VERSION 5.8 ;
BUSBITCHARS "[]" ;
DIVIDERCHAR "/" ;
UNITS
    DATABASE MICRONS 1000 ;
END UNITS

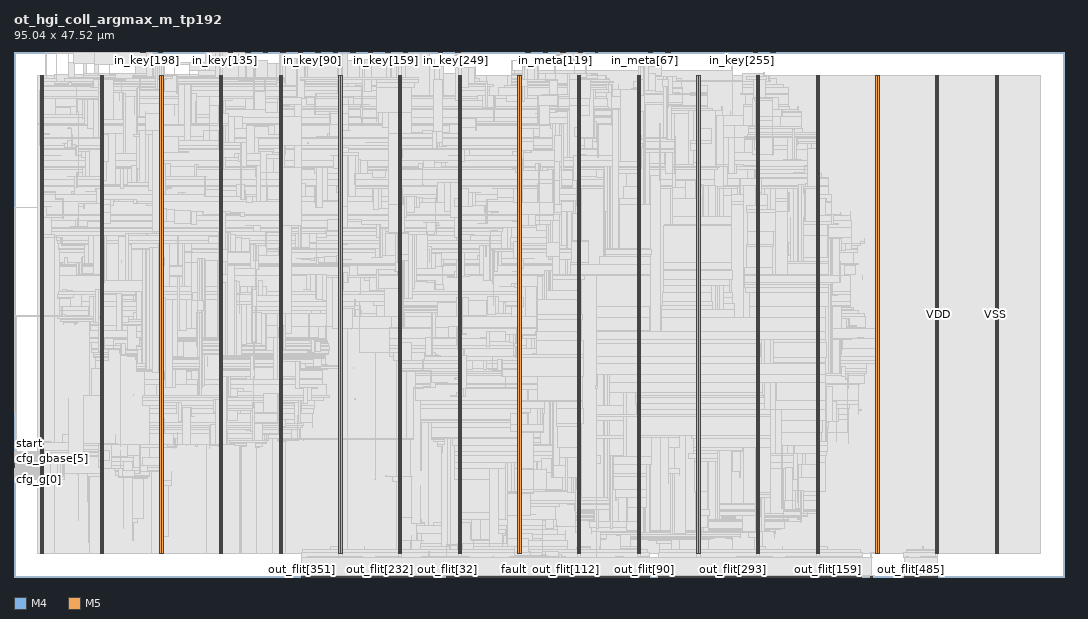
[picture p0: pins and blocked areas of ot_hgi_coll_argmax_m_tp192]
MACRO ot_hgi_coll_argmax_m_tp192
  FOREIGN ot_hgi_coll_argmax_m_tp192 0 0 ;
  CLASS BLOCK ;
  SIZE 95.04 BY 47.52 ;
  PIN cfg_g[0]
    DIRECTION INPUT ;
    USE SIGNAL ;
    PORT
      LAYER M4 ;
        RECT  0 8.784 0.084 8.808 ;
    END
  END cfg_g[0]
  PIN cfg_g[1]
    DIRECTION INPUT ;
    USE SIGNAL ;
    PORT
      LAYER M4 ;
        RECT  0 8.88 0.084 8.904 ;
    END
  END cfg_g[1]
  PIN cfg_g[2]
    DIRECTION INPUT ;
    USE SIGNAL ;
    PORT
      LAYER M4 ;
        RECT  0 8.976 0.084 9 ;
    END
  END cfg_g[2]
  PIN cfg_g[3]
    DIRECTION INPUT ;
    USE SIGNAL ;
    PORT
      LAYER M4 ;
        RECT  0 9.072 0.084 9.096 ;
    END
  END cfg_g[3]
  PIN cfg_g[4]
    DIRECTION INPUT ;
    USE SIGNAL ;
    PORT
      LAYER M4 ;
        RECT  0 9.168 0.084 9.192 ;
    END
  END cfg_g[4]
  PIN cfg_g[5]
    DIRECTION INPUT ;
    USE SIGNAL ;
    PORT
      LAYER M4 ;
        RECT  0 9.264 0.084 9.288 ;
    END
  END cfg_g[5]
  PIN cfg_g[6]
    DIRECTION INPUT ;
    USE SIGNAL ;
    PORT
      LAYER M4 ;
        RECT  0 9.36 0.084 9.384 ;
    END
  END cfg_g[6]
  PIN cfg_g[7]
    DIRECTION INPUT ;
    USE SIGNAL ;
    PORT
      LAYER M4 ;
        RECT  0 9.456 0.084 9.48 ;
    END
  END cfg_g[7]
  PIN cfg_gbase[0]
    DIRECTION INPUT ;
    USE SIGNAL ;
    PORT
      LAYER M4 ;
        RECT  0 9.552 0.084 9.576 ;
    END
  END cfg_gbase[0]
  PIN cfg_gbase[1]
    DIRECTION INPUT ;
    USE SIGNAL ;
    PORT
      LAYER M4 ;
        RECT  0 9.648 0.084 9.672 ;
    END
  END cfg_gbase[1]
  PIN cfg_gbase[2]
    DIRECTION INPUT ;
    USE SIGNAL ;
    PORT
      LAYER M4 ;
        RECT  0 9.744 0.084 9.768 ;
    END
  END cfg_gbase[2]
  PIN cfg_gbase[3]
    DIRECTION INPUT ;
    USE SIGNAL ;
    PORT
      LAYER M4 ;
        RECT  0 9.84 0.084 9.864 ;
    END
  END cfg_gbase[3]
  PIN cfg_gbase[4]
    DIRECTION INPUT ;
    USE SIGNAL ;
    PORT
      LAYER M4 ;
        RECT  0 9.936 0.084 9.96 ;
    END
  END cfg_gbase[4]
  PIN cfg_gbase[5]
    DIRECTION INPUT ;
    USE SIGNAL ;
    PORT
      LAYER M4 ;
        RECT  0 10.032 0.084 10.056 ;
    END
  END cfg_gbase[5]
  PIN cfg_gbase[6]
    DIRECTION INPUT ;
    USE SIGNAL ;
    PORT
      LAYER M4 ;
        RECT  0 10.128 0.084 10.152 ;
    END
  END cfg_gbase[6]
  PIN cfg_gbase[7]
    DIRECTION INPUT ;
    USE SIGNAL ;
    PORT
      LAYER M4 ;
        RECT  0 10.224 0.084 10.248 ;
    END
  END cfg_gbase[7]
  PIN cfg_rank[0]
    DIRECTION INPUT ;
    USE SIGNAL ;
    PORT
      LAYER M4 ;
        RECT  0 10.32 0.084 10.344 ;
    END
  END cfg_rank[0]
  PIN cfg_rank[1]
    DIRECTION INPUT ;
    USE SIGNAL ;
    PORT
      LAYER M4 ;
        RECT  0 10.416 0.084 10.44 ;
    END
  END cfg_rank[1]
  PIN cfg_rank[2]
    DIRECTION INPUT ;
    USE SIGNAL ;
    PORT
      LAYER M4 ;
        RECT  0 10.512 0.084 10.536 ;
    END
  END cfg_rank[2]
  PIN cfg_rank[3]
    DIRECTION INPUT ;
    USE SIGNAL ;
    PORT
      LAYER M4 ;
        RECT  0 10.608 0.084 10.632 ;
    END
  END cfg_rank[3]
  PIN cfg_rank[4]
    DIRECTION INPUT ;
    USE SIGNAL ;
    PORT
      LAYER M4 ;
        RECT  0 10.704 0.084 10.728 ;
    END
  END cfg_rank[4]
  PIN cfg_rank[5]
    DIRECTION INPUT ;
    USE SIGNAL ;
    PORT
      LAYER M4 ;
        RECT  0 10.8 0.084 10.824 ;
    END
  END cfg_rank[5]
  PIN cfg_rank[6]
    DIRECTION INPUT ;
    USE SIGNAL ;
    PORT
      LAYER M4 ;
        RECT  0 10.896 0.084 10.92 ;
    END
  END cfg_rank[6]
  PIN cfg_rank[7]
    DIRECTION INPUT ;
    USE SIGNAL ;
    PORT
      LAYER M4 ;
        RECT  0 10.992 0.084 11.016 ;
    END
  END cfg_rank[7]
  PIN clk
    DIRECTION INPUT ;
    USE SIGNAL ;
    PORT
      LAYER M4 ;
        RECT  0 11.088 0.084 11.112 ;
    END
  END clk
  PIN fault
    DIRECTION OUTPUT ;
    USE SIGNAL ;
    PORT
      LAYER M5 ;
        RECT  45.264 0 45.288 0.084 ;
    END
  END fault
  PIN flush_slot
    DIRECTION INPUT ;
    USE SIGNAL ;
    PORT
      LAYER M5 ;
        RECT  21.36 47.436 21.384 47.52 ;
    END
  END flush_slot
  PIN in_key[0]
    DIRECTION INPUT ;
    USE SIGNAL ;
    PORT
      LAYER M5 ;
        RECT  21.456 47.436 21.48 47.52 ;
    END
  END in_key[0]
  PIN in_key[100]
    DIRECTION INPUT ;
    USE SIGNAL ;
    PORT
      LAYER M5 ;
        RECT  27.984 47.436 28.008 47.52 ;
    END
  END in_key[100]
  PIN in_key[101]
    DIRECTION INPUT ;
    USE SIGNAL ;
    PORT
      LAYER M5 ;
        RECT  28.08 47.436 28.104 47.52 ;
    END
  END in_key[101]
  PIN in_key[102]
    DIRECTION INPUT ;
    USE SIGNAL ;
    PORT
      LAYER M5 ;
        RECT  28.176 47.436 28.2 47.52 ;
    END
  END in_key[102]
  PIN in_key[103]
    DIRECTION INPUT ;
    USE SIGNAL ;
    PORT
      LAYER M5 ;
        RECT  28.272 47.436 28.296 47.52 ;
    END
  END in_key[103]
  PIN in_key[104]
    DIRECTION INPUT ;
    USE SIGNAL ;
    PORT
      LAYER M5 ;
        RECT  28.368 47.436 28.392 47.52 ;
    END
  END in_key[104]
  PIN in_key[105]
    DIRECTION INPUT ;
    USE SIGNAL ;
    PORT
      LAYER M5 ;
        RECT  28.464 47.436 28.488 47.52 ;
    END
  END in_key[105]
  PIN in_key[106]
    DIRECTION INPUT ;
    USE SIGNAL ;
    PORT
      LAYER M5 ;
        RECT  28.56 47.436 28.584 47.52 ;
    END
  END in_key[106]
  PIN in_key[107]
    DIRECTION INPUT ;
    USE SIGNAL ;
    PORT
      LAYER M5 ;
        RECT  28.656 47.436 28.68 47.52 ;
    END
  END in_key[107]
  PIN in_key[108]
    DIRECTION INPUT ;
    USE SIGNAL ;
    PORT
      LAYER M5 ;
        RECT  28.752 47.436 28.776 47.52 ;
    END
  END in_key[108]
  PIN in_key[109]
    DIRECTION INPUT ;
    USE SIGNAL ;
    PORT
      LAYER M5 ;
        RECT  28.848 47.436 28.872 47.52 ;
    END
  END in_key[109]
  PIN in_key[10]
    DIRECTION INPUT ;
    USE SIGNAL ;
    PORT
      LAYER M5 ;
        RECT  22.416 47.436 22.44 47.52 ;
    END
  END in_key[10]
  PIN in_key[110]
    DIRECTION INPUT ;
    USE SIGNAL ;
    PORT
      LAYER M5 ;
        RECT  28.944 47.436 28.968 47.52 ;
    END
  END in_key[110]
  PIN in_key[111]
    DIRECTION INPUT ;
    USE SIGNAL ;
    PORT
      LAYER M5 ;
        RECT  29.04 47.436 29.064 47.52 ;
    END
  END in_key[111]
  PIN in_key[112]
    DIRECTION INPUT ;
    USE SIGNAL ;
    PORT
      LAYER M5 ;
        RECT  29.136 47.436 29.16 47.52 ;
    END
  END in_key[112]
  PIN in_key[113]
    DIRECTION INPUT ;
    USE SIGNAL ;
    PORT
      LAYER M5 ;
        RECT  29.232 47.436 29.256 47.52 ;
    END
  END in_key[113]
  PIN in_key[114]
    DIRECTION INPUT ;
    USE SIGNAL ;
    PORT
      LAYER M5 ;
        RECT  29.328 47.436 29.352 47.52 ;
    END
  END in_key[114]
  PIN in_key[115]
    DIRECTION INPUT ;
    USE SIGNAL ;
    PORT
      LAYER M5 ;
        RECT  29.424 47.436 29.448 47.52 ;
    END
  END in_key[115]
  PIN in_key[116]
    DIRECTION INPUT ;
    USE SIGNAL ;
    PORT
      LAYER M5 ;
        RECT  29.52 47.436 29.544 47.52 ;
    END
  END in_key[116]
  PIN in_key[117]
    DIRECTION INPUT ;
    USE SIGNAL ;
    PORT
      LAYER M5 ;
        RECT  29.616 47.436 29.64 47.52 ;
    END
  END in_key[117]
  PIN in_key[118]
    DIRECTION INPUT ;
    USE SIGNAL ;
    PORT
      LAYER M5 ;
        RECT  29.712 47.436 29.736 47.52 ;
    END
  END in_key[118]
  PIN in_key[119]
    DIRECTION INPUT ;
    USE SIGNAL ;
    PORT
      LAYER M5 ;
        RECT  29.808 47.436 29.832 47.52 ;
    END
  END in_key[119]
  PIN in_key[11]
    DIRECTION INPUT ;
    USE SIGNAL ;
    PORT
      LAYER M5 ;
        RECT  22.512 47.436 22.536 47.52 ;
    END
  END in_key[11]
  PIN in_key[120]
    DIRECTION INPUT ;
    USE SIGNAL ;
    PORT
      LAYER M5 ;
        RECT  29.904 47.436 29.928 47.52 ;
    END
  END in_key[120]
  PIN in_key[121]
    DIRECTION INPUT ;
    USE SIGNAL ;
    PORT
      LAYER M5 ;
        RECT  30 47.436 30.024 47.52 ;
    END
  END in_key[121]
  PIN in_key[122]
    DIRECTION INPUT ;
    USE SIGNAL ;
    PORT
      LAYER M5 ;
        RECT  30.096 47.436 30.12 47.52 ;
    END
  END in_key[122]
  PIN in_key[123]
    DIRECTION INPUT ;
    USE SIGNAL ;
    PORT
      LAYER M5 ;
        RECT  30.192 47.436 30.216 47.52 ;
    END
  END in_key[123]
  PIN in_key[124]
    DIRECTION INPUT ;
    USE SIGNAL ;
    PORT
      LAYER M5 ;
        RECT  30.288 47.436 30.312 47.52 ;
    END
  END in_key[124]
  PIN in_key[125]
    DIRECTION INPUT ;
    USE SIGNAL ;
    PORT
      LAYER M5 ;
        RECT  30.384 47.436 30.408 47.52 ;
    END
  END in_key[125]
  PIN in_key[126]
    DIRECTION INPUT ;
    USE SIGNAL ;
    PORT
      LAYER M5 ;
        RECT  30.48 47.436 30.504 47.52 ;
    END
  END in_key[126]
  PIN in_key[127]
    DIRECTION INPUT ;
    USE SIGNAL ;
    PORT
      LAYER M5 ;
        RECT  18.288 47.436 18.312 47.52 ;
    END
  END in_key[127]
  PIN in_key[128]
    DIRECTION INPUT ;
    USE SIGNAL ;
    PORT
      LAYER M5 ;
        RECT  18.384 47.436 18.408 47.52 ;
    END
  END in_key[128]
  PIN in_key[129]
    DIRECTION INPUT ;
    USE SIGNAL ;
    PORT
      LAYER M5 ;
        RECT  18.48 47.436 18.504 47.52 ;
    END
  END in_key[129]
  PIN in_key[12]
    DIRECTION INPUT ;
    USE SIGNAL ;
    PORT
      LAYER M5 ;
        RECT  22.608 47.436 22.632 47.52 ;
    END
  END in_key[12]
  PIN in_key[130]
    DIRECTION INPUT ;
    USE SIGNAL ;
    PORT
      LAYER M5 ;
        RECT  18.576 47.436 18.6 47.52 ;
    END
  END in_key[130]
  PIN in_key[131]
    DIRECTION INPUT ;
    USE SIGNAL ;
    PORT
      LAYER M5 ;
        RECT  18.672 47.436 18.696 47.52 ;
    END
  END in_key[131]
  PIN in_key[132]
    DIRECTION INPUT ;
    USE SIGNAL ;
    PORT
      LAYER M5 ;
        RECT  18.768 47.436 18.792 47.52 ;
    END
  END in_key[132]
  PIN in_key[133]
    DIRECTION INPUT ;
    USE SIGNAL ;
    PORT
      LAYER M5 ;
        RECT  18.864 47.436 18.888 47.52 ;
    END
  END in_key[133]
  PIN in_key[134]
    DIRECTION INPUT ;
    USE SIGNAL ;
    PORT
      LAYER M5 ;
        RECT  18.96 47.436 18.984 47.52 ;
    END
  END in_key[134]
  PIN in_key[135]
    DIRECTION INPUT ;
    USE SIGNAL ;
    PORT
      LAYER M5 ;
        RECT  19.056 47.436 19.08 47.52 ;
    END
  END in_key[135]
  PIN in_key[136]
    DIRECTION INPUT ;
    USE SIGNAL ;
    PORT
      LAYER M5 ;
        RECT  19.152 47.436 19.176 47.52 ;
    END
  END in_key[136]
  PIN in_key[137]
    DIRECTION INPUT ;
    USE SIGNAL ;
    PORT
      LAYER M5 ;
        RECT  19.248 47.436 19.272 47.52 ;
    END
  END in_key[137]
  PIN in_key[138]
    DIRECTION INPUT ;
    USE SIGNAL ;
    PORT
      LAYER M5 ;
        RECT  19.344 47.436 19.368 47.52 ;
    END
  END in_key[138]
  PIN in_key[139]
    DIRECTION INPUT ;
    USE SIGNAL ;
    PORT
      LAYER M5 ;
        RECT  19.44 47.436 19.464 47.52 ;
    END
  END in_key[139]
  PIN in_key[13]
    DIRECTION INPUT ;
    USE SIGNAL ;
    PORT
      LAYER M5 ;
        RECT  22.704 47.436 22.728 47.52 ;
    END
  END in_key[13]
  PIN in_key[140]
    DIRECTION INPUT ;
    USE SIGNAL ;
    PORT
      LAYER M5 ;
        RECT  19.536 47.436 19.56 47.52 ;
    END
  END in_key[140]
  PIN in_key[141]
    DIRECTION INPUT ;
    USE SIGNAL ;
    PORT
      LAYER M5 ;
        RECT  19.632 47.436 19.656 47.52 ;
    END
  END in_key[141]
  PIN in_key[142]
    DIRECTION INPUT ;
    USE SIGNAL ;
    PORT
      LAYER M5 ;
        RECT  19.728 47.436 19.752 47.52 ;
    END
  END in_key[142]
  PIN in_key[143]
    DIRECTION INPUT ;
    USE SIGNAL ;
    PORT
      LAYER M5 ;
        RECT  19.824 47.436 19.848 47.52 ;
    END
  END in_key[143]
  PIN in_key[144]
    DIRECTION INPUT ;
    USE SIGNAL ;
    PORT
      LAYER M5 ;
        RECT  19.92 47.436 19.944 47.52 ;
    END
  END in_key[144]
  PIN in_key[145]
    DIRECTION INPUT ;
    USE SIGNAL ;
    PORT
      LAYER M5 ;
        RECT  20.016 47.436 20.04 47.52 ;
    END
  END in_key[145]
  PIN in_key[146]
    DIRECTION INPUT ;
    USE SIGNAL ;
    PORT
      LAYER M5 ;
        RECT  20.112 47.436 20.136 47.52 ;
    END
  END in_key[146]
  PIN in_key[147]
    DIRECTION INPUT ;
    USE SIGNAL ;
    PORT
      LAYER M5 ;
        RECT  20.208 47.436 20.232 47.52 ;
    END
  END in_key[147]
  PIN in_key[148]
    DIRECTION INPUT ;
    USE SIGNAL ;
    PORT
      LAYER M5 ;
        RECT  20.304 47.436 20.328 47.52 ;
    END
  END in_key[148]
  PIN in_key[149]
    DIRECTION INPUT ;
    USE SIGNAL ;
    PORT
      LAYER M5 ;
        RECT  20.4 47.436 20.424 47.52 ;
    END
  END in_key[149]
  PIN in_key[14]
    DIRECTION INPUT ;
    USE SIGNAL ;
    PORT
      LAYER M5 ;
        RECT  22.8 47.436 22.824 47.52 ;
    END
  END in_key[14]
  PIN in_key[150]
    DIRECTION INPUT ;
    USE SIGNAL ;
    PORT
      LAYER M5 ;
        RECT  20.496 47.436 20.52 47.52 ;
    END
  END in_key[150]
  PIN in_key[151]
    DIRECTION INPUT ;
    USE SIGNAL ;
    PORT
      LAYER M5 ;
        RECT  20.592 47.436 20.616 47.52 ;
    END
  END in_key[151]
  PIN in_key[152]
    DIRECTION INPUT ;
    USE SIGNAL ;
    PORT
      LAYER M5 ;
        RECT  20.688 47.436 20.712 47.52 ;
    END
  END in_key[152]
  PIN in_key[153]
    DIRECTION INPUT ;
    USE SIGNAL ;
    PORT
      LAYER M5 ;
        RECT  20.784 47.436 20.808 47.52 ;
    END
  END in_key[153]
  PIN in_key[154]
    DIRECTION INPUT ;
    USE SIGNAL ;
    PORT
      LAYER M5 ;
        RECT  20.88 47.436 20.904 47.52 ;
    END
  END in_key[154]
  PIN in_key[155]
    DIRECTION INPUT ;
    USE SIGNAL ;
    PORT
      LAYER M5 ;
        RECT  20.976 47.436 21 47.52 ;
    END
  END in_key[155]
  PIN in_key[156]
    DIRECTION INPUT ;
    USE SIGNAL ;
    PORT
      LAYER M5 ;
        RECT  21.072 47.436 21.096 47.52 ;
    END
  END in_key[156]
  PIN in_key[157]
    DIRECTION INPUT ;
    USE SIGNAL ;
    PORT
      LAYER M5 ;
        RECT  21.168 47.436 21.192 47.52 ;
    END
  END in_key[157]
  PIN in_key[158]
    DIRECTION INPUT ;
    USE SIGNAL ;
    PORT
      LAYER M5 ;
        RECT  21.264 47.436 21.288 47.52 ;
    END
  END in_key[158]
  PIN in_key[159]
    DIRECTION INPUT ;
    USE SIGNAL ;
    PORT
      LAYER M5 ;
        RECT  33.648 47.436 33.672 47.52 ;
    END
  END in_key[159]
  PIN in_key[15]
    DIRECTION INPUT ;
    USE SIGNAL ;
    PORT
      LAYER M5 ;
        RECT  22.896 47.436 22.92 47.52 ;
    END
  END in_key[15]
  PIN in_key[160]
    DIRECTION INPUT ;
    USE SIGNAL ;
    PORT
      LAYER M5 ;
        RECT  33.744 47.436 33.768 47.52 ;
    END
  END in_key[160]
  PIN in_key[161]
    DIRECTION INPUT ;
    USE SIGNAL ;
    PORT
      LAYER M5 ;
        RECT  33.84 47.436 33.864 47.52 ;
    END
  END in_key[161]
  PIN in_key[162]
    DIRECTION INPUT ;
    USE SIGNAL ;
    PORT
      LAYER M5 ;
        RECT  33.936 47.436 33.96 47.52 ;
    END
  END in_key[162]
  PIN in_key[163]
    DIRECTION INPUT ;
    USE SIGNAL ;
    PORT
      LAYER M5 ;
        RECT  34.032 47.436 34.056 47.52 ;
    END
  END in_key[163]
  PIN in_key[164]
    DIRECTION INPUT ;
    USE SIGNAL ;
    PORT
      LAYER M5 ;
        RECT  34.128 47.436 34.152 47.52 ;
    END
  END in_key[164]
  PIN in_key[165]
    DIRECTION INPUT ;
    USE SIGNAL ;
    PORT
      LAYER M5 ;
        RECT  34.224 47.436 34.248 47.52 ;
    END
  END in_key[165]
  PIN in_key[166]
    DIRECTION INPUT ;
    USE SIGNAL ;
    PORT
      LAYER M5 ;
        RECT  34.32 47.436 34.344 47.52 ;
    END
  END in_key[166]
  PIN in_key[167]
    DIRECTION INPUT ;
    USE SIGNAL ;
    PORT
      LAYER M5 ;
        RECT  34.416 47.436 34.44 47.52 ;
    END
  END in_key[167]
  PIN in_key[168]
    DIRECTION INPUT ;
    USE SIGNAL ;
    PORT
      LAYER M5 ;
        RECT  34.512 47.436 34.536 47.52 ;
    END
  END in_key[168]
  PIN in_key[169]
    DIRECTION INPUT ;
    USE SIGNAL ;
    PORT
      LAYER M5 ;
        RECT  34.608 47.436 34.632 47.52 ;
    END
  END in_key[169]
  PIN in_key[16]
    DIRECTION INPUT ;
    USE SIGNAL ;
    PORT
      LAYER M5 ;
        RECT  22.992 47.436 23.016 47.52 ;
    END
  END in_key[16]
  PIN in_key[170]
    DIRECTION INPUT ;
    USE SIGNAL ;
    PORT
      LAYER M5 ;
        RECT  34.704 47.436 34.728 47.52 ;
    END
  END in_key[170]
  PIN in_key[171]
    DIRECTION INPUT ;
    USE SIGNAL ;
    PORT
      LAYER M5 ;
        RECT  34.8 47.436 34.824 47.52 ;
    END
  END in_key[171]
  PIN in_key[172]
    DIRECTION INPUT ;
    USE SIGNAL ;
    PORT
      LAYER M5 ;
        RECT  34.896 47.436 34.92 47.52 ;
    END
  END in_key[172]
  PIN in_key[173]
    DIRECTION INPUT ;
    USE SIGNAL ;
    PORT
      LAYER M5 ;
        RECT  34.992 47.436 35.016 47.52 ;
    END
  END in_key[173]
  PIN in_key[174]
    DIRECTION INPUT ;
    USE SIGNAL ;
    PORT
      LAYER M5 ;
        RECT  35.088 47.436 35.112 47.52 ;
    END
  END in_key[174]
  PIN in_key[175]
    DIRECTION INPUT ;
    USE SIGNAL ;
    PORT
      LAYER M5 ;
        RECT  35.184 47.436 35.208 47.52 ;
    END
  END in_key[175]
  PIN in_key[176]
    DIRECTION INPUT ;
    USE SIGNAL ;
    PORT
      LAYER M5 ;
        RECT  35.28 47.436 35.304 47.52 ;
    END
  END in_key[176]
  PIN in_key[177]
    DIRECTION INPUT ;
    USE SIGNAL ;
    PORT
      LAYER M5 ;
        RECT  35.376 47.436 35.4 47.52 ;
    END
  END in_key[177]
  PIN in_key[178]
    DIRECTION INPUT ;
    USE SIGNAL ;
    PORT
      LAYER M5 ;
        RECT  35.472 47.436 35.496 47.52 ;
    END
  END in_key[178]
  PIN in_key[179]
    DIRECTION INPUT ;
    USE SIGNAL ;
    PORT
      LAYER M5 ;
        RECT  35.568 47.436 35.592 47.52 ;
    END
  END in_key[179]
  PIN in_key[17]
    DIRECTION INPUT ;
    USE SIGNAL ;
    PORT
      LAYER M5 ;
        RECT  23.088 47.436 23.112 47.52 ;
    END
  END in_key[17]
  PIN in_key[180]
    DIRECTION INPUT ;
    USE SIGNAL ;
    PORT
      LAYER M5 ;
        RECT  35.664 47.436 35.688 47.52 ;
    END
  END in_key[180]
  PIN in_key[181]
    DIRECTION INPUT ;
    USE SIGNAL ;
    PORT
      LAYER M5 ;
        RECT  35.76 47.436 35.784 47.52 ;
    END
  END in_key[181]
  PIN in_key[182]
    DIRECTION INPUT ;
    USE SIGNAL ;
    PORT
      LAYER M5 ;
        RECT  35.856 47.436 35.88 47.52 ;
    END
  END in_key[182]
  PIN in_key[183]
    DIRECTION INPUT ;
    USE SIGNAL ;
    PORT
      LAYER M5 ;
        RECT  35.952 47.436 35.976 47.52 ;
    END
  END in_key[183]
  PIN in_key[184]
    DIRECTION INPUT ;
    USE SIGNAL ;
    PORT
      LAYER M5 ;
        RECT  36.048 47.436 36.072 47.52 ;
    END
  END in_key[184]
  PIN in_key[185]
    DIRECTION INPUT ;
    USE SIGNAL ;
    PORT
      LAYER M5 ;
        RECT  36.144 47.436 36.168 47.52 ;
    END
  END in_key[185]
  PIN in_key[186]
    DIRECTION INPUT ;
    USE SIGNAL ;
    PORT
      LAYER M5 ;
        RECT  36.24 47.436 36.264 47.52 ;
    END
  END in_key[186]
  PIN in_key[187]
    DIRECTION INPUT ;
    USE SIGNAL ;
    PORT
      LAYER M5 ;
        RECT  36.336 47.436 36.36 47.52 ;
    END
  END in_key[187]
  PIN in_key[188]
    DIRECTION INPUT ;
    USE SIGNAL ;
    PORT
      LAYER M5 ;
        RECT  36.432 47.436 36.456 47.52 ;
    END
  END in_key[188]
  PIN in_key[189]
    DIRECTION INPUT ;
    USE SIGNAL ;
    PORT
      LAYER M5 ;
        RECT  36.528 47.436 36.552 47.52 ;
    END
  END in_key[189]
  PIN in_key[18]
    DIRECTION INPUT ;
    USE SIGNAL ;
    PORT
      LAYER M5 ;
        RECT  23.184 47.436 23.208 47.52 ;
    END
  END in_key[18]
  PIN in_key[190]
    DIRECTION INPUT ;
    USE SIGNAL ;
    PORT
      LAYER M5 ;
        RECT  36.624 47.436 36.648 47.52 ;
    END
  END in_key[190]
  PIN in_key[191]
    DIRECTION INPUT ;
    USE SIGNAL ;
    PORT
      LAYER M5 ;
        RECT  11.376 47.436 11.4 47.52 ;
    END
  END in_key[191]
  PIN in_key[192]
    DIRECTION INPUT ;
    USE SIGNAL ;
    PORT
      LAYER M5 ;
        RECT  11.472 47.436 11.496 47.52 ;
    END
  END in_key[192]
  PIN in_key[193]
    DIRECTION INPUT ;
    USE SIGNAL ;
    PORT
      LAYER M5 ;
        RECT  11.568 47.436 11.592 47.52 ;
    END
  END in_key[193]
  PIN in_key[194]
    DIRECTION INPUT ;
    USE SIGNAL ;
    PORT
      LAYER M5 ;
        RECT  11.664 47.436 11.688 47.52 ;
    END
  END in_key[194]
  PIN in_key[195]
    DIRECTION INPUT ;
    USE SIGNAL ;
    PORT
      LAYER M5 ;
        RECT  11.76 47.436 11.784 47.52 ;
    END
  END in_key[195]
  PIN in_key[196]
    DIRECTION INPUT ;
    USE SIGNAL ;
    PORT
      LAYER M5 ;
        RECT  11.856 47.436 11.88 47.52 ;
    END
  END in_key[196]
  PIN in_key[197]
    DIRECTION INPUT ;
    USE SIGNAL ;
    PORT
      LAYER M5 ;
        RECT  11.952 47.436 11.976 47.52 ;
    END
  END in_key[197]
  PIN in_key[198]
    DIRECTION INPUT ;
    USE SIGNAL ;
    PORT
      LAYER M5 ;
        RECT  12.048 47.436 12.072 47.52 ;
    END
  END in_key[198]
  PIN in_key[199]
    DIRECTION INPUT ;
    USE SIGNAL ;
    PORT
      LAYER M5 ;
        RECT  12.144 47.436 12.168 47.52 ;
    END
  END in_key[199]
  PIN in_key[19]
    DIRECTION INPUT ;
    USE SIGNAL ;
    PORT
      LAYER M5 ;
        RECT  23.28 47.436 23.304 47.52 ;
    END
  END in_key[19]
  PIN in_key[1]
    DIRECTION INPUT ;
    USE SIGNAL ;
    PORT
      LAYER M5 ;
        RECT  21.552 47.436 21.576 47.52 ;
    END
  END in_key[1]
  PIN in_key[200]
    DIRECTION INPUT ;
    USE SIGNAL ;
    PORT
      LAYER M5 ;
        RECT  12.24 47.436 12.264 47.52 ;
    END
  END in_key[200]
  PIN in_key[201]
    DIRECTION INPUT ;
    USE SIGNAL ;
    PORT
      LAYER M5 ;
        RECT  12.336 47.436 12.36 47.52 ;
    END
  END in_key[201]
  PIN in_key[202]
    DIRECTION INPUT ;
    USE SIGNAL ;
    PORT
      LAYER M5 ;
        RECT  12.432 47.436 12.456 47.52 ;
    END
  END in_key[202]
  PIN in_key[203]
    DIRECTION INPUT ;
    USE SIGNAL ;
    PORT
      LAYER M5 ;
        RECT  12.528 47.436 12.552 47.52 ;
    END
  END in_key[203]
  PIN in_key[204]
    DIRECTION INPUT ;
    USE SIGNAL ;
    PORT
      LAYER M5 ;
        RECT  12.624 47.436 12.648 47.52 ;
    END
  END in_key[204]
  PIN in_key[205]
    DIRECTION INPUT ;
    USE SIGNAL ;
    PORT
      LAYER M5 ;
        RECT  12.72 47.436 12.744 47.52 ;
    END
  END in_key[205]
  PIN in_key[206]
    DIRECTION INPUT ;
    USE SIGNAL ;
    PORT
      LAYER M5 ;
        RECT  12.816 47.436 12.84 47.52 ;
    END
  END in_key[206]
  PIN in_key[207]
    DIRECTION INPUT ;
    USE SIGNAL ;
    PORT
      LAYER M5 ;
        RECT  12.912 47.436 12.936 47.52 ;
    END
  END in_key[207]
  PIN in_key[208]
    DIRECTION INPUT ;
    USE SIGNAL ;
    PORT
      LAYER M5 ;
        RECT  13.008 47.436 13.032 47.52 ;
    END
  END in_key[208]
  PIN in_key[209]
    DIRECTION INPUT ;
    USE SIGNAL ;
    PORT
      LAYER M5 ;
        RECT  13.104 47.436 13.128 47.52 ;
    END
  END in_key[209]
  PIN in_key[20]
    DIRECTION INPUT ;
    USE SIGNAL ;
    PORT
      LAYER M5 ;
        RECT  23.376 47.436 23.4 47.52 ;
    END
  END in_key[20]
  PIN in_key[210]
    DIRECTION INPUT ;
    USE SIGNAL ;
    PORT
      LAYER M5 ;
        RECT  13.2 47.436 13.224 47.52 ;
    END
  END in_key[210]
  PIN in_key[211]
    DIRECTION INPUT ;
    USE SIGNAL ;
    PORT
      LAYER M5 ;
        RECT  13.296 47.436 13.32 47.52 ;
    END
  END in_key[211]
  PIN in_key[212]
    DIRECTION INPUT ;
    USE SIGNAL ;
    PORT
      LAYER M5 ;
        RECT  13.392 47.436 13.416 47.52 ;
    END
  END in_key[212]
  PIN in_key[213]
    DIRECTION INPUT ;
    USE SIGNAL ;
    PORT
      LAYER M5 ;
        RECT  13.488 47.436 13.512 47.52 ;
    END
  END in_key[213]
  PIN in_key[214]
    DIRECTION INPUT ;
    USE SIGNAL ;
    PORT
      LAYER M5 ;
        RECT  13.584 47.436 13.608 47.52 ;
    END
  END in_key[214]
  PIN in_key[215]
    DIRECTION INPUT ;
    USE SIGNAL ;
    PORT
      LAYER M5 ;
        RECT  13.68 47.436 13.704 47.52 ;
    END
  END in_key[215]
  PIN in_key[216]
    DIRECTION INPUT ;
    USE SIGNAL ;
    PORT
      LAYER M5 ;
        RECT  13.776 47.436 13.8 47.52 ;
    END
  END in_key[216]
  PIN in_key[217]
    DIRECTION INPUT ;
    USE SIGNAL ;
    PORT
      LAYER M5 ;
        RECT  13.872 47.436 13.896 47.52 ;
    END
  END in_key[217]
  PIN in_key[218]
    DIRECTION INPUT ;
    USE SIGNAL ;
    PORT
      LAYER M5 ;
        RECT  13.968 47.436 13.992 47.52 ;
    END
  END in_key[218]
  PIN in_key[219]
    DIRECTION INPUT ;
    USE SIGNAL ;
    PORT
      LAYER M5 ;
        RECT  14.064 47.436 14.088 47.52 ;
    END
  END in_key[219]
  PIN in_key[21]
    DIRECTION INPUT ;
    USE SIGNAL ;
    PORT
      LAYER M5 ;
        RECT  23.472 47.436 23.496 47.52 ;
    END
  END in_key[21]
  PIN in_key[220]
    DIRECTION INPUT ;
    USE SIGNAL ;
    PORT
      LAYER M5 ;
        RECT  14.16 47.436 14.184 47.52 ;
    END
  END in_key[220]
  PIN in_key[221]
    DIRECTION INPUT ;
    USE SIGNAL ;
    PORT
      LAYER M5 ;
        RECT  14.256 47.436 14.28 47.52 ;
    END
  END in_key[221]
  PIN in_key[222]
    DIRECTION INPUT ;
    USE SIGNAL ;
    PORT
      LAYER M5 ;
        RECT  14.352 47.436 14.376 47.52 ;
    END
  END in_key[222]
  PIN in_key[223]
    DIRECTION INPUT ;
    USE SIGNAL ;
    PORT
      LAYER M5 ;
        RECT  37.488 47.436 37.512 47.52 ;
    END
  END in_key[223]
  PIN in_key[224]
    DIRECTION INPUT ;
    USE SIGNAL ;
    PORT
      LAYER M5 ;
        RECT  37.584 47.436 37.608 47.52 ;
    END
  END in_key[224]
  PIN in_key[225]
    DIRECTION INPUT ;
    USE SIGNAL ;
    PORT
      LAYER M5 ;
        RECT  37.68 47.436 37.704 47.52 ;
    END
  END in_key[225]
  PIN in_key[226]
    DIRECTION INPUT ;
    USE SIGNAL ;
    PORT
      LAYER M5 ;
        RECT  37.776 47.436 37.8 47.52 ;
    END
  END in_key[226]
  PIN in_key[227]
    DIRECTION INPUT ;
    USE SIGNAL ;
    PORT
      LAYER M5 ;
        RECT  37.872 47.436 37.896 47.52 ;
    END
  END in_key[227]
  PIN in_key[228]
    DIRECTION INPUT ;
    USE SIGNAL ;
    PORT
      LAYER M5 ;
        RECT  37.968 47.436 37.992 47.52 ;
    END
  END in_key[228]
  PIN in_key[229]
    DIRECTION INPUT ;
    USE SIGNAL ;
    PORT
      LAYER M5 ;
        RECT  38.064 47.436 38.088 47.52 ;
    END
  END in_key[229]
  PIN in_key[22]
    DIRECTION INPUT ;
    USE SIGNAL ;
    PORT
      LAYER M5 ;
        RECT  23.568 47.436 23.592 47.52 ;
    END
  END in_key[22]
  PIN in_key[230]
    DIRECTION INPUT ;
    USE SIGNAL ;
    PORT
      LAYER M5 ;
        RECT  38.16 47.436 38.184 47.52 ;
    END
  END in_key[230]
  PIN in_key[231]
    DIRECTION INPUT ;
    USE SIGNAL ;
    PORT
      LAYER M5 ;
        RECT  38.256 47.436 38.28 47.52 ;
    END
  END in_key[231]
  PIN in_key[232]
    DIRECTION INPUT ;
    USE SIGNAL ;
    PORT
      LAYER M5 ;
        RECT  38.352 47.436 38.376 47.52 ;
    END
  END in_key[232]
  PIN in_key[233]
    DIRECTION INPUT ;
    USE SIGNAL ;
    PORT
      LAYER M5 ;
        RECT  38.448 47.436 38.472 47.52 ;
    END
  END in_key[233]
  PIN in_key[234]
    DIRECTION INPUT ;
    USE SIGNAL ;
    PORT
      LAYER M5 ;
        RECT  38.544 47.436 38.568 47.52 ;
    END
  END in_key[234]
  PIN in_key[235]
    DIRECTION INPUT ;
    USE SIGNAL ;
    PORT
      LAYER M5 ;
        RECT  38.64 47.436 38.664 47.52 ;
    END
  END in_key[235]
  PIN in_key[236]
    DIRECTION INPUT ;
    USE SIGNAL ;
    PORT
      LAYER M5 ;
        RECT  38.736 47.436 38.76 47.52 ;
    END
  END in_key[236]
  PIN in_key[237]
    DIRECTION INPUT ;
    USE SIGNAL ;
    PORT
      LAYER M5 ;
        RECT  38.832 47.436 38.856 47.52 ;
    END
  END in_key[237]
  PIN in_key[238]
    DIRECTION INPUT ;
    USE SIGNAL ;
    PORT
      LAYER M5 ;
        RECT  38.928 47.436 38.952 47.52 ;
    END
  END in_key[238]
  PIN in_key[239]
    DIRECTION INPUT ;
    USE SIGNAL ;
    PORT
      LAYER M5 ;
        RECT  39.024 47.436 39.048 47.52 ;
    END
  END in_key[239]
  PIN in_key[23]
    DIRECTION INPUT ;
    USE SIGNAL ;
    PORT
      LAYER M5 ;
        RECT  23.664 47.436 23.688 47.52 ;
    END
  END in_key[23]
  PIN in_key[240]
    DIRECTION INPUT ;
    USE SIGNAL ;
    PORT
      LAYER M5 ;
        RECT  39.12 47.436 39.144 47.52 ;
    END
  END in_key[240]
  PIN in_key[241]
    DIRECTION INPUT ;
    USE SIGNAL ;
    PORT
      LAYER M5 ;
        RECT  39.216 47.436 39.24 47.52 ;
    END
  END in_key[241]
  PIN in_key[242]
    DIRECTION INPUT ;
    USE SIGNAL ;
    PORT
      LAYER M5 ;
        RECT  39.312 47.436 39.336 47.52 ;
    END
  END in_key[242]
  PIN in_key[243]
    DIRECTION INPUT ;
    USE SIGNAL ;
    PORT
      LAYER M5 ;
        RECT  39.408 47.436 39.432 47.52 ;
    END
  END in_key[243]
  PIN in_key[244]
    DIRECTION INPUT ;
    USE SIGNAL ;
    PORT
      LAYER M5 ;
        RECT  39.504 47.436 39.528 47.52 ;
    END
  END in_key[244]
  PIN in_key[245]
    DIRECTION INPUT ;
    USE SIGNAL ;
    PORT
      LAYER M5 ;
        RECT  39.6 47.436 39.624 47.52 ;
    END
  END in_key[245]
  PIN in_key[246]
    DIRECTION INPUT ;
    USE SIGNAL ;
    PORT
      LAYER M5 ;
        RECT  39.696 47.436 39.72 47.52 ;
    END
  END in_key[246]
  PIN in_key[247]
    DIRECTION INPUT ;
    USE SIGNAL ;
    PORT
      LAYER M5 ;
        RECT  39.792 47.436 39.816 47.52 ;
    END
  END in_key[247]
  PIN in_key[248]
    DIRECTION INPUT ;
    USE SIGNAL ;
    PORT
      LAYER M5 ;
        RECT  39.888 47.436 39.912 47.52 ;
    END
  END in_key[248]
  PIN in_key[249]
    DIRECTION INPUT ;
    USE SIGNAL ;
    PORT
      LAYER M5 ;
        RECT  39.984 47.436 40.008 47.52 ;
    END
  END in_key[249]
  PIN in_key[24]
    DIRECTION INPUT ;
    USE SIGNAL ;
    PORT
      LAYER M5 ;
        RECT  23.76 47.436 23.784 47.52 ;
    END
  END in_key[24]
  PIN in_key[250]
    DIRECTION INPUT ;
    USE SIGNAL ;
    PORT
      LAYER M5 ;
        RECT  40.08 47.436 40.104 47.52 ;
    END
  END in_key[250]
  PIN in_key[251]
    DIRECTION INPUT ;
    USE SIGNAL ;
    PORT
      LAYER M5 ;
        RECT  40.176 47.436 40.2 47.52 ;
    END
  END in_key[251]
  PIN in_key[252]
    DIRECTION INPUT ;
    USE SIGNAL ;
    PORT
      LAYER M5 ;
        RECT  40.272 47.436 40.296 47.52 ;
    END
  END in_key[252]
  PIN in_key[253]
    DIRECTION INPUT ;
    USE SIGNAL ;
    PORT
      LAYER M5 ;
        RECT  40.368 47.436 40.392 47.52 ;
    END
  END in_key[253]
  PIN in_key[254]
    DIRECTION INPUT ;
    USE SIGNAL ;
    PORT
      LAYER M5 ;
        RECT  40.464 47.436 40.488 47.52 ;
    END
  END in_key[254]
  PIN in_key[255]
    DIRECTION INPUT ;
    USE SIGNAL ;
    PORT
      LAYER M5 ;
        RECT  65.904 47.436 65.928 47.52 ;
    END
  END in_key[255]
  PIN in_key[25]
    DIRECTION INPUT ;
    USE SIGNAL ;
    PORT
      LAYER M5 ;
        RECT  23.856 47.436 23.88 47.52 ;
    END
  END in_key[25]
  PIN in_key[26]
    DIRECTION INPUT ;
    USE SIGNAL ;
    PORT
      LAYER M5 ;
        RECT  23.952 47.436 23.976 47.52 ;
    END
  END in_key[26]
  PIN in_key[27]
    DIRECTION INPUT ;
    USE SIGNAL ;
    PORT
      LAYER M5 ;
        RECT  24.048 47.436 24.072 47.52 ;
    END
  END in_key[27]
  PIN in_key[28]
    DIRECTION INPUT ;
    USE SIGNAL ;
    PORT
      LAYER M5 ;
        RECT  24.144 47.436 24.168 47.52 ;
    END
  END in_key[28]
  PIN in_key[29]
    DIRECTION INPUT ;
    USE SIGNAL ;
    PORT
      LAYER M5 ;
        RECT  24.24 47.436 24.264 47.52 ;
    END
  END in_key[29]
  PIN in_key[2]
    DIRECTION INPUT ;
    USE SIGNAL ;
    PORT
      LAYER M5 ;
        RECT  21.648 47.436 21.672 47.52 ;
    END
  END in_key[2]
  PIN in_key[30]
    DIRECTION INPUT ;
    USE SIGNAL ;
    PORT
      LAYER M5 ;
        RECT  24.336 47.436 24.36 47.52 ;
    END
  END in_key[30]
  PIN in_key[31]
    DIRECTION INPUT ;
    USE SIGNAL ;
    PORT
      LAYER M5 ;
        RECT  30.576 47.436 30.6 47.52 ;
    END
  END in_key[31]
  PIN in_key[32]
    DIRECTION INPUT ;
    USE SIGNAL ;
    PORT
      LAYER M5 ;
        RECT  30.672 47.436 30.696 47.52 ;
    END
  END in_key[32]
  PIN in_key[33]
    DIRECTION INPUT ;
    USE SIGNAL ;
    PORT
      LAYER M5 ;
        RECT  30.768 47.436 30.792 47.52 ;
    END
  END in_key[33]
  PIN in_key[34]
    DIRECTION INPUT ;
    USE SIGNAL ;
    PORT
      LAYER M5 ;
        RECT  30.864 47.436 30.888 47.52 ;
    END
  END in_key[34]
  PIN in_key[35]
    DIRECTION INPUT ;
    USE SIGNAL ;
    PORT
      LAYER M5 ;
        RECT  30.96 47.436 30.984 47.52 ;
    END
  END in_key[35]
  PIN in_key[36]
    DIRECTION INPUT ;
    USE SIGNAL ;
    PORT
      LAYER M5 ;
        RECT  31.056 47.436 31.08 47.52 ;
    END
  END in_key[36]
  PIN in_key[37]
    DIRECTION INPUT ;
    USE SIGNAL ;
    PORT
      LAYER M5 ;
        RECT  31.152 47.436 31.176 47.52 ;
    END
  END in_key[37]
  PIN in_key[38]
    DIRECTION INPUT ;
    USE SIGNAL ;
    PORT
      LAYER M5 ;
        RECT  31.248 47.436 31.272 47.52 ;
    END
  END in_key[38]
  PIN in_key[39]
    DIRECTION INPUT ;
    USE SIGNAL ;
    PORT
      LAYER M5 ;
        RECT  31.344 47.436 31.368 47.52 ;
    END
  END in_key[39]
  PIN in_key[3]
    DIRECTION INPUT ;
    USE SIGNAL ;
    PORT
      LAYER M5 ;
        RECT  21.744 47.436 21.768 47.52 ;
    END
  END in_key[3]
  PIN in_key[40]
    DIRECTION INPUT ;
    USE SIGNAL ;
    PORT
      LAYER M5 ;
        RECT  31.44 47.436 31.464 47.52 ;
    END
  END in_key[40]
  PIN in_key[41]
    DIRECTION INPUT ;
    USE SIGNAL ;
    PORT
      LAYER M5 ;
        RECT  31.536 47.436 31.56 47.52 ;
    END
  END in_key[41]
  PIN in_key[42]
    DIRECTION INPUT ;
    USE SIGNAL ;
    PORT
      LAYER M5 ;
        RECT  31.632 47.436 31.656 47.52 ;
    END
  END in_key[42]
  PIN in_key[43]
    DIRECTION INPUT ;
    USE SIGNAL ;
    PORT
      LAYER M5 ;
        RECT  31.728 47.436 31.752 47.52 ;
    END
  END in_key[43]
  PIN in_key[44]
    DIRECTION INPUT ;
    USE SIGNAL ;
    PORT
      LAYER M5 ;
        RECT  31.824 47.436 31.848 47.52 ;
    END
  END in_key[44]
  PIN in_key[45]
    DIRECTION INPUT ;
    USE SIGNAL ;
    PORT
      LAYER M5 ;
        RECT  31.92 47.436 31.944 47.52 ;
    END
  END in_key[45]
  PIN in_key[46]
    DIRECTION INPUT ;
    USE SIGNAL ;
    PORT
      LAYER M5 ;
        RECT  32.016 47.436 32.04 47.52 ;
    END
  END in_key[46]
  PIN in_key[47]
    DIRECTION INPUT ;
    USE SIGNAL ;
    PORT
      LAYER M5 ;
        RECT  32.112 47.436 32.136 47.52 ;
    END
  END in_key[47]
  PIN in_key[48]
    DIRECTION INPUT ;
    USE SIGNAL ;
    PORT
      LAYER M5 ;
        RECT  32.208 47.436 32.232 47.52 ;
    END
  END in_key[48]
  PIN in_key[49]
    DIRECTION INPUT ;
    USE SIGNAL ;
    PORT
      LAYER M5 ;
        RECT  32.304 47.436 32.328 47.52 ;
    END
  END in_key[49]
  PIN in_key[4]
    DIRECTION INPUT ;
    USE SIGNAL ;
    PORT
      LAYER M5 ;
        RECT  21.84 47.436 21.864 47.52 ;
    END
  END in_key[4]
  PIN in_key[50]
    DIRECTION INPUT ;
    USE SIGNAL ;
    PORT
      LAYER M5 ;
        RECT  32.4 47.436 32.424 47.52 ;
    END
  END in_key[50]
  PIN in_key[51]
    DIRECTION INPUT ;
    USE SIGNAL ;
    PORT
      LAYER M5 ;
        RECT  32.496 47.436 32.52 47.52 ;
    END
  END in_key[51]
  PIN in_key[52]
    DIRECTION INPUT ;
    USE SIGNAL ;
    PORT
      LAYER M5 ;
        RECT  32.592 47.436 32.616 47.52 ;
    END
  END in_key[52]
  PIN in_key[53]
    DIRECTION INPUT ;
    USE SIGNAL ;
    PORT
      LAYER M5 ;
        RECT  32.688 47.436 32.712 47.52 ;
    END
  END in_key[53]
  PIN in_key[54]
    DIRECTION INPUT ;
    USE SIGNAL ;
    PORT
      LAYER M5 ;
        RECT  32.784 47.436 32.808 47.52 ;
    END
  END in_key[54]
  PIN in_key[55]
    DIRECTION INPUT ;
    USE SIGNAL ;
    PORT
      LAYER M5 ;
        RECT  32.88 47.436 32.904 47.52 ;
    END
  END in_key[55]
  PIN in_key[56]
    DIRECTION INPUT ;
    USE SIGNAL ;
    PORT
      LAYER M5 ;
        RECT  32.976 47.436 33 47.52 ;
    END
  END in_key[56]
  PIN in_key[57]
    DIRECTION INPUT ;
    USE SIGNAL ;
    PORT
      LAYER M5 ;
        RECT  33.072 47.436 33.096 47.52 ;
    END
  END in_key[57]
  PIN in_key[58]
    DIRECTION INPUT ;
    USE SIGNAL ;
    PORT
      LAYER M5 ;
        RECT  33.168 47.436 33.192 47.52 ;
    END
  END in_key[58]
  PIN in_key[59]
    DIRECTION INPUT ;
    USE SIGNAL ;
    PORT
      LAYER M5 ;
        RECT  33.264 47.436 33.288 47.52 ;
    END
  END in_key[59]
  PIN in_key[5]
    DIRECTION INPUT ;
    USE SIGNAL ;
    PORT
      LAYER M5 ;
        RECT  21.936 47.436 21.96 47.52 ;
    END
  END in_key[5]
  PIN in_key[60]
    DIRECTION INPUT ;
    USE SIGNAL ;
    PORT
      LAYER M5 ;
        RECT  33.36 47.436 33.384 47.52 ;
    END
  END in_key[60]
  PIN in_key[61]
    DIRECTION INPUT ;
    USE SIGNAL ;
    PORT
      LAYER M5 ;
        RECT  33.456 47.436 33.48 47.52 ;
    END
  END in_key[61]
  PIN in_key[62]
    DIRECTION INPUT ;
    USE SIGNAL ;
    PORT
      LAYER M5 ;
        RECT  33.552 47.436 33.576 47.52 ;
    END
  END in_key[62]
  PIN in_key[63]
    DIRECTION INPUT ;
    USE SIGNAL ;
    PORT
      LAYER M5 ;
        RECT  24.432 47.436 24.456 47.52 ;
    END
  END in_key[63]
  PIN in_key[64]
    DIRECTION INPUT ;
    USE SIGNAL ;
    PORT
      LAYER M5 ;
        RECT  24.528 47.436 24.552 47.52 ;
    END
  END in_key[64]
  PIN in_key[65]
    DIRECTION INPUT ;
    USE SIGNAL ;
    PORT
      LAYER M5 ;
        RECT  24.624 47.436 24.648 47.52 ;
    END
  END in_key[65]
  PIN in_key[66]
    DIRECTION INPUT ;
    USE SIGNAL ;
    PORT
      LAYER M5 ;
        RECT  24.72 47.436 24.744 47.52 ;
    END
  END in_key[66]
  PIN in_key[67]
    DIRECTION INPUT ;
    USE SIGNAL ;
    PORT
      LAYER M5 ;
        RECT  24.816 47.436 24.84 47.52 ;
    END
  END in_key[67]
  PIN in_key[68]
    DIRECTION INPUT ;
    USE SIGNAL ;
    PORT
      LAYER M5 ;
        RECT  24.912 47.436 24.936 47.52 ;
    END
  END in_key[68]
  PIN in_key[69]
    DIRECTION INPUT ;
    USE SIGNAL ;
    PORT
      LAYER M5 ;
        RECT  25.008 47.436 25.032 47.52 ;
    END
  END in_key[69]
  PIN in_key[6]
    DIRECTION INPUT ;
    USE SIGNAL ;
    PORT
      LAYER M5 ;
        RECT  22.032 47.436 22.056 47.52 ;
    END
  END in_key[6]
  PIN in_key[70]
    DIRECTION INPUT ;
    USE SIGNAL ;
    PORT
      LAYER M5 ;
        RECT  25.104 47.436 25.128 47.52 ;
    END
  END in_key[70]
  PIN in_key[71]
    DIRECTION INPUT ;
    USE SIGNAL ;
    PORT
      LAYER M5 ;
        RECT  25.2 47.436 25.224 47.52 ;
    END
  END in_key[71]
  PIN in_key[72]
    DIRECTION INPUT ;
    USE SIGNAL ;
    PORT
      LAYER M5 ;
        RECT  25.296 47.436 25.32 47.52 ;
    END
  END in_key[72]
  PIN in_key[73]
    DIRECTION INPUT ;
    USE SIGNAL ;
    PORT
      LAYER M5 ;
        RECT  25.392 47.436 25.416 47.52 ;
    END
  END in_key[73]
  PIN in_key[74]
    DIRECTION INPUT ;
    USE SIGNAL ;
    PORT
      LAYER M5 ;
        RECT  25.488 47.436 25.512 47.52 ;
    END
  END in_key[74]
  PIN in_key[75]
    DIRECTION INPUT ;
    USE SIGNAL ;
    PORT
      LAYER M5 ;
        RECT  25.584 47.436 25.608 47.52 ;
    END
  END in_key[75]
  PIN in_key[76]
    DIRECTION INPUT ;
    USE SIGNAL ;
    PORT
      LAYER M5 ;
        RECT  25.68 47.436 25.704 47.52 ;
    END
  END in_key[76]
  PIN in_key[77]
    DIRECTION INPUT ;
    USE SIGNAL ;
    PORT
      LAYER M5 ;
        RECT  25.776 47.436 25.8 47.52 ;
    END
  END in_key[77]
  PIN in_key[78]
    DIRECTION INPUT ;
    USE SIGNAL ;
    PORT
      LAYER M5 ;
        RECT  25.872 47.436 25.896 47.52 ;
    END
  END in_key[78]
  PIN in_key[79]
    DIRECTION INPUT ;
    USE SIGNAL ;
    PORT
      LAYER M5 ;
        RECT  25.968 47.436 25.992 47.52 ;
    END
  END in_key[79]
  PIN in_key[7]
    DIRECTION INPUT ;
    USE SIGNAL ;
    PORT
      LAYER M5 ;
        RECT  22.128 47.436 22.152 47.52 ;
    END
  END in_key[7]
  PIN in_key[80]
    DIRECTION INPUT ;
    USE SIGNAL ;
    PORT
      LAYER M5 ;
        RECT  26.064 47.436 26.088 47.52 ;
    END
  END in_key[80]
  PIN in_key[81]
    DIRECTION INPUT ;
    USE SIGNAL ;
    PORT
      LAYER M5 ;
        RECT  26.16 47.436 26.184 47.52 ;
    END
  END in_key[81]
  PIN in_key[82]
    DIRECTION INPUT ;
    USE SIGNAL ;
    PORT
      LAYER M5 ;
        RECT  26.256 47.436 26.28 47.52 ;
    END
  END in_key[82]
  PIN in_key[83]
    DIRECTION INPUT ;
    USE SIGNAL ;
    PORT
      LAYER M5 ;
        RECT  26.352 47.436 26.376 47.52 ;
    END
  END in_key[83]
  PIN in_key[84]
    DIRECTION INPUT ;
    USE SIGNAL ;
    PORT
      LAYER M5 ;
        RECT  26.448 47.436 26.472 47.52 ;
    END
  END in_key[84]
  PIN in_key[85]
    DIRECTION INPUT ;
    USE SIGNAL ;
    PORT
      LAYER M5 ;
        RECT  26.544 47.436 26.568 47.52 ;
    END
  END in_key[85]
  PIN in_key[86]
    DIRECTION INPUT ;
    USE SIGNAL ;
    PORT
      LAYER M5 ;
        RECT  26.64 47.436 26.664 47.52 ;
    END
  END in_key[86]
  PIN in_key[87]
    DIRECTION INPUT ;
    USE SIGNAL ;
    PORT
      LAYER M5 ;
        RECT  26.736 47.436 26.76 47.52 ;
    END
  END in_key[87]
  PIN in_key[88]
    DIRECTION INPUT ;
    USE SIGNAL ;
    PORT
      LAYER M5 ;
        RECT  26.832 47.436 26.856 47.52 ;
    END
  END in_key[88]
  PIN in_key[89]
    DIRECTION INPUT ;
    USE SIGNAL ;
    PORT
      LAYER M5 ;
        RECT  26.928 47.436 26.952 47.52 ;
    END
  END in_key[89]
  PIN in_key[8]
    DIRECTION INPUT ;
    USE SIGNAL ;
    PORT
      LAYER M5 ;
        RECT  22.224 47.436 22.248 47.52 ;
    END
  END in_key[8]
  PIN in_key[90]
    DIRECTION INPUT ;
    USE SIGNAL ;
    PORT
      LAYER M5 ;
        RECT  27.024 47.436 27.048 47.52 ;
    END
  END in_key[90]
  PIN in_key[91]
    DIRECTION INPUT ;
    USE SIGNAL ;
    PORT
      LAYER M5 ;
        RECT  27.12 47.436 27.144 47.52 ;
    END
  END in_key[91]
  PIN in_key[92]
    DIRECTION INPUT ;
    USE SIGNAL ;
    PORT
      LAYER M5 ;
        RECT  27.216 47.436 27.24 47.52 ;
    END
  END in_key[92]
  PIN in_key[93]
    DIRECTION INPUT ;
    USE SIGNAL ;
    PORT
      LAYER M5 ;
        RECT  27.312 47.436 27.336 47.52 ;
    END
  END in_key[93]
  PIN in_key[94]
    DIRECTION INPUT ;
    USE SIGNAL ;
    PORT
      LAYER M5 ;
        RECT  27.408 47.436 27.432 47.52 ;
    END
  END in_key[94]
  PIN in_key[95]
    DIRECTION INPUT ;
    USE SIGNAL ;
    PORT
      LAYER M5 ;
        RECT  27.504 47.436 27.528 47.52 ;
    END
  END in_key[95]
  PIN in_key[96]
    DIRECTION INPUT ;
    USE SIGNAL ;
    PORT
      LAYER M5 ;
        RECT  27.6 47.436 27.624 47.52 ;
    END
  END in_key[96]
  PIN in_key[97]
    DIRECTION INPUT ;
    USE SIGNAL ;
    PORT
      LAYER M5 ;
        RECT  27.696 47.436 27.72 47.52 ;
    END
  END in_key[97]
  PIN in_key[98]
    DIRECTION INPUT ;
    USE SIGNAL ;
    PORT
      LAYER M5 ;
        RECT  27.792 47.436 27.816 47.52 ;
    END
  END in_key[98]
  PIN in_key[99]
    DIRECTION INPUT ;
    USE SIGNAL ;
    PORT
      LAYER M5 ;
        RECT  27.888 47.436 27.912 47.52 ;
    END
  END in_key[99]
  PIN in_key[9]
    DIRECTION INPUT ;
    USE SIGNAL ;
    PORT
      LAYER M5 ;
        RECT  22.32 47.436 22.344 47.52 ;
    END
  END in_key[9]
  PIN in_meta[0]
    DIRECTION INPUT ;
    USE SIGNAL ;
    PORT
      LAYER M5 ;
        RECT  66 47.436 66.024 47.52 ;
    END
  END in_meta[0]
  PIN in_meta[100]
    DIRECTION INPUT ;
    USE SIGNAL ;
    PORT
      LAYER M5 ;
        RECT  47.184 47.436 47.208 47.52 ;
    END
  END in_meta[100]
  PIN in_meta[101]
    DIRECTION INPUT ;
    USE SIGNAL ;
    PORT
      LAYER M5 ;
        RECT  47.28 47.436 47.304 47.52 ;
    END
  END in_meta[101]
  PIN in_meta[102]
    DIRECTION INPUT ;
    USE SIGNAL ;
    PORT
      LAYER M5 ;
        RECT  47.376 47.436 47.4 47.52 ;
    END
  END in_meta[102]
  PIN in_meta[103]
    DIRECTION INPUT ;
    USE SIGNAL ;
    PORT
      LAYER M5 ;
        RECT  47.472 47.436 47.496 47.52 ;
    END
  END in_meta[103]
  PIN in_meta[104]
    DIRECTION INPUT ;
    USE SIGNAL ;
    PORT
      LAYER M5 ;
        RECT  47.568 47.436 47.592 47.52 ;
    END
  END in_meta[104]
  PIN in_meta[105]
    DIRECTION INPUT ;
    USE SIGNAL ;
    PORT
      LAYER M5 ;
        RECT  47.664 47.436 47.688 47.52 ;
    END
  END in_meta[105]
  PIN in_meta[106]
    DIRECTION INPUT ;
    USE SIGNAL ;
    PORT
      LAYER M5 ;
        RECT  47.76 47.436 47.784 47.52 ;
    END
  END in_meta[106]
  PIN in_meta[107]
    DIRECTION INPUT ;
    USE SIGNAL ;
    PORT
      LAYER M5 ;
        RECT  47.856 47.436 47.88 47.52 ;
    END
  END in_meta[107]
  PIN in_meta[108]
    DIRECTION INPUT ;
    USE SIGNAL ;
    PORT
      LAYER M5 ;
        RECT  47.952 47.436 47.976 47.52 ;
    END
  END in_meta[108]
  PIN in_meta[109]
    DIRECTION INPUT ;
    USE SIGNAL ;
    PORT
      LAYER M5 ;
        RECT  48.048 47.436 48.072 47.52 ;
    END
  END in_meta[109]
  PIN in_meta[10]
    DIRECTION INPUT ;
    USE SIGNAL ;
    PORT
      LAYER M5 ;
        RECT  66.96 47.436 66.984 47.52 ;
    END
  END in_meta[10]
  PIN in_meta[110]
    DIRECTION INPUT ;
    USE SIGNAL ;
    PORT
      LAYER M5 ;
        RECT  48.144 47.436 48.168 47.52 ;
    END
  END in_meta[110]
  PIN in_meta[111]
    DIRECTION INPUT ;
    USE SIGNAL ;
    PORT
      LAYER M5 ;
        RECT  48.24 47.436 48.264 47.52 ;
    END
  END in_meta[111]
  PIN in_meta[112]
    DIRECTION INPUT ;
    USE SIGNAL ;
    PORT
      LAYER M5 ;
        RECT  48.336 47.436 48.36 47.52 ;
    END
  END in_meta[112]
  PIN in_meta[113]
    DIRECTION INPUT ;
    USE SIGNAL ;
    PORT
      LAYER M5 ;
        RECT  48.432 47.436 48.456 47.52 ;
    END
  END in_meta[113]
  PIN in_meta[114]
    DIRECTION INPUT ;
    USE SIGNAL ;
    PORT
      LAYER M5 ;
        RECT  48.528 47.436 48.552 47.52 ;
    END
  END in_meta[114]
  PIN in_meta[115]
    DIRECTION INPUT ;
    USE SIGNAL ;
    PORT
      LAYER M5 ;
        RECT  48.624 47.436 48.648 47.52 ;
    END
  END in_meta[115]
  PIN in_meta[116]
    DIRECTION INPUT ;
    USE SIGNAL ;
    PORT
      LAYER M5 ;
        RECT  48.72 47.436 48.744 47.52 ;
    END
  END in_meta[116]
  PIN in_meta[117]
    DIRECTION INPUT ;
    USE SIGNAL ;
    PORT
      LAYER M5 ;
        RECT  48.816 47.436 48.84 47.52 ;
    END
  END in_meta[117]
  PIN in_meta[118]
    DIRECTION INPUT ;
    USE SIGNAL ;
    PORT
      LAYER M5 ;
        RECT  48.912 47.436 48.936 47.52 ;
    END
  END in_meta[118]
  PIN in_meta[119]
    DIRECTION INPUT ;
    USE SIGNAL ;
    PORT
      LAYER M5 ;
        RECT  49.008 47.436 49.032 47.52 ;
    END
  END in_meta[119]
  PIN in_meta[11]
    DIRECTION INPUT ;
    USE SIGNAL ;
    PORT
      LAYER M5 ;
        RECT  67.056 47.436 67.08 47.52 ;
    END
  END in_meta[11]
  PIN in_meta[120]
    DIRECTION INPUT ;
    USE SIGNAL ;
    PORT
      LAYER M5 ;
        RECT  49.104 47.436 49.128 47.52 ;
    END
  END in_meta[120]
  PIN in_meta[121]
    DIRECTION INPUT ;
    USE SIGNAL ;
    PORT
      LAYER M5 ;
        RECT  49.2 47.436 49.224 47.52 ;
    END
  END in_meta[121]
  PIN in_meta[122]
    DIRECTION INPUT ;
    USE SIGNAL ;
    PORT
      LAYER M5 ;
        RECT  49.296 47.436 49.32 47.52 ;
    END
  END in_meta[122]
  PIN in_meta[123]
    DIRECTION INPUT ;
    USE SIGNAL ;
    PORT
      LAYER M5 ;
        RECT  49.392 47.436 49.416 47.52 ;
    END
  END in_meta[123]
  PIN in_meta[124]
    DIRECTION INPUT ;
    USE SIGNAL ;
    PORT
      LAYER M5 ;
        RECT  49.488 47.436 49.512 47.52 ;
    END
  END in_meta[124]
  PIN in_meta[125]
    DIRECTION INPUT ;
    USE SIGNAL ;
    PORT
      LAYER M5 ;
        RECT  49.584 47.436 49.608 47.52 ;
    END
  END in_meta[125]
  PIN in_meta[126]
    DIRECTION INPUT ;
    USE SIGNAL ;
    PORT
      LAYER M5 ;
        RECT  49.68 47.436 49.704 47.52 ;
    END
  END in_meta[126]
  PIN in_meta[127]
    DIRECTION INPUT ;
    USE SIGNAL ;
    PORT
      LAYER M5 ;
        RECT  45.36 47.436 45.384 47.52 ;
    END
  END in_meta[127]
  PIN in_meta[128]
    DIRECTION INPUT ;
    USE SIGNAL ;
    PORT
      LAYER M5 ;
        RECT  45.456 47.436 45.48 47.52 ;
    END
  END in_meta[128]
  PIN in_meta[129]
    DIRECTION INPUT ;
    USE SIGNAL ;
    PORT
      LAYER M5 ;
        RECT  45.552 47.436 45.576 47.52 ;
    END
  END in_meta[129]
  PIN in_meta[12]
    DIRECTION INPUT ;
    USE SIGNAL ;
    PORT
      LAYER M5 ;
        RECT  67.152 47.436 67.176 47.52 ;
    END
  END in_meta[12]
  PIN in_meta[130]
    DIRECTION INPUT ;
    USE SIGNAL ;
    PORT
      LAYER M5 ;
        RECT  45.648 47.436 45.672 47.52 ;
    END
  END in_meta[130]
  PIN in_meta[131]
    DIRECTION INPUT ;
    USE SIGNAL ;
    PORT
      LAYER M5 ;
        RECT  45.744 47.436 45.768 47.52 ;
    END
  END in_meta[131]
  PIN in_meta[13]
    DIRECTION INPUT ;
    USE SIGNAL ;
    PORT
      LAYER M5 ;
        RECT  67.248 47.436 67.272 47.52 ;
    END
  END in_meta[13]
  PIN in_meta[14]
    DIRECTION INPUT ;
    USE SIGNAL ;
    PORT
      LAYER M5 ;
        RECT  67.344 47.436 67.368 47.52 ;
    END
  END in_meta[14]
  PIN in_meta[15]
    DIRECTION INPUT ;
    USE SIGNAL ;
    PORT
      LAYER M5 ;
        RECT  67.44 47.436 67.464 47.52 ;
    END
  END in_meta[15]
  PIN in_meta[16]
    DIRECTION INPUT ;
    USE SIGNAL ;
    PORT
      LAYER M5 ;
        RECT  67.536 47.436 67.56 47.52 ;
    END
  END in_meta[16]
  PIN in_meta[17]
    DIRECTION INPUT ;
    USE SIGNAL ;
    PORT
      LAYER M5 ;
        RECT  67.632 47.436 67.656 47.52 ;
    END
  END in_meta[17]
  PIN in_meta[18]
    DIRECTION INPUT ;
    USE SIGNAL ;
    PORT
      LAYER M5 ;
        RECT  67.728 47.436 67.752 47.52 ;
    END
  END in_meta[18]
  PIN in_meta[19]
    DIRECTION INPUT ;
    USE SIGNAL ;
    PORT
      LAYER M5 ;
        RECT  67.824 47.436 67.848 47.52 ;
    END
  END in_meta[19]
  PIN in_meta[1]
    DIRECTION INPUT ;
    USE SIGNAL ;
    PORT
      LAYER M5 ;
        RECT  66.096 47.436 66.12 47.52 ;
    END
  END in_meta[1]
  PIN in_meta[20]
    DIRECTION INPUT ;
    USE SIGNAL ;
    PORT
      LAYER M5 ;
        RECT  67.92 47.436 67.944 47.52 ;
    END
  END in_meta[20]
  PIN in_meta[21]
    DIRECTION INPUT ;
    USE SIGNAL ;
    PORT
      LAYER M5 ;
        RECT  68.016 47.436 68.04 47.52 ;
    END
  END in_meta[21]
  PIN in_meta[22]
    DIRECTION INPUT ;
    USE SIGNAL ;
    PORT
      LAYER M5 ;
        RECT  68.112 47.436 68.136 47.52 ;
    END
  END in_meta[22]
  PIN in_meta[23]
    DIRECTION INPUT ;
    USE SIGNAL ;
    PORT
      LAYER M5 ;
        RECT  68.208 47.436 68.232 47.52 ;
    END
  END in_meta[23]
  PIN in_meta[24]
    DIRECTION INPUT ;
    USE SIGNAL ;
    PORT
      LAYER M5 ;
        RECT  68.304 47.436 68.328 47.52 ;
    END
  END in_meta[24]
  PIN in_meta[25]
    DIRECTION INPUT ;
    USE SIGNAL ;
    PORT
      LAYER M5 ;
        RECT  68.4 47.436 68.424 47.52 ;
    END
  END in_meta[25]
  PIN in_meta[26]
    DIRECTION INPUT ;
    USE SIGNAL ;
    PORT
      LAYER M5 ;
        RECT  68.496 47.436 68.52 47.52 ;
    END
  END in_meta[26]
  PIN in_meta[27]
    DIRECTION INPUT ;
    USE SIGNAL ;
    PORT
      LAYER M5 ;
        RECT  68.592 47.436 68.616 47.52 ;
    END
  END in_meta[27]
  PIN in_meta[28]
    DIRECTION INPUT ;
    USE SIGNAL ;
    PORT
      LAYER M5 ;
        RECT  68.688 47.436 68.712 47.52 ;
    END
  END in_meta[28]
  PIN in_meta[29]
    DIRECTION INPUT ;
    USE SIGNAL ;
    PORT
      LAYER M5 ;
        RECT  68.784 47.436 68.808 47.52 ;
    END
  END in_meta[29]
  PIN in_meta[2]
    DIRECTION INPUT ;
    USE SIGNAL ;
    PORT
      LAYER M5 ;
        RECT  66.192 47.436 66.216 47.52 ;
    END
  END in_meta[2]
  PIN in_meta[30]
    DIRECTION INPUT ;
    USE SIGNAL ;
    PORT
      LAYER M5 ;
        RECT  68.88 47.436 68.904 47.52 ;
    END
  END in_meta[30]
  PIN in_meta[31]
    DIRECTION INPUT ;
    USE SIGNAL ;
    PORT
      LAYER M5 ;
        RECT  49.776 47.436 49.8 47.52 ;
    END
  END in_meta[31]
  PIN in_meta[32]
    DIRECTION INPUT ;
    USE SIGNAL ;
    PORT
      LAYER M5 ;
        RECT  49.872 47.436 49.896 47.52 ;
    END
  END in_meta[32]
  PIN in_meta[33]
    DIRECTION INPUT ;
    USE SIGNAL ;
    PORT
      LAYER M5 ;
        RECT  49.968 47.436 49.992 47.52 ;
    END
  END in_meta[33]
  PIN in_meta[34]
    DIRECTION INPUT ;
    USE SIGNAL ;
    PORT
      LAYER M5 ;
        RECT  50.064 47.436 50.088 47.52 ;
    END
  END in_meta[34]
  PIN in_meta[35]
    DIRECTION INPUT ;
    USE SIGNAL ;
    PORT
      LAYER M5 ;
        RECT  50.16 47.436 50.184 47.52 ;
    END
  END in_meta[35]
  PIN in_meta[36]
    DIRECTION INPUT ;
    USE SIGNAL ;
    PORT
      LAYER M5 ;
        RECT  50.256 47.436 50.28 47.52 ;
    END
  END in_meta[36]
  PIN in_meta[37]
    DIRECTION INPUT ;
    USE SIGNAL ;
    PORT
      LAYER M5 ;
        RECT  50.352 47.436 50.376 47.52 ;
    END
  END in_meta[37]
  PIN in_meta[38]
    DIRECTION INPUT ;
    USE SIGNAL ;
    PORT
      LAYER M5 ;
        RECT  50.448 47.436 50.472 47.52 ;
    END
  END in_meta[38]
  PIN in_meta[39]
    DIRECTION INPUT ;
    USE SIGNAL ;
    PORT
      LAYER M5 ;
        RECT  50.544 47.436 50.568 47.52 ;
    END
  END in_meta[39]
  PIN in_meta[3]
    DIRECTION INPUT ;
    USE SIGNAL ;
    PORT
      LAYER M5 ;
        RECT  66.288 47.436 66.312 47.52 ;
    END
  END in_meta[3]
  PIN in_meta[40]
    DIRECTION INPUT ;
    USE SIGNAL ;
    PORT
      LAYER M5 ;
        RECT  50.64 47.436 50.664 47.52 ;
    END
  END in_meta[40]
  PIN in_meta[41]
    DIRECTION INPUT ;
    USE SIGNAL ;
    PORT
      LAYER M5 ;
        RECT  50.736 47.436 50.76 47.52 ;
    END
  END in_meta[41]
  PIN in_meta[42]
    DIRECTION INPUT ;
    USE SIGNAL ;
    PORT
      LAYER M5 ;
        RECT  50.832 47.436 50.856 47.52 ;
    END
  END in_meta[42]
  PIN in_meta[43]
    DIRECTION INPUT ;
    USE SIGNAL ;
    PORT
      LAYER M5 ;
        RECT  50.928 47.436 50.952 47.52 ;
    END
  END in_meta[43]
  PIN in_meta[44]
    DIRECTION INPUT ;
    USE SIGNAL ;
    PORT
      LAYER M5 ;
        RECT  51.024 47.436 51.048 47.52 ;
    END
  END in_meta[44]
  PIN in_meta[45]
    DIRECTION INPUT ;
    USE SIGNAL ;
    PORT
      LAYER M5 ;
        RECT  51.12 47.436 51.144 47.52 ;
    END
  END in_meta[45]
  PIN in_meta[46]
    DIRECTION INPUT ;
    USE SIGNAL ;
    PORT
      LAYER M5 ;
        RECT  51.216 47.436 51.24 47.52 ;
    END
  END in_meta[46]
  PIN in_meta[47]
    DIRECTION INPUT ;
    USE SIGNAL ;
    PORT
      LAYER M5 ;
        RECT  51.312 47.436 51.336 47.52 ;
    END
  END in_meta[47]
  PIN in_meta[48]
    DIRECTION INPUT ;
    USE SIGNAL ;
    PORT
      LAYER M5 ;
        RECT  51.408 47.436 51.432 47.52 ;
    END
  END in_meta[48]
  PIN in_meta[49]
    DIRECTION INPUT ;
    USE SIGNAL ;
    PORT
      LAYER M5 ;
        RECT  51.504 47.436 51.528 47.52 ;
    END
  END in_meta[49]
  PIN in_meta[4]
    DIRECTION INPUT ;
    USE SIGNAL ;
    PORT
      LAYER M5 ;
        RECT  66.384 47.436 66.408 47.52 ;
    END
  END in_meta[4]
  PIN in_meta[50]
    DIRECTION INPUT ;
    USE SIGNAL ;
    PORT
      LAYER M5 ;
        RECT  51.6 47.436 51.624 47.52 ;
    END
  END in_meta[50]
  PIN in_meta[51]
    DIRECTION INPUT ;
    USE SIGNAL ;
    PORT
      LAYER M5 ;
        RECT  51.696 47.436 51.72 47.52 ;
    END
  END in_meta[51]
  PIN in_meta[52]
    DIRECTION INPUT ;
    USE SIGNAL ;
    PORT
      LAYER M5 ;
        RECT  51.792 47.436 51.816 47.52 ;
    END
  END in_meta[52]
  PIN in_meta[53]
    DIRECTION INPUT ;
    USE SIGNAL ;
    PORT
      LAYER M5 ;
        RECT  51.888 47.436 51.912 47.52 ;
    END
  END in_meta[53]
  PIN in_meta[54]
    DIRECTION INPUT ;
    USE SIGNAL ;
    PORT
      LAYER M5 ;
        RECT  51.984 47.436 52.008 47.52 ;
    END
  END in_meta[54]
  PIN in_meta[55]
    DIRECTION INPUT ;
    USE SIGNAL ;
    PORT
      LAYER M5 ;
        RECT  52.08 47.436 52.104 47.52 ;
    END
  END in_meta[55]
  PIN in_meta[56]
    DIRECTION INPUT ;
    USE SIGNAL ;
    PORT
      LAYER M5 ;
        RECT  52.176 47.436 52.2 47.52 ;
    END
  END in_meta[56]
  PIN in_meta[57]
    DIRECTION INPUT ;
    USE SIGNAL ;
    PORT
      LAYER M5 ;
        RECT  52.272 47.436 52.296 47.52 ;
    END
  END in_meta[57]
  PIN in_meta[58]
    DIRECTION INPUT ;
    USE SIGNAL ;
    PORT
      LAYER M5 ;
        RECT  52.368 47.436 52.392 47.52 ;
    END
  END in_meta[58]
  PIN in_meta[59]
    DIRECTION INPUT ;
    USE SIGNAL ;
    PORT
      LAYER M5 ;
        RECT  52.464 47.436 52.488 47.52 ;
    END
  END in_meta[59]
  PIN in_meta[5]
    DIRECTION INPUT ;
    USE SIGNAL ;
    PORT
      LAYER M5 ;
        RECT  66.48 47.436 66.504 47.52 ;
    END
  END in_meta[5]
  PIN in_meta[60]
    DIRECTION INPUT ;
    USE SIGNAL ;
    PORT
      LAYER M5 ;
        RECT  52.56 47.436 52.584 47.52 ;
    END
  END in_meta[60]
  PIN in_meta[61]
    DIRECTION INPUT ;
    USE SIGNAL ;
    PORT
      LAYER M5 ;
        RECT  52.656 47.436 52.68 47.52 ;
    END
  END in_meta[61]
  PIN in_meta[62]
    DIRECTION INPUT ;
    USE SIGNAL ;
    PORT
      LAYER M5 ;
        RECT  52.752 47.436 52.776 47.52 ;
    END
  END in_meta[62]
  PIN in_meta[63]
    DIRECTION INPUT ;
    USE SIGNAL ;
    PORT
      LAYER M5 ;
        RECT  56.688 47.436 56.712 47.52 ;
    END
  END in_meta[63]
  PIN in_meta[64]
    DIRECTION INPUT ;
    USE SIGNAL ;
    PORT
      LAYER M5 ;
        RECT  56.784 47.436 56.808 47.52 ;
    END
  END in_meta[64]
  PIN in_meta[65]
    DIRECTION INPUT ;
    USE SIGNAL ;
    PORT
      LAYER M5 ;
        RECT  56.88 47.436 56.904 47.52 ;
    END
  END in_meta[65]
  PIN in_meta[66]
    DIRECTION INPUT ;
    USE SIGNAL ;
    PORT
      LAYER M5 ;
        RECT  56.976 47.436 57 47.52 ;
    END
  END in_meta[66]
  PIN in_meta[67]
    DIRECTION INPUT ;
    USE SIGNAL ;
    PORT
      LAYER M5 ;
        RECT  57.072 47.436 57.096 47.52 ;
    END
  END in_meta[67]
  PIN in_meta[68]
    DIRECTION INPUT ;
    USE SIGNAL ;
    PORT
      LAYER M5 ;
        RECT  57.168 47.436 57.192 47.52 ;
    END
  END in_meta[68]
  PIN in_meta[69]
    DIRECTION INPUT ;
    USE SIGNAL ;
    PORT
      LAYER M5 ;
        RECT  57.264 47.436 57.288 47.52 ;
    END
  END in_meta[69]
  PIN in_meta[6]
    DIRECTION INPUT ;
    USE SIGNAL ;
    PORT
      LAYER M5 ;
        RECT  66.576 47.436 66.6 47.52 ;
    END
  END in_meta[6]
  PIN in_meta[70]
    DIRECTION INPUT ;
    USE SIGNAL ;
    PORT
      LAYER M5 ;
        RECT  57.36 47.436 57.384 47.52 ;
    END
  END in_meta[70]
  PIN in_meta[71]
    DIRECTION INPUT ;
    USE SIGNAL ;
    PORT
      LAYER M5 ;
        RECT  57.456 47.436 57.48 47.52 ;
    END
  END in_meta[71]
  PIN in_meta[72]
    DIRECTION INPUT ;
    USE SIGNAL ;
    PORT
      LAYER M5 ;
        RECT  57.552 47.436 57.576 47.52 ;
    END
  END in_meta[72]
  PIN in_meta[73]
    DIRECTION INPUT ;
    USE SIGNAL ;
    PORT
      LAYER M5 ;
        RECT  57.648 47.436 57.672 47.52 ;
    END
  END in_meta[73]
  PIN in_meta[74]
    DIRECTION INPUT ;
    USE SIGNAL ;
    PORT
      LAYER M5 ;
        RECT  57.744 47.436 57.768 47.52 ;
    END
  END in_meta[74]
  PIN in_meta[75]
    DIRECTION INPUT ;
    USE SIGNAL ;
    PORT
      LAYER M5 ;
        RECT  57.84 47.436 57.864 47.52 ;
    END
  END in_meta[75]
  PIN in_meta[76]
    DIRECTION INPUT ;
    USE SIGNAL ;
    PORT
      LAYER M5 ;
        RECT  57.936 47.436 57.96 47.52 ;
    END
  END in_meta[76]
  PIN in_meta[77]
    DIRECTION INPUT ;
    USE SIGNAL ;
    PORT
      LAYER M5 ;
        RECT  58.032 47.436 58.056 47.52 ;
    END
  END in_meta[77]
  PIN in_meta[78]
    DIRECTION INPUT ;
    USE SIGNAL ;
    PORT
      LAYER M5 ;
        RECT  58.128 47.436 58.152 47.52 ;
    END
  END in_meta[78]
  PIN in_meta[79]
    DIRECTION INPUT ;
    USE SIGNAL ;
    PORT
      LAYER M5 ;
        RECT  58.224 47.436 58.248 47.52 ;
    END
  END in_meta[79]
  PIN in_meta[7]
    DIRECTION INPUT ;
    USE SIGNAL ;
    PORT
      LAYER M5 ;
        RECT  66.672 47.436 66.696 47.52 ;
    END
  END in_meta[7]
  PIN in_meta[80]
    DIRECTION INPUT ;
    USE SIGNAL ;
    PORT
      LAYER M5 ;
        RECT  58.32 47.436 58.344 47.52 ;
    END
  END in_meta[80]
  PIN in_meta[81]
    DIRECTION INPUT ;
    USE SIGNAL ;
    PORT
      LAYER M5 ;
        RECT  58.416 47.436 58.44 47.52 ;
    END
  END in_meta[81]
  PIN in_meta[82]
    DIRECTION INPUT ;
    USE SIGNAL ;
    PORT
      LAYER M5 ;
        RECT  58.512 47.436 58.536 47.52 ;
    END
  END in_meta[82]
  PIN in_meta[83]
    DIRECTION INPUT ;
    USE SIGNAL ;
    PORT
      LAYER M5 ;
        RECT  58.608 47.436 58.632 47.52 ;
    END
  END in_meta[83]
  PIN in_meta[84]
    DIRECTION INPUT ;
    USE SIGNAL ;
    PORT
      LAYER M5 ;
        RECT  58.704 47.436 58.728 47.52 ;
    END
  END in_meta[84]
  PIN in_meta[85]
    DIRECTION INPUT ;
    USE SIGNAL ;
    PORT
      LAYER M5 ;
        RECT  58.8 47.436 58.824 47.52 ;
    END
  END in_meta[85]
  PIN in_meta[86]
    DIRECTION INPUT ;
    USE SIGNAL ;
    PORT
      LAYER M5 ;
        RECT  58.896 47.436 58.92 47.52 ;
    END
  END in_meta[86]
  PIN in_meta[87]
    DIRECTION INPUT ;
    USE SIGNAL ;
    PORT
      LAYER M5 ;
        RECT  58.992 47.436 59.016 47.52 ;
    END
  END in_meta[87]
  PIN in_meta[88]
    DIRECTION INPUT ;
    USE SIGNAL ;
    PORT
      LAYER M5 ;
        RECT  59.088 47.436 59.112 47.52 ;
    END
  END in_meta[88]
  PIN in_meta[89]
    DIRECTION INPUT ;
    USE SIGNAL ;
    PORT
      LAYER M5 ;
        RECT  59.184 47.436 59.208 47.52 ;
    END
  END in_meta[89]
  PIN in_meta[8]
    DIRECTION INPUT ;
    USE SIGNAL ;
    PORT
      LAYER M5 ;
        RECT  66.768 47.436 66.792 47.52 ;
    END
  END in_meta[8]
  PIN in_meta[90]
    DIRECTION INPUT ;
    USE SIGNAL ;
    PORT
      LAYER M5 ;
        RECT  59.28 47.436 59.304 47.52 ;
    END
  END in_meta[90]
  PIN in_meta[91]
    DIRECTION INPUT ;
    USE SIGNAL ;
    PORT
      LAYER M5 ;
        RECT  59.376 47.436 59.4 47.52 ;
    END
  END in_meta[91]
  PIN in_meta[92]
    DIRECTION INPUT ;
    USE SIGNAL ;
    PORT
      LAYER M5 ;
        RECT  59.472 47.436 59.496 47.52 ;
    END
  END in_meta[92]
  PIN in_meta[93]
    DIRECTION INPUT ;
    USE SIGNAL ;
    PORT
      LAYER M5 ;
        RECT  59.568 47.436 59.592 47.52 ;
    END
  END in_meta[93]
  PIN in_meta[94]
    DIRECTION INPUT ;
    USE SIGNAL ;
    PORT
      LAYER M5 ;
        RECT  59.664 47.436 59.688 47.52 ;
    END
  END in_meta[94]
  PIN in_meta[95]
    DIRECTION INPUT ;
    USE SIGNAL ;
    PORT
      LAYER M5 ;
        RECT  46.704 47.436 46.728 47.52 ;
    END
  END in_meta[95]
  PIN in_meta[96]
    DIRECTION INPUT ;
    USE SIGNAL ;
    PORT
      LAYER M5 ;
        RECT  46.8 47.436 46.824 47.52 ;
    END
  END in_meta[96]
  PIN in_meta[97]
    DIRECTION INPUT ;
    USE SIGNAL ;
    PORT
      LAYER M5 ;
        RECT  46.896 47.436 46.92 47.52 ;
    END
  END in_meta[97]
  PIN in_meta[98]
    DIRECTION INPUT ;
    USE SIGNAL ;
    PORT
      LAYER M5 ;
        RECT  46.992 47.436 47.016 47.52 ;
    END
  END in_meta[98]
  PIN in_meta[99]
    DIRECTION INPUT ;
    USE SIGNAL ;
    PORT
      LAYER M5 ;
        RECT  47.088 47.436 47.112 47.52 ;
    END
  END in_meta[99]
  PIN in_meta[9]
    DIRECTION INPUT ;
    USE SIGNAL ;
    PORT
      LAYER M5 ;
        RECT  66.864 47.436 66.888 47.52 ;
    END
  END in_meta[9]
  PIN in_slot[0]
    DIRECTION INPUT ;
    USE SIGNAL ;
    PORT
      LAYER M5 ;
        RECT  45.84 47.436 45.864 47.52 ;
    END
  END in_slot[0]
  PIN in_slot[1]
    DIRECTION INPUT ;
    USE SIGNAL ;
    PORT
      LAYER M5 ;
        RECT  45.936 47.436 45.96 47.52 ;
    END
  END in_slot[1]
  PIN in_slot[2]
    DIRECTION INPUT ;
    USE SIGNAL ;
    PORT
      LAYER M5 ;
        RECT  46.032 47.436 46.056 47.52 ;
    END
  END in_slot[2]
  PIN in_slot[3]
    DIRECTION INPUT ;
    USE SIGNAL ;
    PORT
      LAYER M5 ;
        RECT  46.128 47.436 46.152 47.52 ;
    END
  END in_slot[3]
  PIN in_v[0]
    DIRECTION INPUT ;
    USE SIGNAL ;
    PORT
      LAYER M5 ;
        RECT  46.224 47.436 46.248 47.52 ;
    END
  END in_v[0]
  PIN in_v[1]
    DIRECTION INPUT ;
    USE SIGNAL ;
    PORT
      LAYER M5 ;
        RECT  46.32 47.436 46.344 47.52 ;
    END
  END in_v[1]
  PIN in_v[2]
    DIRECTION INPUT ;
    USE SIGNAL ;
    PORT
      LAYER M5 ;
        RECT  46.416 47.436 46.44 47.52 ;
    END
  END in_v[2]
  PIN in_v[3]
    DIRECTION INPUT ;
    USE SIGNAL ;
    PORT
      LAYER M5 ;
        RECT  46.512 47.436 46.536 47.52 ;
    END
  END in_v[3]
  PIN mode
    DIRECTION INPUT ;
    USE SIGNAL ;
    PORT
      LAYER M4 ;
        RECT  0 11.184 0.084 11.208 ;
    END
  END mode
  PIN out_flit[0]
    DIRECTION OUTPUT ;
    USE SIGNAL ;
    PORT
      LAYER M5 ;
        RECT  45.36 0 45.384 0.084 ;
    END
  END out_flit[0]
  PIN out_flit[100]
    DIRECTION OUTPUT ;
    USE SIGNAL ;
    PORT
      LAYER M5 ;
        RECT  48.816 0 48.84 0.084 ;
    END
  END out_flit[100]
  PIN out_flit[101]
    DIRECTION OUTPUT ;
    USE SIGNAL ;
    PORT
      LAYER M5 ;
        RECT  48.912 0 48.936 0.084 ;
    END
  END out_flit[101]
  PIN out_flit[102]
    DIRECTION OUTPUT ;
    USE SIGNAL ;
    PORT
      LAYER M5 ;
        RECT  49.008 0 49.032 0.084 ;
    END
  END out_flit[102]
  PIN out_flit[103]
    DIRECTION OUTPUT ;
    USE SIGNAL ;
    PORT
      LAYER M5 ;
        RECT  49.104 0 49.128 0.084 ;
    END
  END out_flit[103]
  PIN out_flit[104]
    DIRECTION OUTPUT ;
    USE SIGNAL ;
    PORT
      LAYER M5 ;
        RECT  49.2 0 49.224 0.084 ;
    END
  END out_flit[104]
  PIN out_flit[105]
    DIRECTION OUTPUT ;
    USE SIGNAL ;
    PORT
      LAYER M5 ;
        RECT  49.296 0 49.32 0.084 ;
    END
  END out_flit[105]
  PIN out_flit[106]
    DIRECTION OUTPUT ;
    USE SIGNAL ;
    PORT
      LAYER M5 ;
        RECT  49.392 0 49.416 0.084 ;
    END
  END out_flit[106]
  PIN out_flit[107]
    DIRECTION OUTPUT ;
    USE SIGNAL ;
    PORT
      LAYER M5 ;
        RECT  49.488 0 49.512 0.084 ;
    END
  END out_flit[107]
  PIN out_flit[108]
    DIRECTION OUTPUT ;
    USE SIGNAL ;
    PORT
      LAYER M5 ;
        RECT  49.584 0 49.608 0.084 ;
    END
  END out_flit[108]
  PIN out_flit[109]
    DIRECTION OUTPUT ;
    USE SIGNAL ;
    PORT
      LAYER M5 ;
        RECT  49.68 0 49.704 0.084 ;
    END
  END out_flit[109]
  PIN out_flit[10]
    DIRECTION OUTPUT ;
    USE SIGNAL ;
    PORT
      LAYER M5 ;
        RECT  46.32 0 46.344 0.084 ;
    END
  END out_flit[10]
  PIN out_flit[110]
    DIRECTION OUTPUT ;
    USE SIGNAL ;
    PORT
      LAYER M5 ;
        RECT  49.776 0 49.8 0.084 ;
    END
  END out_flit[110]
  PIN out_flit[111]
    DIRECTION OUTPUT ;
    USE SIGNAL ;
    PORT
      LAYER M5 ;
        RECT  49.872 0 49.896 0.084 ;
    END
  END out_flit[111]
  PIN out_flit[112]
    DIRECTION OUTPUT ;
    USE SIGNAL ;
    PORT
      LAYER M5 ;
        RECT  49.968 0 49.992 0.084 ;
    END
  END out_flit[112]
  PIN out_flit[113]
    DIRECTION OUTPUT ;
    USE SIGNAL ;
    PORT
      LAYER M5 ;
        RECT  50.064 0 50.088 0.084 ;
    END
  END out_flit[113]
  PIN out_flit[114]
    DIRECTION OUTPUT ;
    USE SIGNAL ;
    PORT
      LAYER M5 ;
        RECT  50.16 0 50.184 0.084 ;
    END
  END out_flit[114]
  PIN out_flit[115]
    DIRECTION OUTPUT ;
    USE SIGNAL ;
    PORT
      LAYER M5 ;
        RECT  50.256 0 50.28 0.084 ;
    END
  END out_flit[115]
  PIN out_flit[116]
    DIRECTION OUTPUT ;
    USE SIGNAL ;
    PORT
      LAYER M5 ;
        RECT  50.352 0 50.376 0.084 ;
    END
  END out_flit[116]
  PIN out_flit[117]
    DIRECTION OUTPUT ;
    USE SIGNAL ;
    PORT
      LAYER M5 ;
        RECT  50.448 0 50.472 0.084 ;
    END
  END out_flit[117]
  PIN out_flit[118]
    DIRECTION OUTPUT ;
    USE SIGNAL ;
    PORT
      LAYER M5 ;
        RECT  50.544 0 50.568 0.084 ;
    END
  END out_flit[118]
  PIN out_flit[119]
    DIRECTION OUTPUT ;
    USE SIGNAL ;
    PORT
      LAYER M5 ;
        RECT  50.64 0 50.664 0.084 ;
    END
  END out_flit[119]
  PIN out_flit[11]
    DIRECTION OUTPUT ;
    USE SIGNAL ;
    PORT
      LAYER M5 ;
        RECT  46.416 0 46.44 0.084 ;
    END
  END out_flit[11]
  PIN out_flit[120]
    DIRECTION OUTPUT ;
    USE SIGNAL ;
    PORT
      LAYER M5 ;
        RECT  50.736 0 50.76 0.084 ;
    END
  END out_flit[120]
  PIN out_flit[121]
    DIRECTION OUTPUT ;
    USE SIGNAL ;
    PORT
      LAYER M5 ;
        RECT  50.832 0 50.856 0.084 ;
    END
  END out_flit[121]
  PIN out_flit[122]
    DIRECTION OUTPUT ;
    USE SIGNAL ;
    PORT
      LAYER M5 ;
        RECT  50.928 0 50.952 0.084 ;
    END
  END out_flit[122]
  PIN out_flit[123]
    DIRECTION OUTPUT ;
    USE SIGNAL ;
    PORT
      LAYER M5 ;
        RECT  51.024 0 51.048 0.084 ;
    END
  END out_flit[123]
  PIN out_flit[124]
    DIRECTION OUTPUT ;
    USE SIGNAL ;
    PORT
      LAYER M5 ;
        RECT  51.12 0 51.144 0.084 ;
    END
  END out_flit[124]
  PIN out_flit[125]
    DIRECTION OUTPUT ;
    USE SIGNAL ;
    PORT
      LAYER M5 ;
        RECT  51.216 0 51.24 0.084 ;
    END
  END out_flit[125]
  PIN out_flit[126]
    DIRECTION OUTPUT ;
    USE SIGNAL ;
    PORT
      LAYER M5 ;
        RECT  51.312 0 51.336 0.084 ;
    END
  END out_flit[126]
  PIN out_flit[127]
    DIRECTION OUTPUT ;
    USE SIGNAL ;
    PORT
      LAYER M5 ;
        RECT  42.192 0 42.216 0.084 ;
    END
  END out_flit[127]
  PIN out_flit[128]
    DIRECTION OUTPUT ;
    USE SIGNAL ;
    PORT
      LAYER M5 ;
        RECT  42.288 0 42.312 0.084 ;
    END
  END out_flit[128]
  PIN out_flit[129]
    DIRECTION OUTPUT ;
    USE SIGNAL ;
    PORT
      LAYER M5 ;
        RECT  42.384 0 42.408 0.084 ;
    END
  END out_flit[129]
  PIN out_flit[12]
    DIRECTION OUTPUT ;
    USE SIGNAL ;
    PORT
      LAYER M5 ;
        RECT  46.512 0 46.536 0.084 ;
    END
  END out_flit[12]
  PIN out_flit[130]
    DIRECTION OUTPUT ;
    USE SIGNAL ;
    PORT
      LAYER M5 ;
        RECT  42.48 0 42.504 0.084 ;
    END
  END out_flit[130]
  PIN out_flit[131]
    DIRECTION OUTPUT ;
    USE SIGNAL ;
    PORT
      LAYER M5 ;
        RECT  42.576 0 42.6 0.084 ;
    END
  END out_flit[131]
  PIN out_flit[132]
    DIRECTION OUTPUT ;
    USE SIGNAL ;
    PORT
      LAYER M5 ;
        RECT  42.672 0 42.696 0.084 ;
    END
  END out_flit[132]
  PIN out_flit[133]
    DIRECTION OUTPUT ;
    USE SIGNAL ;
    PORT
      LAYER M5 ;
        RECT  42.768 0 42.792 0.084 ;
    END
  END out_flit[133]
  PIN out_flit[134]
    DIRECTION OUTPUT ;
    USE SIGNAL ;
    PORT
      LAYER M5 ;
        RECT  42.864 0 42.888 0.084 ;
    END
  END out_flit[134]
  PIN out_flit[135]
    DIRECTION OUTPUT ;
    USE SIGNAL ;
    PORT
      LAYER M5 ;
        RECT  42.96 0 42.984 0.084 ;
    END
  END out_flit[135]
  PIN out_flit[136]
    DIRECTION OUTPUT ;
    USE SIGNAL ;
    PORT
      LAYER M5 ;
        RECT  43.056 0 43.08 0.084 ;
    END
  END out_flit[136]
  PIN out_flit[137]
    DIRECTION OUTPUT ;
    USE SIGNAL ;
    PORT
      LAYER M5 ;
        RECT  43.152 0 43.176 0.084 ;
    END
  END out_flit[137]
  PIN out_flit[138]
    DIRECTION OUTPUT ;
    USE SIGNAL ;
    PORT
      LAYER M5 ;
        RECT  43.248 0 43.272 0.084 ;
    END
  END out_flit[138]
  PIN out_flit[139]
    DIRECTION OUTPUT ;
    USE SIGNAL ;
    PORT
      LAYER M5 ;
        RECT  43.344 0 43.368 0.084 ;
    END
  END out_flit[139]
  PIN out_flit[13]
    DIRECTION OUTPUT ;
    USE SIGNAL ;
    PORT
      LAYER M5 ;
        RECT  46.608 0 46.632 0.084 ;
    END
  END out_flit[13]
  PIN out_flit[140]
    DIRECTION OUTPUT ;
    USE SIGNAL ;
    PORT
      LAYER M5 ;
        RECT  43.44 0 43.464 0.084 ;
    END
  END out_flit[140]
  PIN out_flit[141]
    DIRECTION OUTPUT ;
    USE SIGNAL ;
    PORT
      LAYER M5 ;
        RECT  43.536 0 43.56 0.084 ;
    END
  END out_flit[141]
  PIN out_flit[142]
    DIRECTION OUTPUT ;
    USE SIGNAL ;
    PORT
      LAYER M5 ;
        RECT  43.632 0 43.656 0.084 ;
    END
  END out_flit[142]
  PIN out_flit[143]
    DIRECTION OUTPUT ;
    USE SIGNAL ;
    PORT
      LAYER M5 ;
        RECT  43.728 0 43.752 0.084 ;
    END
  END out_flit[143]
  PIN out_flit[144]
    DIRECTION OUTPUT ;
    USE SIGNAL ;
    PORT
      LAYER M5 ;
        RECT  43.824 0 43.848 0.084 ;
    END
  END out_flit[144]
  PIN out_flit[145]
    DIRECTION OUTPUT ;
    USE SIGNAL ;
    PORT
      LAYER M5 ;
        RECT  43.92 0 43.944 0.084 ;
    END
  END out_flit[145]
  PIN out_flit[146]
    DIRECTION OUTPUT ;
    USE SIGNAL ;
    PORT
      LAYER M5 ;
        RECT  44.016 0 44.04 0.084 ;
    END
  END out_flit[146]
  PIN out_flit[147]
    DIRECTION OUTPUT ;
    USE SIGNAL ;
    PORT
      LAYER M5 ;
        RECT  44.112 0 44.136 0.084 ;
    END
  END out_flit[147]
  PIN out_flit[148]
    DIRECTION OUTPUT ;
    USE SIGNAL ;
    PORT
      LAYER M5 ;
        RECT  44.208 0 44.232 0.084 ;
    END
  END out_flit[148]
  PIN out_flit[149]
    DIRECTION OUTPUT ;
    USE SIGNAL ;
    PORT
      LAYER M5 ;
        RECT  44.304 0 44.328 0.084 ;
    END
  END out_flit[149]
  PIN out_flit[14]
    DIRECTION OUTPUT ;
    USE SIGNAL ;
    PORT
      LAYER M5 ;
        RECT  46.704 0 46.728 0.084 ;
    END
  END out_flit[14]
  PIN out_flit[150]
    DIRECTION OUTPUT ;
    USE SIGNAL ;
    PORT
      LAYER M5 ;
        RECT  44.4 0 44.424 0.084 ;
    END
  END out_flit[150]
  PIN out_flit[151]
    DIRECTION OUTPUT ;
    USE SIGNAL ;
    PORT
      LAYER M5 ;
        RECT  44.496 0 44.52 0.084 ;
    END
  END out_flit[151]
  PIN out_flit[152]
    DIRECTION OUTPUT ;
    USE SIGNAL ;
    PORT
      LAYER M5 ;
        RECT  44.592 0 44.616 0.084 ;
    END
  END out_flit[152]
  PIN out_flit[153]
    DIRECTION OUTPUT ;
    USE SIGNAL ;
    PORT
      LAYER M5 ;
        RECT  44.688 0 44.712 0.084 ;
    END
  END out_flit[153]
  PIN out_flit[154]
    DIRECTION OUTPUT ;
    USE SIGNAL ;
    PORT
      LAYER M5 ;
        RECT  44.784 0 44.808 0.084 ;
    END
  END out_flit[154]
  PIN out_flit[155]
    DIRECTION OUTPUT ;
    USE SIGNAL ;
    PORT
      LAYER M5 ;
        RECT  44.88 0 44.904 0.084 ;
    END
  END out_flit[155]
  PIN out_flit[156]
    DIRECTION OUTPUT ;
    USE SIGNAL ;
    PORT
      LAYER M5 ;
        RECT  44.976 0 45 0.084 ;
    END
  END out_flit[156]
  PIN out_flit[157]
    DIRECTION OUTPUT ;
    USE SIGNAL ;
    PORT
      LAYER M5 ;
        RECT  45.072 0 45.096 0.084 ;
    END
  END out_flit[157]
  PIN out_flit[158]
    DIRECTION OUTPUT ;
    USE SIGNAL ;
    PORT
      LAYER M5 ;
        RECT  45.168 0 45.192 0.084 ;
    END
  END out_flit[158]
  PIN out_flit[159]
    DIRECTION OUTPUT ;
    USE SIGNAL ;
    PORT
      LAYER M5 ;
        RECT  73.68 0 73.704 0.084 ;
    END
  END out_flit[159]
  PIN out_flit[15]
    DIRECTION OUTPUT ;
    USE SIGNAL ;
    PORT
      LAYER M5 ;
        RECT  46.8 0 46.824 0.084 ;
    END
  END out_flit[15]
  PIN out_flit[160]
    DIRECTION OUTPUT ;
    USE SIGNAL ;
    PORT
      LAYER M5 ;
        RECT  73.776 0 73.8 0.084 ;
    END
  END out_flit[160]
  PIN out_flit[161]
    DIRECTION OUTPUT ;
    USE SIGNAL ;
    PORT
      LAYER M5 ;
        RECT  73.872 0 73.896 0.084 ;
    END
  END out_flit[161]
  PIN out_flit[162]
    DIRECTION OUTPUT ;
    USE SIGNAL ;
    PORT
      LAYER M5 ;
        RECT  73.968 0 73.992 0.084 ;
    END
  END out_flit[162]
  PIN out_flit[163]
    DIRECTION OUTPUT ;
    USE SIGNAL ;
    PORT
      LAYER M5 ;
        RECT  74.064 0 74.088 0.084 ;
    END
  END out_flit[163]
  PIN out_flit[164]
    DIRECTION OUTPUT ;
    USE SIGNAL ;
    PORT
      LAYER M5 ;
        RECT  74.16 0 74.184 0.084 ;
    END
  END out_flit[164]
  PIN out_flit[165]
    DIRECTION OUTPUT ;
    USE SIGNAL ;
    PORT
      LAYER M5 ;
        RECT  74.256 0 74.28 0.084 ;
    END
  END out_flit[165]
  PIN out_flit[166]
    DIRECTION OUTPUT ;
    USE SIGNAL ;
    PORT
      LAYER M5 ;
        RECT  74.352 0 74.376 0.084 ;
    END
  END out_flit[166]
  PIN out_flit[167]
    DIRECTION OUTPUT ;
    USE SIGNAL ;
    PORT
      LAYER M5 ;
        RECT  74.448 0 74.472 0.084 ;
    END
  END out_flit[167]
  PIN out_flit[168]
    DIRECTION OUTPUT ;
    USE SIGNAL ;
    PORT
      LAYER M5 ;
        RECT  74.544 0 74.568 0.084 ;
    END
  END out_flit[168]
  PIN out_flit[169]
    DIRECTION OUTPUT ;
    USE SIGNAL ;
    PORT
      LAYER M5 ;
        RECT  74.64 0 74.664 0.084 ;
    END
  END out_flit[169]
  PIN out_flit[16]
    DIRECTION OUTPUT ;
    USE SIGNAL ;
    PORT
      LAYER M5 ;
        RECT  46.896 0 46.92 0.084 ;
    END
  END out_flit[16]
  PIN out_flit[170]
    DIRECTION OUTPUT ;
    USE SIGNAL ;
    PORT
      LAYER M5 ;
        RECT  74.736 0 74.76 0.084 ;
    END
  END out_flit[170]
  PIN out_flit[171]
    DIRECTION OUTPUT ;
    USE SIGNAL ;
    PORT
      LAYER M5 ;
        RECT  74.832 0 74.856 0.084 ;
    END
  END out_flit[171]
  PIN out_flit[172]
    DIRECTION OUTPUT ;
    USE SIGNAL ;
    PORT
      LAYER M5 ;
        RECT  74.928 0 74.952 0.084 ;
    END
  END out_flit[172]
  PIN out_flit[173]
    DIRECTION OUTPUT ;
    USE SIGNAL ;
    PORT
      LAYER M5 ;
        RECT  75.024 0 75.048 0.084 ;
    END
  END out_flit[173]
  PIN out_flit[174]
    DIRECTION OUTPUT ;
    USE SIGNAL ;
    PORT
      LAYER M5 ;
        RECT  75.12 0 75.144 0.084 ;
    END
  END out_flit[174]
  PIN out_flit[175]
    DIRECTION OUTPUT ;
    USE SIGNAL ;
    PORT
      LAYER M5 ;
        RECT  75.216 0 75.24 0.084 ;
    END
  END out_flit[175]
  PIN out_flit[176]
    DIRECTION OUTPUT ;
    USE SIGNAL ;
    PORT
      LAYER M5 ;
        RECT  75.312 0 75.336 0.084 ;
    END
  END out_flit[176]
  PIN out_flit[177]
    DIRECTION OUTPUT ;
    USE SIGNAL ;
    PORT
      LAYER M5 ;
        RECT  75.408 0 75.432 0.084 ;
    END
  END out_flit[177]
  PIN out_flit[178]
    DIRECTION OUTPUT ;
    USE SIGNAL ;
    PORT
      LAYER M5 ;
        RECT  75.504 0 75.528 0.084 ;
    END
  END out_flit[178]
  PIN out_flit[179]
    DIRECTION OUTPUT ;
    USE SIGNAL ;
    PORT
      LAYER M5 ;
        RECT  75.6 0 75.624 0.084 ;
    END
  END out_flit[179]
  PIN out_flit[17]
    DIRECTION OUTPUT ;
    USE SIGNAL ;
    PORT
      LAYER M5 ;
        RECT  46.992 0 47.016 0.084 ;
    END
  END out_flit[17]
  PIN out_flit[180]
    DIRECTION OUTPUT ;
    USE SIGNAL ;
    PORT
      LAYER M5 ;
        RECT  75.696 0 75.72 0.084 ;
    END
  END out_flit[180]
  PIN out_flit[181]
    DIRECTION OUTPUT ;
    USE SIGNAL ;
    PORT
      LAYER M5 ;
        RECT  75.792 0 75.816 0.084 ;
    END
  END out_flit[181]
  PIN out_flit[182]
    DIRECTION OUTPUT ;
    USE SIGNAL ;
    PORT
      LAYER M5 ;
        RECT  75.888 0 75.912 0.084 ;
    END
  END out_flit[182]
  PIN out_flit[183]
    DIRECTION OUTPUT ;
    USE SIGNAL ;
    PORT
      LAYER M5 ;
        RECT  75.984 0 76.008 0.084 ;
    END
  END out_flit[183]
  PIN out_flit[184]
    DIRECTION OUTPUT ;
    USE SIGNAL ;
    PORT
      LAYER M5 ;
        RECT  76.08 0 76.104 0.084 ;
    END
  END out_flit[184]
  PIN out_flit[185]
    DIRECTION OUTPUT ;
    USE SIGNAL ;
    PORT
      LAYER M5 ;
        RECT  76.176 0 76.2 0.084 ;
    END
  END out_flit[185]
  PIN out_flit[186]
    DIRECTION OUTPUT ;
    USE SIGNAL ;
    PORT
      LAYER M5 ;
        RECT  76.272 0 76.296 0.084 ;
    END
  END out_flit[186]
  PIN out_flit[187]
    DIRECTION OUTPUT ;
    USE SIGNAL ;
    PORT
      LAYER M5 ;
        RECT  76.368 0 76.392 0.084 ;
    END
  END out_flit[187]
  PIN out_flit[188]
    DIRECTION OUTPUT ;
    USE SIGNAL ;
    PORT
      LAYER M5 ;
        RECT  76.464 0 76.488 0.084 ;
    END
  END out_flit[188]
  PIN out_flit[189]
    DIRECTION OUTPUT ;
    USE SIGNAL ;
    PORT
      LAYER M5 ;
        RECT  76.56 0 76.584 0.084 ;
    END
  END out_flit[189]
  PIN out_flit[18]
    DIRECTION OUTPUT ;
    USE SIGNAL ;
    PORT
      LAYER M5 ;
        RECT  47.088 0 47.112 0.084 ;
    END
  END out_flit[18]
  PIN out_flit[190]
    DIRECTION OUTPUT ;
    USE SIGNAL ;
    PORT
      LAYER M5 ;
        RECT  76.656 0 76.68 0.084 ;
    END
  END out_flit[190]
  PIN out_flit[191]
    DIRECTION OUTPUT ;
    USE SIGNAL ;
    PORT
      LAYER M5 ;
        RECT  51.408 0 51.432 0.084 ;
    END
  END out_flit[191]
  PIN out_flit[192]
    DIRECTION OUTPUT ;
    USE SIGNAL ;
    PORT
      LAYER M5 ;
        RECT  51.504 0 51.528 0.084 ;
    END
  END out_flit[192]
  PIN out_flit[193]
    DIRECTION OUTPUT ;
    USE SIGNAL ;
    PORT
      LAYER M5 ;
        RECT  51.6 0 51.624 0.084 ;
    END
  END out_flit[193]
  PIN out_flit[194]
    DIRECTION OUTPUT ;
    USE SIGNAL ;
    PORT
      LAYER M5 ;
        RECT  51.696 0 51.72 0.084 ;
    END
  END out_flit[194]
  PIN out_flit[195]
    DIRECTION OUTPUT ;
    USE SIGNAL ;
    PORT
      LAYER M5 ;
        RECT  51.792 0 51.816 0.084 ;
    END
  END out_flit[195]
  PIN out_flit[196]
    DIRECTION OUTPUT ;
    USE SIGNAL ;
    PORT
      LAYER M5 ;
        RECT  51.888 0 51.912 0.084 ;
    END
  END out_flit[196]
  PIN out_flit[197]
    DIRECTION OUTPUT ;
    USE SIGNAL ;
    PORT
      LAYER M5 ;
        RECT  51.984 0 52.008 0.084 ;
    END
  END out_flit[197]
  PIN out_flit[198]
    DIRECTION OUTPUT ;
    USE SIGNAL ;
    PORT
      LAYER M5 ;
        RECT  52.08 0 52.104 0.084 ;
    END
  END out_flit[198]
  PIN out_flit[199]
    DIRECTION OUTPUT ;
    USE SIGNAL ;
    PORT
      LAYER M5 ;
        RECT  52.176 0 52.2 0.084 ;
    END
  END out_flit[199]
  PIN out_flit[19]
    DIRECTION OUTPUT ;
    USE SIGNAL ;
    PORT
      LAYER M5 ;
        RECT  47.184 0 47.208 0.084 ;
    END
  END out_flit[19]
  PIN out_flit[1]
    DIRECTION OUTPUT ;
    USE SIGNAL ;
    PORT
      LAYER M5 ;
        RECT  45.456 0 45.48 0.084 ;
    END
  END out_flit[1]
  PIN out_flit[200]
    DIRECTION OUTPUT ;
    USE SIGNAL ;
    PORT
      LAYER M5 ;
        RECT  52.272 0 52.296 0.084 ;
    END
  END out_flit[200]
  PIN out_flit[201]
    DIRECTION OUTPUT ;
    USE SIGNAL ;
    PORT
      LAYER M5 ;
        RECT  52.368 0 52.392 0.084 ;
    END
  END out_flit[201]
  PIN out_flit[202]
    DIRECTION OUTPUT ;
    USE SIGNAL ;
    PORT
      LAYER M5 ;
        RECT  52.464 0 52.488 0.084 ;
    END
  END out_flit[202]
  PIN out_flit[203]
    DIRECTION OUTPUT ;
    USE SIGNAL ;
    PORT
      LAYER M5 ;
        RECT  52.56 0 52.584 0.084 ;
    END
  END out_flit[203]
  PIN out_flit[204]
    DIRECTION OUTPUT ;
    USE SIGNAL ;
    PORT
      LAYER M5 ;
        RECT  52.656 0 52.68 0.084 ;
    END
  END out_flit[204]
  PIN out_flit[205]
    DIRECTION OUTPUT ;
    USE SIGNAL ;
    PORT
      LAYER M5 ;
        RECT  52.752 0 52.776 0.084 ;
    END
  END out_flit[205]
  PIN out_flit[206]
    DIRECTION OUTPUT ;
    USE SIGNAL ;
    PORT
      LAYER M5 ;
        RECT  52.848 0 52.872 0.084 ;
    END
  END out_flit[206]
  PIN out_flit[207]
    DIRECTION OUTPUT ;
    USE SIGNAL ;
    PORT
      LAYER M5 ;
        RECT  52.944 0 52.968 0.084 ;
    END
  END out_flit[207]
  PIN out_flit[208]
    DIRECTION OUTPUT ;
    USE SIGNAL ;
    PORT
      LAYER M5 ;
        RECT  53.04 0 53.064 0.084 ;
    END
  END out_flit[208]
  PIN out_flit[209]
    DIRECTION OUTPUT ;
    USE SIGNAL ;
    PORT
      LAYER M5 ;
        RECT  53.136 0 53.16 0.084 ;
    END
  END out_flit[209]
  PIN out_flit[20]
    DIRECTION OUTPUT ;
    USE SIGNAL ;
    PORT
      LAYER M5 ;
        RECT  47.28 0 47.304 0.084 ;
    END
  END out_flit[20]
  PIN out_flit[210]
    DIRECTION OUTPUT ;
    USE SIGNAL ;
    PORT
      LAYER M5 ;
        RECT  53.232 0 53.256 0.084 ;
    END
  END out_flit[210]
  PIN out_flit[211]
    DIRECTION OUTPUT ;
    USE SIGNAL ;
    PORT
      LAYER M5 ;
        RECT  53.328 0 53.352 0.084 ;
    END
  END out_flit[211]
  PIN out_flit[212]
    DIRECTION OUTPUT ;
    USE SIGNAL ;
    PORT
      LAYER M5 ;
        RECT  53.424 0 53.448 0.084 ;
    END
  END out_flit[212]
  PIN out_flit[213]
    DIRECTION OUTPUT ;
    USE SIGNAL ;
    PORT
      LAYER M5 ;
        RECT  53.52 0 53.544 0.084 ;
    END
  END out_flit[213]
  PIN out_flit[214]
    DIRECTION OUTPUT ;
    USE SIGNAL ;
    PORT
      LAYER M5 ;
        RECT  53.616 0 53.64 0.084 ;
    END
  END out_flit[214]
  PIN out_flit[215]
    DIRECTION OUTPUT ;
    USE SIGNAL ;
    PORT
      LAYER M5 ;
        RECT  53.712 0 53.736 0.084 ;
    END
  END out_flit[215]
  PIN out_flit[216]
    DIRECTION OUTPUT ;
    USE SIGNAL ;
    PORT
      LAYER M5 ;
        RECT  53.808 0 53.832 0.084 ;
    END
  END out_flit[216]
  PIN out_flit[217]
    DIRECTION OUTPUT ;
    USE SIGNAL ;
    PORT
      LAYER M5 ;
        RECT  53.904 0 53.928 0.084 ;
    END
  END out_flit[217]
  PIN out_flit[218]
    DIRECTION OUTPUT ;
    USE SIGNAL ;
    PORT
      LAYER M5 ;
        RECT  54 0 54.024 0.084 ;
    END
  END out_flit[218]
  PIN out_flit[219]
    DIRECTION OUTPUT ;
    USE SIGNAL ;
    PORT
      LAYER M5 ;
        RECT  54.096 0 54.12 0.084 ;
    END
  END out_flit[219]
  PIN out_flit[21]
    DIRECTION OUTPUT ;
    USE SIGNAL ;
    PORT
      LAYER M5 ;
        RECT  47.376 0 47.4 0.084 ;
    END
  END out_flit[21]
  PIN out_flit[220]
    DIRECTION OUTPUT ;
    USE SIGNAL ;
    PORT
      LAYER M5 ;
        RECT  54.192 0 54.216 0.084 ;
    END
  END out_flit[220]
  PIN out_flit[221]
    DIRECTION OUTPUT ;
    USE SIGNAL ;
    PORT
      LAYER M5 ;
        RECT  54.288 0 54.312 0.084 ;
    END
  END out_flit[221]
  PIN out_flit[222]
    DIRECTION OUTPUT ;
    USE SIGNAL ;
    PORT
      LAYER M5 ;
        RECT  54.384 0 54.408 0.084 ;
    END
  END out_flit[222]
  PIN out_flit[223]
    DIRECTION OUTPUT ;
    USE SIGNAL ;
    PORT
      LAYER M5 ;
        RECT  32.208 0 32.232 0.084 ;
    END
  END out_flit[223]
  PIN out_flit[224]
    DIRECTION OUTPUT ;
    USE SIGNAL ;
    PORT
      LAYER M5 ;
        RECT  32.304 0 32.328 0.084 ;
    END
  END out_flit[224]
  PIN out_flit[225]
    DIRECTION OUTPUT ;
    USE SIGNAL ;
    PORT
      LAYER M5 ;
        RECT  32.4 0 32.424 0.084 ;
    END
  END out_flit[225]
  PIN out_flit[226]
    DIRECTION OUTPUT ;
    USE SIGNAL ;
    PORT
      LAYER M5 ;
        RECT  32.496 0 32.52 0.084 ;
    END
  END out_flit[226]
  PIN out_flit[227]
    DIRECTION OUTPUT ;
    USE SIGNAL ;
    PORT
      LAYER M5 ;
        RECT  32.592 0 32.616 0.084 ;
    END
  END out_flit[227]
  PIN out_flit[228]
    DIRECTION OUTPUT ;
    USE SIGNAL ;
    PORT
      LAYER M5 ;
        RECT  32.688 0 32.712 0.084 ;
    END
  END out_flit[228]
  PIN out_flit[229]
    DIRECTION OUTPUT ;
    USE SIGNAL ;
    PORT
      LAYER M5 ;
        RECT  32.784 0 32.808 0.084 ;
    END
  END out_flit[229]
  PIN out_flit[22]
    DIRECTION OUTPUT ;
    USE SIGNAL ;
    PORT
      LAYER M5 ;
        RECT  47.472 0 47.496 0.084 ;
    END
  END out_flit[22]
  PIN out_flit[230]
    DIRECTION OUTPUT ;
    USE SIGNAL ;
    PORT
      LAYER M5 ;
        RECT  32.88 0 32.904 0.084 ;
    END
  END out_flit[230]
  PIN out_flit[231]
    DIRECTION OUTPUT ;
    USE SIGNAL ;
    PORT
      LAYER M5 ;
        RECT  32.976 0 33 0.084 ;
    END
  END out_flit[231]
  PIN out_flit[232]
    DIRECTION OUTPUT ;
    USE SIGNAL ;
    PORT
      LAYER M5 ;
        RECT  33.072 0 33.096 0.084 ;
    END
  END out_flit[232]
  PIN out_flit[233]
    DIRECTION OUTPUT ;
    USE SIGNAL ;
    PORT
      LAYER M5 ;
        RECT  33.168 0 33.192 0.084 ;
    END
  END out_flit[233]
  PIN out_flit[234]
    DIRECTION OUTPUT ;
    USE SIGNAL ;
    PORT
      LAYER M5 ;
        RECT  33.264 0 33.288 0.084 ;
    END
  END out_flit[234]
  PIN out_flit[235]
    DIRECTION OUTPUT ;
    USE SIGNAL ;
    PORT
      LAYER M5 ;
        RECT  33.36 0 33.384 0.084 ;
    END
  END out_flit[235]
  PIN out_flit[236]
    DIRECTION OUTPUT ;
    USE SIGNAL ;
    PORT
      LAYER M5 ;
        RECT  33.456 0 33.48 0.084 ;
    END
  END out_flit[236]
  PIN out_flit[237]
    DIRECTION OUTPUT ;
    USE SIGNAL ;
    PORT
      LAYER M5 ;
        RECT  33.552 0 33.576 0.084 ;
    END
  END out_flit[237]
  PIN out_flit[238]
    DIRECTION OUTPUT ;
    USE SIGNAL ;
    PORT
      LAYER M5 ;
        RECT  33.648 0 33.672 0.084 ;
    END
  END out_flit[238]
  PIN out_flit[239]
    DIRECTION OUTPUT ;
    USE SIGNAL ;
    PORT
      LAYER M5 ;
        RECT  33.744 0 33.768 0.084 ;
    END
  END out_flit[239]
  PIN out_flit[23]
    DIRECTION OUTPUT ;
    USE SIGNAL ;
    PORT
      LAYER M5 ;
        RECT  47.568 0 47.592 0.084 ;
    END
  END out_flit[23]
  PIN out_flit[240]
    DIRECTION OUTPUT ;
    USE SIGNAL ;
    PORT
      LAYER M5 ;
        RECT  33.84 0 33.864 0.084 ;
    END
  END out_flit[240]
  PIN out_flit[241]
    DIRECTION OUTPUT ;
    USE SIGNAL ;
    PORT
      LAYER M5 ;
        RECT  33.936 0 33.96 0.084 ;
    END
  END out_flit[241]
  PIN out_flit[242]
    DIRECTION OUTPUT ;
    USE SIGNAL ;
    PORT
      LAYER M5 ;
        RECT  34.032 0 34.056 0.084 ;
    END
  END out_flit[242]
  PIN out_flit[243]
    DIRECTION OUTPUT ;
    USE SIGNAL ;
    PORT
      LAYER M5 ;
        RECT  34.128 0 34.152 0.084 ;
    END
  END out_flit[243]
  PIN out_flit[244]
    DIRECTION OUTPUT ;
    USE SIGNAL ;
    PORT
      LAYER M5 ;
        RECT  34.224 0 34.248 0.084 ;
    END
  END out_flit[244]
  PIN out_flit[245]
    DIRECTION OUTPUT ;
    USE SIGNAL ;
    PORT
      LAYER M5 ;
        RECT  34.32 0 34.344 0.084 ;
    END
  END out_flit[245]
  PIN out_flit[246]
    DIRECTION OUTPUT ;
    USE SIGNAL ;
    PORT
      LAYER M5 ;
        RECT  34.416 0 34.44 0.084 ;
    END
  END out_flit[246]
  PIN out_flit[247]
    DIRECTION OUTPUT ;
    USE SIGNAL ;
    PORT
      LAYER M5 ;
        RECT  34.512 0 34.536 0.084 ;
    END
  END out_flit[247]
  PIN out_flit[248]
    DIRECTION OUTPUT ;
    USE SIGNAL ;
    PORT
      LAYER M5 ;
        RECT  34.608 0 34.632 0.084 ;
    END
  END out_flit[248]
  PIN out_flit[249]
    DIRECTION OUTPUT ;
    USE SIGNAL ;
    PORT
      LAYER M5 ;
        RECT  34.704 0 34.728 0.084 ;
    END
  END out_flit[249]
  PIN out_flit[24]
    DIRECTION OUTPUT ;
    USE SIGNAL ;
    PORT
      LAYER M5 ;
        RECT  47.664 0 47.688 0.084 ;
    END
  END out_flit[24]
  PIN out_flit[250]
    DIRECTION OUTPUT ;
    USE SIGNAL ;
    PORT
      LAYER M5 ;
        RECT  34.8 0 34.824 0.084 ;
    END
  END out_flit[250]
  PIN out_flit[251]
    DIRECTION OUTPUT ;
    USE SIGNAL ;
    PORT
      LAYER M5 ;
        RECT  34.896 0 34.92 0.084 ;
    END
  END out_flit[251]
  PIN out_flit[252]
    DIRECTION OUTPUT ;
    USE SIGNAL ;
    PORT
      LAYER M5 ;
        RECT  34.992 0 35.016 0.084 ;
    END
  END out_flit[252]
  PIN out_flit[253]
    DIRECTION OUTPUT ;
    USE SIGNAL ;
    PORT
      LAYER M5 ;
        RECT  35.088 0 35.112 0.084 ;
    END
  END out_flit[253]
  PIN out_flit[254]
    DIRECTION OUTPUT ;
    USE SIGNAL ;
    PORT
      LAYER M5 ;
        RECT  35.184 0 35.208 0.084 ;
    END
  END out_flit[254]
  PIN out_flit[255]
    DIRECTION OUTPUT ;
    USE SIGNAL ;
    PORT
      LAYER M5 ;
        RECT  67.536 0 67.56 0.084 ;
    END
  END out_flit[255]
  PIN out_flit[256]
    DIRECTION OUTPUT ;
    USE SIGNAL ;
    PORT
      LAYER M5 ;
        RECT  67.632 0 67.656 0.084 ;
    END
  END out_flit[256]
  PIN out_flit[257]
    DIRECTION OUTPUT ;
    USE SIGNAL ;
    PORT
      LAYER M5 ;
        RECT  67.728 0 67.752 0.084 ;
    END
  END out_flit[257]
  PIN out_flit[258]
    DIRECTION OUTPUT ;
    USE SIGNAL ;
    PORT
      LAYER M5 ;
        RECT  67.824 0 67.848 0.084 ;
    END
  END out_flit[258]
  PIN out_flit[259]
    DIRECTION OUTPUT ;
    USE SIGNAL ;
    PORT
      LAYER M5 ;
        RECT  67.92 0 67.944 0.084 ;
    END
  END out_flit[259]
  PIN out_flit[25]
    DIRECTION OUTPUT ;
    USE SIGNAL ;
    PORT
      LAYER M5 ;
        RECT  47.76 0 47.784 0.084 ;
    END
  END out_flit[25]
  PIN out_flit[260]
    DIRECTION OUTPUT ;
    USE SIGNAL ;
    PORT
      LAYER M5 ;
        RECT  68.016 0 68.04 0.084 ;
    END
  END out_flit[260]
  PIN out_flit[261]
    DIRECTION OUTPUT ;
    USE SIGNAL ;
    PORT
      LAYER M5 ;
        RECT  68.112 0 68.136 0.084 ;
    END
  END out_flit[261]
  PIN out_flit[262]
    DIRECTION OUTPUT ;
    USE SIGNAL ;
    PORT
      LAYER M5 ;
        RECT  68.208 0 68.232 0.084 ;
    END
  END out_flit[262]
  PIN out_flit[263]
    DIRECTION OUTPUT ;
    USE SIGNAL ;
    PORT
      LAYER M5 ;
        RECT  68.304 0 68.328 0.084 ;
    END
  END out_flit[263]
  PIN out_flit[264]
    DIRECTION OUTPUT ;
    USE SIGNAL ;
    PORT
      LAYER M5 ;
        RECT  68.4 0 68.424 0.084 ;
    END
  END out_flit[264]
  PIN out_flit[265]
    DIRECTION OUTPUT ;
    USE SIGNAL ;
    PORT
      LAYER M5 ;
        RECT  68.496 0 68.52 0.084 ;
    END
  END out_flit[265]
  PIN out_flit[266]
    DIRECTION OUTPUT ;
    USE SIGNAL ;
    PORT
      LAYER M5 ;
        RECT  68.592 0 68.616 0.084 ;
    END
  END out_flit[266]
  PIN out_flit[267]
    DIRECTION OUTPUT ;
    USE SIGNAL ;
    PORT
      LAYER M5 ;
        RECT  68.688 0 68.712 0.084 ;
    END
  END out_flit[267]
  PIN out_flit[268]
    DIRECTION OUTPUT ;
    USE SIGNAL ;
    PORT
      LAYER M5 ;
        RECT  68.784 0 68.808 0.084 ;
    END
  END out_flit[268]
  PIN out_flit[269]
    DIRECTION OUTPUT ;
    USE SIGNAL ;
    PORT
      LAYER M5 ;
        RECT  68.88 0 68.904 0.084 ;
    END
  END out_flit[269]
  PIN out_flit[26]
    DIRECTION OUTPUT ;
    USE SIGNAL ;
    PORT
      LAYER M5 ;
        RECT  47.856 0 47.88 0.084 ;
    END
  END out_flit[26]
  PIN out_flit[270]
    DIRECTION OUTPUT ;
    USE SIGNAL ;
    PORT
      LAYER M5 ;
        RECT  68.976 0 69 0.084 ;
    END
  END out_flit[270]
  PIN out_flit[271]
    DIRECTION OUTPUT ;
    USE SIGNAL ;
    PORT
      LAYER M5 ;
        RECT  69.072 0 69.096 0.084 ;
    END
  END out_flit[271]
  PIN out_flit[272]
    DIRECTION OUTPUT ;
    USE SIGNAL ;
    PORT
      LAYER M5 ;
        RECT  69.168 0 69.192 0.084 ;
    END
  END out_flit[272]
  PIN out_flit[273]
    DIRECTION OUTPUT ;
    USE SIGNAL ;
    PORT
      LAYER M5 ;
        RECT  69.264 0 69.288 0.084 ;
    END
  END out_flit[273]
  PIN out_flit[274]
    DIRECTION OUTPUT ;
    USE SIGNAL ;
    PORT
      LAYER M5 ;
        RECT  69.36 0 69.384 0.084 ;
    END
  END out_flit[274]
  PIN out_flit[275]
    DIRECTION OUTPUT ;
    USE SIGNAL ;
    PORT
      LAYER M5 ;
        RECT  69.456 0 69.48 0.084 ;
    END
  END out_flit[275]
  PIN out_flit[276]
    DIRECTION OUTPUT ;
    USE SIGNAL ;
    PORT
      LAYER M5 ;
        RECT  69.552 0 69.576 0.084 ;
    END
  END out_flit[276]
  PIN out_flit[277]
    DIRECTION OUTPUT ;
    USE SIGNAL ;
    PORT
      LAYER M5 ;
        RECT  69.648 0 69.672 0.084 ;
    END
  END out_flit[277]
  PIN out_flit[278]
    DIRECTION OUTPUT ;
    USE SIGNAL ;
    PORT
      LAYER M5 ;
        RECT  69.744 0 69.768 0.084 ;
    END
  END out_flit[278]
  PIN out_flit[279]
    DIRECTION OUTPUT ;
    USE SIGNAL ;
    PORT
      LAYER M5 ;
        RECT  69.84 0 69.864 0.084 ;
    END
  END out_flit[279]
  PIN out_flit[27]
    DIRECTION OUTPUT ;
    USE SIGNAL ;
    PORT
      LAYER M5 ;
        RECT  47.952 0 47.976 0.084 ;
    END
  END out_flit[27]
  PIN out_flit[280]
    DIRECTION OUTPUT ;
    USE SIGNAL ;
    PORT
      LAYER M5 ;
        RECT  69.936 0 69.96 0.084 ;
    END
  END out_flit[280]
  PIN out_flit[281]
    DIRECTION OUTPUT ;
    USE SIGNAL ;
    PORT
      LAYER M5 ;
        RECT  70.032 0 70.056 0.084 ;
    END
  END out_flit[281]
  PIN out_flit[282]
    DIRECTION OUTPUT ;
    USE SIGNAL ;
    PORT
      LAYER M5 ;
        RECT  70.128 0 70.152 0.084 ;
    END
  END out_flit[282]
  PIN out_flit[283]
    DIRECTION OUTPUT ;
    USE SIGNAL ;
    PORT
      LAYER M5 ;
        RECT  70.224 0 70.248 0.084 ;
    END
  END out_flit[283]
  PIN out_flit[284]
    DIRECTION OUTPUT ;
    USE SIGNAL ;
    PORT
      LAYER M5 ;
        RECT  70.32 0 70.344 0.084 ;
    END
  END out_flit[284]
  PIN out_flit[285]
    DIRECTION OUTPUT ;
    USE SIGNAL ;
    PORT
      LAYER M5 ;
        RECT  70.416 0 70.44 0.084 ;
    END
  END out_flit[285]
  PIN out_flit[286]
    DIRECTION OUTPUT ;
    USE SIGNAL ;
    PORT
      LAYER M5 ;
        RECT  70.512 0 70.536 0.084 ;
    END
  END out_flit[286]
  PIN out_flit[287]
    DIRECTION OUTPUT ;
    USE SIGNAL ;
    PORT
      LAYER M5 ;
        RECT  64.464 0 64.488 0.084 ;
    END
  END out_flit[287]
  PIN out_flit[288]
    DIRECTION OUTPUT ;
    USE SIGNAL ;
    PORT
      LAYER M5 ;
        RECT  64.56 0 64.584 0.084 ;
    END
  END out_flit[288]
  PIN out_flit[289]
    DIRECTION OUTPUT ;
    USE SIGNAL ;
    PORT
      LAYER M5 ;
        RECT  64.656 0 64.68 0.084 ;
    END
  END out_flit[289]
  PIN out_flit[28]
    DIRECTION OUTPUT ;
    USE SIGNAL ;
    PORT
      LAYER M5 ;
        RECT  48.048 0 48.072 0.084 ;
    END
  END out_flit[28]
  PIN out_flit[290]
    DIRECTION OUTPUT ;
    USE SIGNAL ;
    PORT
      LAYER M5 ;
        RECT  64.752 0 64.776 0.084 ;
    END
  END out_flit[290]
  PIN out_flit[291]
    DIRECTION OUTPUT ;
    USE SIGNAL ;
    PORT
      LAYER M5 ;
        RECT  64.848 0 64.872 0.084 ;
    END
  END out_flit[291]
  PIN out_flit[292]
    DIRECTION OUTPUT ;
    USE SIGNAL ;
    PORT
      LAYER M5 ;
        RECT  64.944 0 64.968 0.084 ;
    END
  END out_flit[292]
  PIN out_flit[293]
    DIRECTION OUTPUT ;
    USE SIGNAL ;
    PORT
      LAYER M5 ;
        RECT  65.04 0 65.064 0.084 ;
    END
  END out_flit[293]
  PIN out_flit[294]
    DIRECTION OUTPUT ;
    USE SIGNAL ;
    PORT
      LAYER M5 ;
        RECT  65.136 0 65.16 0.084 ;
    END
  END out_flit[294]
  PIN out_flit[295]
    DIRECTION OUTPUT ;
    USE SIGNAL ;
    PORT
      LAYER M5 ;
        RECT  65.232 0 65.256 0.084 ;
    END
  END out_flit[295]
  PIN out_flit[296]
    DIRECTION OUTPUT ;
    USE SIGNAL ;
    PORT
      LAYER M5 ;
        RECT  65.328 0 65.352 0.084 ;
    END
  END out_flit[296]
  PIN out_flit[297]
    DIRECTION OUTPUT ;
    USE SIGNAL ;
    PORT
      LAYER M5 ;
        RECT  65.424 0 65.448 0.084 ;
    END
  END out_flit[297]
  PIN out_flit[298]
    DIRECTION OUTPUT ;
    USE SIGNAL ;
    PORT
      LAYER M5 ;
        RECT  65.52 0 65.544 0.084 ;
    END
  END out_flit[298]
  PIN out_flit[299]
    DIRECTION OUTPUT ;
    USE SIGNAL ;
    PORT
      LAYER M5 ;
        RECT  65.616 0 65.64 0.084 ;
    END
  END out_flit[299]
  PIN out_flit[29]
    DIRECTION OUTPUT ;
    USE SIGNAL ;
    PORT
      LAYER M5 ;
        RECT  48.144 0 48.168 0.084 ;
    END
  END out_flit[29]
  PIN out_flit[2]
    DIRECTION OUTPUT ;
    USE SIGNAL ;
    PORT
      LAYER M5 ;
        RECT  45.552 0 45.576 0.084 ;
    END
  END out_flit[2]
  PIN out_flit[300]
    DIRECTION OUTPUT ;
    USE SIGNAL ;
    PORT
      LAYER M5 ;
        RECT  65.712 0 65.736 0.084 ;
    END
  END out_flit[300]
  PIN out_flit[301]
    DIRECTION OUTPUT ;
    USE SIGNAL ;
    PORT
      LAYER M5 ;
        RECT  65.808 0 65.832 0.084 ;
    END
  END out_flit[301]
  PIN out_flit[302]
    DIRECTION OUTPUT ;
    USE SIGNAL ;
    PORT
      LAYER M5 ;
        RECT  65.904 0 65.928 0.084 ;
    END
  END out_flit[302]
  PIN out_flit[303]
    DIRECTION OUTPUT ;
    USE SIGNAL ;
    PORT
      LAYER M5 ;
        RECT  66 0 66.024 0.084 ;
    END
  END out_flit[303]
  PIN out_flit[304]
    DIRECTION OUTPUT ;
    USE SIGNAL ;
    PORT
      LAYER M5 ;
        RECT  66.096 0 66.12 0.084 ;
    END
  END out_flit[304]
  PIN out_flit[305]
    DIRECTION OUTPUT ;
    USE SIGNAL ;
    PORT
      LAYER M5 ;
        RECT  66.192 0 66.216 0.084 ;
    END
  END out_flit[305]
  PIN out_flit[306]
    DIRECTION OUTPUT ;
    USE SIGNAL ;
    PORT
      LAYER M5 ;
        RECT  66.288 0 66.312 0.084 ;
    END
  END out_flit[306]
  PIN out_flit[307]
    DIRECTION OUTPUT ;
    USE SIGNAL ;
    PORT
      LAYER M5 ;
        RECT  66.384 0 66.408 0.084 ;
    END
  END out_flit[307]
  PIN out_flit[308]
    DIRECTION OUTPUT ;
    USE SIGNAL ;
    PORT
      LAYER M5 ;
        RECT  66.48 0 66.504 0.084 ;
    END
  END out_flit[308]
  PIN out_flit[309]
    DIRECTION OUTPUT ;
    USE SIGNAL ;
    PORT
      LAYER M5 ;
        RECT  66.576 0 66.6 0.084 ;
    END
  END out_flit[309]
  PIN out_flit[30]
    DIRECTION OUTPUT ;
    USE SIGNAL ;
    PORT
      LAYER M5 ;
        RECT  48.24 0 48.264 0.084 ;
    END
  END out_flit[30]
  PIN out_flit[310]
    DIRECTION OUTPUT ;
    USE SIGNAL ;
    PORT
      LAYER M5 ;
        RECT  66.672 0 66.696 0.084 ;
    END
  END out_flit[310]
  PIN out_flit[311]
    DIRECTION OUTPUT ;
    USE SIGNAL ;
    PORT
      LAYER M5 ;
        RECT  66.768 0 66.792 0.084 ;
    END
  END out_flit[311]
  PIN out_flit[312]
    DIRECTION OUTPUT ;
    USE SIGNAL ;
    PORT
      LAYER M5 ;
        RECT  66.864 0 66.888 0.084 ;
    END
  END out_flit[312]
  PIN out_flit[313]
    DIRECTION OUTPUT ;
    USE SIGNAL ;
    PORT
      LAYER M5 ;
        RECT  66.96 0 66.984 0.084 ;
    END
  END out_flit[313]
  PIN out_flit[314]
    DIRECTION OUTPUT ;
    USE SIGNAL ;
    PORT
      LAYER M5 ;
        RECT  67.056 0 67.08 0.084 ;
    END
  END out_flit[314]
  PIN out_flit[315]
    DIRECTION OUTPUT ;
    USE SIGNAL ;
    PORT
      LAYER M5 ;
        RECT  67.152 0 67.176 0.084 ;
    END
  END out_flit[315]
  PIN out_flit[316]
    DIRECTION OUTPUT ;
    USE SIGNAL ;
    PORT
      LAYER M5 ;
        RECT  67.248 0 67.272 0.084 ;
    END
  END out_flit[316]
  PIN out_flit[317]
    DIRECTION OUTPUT ;
    USE SIGNAL ;
    PORT
      LAYER M5 ;
        RECT  67.344 0 67.368 0.084 ;
    END
  END out_flit[317]
  PIN out_flit[318]
    DIRECTION OUTPUT ;
    USE SIGNAL ;
    PORT
      LAYER M5 ;
        RECT  67.44 0 67.464 0.084 ;
    END
  END out_flit[318]
  PIN out_flit[319]
    DIRECTION OUTPUT ;
    USE SIGNAL ;
    PORT
      LAYER M5 ;
        RECT  70.608 0 70.632 0.084 ;
    END
  END out_flit[319]
  PIN out_flit[31]
    DIRECTION OUTPUT ;
    USE SIGNAL ;
    PORT
      LAYER M5 ;
        RECT  39.12 0 39.144 0.084 ;
    END
  END out_flit[31]
  PIN out_flit[320]
    DIRECTION OUTPUT ;
    USE SIGNAL ;
    PORT
      LAYER M5 ;
        RECT  70.704 0 70.728 0.084 ;
    END
  END out_flit[320]
  PIN out_flit[321]
    DIRECTION OUTPUT ;
    USE SIGNAL ;
    PORT
      LAYER M5 ;
        RECT  70.8 0 70.824 0.084 ;
    END
  END out_flit[321]
  PIN out_flit[322]
    DIRECTION OUTPUT ;
    USE SIGNAL ;
    PORT
      LAYER M5 ;
        RECT  70.896 0 70.92 0.084 ;
    END
  END out_flit[322]
  PIN out_flit[323]
    DIRECTION OUTPUT ;
    USE SIGNAL ;
    PORT
      LAYER M5 ;
        RECT  70.992 0 71.016 0.084 ;
    END
  END out_flit[323]
  PIN out_flit[324]
    DIRECTION OUTPUT ;
    USE SIGNAL ;
    PORT
      LAYER M5 ;
        RECT  71.088 0 71.112 0.084 ;
    END
  END out_flit[324]
  PIN out_flit[325]
    DIRECTION OUTPUT ;
    USE SIGNAL ;
    PORT
      LAYER M5 ;
        RECT  71.184 0 71.208 0.084 ;
    END
  END out_flit[325]
  PIN out_flit[326]
    DIRECTION OUTPUT ;
    USE SIGNAL ;
    PORT
      LAYER M5 ;
        RECT  71.28 0 71.304 0.084 ;
    END
  END out_flit[326]
  PIN out_flit[327]
    DIRECTION OUTPUT ;
    USE SIGNAL ;
    PORT
      LAYER M5 ;
        RECT  71.376 0 71.4 0.084 ;
    END
  END out_flit[327]
  PIN out_flit[328]
    DIRECTION OUTPUT ;
    USE SIGNAL ;
    PORT
      LAYER M5 ;
        RECT  71.472 0 71.496 0.084 ;
    END
  END out_flit[328]
  PIN out_flit[329]
    DIRECTION OUTPUT ;
    USE SIGNAL ;
    PORT
      LAYER M5 ;
        RECT  71.568 0 71.592 0.084 ;
    END
  END out_flit[329]
  PIN out_flit[32]
    DIRECTION OUTPUT ;
    USE SIGNAL ;
    PORT
      LAYER M5 ;
        RECT  39.216 0 39.24 0.084 ;
    END
  END out_flit[32]
  PIN out_flit[330]
    DIRECTION OUTPUT ;
    USE SIGNAL ;
    PORT
      LAYER M5 ;
        RECT  71.664 0 71.688 0.084 ;
    END
  END out_flit[330]
  PIN out_flit[331]
    DIRECTION OUTPUT ;
    USE SIGNAL ;
    PORT
      LAYER M5 ;
        RECT  71.76 0 71.784 0.084 ;
    END
  END out_flit[331]
  PIN out_flit[332]
    DIRECTION OUTPUT ;
    USE SIGNAL ;
    PORT
      LAYER M5 ;
        RECT  71.856 0 71.88 0.084 ;
    END
  END out_flit[332]
  PIN out_flit[333]
    DIRECTION OUTPUT ;
    USE SIGNAL ;
    PORT
      LAYER M5 ;
        RECT  71.952 0 71.976 0.084 ;
    END
  END out_flit[333]
  PIN out_flit[334]
    DIRECTION OUTPUT ;
    USE SIGNAL ;
    PORT
      LAYER M5 ;
        RECT  72.048 0 72.072 0.084 ;
    END
  END out_flit[334]
  PIN out_flit[335]
    DIRECTION OUTPUT ;
    USE SIGNAL ;
    PORT
      LAYER M5 ;
        RECT  72.144 0 72.168 0.084 ;
    END
  END out_flit[335]
  PIN out_flit[336]
    DIRECTION OUTPUT ;
    USE SIGNAL ;
    PORT
      LAYER M5 ;
        RECT  72.24 0 72.264 0.084 ;
    END
  END out_flit[336]
  PIN out_flit[337]
    DIRECTION OUTPUT ;
    USE SIGNAL ;
    PORT
      LAYER M5 ;
        RECT  72.336 0 72.36 0.084 ;
    END
  END out_flit[337]
  PIN out_flit[338]
    DIRECTION OUTPUT ;
    USE SIGNAL ;
    PORT
      LAYER M5 ;
        RECT  72.432 0 72.456 0.084 ;
    END
  END out_flit[338]
  PIN out_flit[339]
    DIRECTION OUTPUT ;
    USE SIGNAL ;
    PORT
      LAYER M5 ;
        RECT  72.528 0 72.552 0.084 ;
    END
  END out_flit[339]
  PIN out_flit[33]
    DIRECTION OUTPUT ;
    USE SIGNAL ;
    PORT
      LAYER M5 ;
        RECT  39.312 0 39.336 0.084 ;
    END
  END out_flit[33]
  PIN out_flit[340]
    DIRECTION OUTPUT ;
    USE SIGNAL ;
    PORT
      LAYER M5 ;
        RECT  72.624 0 72.648 0.084 ;
    END
  END out_flit[340]
  PIN out_flit[341]
    DIRECTION OUTPUT ;
    USE SIGNAL ;
    PORT
      LAYER M5 ;
        RECT  72.72 0 72.744 0.084 ;
    END
  END out_flit[341]
  PIN out_flit[342]
    DIRECTION OUTPUT ;
    USE SIGNAL ;
    PORT
      LAYER M5 ;
        RECT  72.816 0 72.84 0.084 ;
    END
  END out_flit[342]
  PIN out_flit[343]
    DIRECTION OUTPUT ;
    USE SIGNAL ;
    PORT
      LAYER M5 ;
        RECT  72.912 0 72.936 0.084 ;
    END
  END out_flit[343]
  PIN out_flit[344]
    DIRECTION OUTPUT ;
    USE SIGNAL ;
    PORT
      LAYER M5 ;
        RECT  73.008 0 73.032 0.084 ;
    END
  END out_flit[344]
  PIN out_flit[345]
    DIRECTION OUTPUT ;
    USE SIGNAL ;
    PORT
      LAYER M5 ;
        RECT  73.104 0 73.128 0.084 ;
    END
  END out_flit[345]
  PIN out_flit[346]
    DIRECTION OUTPUT ;
    USE SIGNAL ;
    PORT
      LAYER M5 ;
        RECT  73.2 0 73.224 0.084 ;
    END
  END out_flit[346]
  PIN out_flit[347]
    DIRECTION OUTPUT ;
    USE SIGNAL ;
    PORT
      LAYER M5 ;
        RECT  73.296 0 73.32 0.084 ;
    END
  END out_flit[347]
  PIN out_flit[348]
    DIRECTION OUTPUT ;
    USE SIGNAL ;
    PORT
      LAYER M5 ;
        RECT  73.392 0 73.416 0.084 ;
    END
  END out_flit[348]
  PIN out_flit[349]
    DIRECTION OUTPUT ;
    USE SIGNAL ;
    PORT
      LAYER M5 ;
        RECT  73.488 0 73.512 0.084 ;
    END
  END out_flit[349]
  PIN out_flit[34]
    DIRECTION OUTPUT ;
    USE SIGNAL ;
    PORT
      LAYER M5 ;
        RECT  39.408 0 39.432 0.084 ;
    END
  END out_flit[34]
  PIN out_flit[350]
    DIRECTION OUTPUT ;
    USE SIGNAL ;
    PORT
      LAYER M5 ;
        RECT  73.584 0 73.608 0.084 ;
    END
  END out_flit[350]
  PIN out_flit[351]
    DIRECTION OUTPUT ;
    USE SIGNAL ;
    PORT
      LAYER M5 ;
        RECT  26.064 0 26.088 0.084 ;
    END
  END out_flit[351]
  PIN out_flit[352]
    DIRECTION OUTPUT ;
    USE SIGNAL ;
    PORT
      LAYER M5 ;
        RECT  26.16 0 26.184 0.084 ;
    END
  END out_flit[352]
  PIN out_flit[353]
    DIRECTION OUTPUT ;
    USE SIGNAL ;
    PORT
      LAYER M5 ;
        RECT  26.256 0 26.28 0.084 ;
    END
  END out_flit[353]
  PIN out_flit[354]
    DIRECTION OUTPUT ;
    USE SIGNAL ;
    PORT
      LAYER M5 ;
        RECT  26.352 0 26.376 0.084 ;
    END
  END out_flit[354]
  PIN out_flit[355]
    DIRECTION OUTPUT ;
    USE SIGNAL ;
    PORT
      LAYER M5 ;
        RECT  26.448 0 26.472 0.084 ;
    END
  END out_flit[355]
  PIN out_flit[356]
    DIRECTION OUTPUT ;
    USE SIGNAL ;
    PORT
      LAYER M5 ;
        RECT  26.544 0 26.568 0.084 ;
    END
  END out_flit[356]
  PIN out_flit[357]
    DIRECTION OUTPUT ;
    USE SIGNAL ;
    PORT
      LAYER M5 ;
        RECT  26.64 0 26.664 0.084 ;
    END
  END out_flit[357]
  PIN out_flit[358]
    DIRECTION OUTPUT ;
    USE SIGNAL ;
    PORT
      LAYER M5 ;
        RECT  26.736 0 26.76 0.084 ;
    END
  END out_flit[358]
  PIN out_flit[359]
    DIRECTION OUTPUT ;
    USE SIGNAL ;
    PORT
      LAYER M5 ;
        RECT  26.832 0 26.856 0.084 ;
    END
  END out_flit[359]
  PIN out_flit[35]
    DIRECTION OUTPUT ;
    USE SIGNAL ;
    PORT
      LAYER M5 ;
        RECT  39.504 0 39.528 0.084 ;
    END
  END out_flit[35]
  PIN out_flit[360]
    DIRECTION OUTPUT ;
    USE SIGNAL ;
    PORT
      LAYER M5 ;
        RECT  26.928 0 26.952 0.084 ;
    END
  END out_flit[360]
  PIN out_flit[361]
    DIRECTION OUTPUT ;
    USE SIGNAL ;
    PORT
      LAYER M5 ;
        RECT  27.024 0 27.048 0.084 ;
    END
  END out_flit[361]
  PIN out_flit[362]
    DIRECTION OUTPUT ;
    USE SIGNAL ;
    PORT
      LAYER M5 ;
        RECT  27.12 0 27.144 0.084 ;
    END
  END out_flit[362]
  PIN out_flit[363]
    DIRECTION OUTPUT ;
    USE SIGNAL ;
    PORT
      LAYER M5 ;
        RECT  27.216 0 27.24 0.084 ;
    END
  END out_flit[363]
  PIN out_flit[364]
    DIRECTION OUTPUT ;
    USE SIGNAL ;
    PORT
      LAYER M5 ;
        RECT  27.312 0 27.336 0.084 ;
    END
  END out_flit[364]
  PIN out_flit[365]
    DIRECTION OUTPUT ;
    USE SIGNAL ;
    PORT
      LAYER M5 ;
        RECT  27.408 0 27.432 0.084 ;
    END
  END out_flit[365]
  PIN out_flit[366]
    DIRECTION OUTPUT ;
    USE SIGNAL ;
    PORT
      LAYER M5 ;
        RECT  27.504 0 27.528 0.084 ;
    END
  END out_flit[366]
  PIN out_flit[367]
    DIRECTION OUTPUT ;
    USE SIGNAL ;
    PORT
      LAYER M5 ;
        RECT  27.6 0 27.624 0.084 ;
    END
  END out_flit[367]
  PIN out_flit[368]
    DIRECTION OUTPUT ;
    USE SIGNAL ;
    PORT
      LAYER M5 ;
        RECT  27.696 0 27.72 0.084 ;
    END
  END out_flit[368]
  PIN out_flit[369]
    DIRECTION OUTPUT ;
    USE SIGNAL ;
    PORT
      LAYER M5 ;
        RECT  27.792 0 27.816 0.084 ;
    END
  END out_flit[369]
  PIN out_flit[36]
    DIRECTION OUTPUT ;
    USE SIGNAL ;
    PORT
      LAYER M5 ;
        RECT  39.6 0 39.624 0.084 ;
    END
  END out_flit[36]
  PIN out_flit[370]
    DIRECTION OUTPUT ;
    USE SIGNAL ;
    PORT
      LAYER M5 ;
        RECT  27.888 0 27.912 0.084 ;
    END
  END out_flit[370]
  PIN out_flit[371]
    DIRECTION OUTPUT ;
    USE SIGNAL ;
    PORT
      LAYER M5 ;
        RECT  27.984 0 28.008 0.084 ;
    END
  END out_flit[371]
  PIN out_flit[372]
    DIRECTION OUTPUT ;
    USE SIGNAL ;
    PORT
      LAYER M5 ;
        RECT  28.08 0 28.104 0.084 ;
    END
  END out_flit[372]
  PIN out_flit[373]
    DIRECTION OUTPUT ;
    USE SIGNAL ;
    PORT
      LAYER M5 ;
        RECT  28.176 0 28.2 0.084 ;
    END
  END out_flit[373]
  PIN out_flit[374]
    DIRECTION OUTPUT ;
    USE SIGNAL ;
    PORT
      LAYER M5 ;
        RECT  28.272 0 28.296 0.084 ;
    END
  END out_flit[374]
  PIN out_flit[375]
    DIRECTION OUTPUT ;
    USE SIGNAL ;
    PORT
      LAYER M5 ;
        RECT  28.368 0 28.392 0.084 ;
    END
  END out_flit[375]
  PIN out_flit[376]
    DIRECTION OUTPUT ;
    USE SIGNAL ;
    PORT
      LAYER M5 ;
        RECT  28.464 0 28.488 0.084 ;
    END
  END out_flit[376]
  PIN out_flit[377]
    DIRECTION OUTPUT ;
    USE SIGNAL ;
    PORT
      LAYER M5 ;
        RECT  28.56 0 28.584 0.084 ;
    END
  END out_flit[377]
  PIN out_flit[378]
    DIRECTION OUTPUT ;
    USE SIGNAL ;
    PORT
      LAYER M5 ;
        RECT  28.656 0 28.68 0.084 ;
    END
  END out_flit[378]
  PIN out_flit[379]
    DIRECTION OUTPUT ;
    USE SIGNAL ;
    PORT
      LAYER M5 ;
        RECT  28.752 0 28.776 0.084 ;
    END
  END out_flit[379]
  PIN out_flit[37]
    DIRECTION OUTPUT ;
    USE SIGNAL ;
    PORT
      LAYER M5 ;
        RECT  39.696 0 39.72 0.084 ;
    END
  END out_flit[37]
  PIN out_flit[380]
    DIRECTION OUTPUT ;
    USE SIGNAL ;
    PORT
      LAYER M5 ;
        RECT  28.848 0 28.872 0.084 ;
    END
  END out_flit[380]
  PIN out_flit[381]
    DIRECTION OUTPUT ;
    USE SIGNAL ;
    PORT
      LAYER M5 ;
        RECT  28.944 0 28.968 0.084 ;
    END
  END out_flit[381]
  PIN out_flit[382]
    DIRECTION OUTPUT ;
    USE SIGNAL ;
    PORT
      LAYER M5 ;
        RECT  29.04 0 29.064 0.084 ;
    END
  END out_flit[382]
  PIN out_flit[383]
    DIRECTION OUTPUT ;
    USE SIGNAL ;
    PORT
      LAYER M5 ;
        RECT  58.32 0 58.344 0.084 ;
    END
  END out_flit[383]
  PIN out_flit[384]
    DIRECTION OUTPUT ;
    USE SIGNAL ;
    PORT
      LAYER M5 ;
        RECT  58.416 0 58.44 0.084 ;
    END
  END out_flit[384]
  PIN out_flit[385]
    DIRECTION OUTPUT ;
    USE SIGNAL ;
    PORT
      LAYER M5 ;
        RECT  58.512 0 58.536 0.084 ;
    END
  END out_flit[385]
  PIN out_flit[386]
    DIRECTION OUTPUT ;
    USE SIGNAL ;
    PORT
      LAYER M5 ;
        RECT  58.608 0 58.632 0.084 ;
    END
  END out_flit[386]
  PIN out_flit[387]
    DIRECTION OUTPUT ;
    USE SIGNAL ;
    PORT
      LAYER M5 ;
        RECT  58.704 0 58.728 0.084 ;
    END
  END out_flit[387]
  PIN out_flit[388]
    DIRECTION OUTPUT ;
    USE SIGNAL ;
    PORT
      LAYER M5 ;
        RECT  58.8 0 58.824 0.084 ;
    END
  END out_flit[388]
  PIN out_flit[389]
    DIRECTION OUTPUT ;
    USE SIGNAL ;
    PORT
      LAYER M5 ;
        RECT  58.896 0 58.92 0.084 ;
    END
  END out_flit[389]
  PIN out_flit[38]
    DIRECTION OUTPUT ;
    USE SIGNAL ;
    PORT
      LAYER M5 ;
        RECT  39.792 0 39.816 0.084 ;
    END
  END out_flit[38]
  PIN out_flit[390]
    DIRECTION OUTPUT ;
    USE SIGNAL ;
    PORT
      LAYER M5 ;
        RECT  58.992 0 59.016 0.084 ;
    END
  END out_flit[390]
  PIN out_flit[391]
    DIRECTION OUTPUT ;
    USE SIGNAL ;
    PORT
      LAYER M5 ;
        RECT  59.088 0 59.112 0.084 ;
    END
  END out_flit[391]
  PIN out_flit[392]
    DIRECTION OUTPUT ;
    USE SIGNAL ;
    PORT
      LAYER M5 ;
        RECT  59.184 0 59.208 0.084 ;
    END
  END out_flit[392]
  PIN out_flit[393]
    DIRECTION OUTPUT ;
    USE SIGNAL ;
    PORT
      LAYER M5 ;
        RECT  59.28 0 59.304 0.084 ;
    END
  END out_flit[393]
  PIN out_flit[394]
    DIRECTION OUTPUT ;
    USE SIGNAL ;
    PORT
      LAYER M5 ;
        RECT  59.376 0 59.4 0.084 ;
    END
  END out_flit[394]
  PIN out_flit[395]
    DIRECTION OUTPUT ;
    USE SIGNAL ;
    PORT
      LAYER M5 ;
        RECT  59.472 0 59.496 0.084 ;
    END
  END out_flit[395]
  PIN out_flit[396]
    DIRECTION OUTPUT ;
    USE SIGNAL ;
    PORT
      LAYER M5 ;
        RECT  59.568 0 59.592 0.084 ;
    END
  END out_flit[396]
  PIN out_flit[397]
    DIRECTION OUTPUT ;
    USE SIGNAL ;
    PORT
      LAYER M5 ;
        RECT  59.664 0 59.688 0.084 ;
    END
  END out_flit[397]
  PIN out_flit[398]
    DIRECTION OUTPUT ;
    USE SIGNAL ;
    PORT
      LAYER M5 ;
        RECT  59.76 0 59.784 0.084 ;
    END
  END out_flit[398]
  PIN out_flit[399]
    DIRECTION OUTPUT ;
    USE SIGNAL ;
    PORT
      LAYER M5 ;
        RECT  59.856 0 59.88 0.084 ;
    END
  END out_flit[399]
  PIN out_flit[39]
    DIRECTION OUTPUT ;
    USE SIGNAL ;
    PORT
      LAYER M5 ;
        RECT  39.888 0 39.912 0.084 ;
    END
  END out_flit[39]
  PIN out_flit[3]
    DIRECTION OUTPUT ;
    USE SIGNAL ;
    PORT
      LAYER M5 ;
        RECT  45.648 0 45.672 0.084 ;
    END
  END out_flit[3]
  PIN out_flit[400]
    DIRECTION OUTPUT ;
    USE SIGNAL ;
    PORT
      LAYER M5 ;
        RECT  59.952 0 59.976 0.084 ;
    END
  END out_flit[400]
  PIN out_flit[401]
    DIRECTION OUTPUT ;
    USE SIGNAL ;
    PORT
      LAYER M5 ;
        RECT  60.048 0 60.072 0.084 ;
    END
  END out_flit[401]
  PIN out_flit[402]
    DIRECTION OUTPUT ;
    USE SIGNAL ;
    PORT
      LAYER M5 ;
        RECT  60.144 0 60.168 0.084 ;
    END
  END out_flit[402]
  PIN out_flit[403]
    DIRECTION OUTPUT ;
    USE SIGNAL ;
    PORT
      LAYER M5 ;
        RECT  60.24 0 60.264 0.084 ;
    END
  END out_flit[403]
  PIN out_flit[404]
    DIRECTION OUTPUT ;
    USE SIGNAL ;
    PORT
      LAYER M5 ;
        RECT  60.336 0 60.36 0.084 ;
    END
  END out_flit[404]
  PIN out_flit[405]
    DIRECTION OUTPUT ;
    USE SIGNAL ;
    PORT
      LAYER M5 ;
        RECT  60.432 0 60.456 0.084 ;
    END
  END out_flit[405]
  PIN out_flit[406]
    DIRECTION OUTPUT ;
    USE SIGNAL ;
    PORT
      LAYER M5 ;
        RECT  60.528 0 60.552 0.084 ;
    END
  END out_flit[406]
  PIN out_flit[407]
    DIRECTION OUTPUT ;
    USE SIGNAL ;
    PORT
      LAYER M5 ;
        RECT  60.624 0 60.648 0.084 ;
    END
  END out_flit[407]
  PIN out_flit[408]
    DIRECTION OUTPUT ;
    USE SIGNAL ;
    PORT
      LAYER M5 ;
        RECT  60.72 0 60.744 0.084 ;
    END
  END out_flit[408]
  PIN out_flit[409]
    DIRECTION OUTPUT ;
    USE SIGNAL ;
    PORT
      LAYER M5 ;
        RECT  60.816 0 60.84 0.084 ;
    END
  END out_flit[409]
  PIN out_flit[40]
    DIRECTION OUTPUT ;
    USE SIGNAL ;
    PORT
      LAYER M5 ;
        RECT  39.984 0 40.008 0.084 ;
    END
  END out_flit[40]
  PIN out_flit[410]
    DIRECTION OUTPUT ;
    USE SIGNAL ;
    PORT
      LAYER M5 ;
        RECT  60.912 0 60.936 0.084 ;
    END
  END out_flit[410]
  PIN out_flit[411]
    DIRECTION OUTPUT ;
    USE SIGNAL ;
    PORT
      LAYER M5 ;
        RECT  61.008 0 61.032 0.084 ;
    END
  END out_flit[411]
  PIN out_flit[412]
    DIRECTION OUTPUT ;
    USE SIGNAL ;
    PORT
      LAYER M5 ;
        RECT  61.104 0 61.128 0.084 ;
    END
  END out_flit[412]
  PIN out_flit[413]
    DIRECTION OUTPUT ;
    USE SIGNAL ;
    PORT
      LAYER M5 ;
        RECT  61.2 0 61.224 0.084 ;
    END
  END out_flit[413]
  PIN out_flit[414]
    DIRECTION OUTPUT ;
    USE SIGNAL ;
    PORT
      LAYER M5 ;
        RECT  61.296 0 61.32 0.084 ;
    END
  END out_flit[414]
  PIN out_flit[415]
    DIRECTION OUTPUT ;
    USE SIGNAL ;
    PORT
      LAYER M5 ;
        RECT  29.136 0 29.16 0.084 ;
    END
  END out_flit[415]
  PIN out_flit[416]
    DIRECTION OUTPUT ;
    USE SIGNAL ;
    PORT
      LAYER M5 ;
        RECT  29.232 0 29.256 0.084 ;
    END
  END out_flit[416]
  PIN out_flit[417]
    DIRECTION OUTPUT ;
    USE SIGNAL ;
    PORT
      LAYER M5 ;
        RECT  29.328 0 29.352 0.084 ;
    END
  END out_flit[417]
  PIN out_flit[418]
    DIRECTION OUTPUT ;
    USE SIGNAL ;
    PORT
      LAYER M5 ;
        RECT  29.424 0 29.448 0.084 ;
    END
  END out_flit[418]
  PIN out_flit[419]
    DIRECTION OUTPUT ;
    USE SIGNAL ;
    PORT
      LAYER M5 ;
        RECT  29.52 0 29.544 0.084 ;
    END
  END out_flit[419]
  PIN out_flit[41]
    DIRECTION OUTPUT ;
    USE SIGNAL ;
    PORT
      LAYER M5 ;
        RECT  40.08 0 40.104 0.084 ;
    END
  END out_flit[41]
  PIN out_flit[420]
    DIRECTION OUTPUT ;
    USE SIGNAL ;
    PORT
      LAYER M5 ;
        RECT  29.616 0 29.64 0.084 ;
    END
  END out_flit[420]
  PIN out_flit[421]
    DIRECTION OUTPUT ;
    USE SIGNAL ;
    PORT
      LAYER M5 ;
        RECT  29.712 0 29.736 0.084 ;
    END
  END out_flit[421]
  PIN out_flit[422]
    DIRECTION OUTPUT ;
    USE SIGNAL ;
    PORT
      LAYER M5 ;
        RECT  29.808 0 29.832 0.084 ;
    END
  END out_flit[422]
  PIN out_flit[423]
    DIRECTION OUTPUT ;
    USE SIGNAL ;
    PORT
      LAYER M5 ;
        RECT  29.904 0 29.928 0.084 ;
    END
  END out_flit[423]
  PIN out_flit[424]
    DIRECTION OUTPUT ;
    USE SIGNAL ;
    PORT
      LAYER M5 ;
        RECT  30 0 30.024 0.084 ;
    END
  END out_flit[424]
  PIN out_flit[425]
    DIRECTION OUTPUT ;
    USE SIGNAL ;
    PORT
      LAYER M5 ;
        RECT  30.096 0 30.12 0.084 ;
    END
  END out_flit[425]
  PIN out_flit[426]
    DIRECTION OUTPUT ;
    USE SIGNAL ;
    PORT
      LAYER M5 ;
        RECT  30.192 0 30.216 0.084 ;
    END
  END out_flit[426]
  PIN out_flit[427]
    DIRECTION OUTPUT ;
    USE SIGNAL ;
    PORT
      LAYER M5 ;
        RECT  30.288 0 30.312 0.084 ;
    END
  END out_flit[427]
  PIN out_flit[428]
    DIRECTION OUTPUT ;
    USE SIGNAL ;
    PORT
      LAYER M5 ;
        RECT  30.384 0 30.408 0.084 ;
    END
  END out_flit[428]
  PIN out_flit[429]
    DIRECTION OUTPUT ;
    USE SIGNAL ;
    PORT
      LAYER M5 ;
        RECT  30.48 0 30.504 0.084 ;
    END
  END out_flit[429]
  PIN out_flit[42]
    DIRECTION OUTPUT ;
    USE SIGNAL ;
    PORT
      LAYER M5 ;
        RECT  40.176 0 40.2 0.084 ;
    END
  END out_flit[42]
  PIN out_flit[430]
    DIRECTION OUTPUT ;
    USE SIGNAL ;
    PORT
      LAYER M5 ;
        RECT  30.576 0 30.6 0.084 ;
    END
  END out_flit[430]
  PIN out_flit[431]
    DIRECTION OUTPUT ;
    USE SIGNAL ;
    PORT
      LAYER M5 ;
        RECT  30.672 0 30.696 0.084 ;
    END
  END out_flit[431]
  PIN out_flit[432]
    DIRECTION OUTPUT ;
    USE SIGNAL ;
    PORT
      LAYER M5 ;
        RECT  30.768 0 30.792 0.084 ;
    END
  END out_flit[432]
  PIN out_flit[433]
    DIRECTION OUTPUT ;
    USE SIGNAL ;
    PORT
      LAYER M5 ;
        RECT  30.864 0 30.888 0.084 ;
    END
  END out_flit[433]
  PIN out_flit[434]
    DIRECTION OUTPUT ;
    USE SIGNAL ;
    PORT
      LAYER M5 ;
        RECT  30.96 0 30.984 0.084 ;
    END
  END out_flit[434]
  PIN out_flit[435]
    DIRECTION OUTPUT ;
    USE SIGNAL ;
    PORT
      LAYER M5 ;
        RECT  31.056 0 31.08 0.084 ;
    END
  END out_flit[435]
  PIN out_flit[436]
    DIRECTION OUTPUT ;
    USE SIGNAL ;
    PORT
      LAYER M5 ;
        RECT  31.152 0 31.176 0.084 ;
    END
  END out_flit[436]
  PIN out_flit[437]
    DIRECTION OUTPUT ;
    USE SIGNAL ;
    PORT
      LAYER M5 ;
        RECT  31.248 0 31.272 0.084 ;
    END
  END out_flit[437]
  PIN out_flit[438]
    DIRECTION OUTPUT ;
    USE SIGNAL ;
    PORT
      LAYER M5 ;
        RECT  31.344 0 31.368 0.084 ;
    END
  END out_flit[438]
  PIN out_flit[439]
    DIRECTION OUTPUT ;
    USE SIGNAL ;
    PORT
      LAYER M5 ;
        RECT  31.44 0 31.464 0.084 ;
    END
  END out_flit[439]
  PIN out_flit[43]
    DIRECTION OUTPUT ;
    USE SIGNAL ;
    PORT
      LAYER M5 ;
        RECT  40.272 0 40.296 0.084 ;
    END
  END out_flit[43]
  PIN out_flit[440]
    DIRECTION OUTPUT ;
    USE SIGNAL ;
    PORT
      LAYER M5 ;
        RECT  31.536 0 31.56 0.084 ;
    END
  END out_flit[440]
  PIN out_flit[441]
    DIRECTION OUTPUT ;
    USE SIGNAL ;
    PORT
      LAYER M5 ;
        RECT  31.632 0 31.656 0.084 ;
    END
  END out_flit[441]
  PIN out_flit[442]
    DIRECTION OUTPUT ;
    USE SIGNAL ;
    PORT
      LAYER M5 ;
        RECT  31.728 0 31.752 0.084 ;
    END
  END out_flit[442]
  PIN out_flit[443]
    DIRECTION OUTPUT ;
    USE SIGNAL ;
    PORT
      LAYER M5 ;
        RECT  31.824 0 31.848 0.084 ;
    END
  END out_flit[443]
  PIN out_flit[444]
    DIRECTION OUTPUT ;
    USE SIGNAL ;
    PORT
      LAYER M5 ;
        RECT  31.92 0 31.944 0.084 ;
    END
  END out_flit[444]
  PIN out_flit[445]
    DIRECTION OUTPUT ;
    USE SIGNAL ;
    PORT
      LAYER M5 ;
        RECT  32.016 0 32.04 0.084 ;
    END
  END out_flit[445]
  PIN out_flit[446]
    DIRECTION OUTPUT ;
    USE SIGNAL ;
    PORT
      LAYER M5 ;
        RECT  32.112 0 32.136 0.084 ;
    END
  END out_flit[446]
  PIN out_flit[447]
    DIRECTION OUTPUT ;
    USE SIGNAL ;
    PORT
      LAYER M5 ;
        RECT  61.392 0 61.416 0.084 ;
    END
  END out_flit[447]
  PIN out_flit[448]
    DIRECTION OUTPUT ;
    USE SIGNAL ;
    PORT
      LAYER M5 ;
        RECT  61.488 0 61.512 0.084 ;
    END
  END out_flit[448]
  PIN out_flit[449]
    DIRECTION OUTPUT ;
    USE SIGNAL ;
    PORT
      LAYER M5 ;
        RECT  61.584 0 61.608 0.084 ;
    END
  END out_flit[449]
  PIN out_flit[44]
    DIRECTION OUTPUT ;
    USE SIGNAL ;
    PORT
      LAYER M5 ;
        RECT  40.368 0 40.392 0.084 ;
    END
  END out_flit[44]
  PIN out_flit[450]
    DIRECTION OUTPUT ;
    USE SIGNAL ;
    PORT
      LAYER M5 ;
        RECT  61.68 0 61.704 0.084 ;
    END
  END out_flit[450]
  PIN out_flit[451]
    DIRECTION OUTPUT ;
    USE SIGNAL ;
    PORT
      LAYER M5 ;
        RECT  61.776 0 61.8 0.084 ;
    END
  END out_flit[451]
  PIN out_flit[452]
    DIRECTION OUTPUT ;
    USE SIGNAL ;
    PORT
      LAYER M5 ;
        RECT  61.872 0 61.896 0.084 ;
    END
  END out_flit[452]
  PIN out_flit[453]
    DIRECTION OUTPUT ;
    USE SIGNAL ;
    PORT
      LAYER M5 ;
        RECT  61.968 0 61.992 0.084 ;
    END
  END out_flit[453]
  PIN out_flit[454]
    DIRECTION OUTPUT ;
    USE SIGNAL ;
    PORT
      LAYER M5 ;
        RECT  62.064 0 62.088 0.084 ;
    END
  END out_flit[454]
  PIN out_flit[455]
    DIRECTION OUTPUT ;
    USE SIGNAL ;
    PORT
      LAYER M5 ;
        RECT  62.16 0 62.184 0.084 ;
    END
  END out_flit[455]
  PIN out_flit[456]
    DIRECTION OUTPUT ;
    USE SIGNAL ;
    PORT
      LAYER M5 ;
        RECT  62.256 0 62.28 0.084 ;
    END
  END out_flit[456]
  PIN out_flit[457]
    DIRECTION OUTPUT ;
    USE SIGNAL ;
    PORT
      LAYER M5 ;
        RECT  62.352 0 62.376 0.084 ;
    END
  END out_flit[457]
  PIN out_flit[458]
    DIRECTION OUTPUT ;
    USE SIGNAL ;
    PORT
      LAYER M5 ;
        RECT  62.448 0 62.472 0.084 ;
    END
  END out_flit[458]
  PIN out_flit[459]
    DIRECTION OUTPUT ;
    USE SIGNAL ;
    PORT
      LAYER M5 ;
        RECT  62.544 0 62.568 0.084 ;
    END
  END out_flit[459]
  PIN out_flit[45]
    DIRECTION OUTPUT ;
    USE SIGNAL ;
    PORT
      LAYER M5 ;
        RECT  40.464 0 40.488 0.084 ;
    END
  END out_flit[45]
  PIN out_flit[460]
    DIRECTION OUTPUT ;
    USE SIGNAL ;
    PORT
      LAYER M5 ;
        RECT  62.64 0 62.664 0.084 ;
    END
  END out_flit[460]
  PIN out_flit[461]
    DIRECTION OUTPUT ;
    USE SIGNAL ;
    PORT
      LAYER M5 ;
        RECT  62.736 0 62.76 0.084 ;
    END
  END out_flit[461]
  PIN out_flit[462]
    DIRECTION OUTPUT ;
    USE SIGNAL ;
    PORT
      LAYER M5 ;
        RECT  62.832 0 62.856 0.084 ;
    END
  END out_flit[462]
  PIN out_flit[463]
    DIRECTION OUTPUT ;
    USE SIGNAL ;
    PORT
      LAYER M5 ;
        RECT  62.928 0 62.952 0.084 ;
    END
  END out_flit[463]
  PIN out_flit[464]
    DIRECTION OUTPUT ;
    USE SIGNAL ;
    PORT
      LAYER M5 ;
        RECT  63.024 0 63.048 0.084 ;
    END
  END out_flit[464]
  PIN out_flit[465]
    DIRECTION OUTPUT ;
    USE SIGNAL ;
    PORT
      LAYER M5 ;
        RECT  63.12 0 63.144 0.084 ;
    END
  END out_flit[465]
  PIN out_flit[466]
    DIRECTION OUTPUT ;
    USE SIGNAL ;
    PORT
      LAYER M5 ;
        RECT  63.216 0 63.24 0.084 ;
    END
  END out_flit[466]
  PIN out_flit[467]
    DIRECTION OUTPUT ;
    USE SIGNAL ;
    PORT
      LAYER M5 ;
        RECT  63.312 0 63.336 0.084 ;
    END
  END out_flit[467]
  PIN out_flit[468]
    DIRECTION OUTPUT ;
    USE SIGNAL ;
    PORT
      LAYER M5 ;
        RECT  63.408 0 63.432 0.084 ;
    END
  END out_flit[468]
  PIN out_flit[469]
    DIRECTION OUTPUT ;
    USE SIGNAL ;
    PORT
      LAYER M5 ;
        RECT  63.504 0 63.528 0.084 ;
    END
  END out_flit[469]
  PIN out_flit[46]
    DIRECTION OUTPUT ;
    USE SIGNAL ;
    PORT
      LAYER M5 ;
        RECT  40.56 0 40.584 0.084 ;
    END
  END out_flit[46]
  PIN out_flit[470]
    DIRECTION OUTPUT ;
    USE SIGNAL ;
    PORT
      LAYER M5 ;
        RECT  63.6 0 63.624 0.084 ;
    END
  END out_flit[470]
  PIN out_flit[471]
    DIRECTION OUTPUT ;
    USE SIGNAL ;
    PORT
      LAYER M5 ;
        RECT  63.696 0 63.72 0.084 ;
    END
  END out_flit[471]
  PIN out_flit[472]
    DIRECTION OUTPUT ;
    USE SIGNAL ;
    PORT
      LAYER M5 ;
        RECT  63.792 0 63.816 0.084 ;
    END
  END out_flit[472]
  PIN out_flit[473]
    DIRECTION OUTPUT ;
    USE SIGNAL ;
    PORT
      LAYER M5 ;
        RECT  63.888 0 63.912 0.084 ;
    END
  END out_flit[473]
  PIN out_flit[474]
    DIRECTION OUTPUT ;
    USE SIGNAL ;
    PORT
      LAYER M5 ;
        RECT  63.984 0 64.008 0.084 ;
    END
  END out_flit[474]
  PIN out_flit[475]
    DIRECTION OUTPUT ;
    USE SIGNAL ;
    PORT
      LAYER M5 ;
        RECT  64.08 0 64.104 0.084 ;
    END
  END out_flit[475]
  PIN out_flit[476]
    DIRECTION OUTPUT ;
    USE SIGNAL ;
    PORT
      LAYER M5 ;
        RECT  64.176 0 64.2 0.084 ;
    END
  END out_flit[476]
  PIN out_flit[477]
    DIRECTION OUTPUT ;
    USE SIGNAL ;
    PORT
      LAYER M5 ;
        RECT  64.272 0 64.296 0.084 ;
    END
  END out_flit[477]
  PIN out_flit[478]
    DIRECTION OUTPUT ;
    USE SIGNAL ;
    PORT
      LAYER M5 ;
        RECT  64.368 0 64.392 0.084 ;
    END
  END out_flit[478]
  PIN out_flit[479]
    DIRECTION OUTPUT ;
    USE SIGNAL ;
    PORT
      LAYER M5 ;
        RECT  80.592 0 80.616 0.084 ;
    END
  END out_flit[479]
  PIN out_flit[47]
    DIRECTION OUTPUT ;
    USE SIGNAL ;
    PORT
      LAYER M5 ;
        RECT  40.656 0 40.68 0.084 ;
    END
  END out_flit[47]
  PIN out_flit[480]
    DIRECTION OUTPUT ;
    USE SIGNAL ;
    PORT
      LAYER M5 ;
        RECT  80.688 0 80.712 0.084 ;
    END
  END out_flit[480]
  PIN out_flit[481]
    DIRECTION OUTPUT ;
    USE SIGNAL ;
    PORT
      LAYER M5 ;
        RECT  80.784 0 80.808 0.084 ;
    END
  END out_flit[481]
  PIN out_flit[482]
    DIRECTION OUTPUT ;
    USE SIGNAL ;
    PORT
      LAYER M5 ;
        RECT  80.88 0 80.904 0.084 ;
    END
  END out_flit[482]
  PIN out_flit[483]
    DIRECTION OUTPUT ;
    USE SIGNAL ;
    PORT
      LAYER M5 ;
        RECT  80.976 0 81 0.084 ;
    END
  END out_flit[483]
  PIN out_flit[484]
    DIRECTION OUTPUT ;
    USE SIGNAL ;
    PORT
      LAYER M5 ;
        RECT  81.072 0 81.096 0.084 ;
    END
  END out_flit[484]
  PIN out_flit[485]
    DIRECTION OUTPUT ;
    USE SIGNAL ;
    PORT
      LAYER M5 ;
        RECT  81.168 0 81.192 0.084 ;
    END
  END out_flit[485]
  PIN out_flit[486]
    DIRECTION OUTPUT ;
    USE SIGNAL ;
    PORT
      LAYER M5 ;
        RECT  81.264 0 81.288 0.084 ;
    END
  END out_flit[486]
  PIN out_flit[487]
    DIRECTION OUTPUT ;
    USE SIGNAL ;
    PORT
      LAYER M5 ;
        RECT  81.36 0 81.384 0.084 ;
    END
  END out_flit[487]
  PIN out_flit[488]
    DIRECTION OUTPUT ;
    USE SIGNAL ;
    PORT
      LAYER M5 ;
        RECT  81.456 0 81.48 0.084 ;
    END
  END out_flit[488]
  PIN out_flit[489]
    DIRECTION OUTPUT ;
    USE SIGNAL ;
    PORT
      LAYER M5 ;
        RECT  81.552 0 81.576 0.084 ;
    END
  END out_flit[489]
  PIN out_flit[48]
    DIRECTION OUTPUT ;
    USE SIGNAL ;
    PORT
      LAYER M5 ;
        RECT  40.752 0 40.776 0.084 ;
    END
  END out_flit[48]
  PIN out_flit[490]
    DIRECTION OUTPUT ;
    USE SIGNAL ;
    PORT
      LAYER M5 ;
        RECT  81.648 0 81.672 0.084 ;
    END
  END out_flit[490]
  PIN out_flit[491]
    DIRECTION OUTPUT ;
    USE SIGNAL ;
    PORT
      LAYER M5 ;
        RECT  81.744 0 81.768 0.084 ;
    END
  END out_flit[491]
  PIN out_flit[492]
    DIRECTION OUTPUT ;
    USE SIGNAL ;
    PORT
      LAYER M5 ;
        RECT  81.84 0 81.864 0.084 ;
    END
  END out_flit[492]
  PIN out_flit[493]
    DIRECTION OUTPUT ;
    USE SIGNAL ;
    PORT
      LAYER M5 ;
        RECT  81.936 0 81.96 0.084 ;
    END
  END out_flit[493]
  PIN out_flit[494]
    DIRECTION OUTPUT ;
    USE SIGNAL ;
    PORT
      LAYER M5 ;
        RECT  82.032 0 82.056 0.084 ;
    END
  END out_flit[494]
  PIN out_flit[495]
    DIRECTION OUTPUT ;
    USE SIGNAL ;
    PORT
      LAYER M5 ;
        RECT  82.128 0 82.152 0.084 ;
    END
  END out_flit[495]
  PIN out_flit[496]
    DIRECTION OUTPUT ;
    USE SIGNAL ;
    PORT
      LAYER M5 ;
        RECT  82.224 0 82.248 0.084 ;
    END
  END out_flit[496]
  PIN out_flit[497]
    DIRECTION OUTPUT ;
    USE SIGNAL ;
    PORT
      LAYER M5 ;
        RECT  82.32 0 82.344 0.084 ;
    END
  END out_flit[497]
  PIN out_flit[498]
    DIRECTION OUTPUT ;
    USE SIGNAL ;
    PORT
      LAYER M5 ;
        RECT  82.416 0 82.44 0.084 ;
    END
  END out_flit[498]
  PIN out_flit[499]
    DIRECTION OUTPUT ;
    USE SIGNAL ;
    PORT
      LAYER M5 ;
        RECT  82.512 0 82.536 0.084 ;
    END
  END out_flit[499]
  PIN out_flit[49]
    DIRECTION OUTPUT ;
    USE SIGNAL ;
    PORT
      LAYER M5 ;
        RECT  40.848 0 40.872 0.084 ;
    END
  END out_flit[49]
  PIN out_flit[4]
    DIRECTION OUTPUT ;
    USE SIGNAL ;
    PORT
      LAYER M5 ;
        RECT  45.744 0 45.768 0.084 ;
    END
  END out_flit[4]
  PIN out_flit[500]
    DIRECTION OUTPUT ;
    USE SIGNAL ;
    PORT
      LAYER M5 ;
        RECT  82.608 0 82.632 0.084 ;
    END
  END out_flit[500]
  PIN out_flit[501]
    DIRECTION OUTPUT ;
    USE SIGNAL ;
    PORT
      LAYER M5 ;
        RECT  82.704 0 82.728 0.084 ;
    END
  END out_flit[501]
  PIN out_flit[502]
    DIRECTION OUTPUT ;
    USE SIGNAL ;
    PORT
      LAYER M5 ;
        RECT  82.8 0 82.824 0.084 ;
    END
  END out_flit[502]
  PIN out_flit[503]
    DIRECTION OUTPUT ;
    USE SIGNAL ;
    PORT
      LAYER M5 ;
        RECT  82.896 0 82.92 0.084 ;
    END
  END out_flit[503]
  PIN out_flit[504]
    DIRECTION OUTPUT ;
    USE SIGNAL ;
    PORT
      LAYER M5 ;
        RECT  82.992 0 83.016 0.084 ;
    END
  END out_flit[504]
  PIN out_flit[505]
    DIRECTION OUTPUT ;
    USE SIGNAL ;
    PORT
      LAYER M5 ;
        RECT  83.088 0 83.112 0.084 ;
    END
  END out_flit[505]
  PIN out_flit[506]
    DIRECTION OUTPUT ;
    USE SIGNAL ;
    PORT
      LAYER M5 ;
        RECT  83.184 0 83.208 0.084 ;
    END
  END out_flit[506]
  PIN out_flit[507]
    DIRECTION OUTPUT ;
    USE SIGNAL ;
    PORT
      LAYER M5 ;
        RECT  83.28 0 83.304 0.084 ;
    END
  END out_flit[507]
  PIN out_flit[508]
    DIRECTION OUTPUT ;
    USE SIGNAL ;
    PORT
      LAYER M5 ;
        RECT  83.376 0 83.4 0.084 ;
    END
  END out_flit[508]
  PIN out_flit[509]
    DIRECTION OUTPUT ;
    USE SIGNAL ;
    PORT
      LAYER M5 ;
        RECT  83.472 0 83.496 0.084 ;
    END
  END out_flit[509]
  PIN out_flit[50]
    DIRECTION OUTPUT ;
    USE SIGNAL ;
    PORT
      LAYER M5 ;
        RECT  40.944 0 40.968 0.084 ;
    END
  END out_flit[50]
  PIN out_flit[510]
    DIRECTION OUTPUT ;
    USE SIGNAL ;
    PORT
      LAYER M5 ;
        RECT  83.568 0 83.592 0.084 ;
    END
  END out_flit[510]
  PIN out_flit[511]
    DIRECTION OUTPUT ;
    USE SIGNAL ;
    PORT
      LAYER M5 ;
        RECT  35.28 0 35.304 0.084 ;
    END
  END out_flit[511]
  PIN out_flit[512]
    DIRECTION OUTPUT ;
    USE SIGNAL ;
    PORT
      LAYER M5 ;
        RECT  35.376 0 35.4 0.084 ;
    END
  END out_flit[512]
  PIN out_flit[513]
    DIRECTION OUTPUT ;
    USE SIGNAL ;
    PORT
      LAYER M5 ;
        RECT  35.472 0 35.496 0.084 ;
    END
  END out_flit[513]
  PIN out_flit[514]
    DIRECTION OUTPUT ;
    USE SIGNAL ;
    PORT
      LAYER M5 ;
        RECT  35.568 0 35.592 0.084 ;
    END
  END out_flit[514]
  PIN out_flit[515]
    DIRECTION OUTPUT ;
    USE SIGNAL ;
    PORT
      LAYER M5 ;
        RECT  35.664 0 35.688 0.084 ;
    END
  END out_flit[515]
  PIN out_flit[516]
    DIRECTION OUTPUT ;
    USE SIGNAL ;
    PORT
      LAYER M5 ;
        RECT  35.76 0 35.784 0.084 ;
    END
  END out_flit[516]
  PIN out_flit[517]
    DIRECTION OUTPUT ;
    USE SIGNAL ;
    PORT
      LAYER M5 ;
        RECT  35.856 0 35.88 0.084 ;
    END
  END out_flit[517]
  PIN out_flit[518]
    DIRECTION OUTPUT ;
    USE SIGNAL ;
    PORT
      LAYER M5 ;
        RECT  35.952 0 35.976 0.084 ;
    END
  END out_flit[518]
  PIN out_flit[519]
    DIRECTION OUTPUT ;
    USE SIGNAL ;
    PORT
      LAYER M5 ;
        RECT  36.048 0 36.072 0.084 ;
    END
  END out_flit[519]
  PIN out_flit[51]
    DIRECTION OUTPUT ;
    USE SIGNAL ;
    PORT
      LAYER M5 ;
        RECT  41.04 0 41.064 0.084 ;
    END
  END out_flit[51]
  PIN out_flit[520]
    DIRECTION OUTPUT ;
    USE SIGNAL ;
    PORT
      LAYER M5 ;
        RECT  36.144 0 36.168 0.084 ;
    END
  END out_flit[520]
  PIN out_flit[521]
    DIRECTION OUTPUT ;
    USE SIGNAL ;
    PORT
      LAYER M5 ;
        RECT  36.24 0 36.264 0.084 ;
    END
  END out_flit[521]
  PIN out_flit[522]
    DIRECTION OUTPUT ;
    USE SIGNAL ;
    PORT
      LAYER M5 ;
        RECT  36.336 0 36.36 0.084 ;
    END
  END out_flit[522]
  PIN out_flit[523]
    DIRECTION OUTPUT ;
    USE SIGNAL ;
    PORT
      LAYER M5 ;
        RECT  36.432 0 36.456 0.084 ;
    END
  END out_flit[523]
  PIN out_flit[524]
    DIRECTION OUTPUT ;
    USE SIGNAL ;
    PORT
      LAYER M5 ;
        RECT  36.528 0 36.552 0.084 ;
    END
  END out_flit[524]
  PIN out_flit[525]
    DIRECTION OUTPUT ;
    USE SIGNAL ;
    PORT
      LAYER M5 ;
        RECT  36.624 0 36.648 0.084 ;
    END
  END out_flit[525]
  PIN out_flit[526]
    DIRECTION OUTPUT ;
    USE SIGNAL ;
    PORT
      LAYER M5 ;
        RECT  36.72 0 36.744 0.084 ;
    END
  END out_flit[526]
  PIN out_flit[527]
    DIRECTION OUTPUT ;
    USE SIGNAL ;
    PORT
      LAYER M5 ;
        RECT  36.816 0 36.84 0.084 ;
    END
  END out_flit[527]
  PIN out_flit[528]
    DIRECTION OUTPUT ;
    USE SIGNAL ;
    PORT
      LAYER M5 ;
        RECT  36.912 0 36.936 0.084 ;
    END
  END out_flit[528]
  PIN out_flit[529]
    DIRECTION OUTPUT ;
    USE SIGNAL ;
    PORT
      LAYER M5 ;
        RECT  37.008 0 37.032 0.084 ;
    END
  END out_flit[529]
  PIN out_flit[52]
    DIRECTION OUTPUT ;
    USE SIGNAL ;
    PORT
      LAYER M5 ;
        RECT  41.136 0 41.16 0.084 ;
    END
  END out_flit[52]
  PIN out_flit[530]
    DIRECTION OUTPUT ;
    USE SIGNAL ;
    PORT
      LAYER M5 ;
        RECT  37.104 0 37.128 0.084 ;
    END
  END out_flit[530]
  PIN out_flit[531]
    DIRECTION OUTPUT ;
    USE SIGNAL ;
    PORT
      LAYER M5 ;
        RECT  37.2 0 37.224 0.084 ;
    END
  END out_flit[531]
  PIN out_flit[532]
    DIRECTION OUTPUT ;
    USE SIGNAL ;
    PORT
      LAYER M5 ;
        RECT  37.296 0 37.32 0.084 ;
    END
  END out_flit[532]
  PIN out_flit[533]
    DIRECTION OUTPUT ;
    USE SIGNAL ;
    PORT
      LAYER M5 ;
        RECT  37.392 0 37.416 0.084 ;
    END
  END out_flit[533]
  PIN out_flit[534]
    DIRECTION OUTPUT ;
    USE SIGNAL ;
    PORT
      LAYER M5 ;
        RECT  37.488 0 37.512 0.084 ;
    END
  END out_flit[534]
  PIN out_flit[535]
    DIRECTION OUTPUT ;
    USE SIGNAL ;
    PORT
      LAYER M5 ;
        RECT  37.584 0 37.608 0.084 ;
    END
  END out_flit[535]
  PIN out_flit[536]
    DIRECTION OUTPUT ;
    USE SIGNAL ;
    PORT
      LAYER M5 ;
        RECT  37.68 0 37.704 0.084 ;
    END
  END out_flit[536]
  PIN out_flit[537]
    DIRECTION OUTPUT ;
    USE SIGNAL ;
    PORT
      LAYER M5 ;
        RECT  37.776 0 37.8 0.084 ;
    END
  END out_flit[537]
  PIN out_flit[538]
    DIRECTION OUTPUT ;
    USE SIGNAL ;
    PORT
      LAYER M5 ;
        RECT  37.872 0 37.896 0.084 ;
    END
  END out_flit[538]
  PIN out_flit[539]
    DIRECTION OUTPUT ;
    USE SIGNAL ;
    PORT
      LAYER M5 ;
        RECT  37.968 0 37.992 0.084 ;
    END
  END out_flit[539]
  PIN out_flit[53]
    DIRECTION OUTPUT ;
    USE SIGNAL ;
    PORT
      LAYER M5 ;
        RECT  41.232 0 41.256 0.084 ;
    END
  END out_flit[53]
  PIN out_flit[540]
    DIRECTION OUTPUT ;
    USE SIGNAL ;
    PORT
      LAYER M5 ;
        RECT  38.064 0 38.088 0.084 ;
    END
  END out_flit[540]
  PIN out_flit[541]
    DIRECTION OUTPUT ;
    USE SIGNAL ;
    PORT
      LAYER M5 ;
        RECT  38.16 0 38.184 0.084 ;
    END
  END out_flit[541]
  PIN out_flit[542]
    DIRECTION OUTPUT ;
    USE SIGNAL ;
    PORT
      LAYER M5 ;
        RECT  38.256 0 38.28 0.084 ;
    END
  END out_flit[542]
  PIN out_flit[543]
    DIRECTION OUTPUT ;
    USE SIGNAL ;
    PORT
      LAYER M5 ;
        RECT  77.52 0 77.544 0.084 ;
    END
  END out_flit[543]
  PIN out_flit[544]
    DIRECTION OUTPUT ;
    USE SIGNAL ;
    PORT
      LAYER M5 ;
        RECT  77.616 0 77.64 0.084 ;
    END
  END out_flit[544]
  PIN out_flit[54]
    DIRECTION OUTPUT ;
    USE SIGNAL ;
    PORT
      LAYER M5 ;
        RECT  41.328 0 41.352 0.084 ;
    END
  END out_flit[54]
  PIN out_flit[55]
    DIRECTION OUTPUT ;
    USE SIGNAL ;
    PORT
      LAYER M5 ;
        RECT  41.424 0 41.448 0.084 ;
    END
  END out_flit[55]
  PIN out_flit[56]
    DIRECTION OUTPUT ;
    USE SIGNAL ;
    PORT
      LAYER M5 ;
        RECT  41.52 0 41.544 0.084 ;
    END
  END out_flit[56]
  PIN out_flit[57]
    DIRECTION OUTPUT ;
    USE SIGNAL ;
    PORT
      LAYER M5 ;
        RECT  41.616 0 41.64 0.084 ;
    END
  END out_flit[57]
  PIN out_flit[58]
    DIRECTION OUTPUT ;
    USE SIGNAL ;
    PORT
      LAYER M5 ;
        RECT  41.712 0 41.736 0.084 ;
    END
  END out_flit[58]
  PIN out_flit[59]
    DIRECTION OUTPUT ;
    USE SIGNAL ;
    PORT
      LAYER M5 ;
        RECT  41.808 0 41.832 0.084 ;
    END
  END out_flit[59]
  PIN out_flit[5]
    DIRECTION OUTPUT ;
    USE SIGNAL ;
    PORT
      LAYER M5 ;
        RECT  45.84 0 45.864 0.084 ;
    END
  END out_flit[5]
  PIN out_flit[60]
    DIRECTION OUTPUT ;
    USE SIGNAL ;
    PORT
      LAYER M5 ;
        RECT  41.904 0 41.928 0.084 ;
    END
  END out_flit[60]
  PIN out_flit[61]
    DIRECTION OUTPUT ;
    USE SIGNAL ;
    PORT
      LAYER M5 ;
        RECT  42 0 42.024 0.084 ;
    END
  END out_flit[61]
  PIN out_flit[62]
    DIRECTION OUTPUT ;
    USE SIGNAL ;
    PORT
      LAYER M5 ;
        RECT  42.096 0 42.12 0.084 ;
    END
  END out_flit[62]
  PIN out_flit[63]
    DIRECTION OUTPUT ;
    USE SIGNAL ;
    PORT
      LAYER M5 ;
        RECT  54.48 0 54.504 0.084 ;
    END
  END out_flit[63]
  PIN out_flit[64]
    DIRECTION OUTPUT ;
    USE SIGNAL ;
    PORT
      LAYER M5 ;
        RECT  54.576 0 54.6 0.084 ;
    END
  END out_flit[64]
  PIN out_flit[65]
    DIRECTION OUTPUT ;
    USE SIGNAL ;
    PORT
      LAYER M5 ;
        RECT  54.672 0 54.696 0.084 ;
    END
  END out_flit[65]
  PIN out_flit[66]
    DIRECTION OUTPUT ;
    USE SIGNAL ;
    PORT
      LAYER M5 ;
        RECT  54.768 0 54.792 0.084 ;
    END
  END out_flit[66]
  PIN out_flit[67]
    DIRECTION OUTPUT ;
    USE SIGNAL ;
    PORT
      LAYER M5 ;
        RECT  54.864 0 54.888 0.084 ;
    END
  END out_flit[67]
  PIN out_flit[68]
    DIRECTION OUTPUT ;
    USE SIGNAL ;
    PORT
      LAYER M5 ;
        RECT  54.96 0 54.984 0.084 ;
    END
  END out_flit[68]
  PIN out_flit[69]
    DIRECTION OUTPUT ;
    USE SIGNAL ;
    PORT
      LAYER M5 ;
        RECT  55.056 0 55.08 0.084 ;
    END
  END out_flit[69]
  PIN out_flit[6]
    DIRECTION OUTPUT ;
    USE SIGNAL ;
    PORT
      LAYER M5 ;
        RECT  45.936 0 45.96 0.084 ;
    END
  END out_flit[6]
  PIN out_flit[70]
    DIRECTION OUTPUT ;
    USE SIGNAL ;
    PORT
      LAYER M5 ;
        RECT  55.152 0 55.176 0.084 ;
    END
  END out_flit[70]
  PIN out_flit[71]
    DIRECTION OUTPUT ;
    USE SIGNAL ;
    PORT
      LAYER M5 ;
        RECT  55.248 0 55.272 0.084 ;
    END
  END out_flit[71]
  PIN out_flit[72]
    DIRECTION OUTPUT ;
    USE SIGNAL ;
    PORT
      LAYER M5 ;
        RECT  55.344 0 55.368 0.084 ;
    END
  END out_flit[72]
  PIN out_flit[73]
    DIRECTION OUTPUT ;
    USE SIGNAL ;
    PORT
      LAYER M5 ;
        RECT  55.44 0 55.464 0.084 ;
    END
  END out_flit[73]
  PIN out_flit[74]
    DIRECTION OUTPUT ;
    USE SIGNAL ;
    PORT
      LAYER M5 ;
        RECT  55.536 0 55.56 0.084 ;
    END
  END out_flit[74]
  PIN out_flit[75]
    DIRECTION OUTPUT ;
    USE SIGNAL ;
    PORT
      LAYER M5 ;
        RECT  55.632 0 55.656 0.084 ;
    END
  END out_flit[75]
  PIN out_flit[76]
    DIRECTION OUTPUT ;
    USE SIGNAL ;
    PORT
      LAYER M5 ;
        RECT  55.728 0 55.752 0.084 ;
    END
  END out_flit[76]
  PIN out_flit[77]
    DIRECTION OUTPUT ;
    USE SIGNAL ;
    PORT
      LAYER M5 ;
        RECT  55.824 0 55.848 0.084 ;
    END
  END out_flit[77]
  PIN out_flit[78]
    DIRECTION OUTPUT ;
    USE SIGNAL ;
    PORT
      LAYER M5 ;
        RECT  55.92 0 55.944 0.084 ;
    END
  END out_flit[78]
  PIN out_flit[79]
    DIRECTION OUTPUT ;
    USE SIGNAL ;
    PORT
      LAYER M5 ;
        RECT  56.016 0 56.04 0.084 ;
    END
  END out_flit[79]
  PIN out_flit[7]
    DIRECTION OUTPUT ;
    USE SIGNAL ;
    PORT
      LAYER M5 ;
        RECT  46.032 0 46.056 0.084 ;
    END
  END out_flit[7]
  PIN out_flit[80]
    DIRECTION OUTPUT ;
    USE SIGNAL ;
    PORT
      LAYER M5 ;
        RECT  56.112 0 56.136 0.084 ;
    END
  END out_flit[80]
  PIN out_flit[81]
    DIRECTION OUTPUT ;
    USE SIGNAL ;
    PORT
      LAYER M5 ;
        RECT  56.208 0 56.232 0.084 ;
    END
  END out_flit[81]
  PIN out_flit[82]
    DIRECTION OUTPUT ;
    USE SIGNAL ;
    PORT
      LAYER M5 ;
        RECT  56.304 0 56.328 0.084 ;
    END
  END out_flit[82]
  PIN out_flit[83]
    DIRECTION OUTPUT ;
    USE SIGNAL ;
    PORT
      LAYER M5 ;
        RECT  56.4 0 56.424 0.084 ;
    END
  END out_flit[83]
  PIN out_flit[84]
    DIRECTION OUTPUT ;
    USE SIGNAL ;
    PORT
      LAYER M5 ;
        RECT  56.496 0 56.52 0.084 ;
    END
  END out_flit[84]
  PIN out_flit[85]
    DIRECTION OUTPUT ;
    USE SIGNAL ;
    PORT
      LAYER M5 ;
        RECT  56.592 0 56.616 0.084 ;
    END
  END out_flit[85]
  PIN out_flit[86]
    DIRECTION OUTPUT ;
    USE SIGNAL ;
    PORT
      LAYER M5 ;
        RECT  56.688 0 56.712 0.084 ;
    END
  END out_flit[86]
  PIN out_flit[87]
    DIRECTION OUTPUT ;
    USE SIGNAL ;
    PORT
      LAYER M5 ;
        RECT  56.784 0 56.808 0.084 ;
    END
  END out_flit[87]
  PIN out_flit[88]
    DIRECTION OUTPUT ;
    USE SIGNAL ;
    PORT
      LAYER M5 ;
        RECT  56.88 0 56.904 0.084 ;
    END
  END out_flit[88]
  PIN out_flit[89]
    DIRECTION OUTPUT ;
    USE SIGNAL ;
    PORT
      LAYER M5 ;
        RECT  56.976 0 57 0.084 ;
    END
  END out_flit[89]
  PIN out_flit[8]
    DIRECTION OUTPUT ;
    USE SIGNAL ;
    PORT
      LAYER M5 ;
        RECT  46.128 0 46.152 0.084 ;
    END
  END out_flit[8]
  PIN out_flit[90]
    DIRECTION OUTPUT ;
    USE SIGNAL ;
    PORT
      LAYER M5 ;
        RECT  57.072 0 57.096 0.084 ;
    END
  END out_flit[90]
  PIN out_flit[91]
    DIRECTION OUTPUT ;
    USE SIGNAL ;
    PORT
      LAYER M5 ;
        RECT  57.168 0 57.192 0.084 ;
    END
  END out_flit[91]
  PIN out_flit[92]
    DIRECTION OUTPUT ;
    USE SIGNAL ;
    PORT
      LAYER M5 ;
        RECT  57.264 0 57.288 0.084 ;
    END
  END out_flit[92]
  PIN out_flit[93]
    DIRECTION OUTPUT ;
    USE SIGNAL ;
    PORT
      LAYER M5 ;
        RECT  57.36 0 57.384 0.084 ;
    END
  END out_flit[93]
  PIN out_flit[94]
    DIRECTION OUTPUT ;
    USE SIGNAL ;
    PORT
      LAYER M5 ;
        RECT  57.456 0 57.48 0.084 ;
    END
  END out_flit[94]
  PIN out_flit[95]
    DIRECTION OUTPUT ;
    USE SIGNAL ;
    PORT
      LAYER M5 ;
        RECT  48.336 0 48.36 0.084 ;
    END
  END out_flit[95]
  PIN out_flit[96]
    DIRECTION OUTPUT ;
    USE SIGNAL ;
    PORT
      LAYER M5 ;
        RECT  48.432 0 48.456 0.084 ;
    END
  END out_flit[96]
  PIN out_flit[97]
    DIRECTION OUTPUT ;
    USE SIGNAL ;
    PORT
      LAYER M5 ;
        RECT  48.528 0 48.552 0.084 ;
    END
  END out_flit[97]
  PIN out_flit[98]
    DIRECTION OUTPUT ;
    USE SIGNAL ;
    PORT
      LAYER M5 ;
        RECT  48.624 0 48.648 0.084 ;
    END
  END out_flit[98]
  PIN out_flit[99]
    DIRECTION OUTPUT ;
    USE SIGNAL ;
    PORT
      LAYER M5 ;
        RECT  48.72 0 48.744 0.084 ;
    END
  END out_flit[99]
  PIN out_flit[9]
    DIRECTION OUTPUT ;
    USE SIGNAL ;
    PORT
      LAYER M5 ;
        RECT  46.224 0 46.248 0.084 ;
    END
  END out_flit[9]
  PIN out_v
    DIRECTION OUTPUT ;
    USE SIGNAL ;
    PORT
      LAYER M5 ;
        RECT  77.712 0 77.736 0.084 ;
    END
  END out_v
  PIN publish_slot
    DIRECTION INPUT ;
    USE SIGNAL ;
    PORT
      LAYER M5 ;
        RECT  46.608 47.436 46.632 47.52 ;
    END
  END publish_slot
  PIN rst_n
    DIRECTION INPUT ;
    USE SIGNAL ;
    PORT
      LAYER M4 ;
        RECT  0 11.28 0.084 11.304 ;
    END
  END rst_n
  PIN start
    DIRECTION INPUT ;
    USE SIGNAL ;
    PORT
      LAYER M4 ;
        RECT  0 11.376 0.084 11.4 ;
    END
  END start
  PIN VDD
    DIRECTION INOUT ;
    USE POWER ;
    PORT
      LAYER M5 ;
        RECT  88.992 2.151 89.112 45.369 ;
        RECT  83.592 2.151 83.712 45.369 ;
        RECT  78.192 2.151 78.312 45.369 ;
        RECT  72.792 2.151 72.912 45.369 ;
        RECT  67.392 2.151 67.512 45.369 ;
        RECT  61.992 2.151 62.112 45.369 ;
        RECT  56.592 2.151 56.712 45.369 ;
        RECT  51.192 2.151 51.312 45.369 ;
        RECT  45.792 2.151 45.912 45.369 ;
        RECT  40.392 2.151 40.512 45.369 ;
        RECT  34.992 2.151 35.112 45.369 ;
        RECT  29.592 2.151 29.712 45.369 ;
        RECT  24.192 2.151 24.312 45.369 ;
        RECT  18.792 2.151 18.912 45.369 ;
        RECT  13.392 2.151 13.512 45.369 ;
        RECT  7.992 2.151 8.112 45.369 ;
        RECT  2.592 2.151 2.712 45.369 ;
    END
  END VDD
  PIN VSS
    DIRECTION INOUT ;
    USE GROUND ;
    PORT
      LAYER M5 ;
        RECT  88.8 2.137 88.92 45.383 ;
        RECT  83.4 2.137 83.52 45.383 ;
        RECT  78 2.137 78.12 45.383 ;
        RECT  72.6 2.137 72.72 45.383 ;
        RECT  67.2 2.137 67.32 45.383 ;
        RECT  61.8 2.137 61.92 45.383 ;
        RECT  56.4 2.137 56.52 45.383 ;
        RECT  51 2.137 51.12 45.383 ;
        RECT  45.6 2.137 45.72 45.383 ;
        RECT  40.2 2.137 40.32 45.383 ;
        RECT  34.8 2.137 34.92 45.383 ;
        RECT  29.4 2.137 29.52 45.383 ;
        RECT  24 2.137 24.12 45.383 ;
        RECT  18.6 2.137 18.72 45.383 ;
        RECT  13.2 2.137 13.32 45.383 ;
        RECT  7.8 2.137 7.92 45.383 ;
        RECT  2.4 2.137 2.52 45.383 ;
    END
  END VSS
  # OT_OBS_CLOSED layer=M5 d_um=1.536 added=244
  OBS
    LAYER RVTN ;
     RECT  2.16 2.16 92.88 2.295 ;
     RECT  2.16 2.565 92.88 2.835 ;
     RECT  2.16 3.105 92.88 3.375 ;
     RECT  2.16 3.645 92.88 3.915 ;
     RECT  2.16 4.185 92.88 4.455 ;
     RECT  2.16 4.725 92.88 4.995 ;
     RECT  2.16 5.265 92.88 5.535 ;
     RECT  2.16 5.805 92.88 6.075 ;
     RECT  2.16 6.345 92.88 6.615 ;
     RECT  2.16 6.885 92.88 7.155 ;
     RECT  2.16 7.425 92.88 7.695 ;
     RECT  2.16 7.965 92.88 8.235 ;
     RECT  2.16 8.505 92.88 8.775 ;
     RECT  2.16 9.045 92.88 9.315 ;
     RECT  2.16 9.585 92.88 9.855 ;
     RECT  2.16 10.125 92.88 10.395 ;
     RECT  2.16 10.665 92.88 10.935 ;
     RECT  2.16 11.205 92.88 11.475 ;
     RECT  2.16 11.745 92.88 12.015 ;
     RECT  2.16 12.285 92.88 12.555 ;
     RECT  2.16 12.825 92.88 13.095 ;
     RECT  2.16 13.365 92.88 13.635 ;
     RECT  2.16 13.905 92.88 14.175 ;
     RECT  2.16 14.445 92.88 14.715 ;
     RECT  2.16 14.985 92.88 15.255 ;
     RECT  2.16 15.525 92.88 15.795 ;
     RECT  2.16 16.065 92.88 16.335 ;
     RECT  2.16 16.605 92.88 16.875 ;
     RECT  2.16 17.145 92.88 17.415 ;
     RECT  2.16 17.685 92.88 17.955 ;
     RECT  2.16 18.225 92.88 18.495 ;
     RECT  2.16 18.765 92.88 19.035 ;
     RECT  2.16 19.305 92.88 19.575 ;
     RECT  2.16 19.845 92.88 20.115 ;
     RECT  2.16 20.385 92.88 20.655 ;
     RECT  2.16 20.925 92.88 21.195 ;
     RECT  2.16 21.465 92.88 21.735 ;
     RECT  2.16 22.005 92.88 22.275 ;
     RECT  2.16 22.545 92.88 22.815 ;
     RECT  2.16 23.085 92.88 23.355 ;
     RECT  2.16 23.625 92.88 23.895 ;
     RECT  2.16 24.165 92.88 24.435 ;
     RECT  2.16 24.705 92.88 24.975 ;
     RECT  2.16 25.245 92.88 25.515 ;
     RECT  2.16 25.785 92.88 26.055 ;
     RECT  2.16 26.325 92.88 26.595 ;
     RECT  2.16 26.865 92.88 27.135 ;
     RECT  2.16 27.405 92.88 27.675 ;
     RECT  2.16 27.945 92.88 28.215 ;
     RECT  2.16 28.485 92.88 28.755 ;
     RECT  2.16 29.025 92.88 29.295 ;
     RECT  2.16 29.565 92.88 29.835 ;
     RECT  2.16 30.105 92.88 30.375 ;
     RECT  2.16 30.645 92.88 30.915 ;
     RECT  2.16 31.185 92.88 31.455 ;
     RECT  2.16 31.725 92.88 31.995 ;
     RECT  2.16 32.265 92.88 32.535 ;
     RECT  2.16 32.805 92.88 33.075 ;
     RECT  2.16 33.345 92.88 33.615 ;
     RECT  2.16 33.885 92.88 34.155 ;
     RECT  2.16 34.425 92.88 34.695 ;
     RECT  2.16 34.965 92.88 35.235 ;
     RECT  2.16 35.505 92.88 35.775 ;
     RECT  2.16 36.045 92.88 36.315 ;
     RECT  2.16 36.585 92.88 36.855 ;
     RECT  2.16 37.125 92.88 37.395 ;
     RECT  2.16 37.665 92.88 37.935 ;
     RECT  2.16 38.205 92.88 38.475 ;
     RECT  2.16 38.745 92.88 39.015 ;
     RECT  2.16 39.285 92.88 39.555 ;
     RECT  2.16 39.825 92.88 40.095 ;
     RECT  2.16 40.365 92.88 40.635 ;
     RECT  2.16 40.905 92.88 41.175 ;
     RECT  2.16 41.445 92.88 41.715 ;
     RECT  2.16 41.985 92.88 42.255 ;
     RECT  2.16 42.525 92.88 42.795 ;
     RECT  2.16 43.065 92.88 43.335 ;
     RECT  2.16 43.605 92.88 43.875 ;
     RECT  2.16 44.145 92.88 44.415 ;
     RECT  2.16 44.685 92.88 44.955 ;
     RECT  2.16 45.225 92.88 45.36 ;
    LAYER RVTP ;
     RECT  2.16 2.295 92.88 2.565 ;
     RECT  2.16 2.835 92.88 3.105 ;
     RECT  2.16 3.375 92.88 3.645 ;
     RECT  2.16 3.915 92.88 4.185 ;
     RECT  2.16 4.455 92.88 4.725 ;
     RECT  2.16 4.995 92.88 5.265 ;
     RECT  2.16 5.535 92.88 5.805 ;
     RECT  2.16 6.075 92.88 6.345 ;
     RECT  2.16 6.615 92.88 6.885 ;
     RECT  2.16 7.155 92.88 7.425 ;
     RECT  2.16 7.695 92.88 7.965 ;
     RECT  2.16 8.235 92.88 8.505 ;
     RECT  2.16 8.775 92.88 9.045 ;
     RECT  2.16 9.315 92.88 9.585 ;
     RECT  2.16 9.855 92.88 10.125 ;
     RECT  2.16 10.395 92.88 10.665 ;
     RECT  2.16 10.935 92.88 11.205 ;
     RECT  2.16 11.475 92.88 11.745 ;
     RECT  2.16 12.015 92.88 12.285 ;
     RECT  2.16 12.555 92.88 12.825 ;
     RECT  2.16 13.095 92.88 13.365 ;
     RECT  2.16 13.635 92.88 13.905 ;
     RECT  2.16 14.175 92.88 14.445 ;
     RECT  2.16 14.715 92.88 14.985 ;
     RECT  2.16 15.255 92.88 15.525 ;
     RECT  2.16 15.795 92.88 16.065 ;
     RECT  2.16 16.335 92.88 16.605 ;
     RECT  2.16 16.875 92.88 17.145 ;
     RECT  2.16 17.415 92.88 17.685 ;
     RECT  2.16 17.955 92.88 18.225 ;
     RECT  2.16 18.495 92.88 18.765 ;
     RECT  2.16 19.035 92.88 19.305 ;
     RECT  2.16 19.575 92.88 19.845 ;
     RECT  2.16 20.115 92.88 20.385 ;
     RECT  2.16 20.655 92.88 20.925 ;
     RECT  2.16 21.195 92.88 21.465 ;
     RECT  2.16 21.735 92.88 22.005 ;
     RECT  2.16 22.275 92.88 22.545 ;
     RECT  2.16 22.815 92.88 23.085 ;
     RECT  2.16 23.355 92.88 23.625 ;
     RECT  2.16 23.895 92.88 24.165 ;
     RECT  2.16 24.435 92.88 24.705 ;
     RECT  2.16 24.975 92.88 25.245 ;
     RECT  2.16 25.515 92.88 25.785 ;
     RECT  2.16 26.055 92.88 26.325 ;
     RECT  2.16 26.595 92.88 26.865 ;
     RECT  2.16 27.135 92.88 27.405 ;
     RECT  2.16 27.675 92.88 27.945 ;
     RECT  2.16 28.215 92.88 28.485 ;
     RECT  2.16 28.755 92.88 29.025 ;
     RECT  2.16 29.295 92.88 29.565 ;
     RECT  2.16 29.835 92.88 30.105 ;
     RECT  2.16 30.375 92.88 30.645 ;
     RECT  2.16 30.915 92.88 31.185 ;
     RECT  2.16 31.455 92.88 31.725 ;
     RECT  2.16 31.995 92.88 32.265 ;
     RECT  2.16 32.535 92.88 32.805 ;
     RECT  2.16 33.075 92.88 33.345 ;
     RECT  2.16 33.615 92.88 33.885 ;
     RECT  2.16 34.155 92.88 34.425 ;
     RECT  2.16 34.695 92.88 34.965 ;
     RECT  2.16 35.235 92.88 35.505 ;
     RECT  2.16 35.775 92.88 36.045 ;
     RECT  2.16 36.315 92.88 36.585 ;
     RECT  2.16 36.855 92.88 37.125 ;
     RECT  2.16 37.395 92.88 37.665 ;
     RECT  2.16 37.935 92.88 38.205 ;
     RECT  2.16 38.475 92.88 38.745 ;
     RECT  2.16 39.015 92.88 39.285 ;
     RECT  2.16 39.555 92.88 39.825 ;
     RECT  2.16 40.095 92.88 40.365 ;
     RECT  2.16 40.635 92.88 40.905 ;
     RECT  2.16 41.175 92.88 41.445 ;
     RECT  2.16 41.715 92.88 41.985 ;
     RECT  2.16 42.255 92.88 42.525 ;
     RECT  2.16 42.795 92.88 43.065 ;
     RECT  2.16 43.335 92.88 43.605 ;
     RECT  2.16 43.875 92.88 44.145 ;
     RECT  2.16 44.415 92.88 44.685 ;
     RECT  2.16 44.955 92.88 45.225 ;
    LAYER M1 ;
     RECT  2.16 2.151 92.88 45.369 ;
    LAYER M2 ;
     RECT  0.103 9.486 0.139 9.504 ;
     RECT  0.031 14.796 0.167 14.814 ;
     RECT  0.139 9.486 0.203 10.224 ;
     RECT  0.203 9.9 0.283 10.224 ;
     RECT  0.103 11.178 0.283 11.196 ;
     RECT  0.283 9.9 0.419 11.196 ;
     RECT  0.535 8.784 2.16 8.802 ;
     RECT  0.419 9.9 2.16 10.188 ;
     RECT  0.419 11.178 2.16 11.196 ;
     RECT  0.031 33.426 2.16 33.444 ;
     RECT  2.16 2.151 3.703 45.369 ;
     RECT  3.703 2.151 6.835 45.486 ;
     RECT  6.835 2.151 12.407 45.594 ;
     RECT  12.407 2.151 17.447 45.486 ;
     RECT  18.967 46.62 19.039 46.638 ;
     RECT  19.039 46.62 19.067 46.719 ;
     RECT  19.067 46.701 19.139 46.719 ;
     RECT  17.447 2.151 20.443 45.414 ;
     RECT  20.443 2.151 20.479 45.486 ;
     RECT  20.479 2.151 20.623 45.522 ;
     RECT  20.623 2.151 21.983 45.558 ;
     RECT  21.983 2.151 23.387 45.522 ;
     RECT  23.387 2.151 24.539 45.486 ;
     RECT  24.539 2.151 30.163 45.369 ;
     RECT  30.163 2.151 34.619 45.864 ;
     RECT  34.771 46.161 35.699 46.179 ;
     RECT  37.255 46.242 37.355 46.26 ;
     RECT  34.619 2.151 37.507 45.369 ;
     RECT  37.507 2.151 38.695 45.486 ;
     RECT  38.695 2.106 39.263 45.486 ;
     RECT  39.263 2.106 39.515 45.414 ;
     RECT  39.515 2.106 42.799 45.369 ;
     RECT  42.799 2.034 44.699 45.369 ;
     RECT  44.699 2.106 44.995 45.369 ;
     RECT  44.995 2.106 45.283 45.414 ;
     RECT  45.283 2.106 46.859 45.864 ;
     RECT  46.859 2.151 65.003 45.864 ;
     RECT  65.003 2.151 67.027 45.369 ;
     RECT  67.027 2.151 67.739 45.414 ;
     RECT  67.739 2.151 92.88 45.369 ;
    LAYER M3 ;
     RECT  52.812 0.043 52.83 0.091 ;
     RECT  48.168 0.091 49.122 0.139 ;
     RECT  49.932 0.091 57.186 0.139 ;
     RECT  80.784 0.091 83.25 0.523 ;
     RECT  26.136 0.091 36.666 0.571 ;
     RECT  26.136 0.571 37.674 1.147 ;
     RECT  26.136 1.147 38.034 1.723 ;
     RECT  39.42 0.091 46.818 1.723 ;
     RECT  48.024 0.139 57.33 1.723 ;
     RECT  58.428 0.091 76.626 1.723 ;
     RECT  77.544 0.571 77.562 1.723 ;
     RECT  80.784 0.523 83.574 1.723 ;
     RECT  26.028 1.723 38.322 1.771 ;
     RECT  39.06 1.723 47.142 1.771 ;
     RECT  48.024 1.723 57.366 1.771 ;
     RECT  58.32 1.723 76.626 1.771 ;
     RECT  77.544 1.723 77.634 2.143 ;
     RECT  26.028 1.771 57.546 2.219 ;
     RECT  58.32 1.771 76.806 2.219 ;
     RECT  80.532 1.723 83.61 2.219 ;
     RECT  77.544 2.143 78.105 2.255 ;
     RECT  2.415 2.143 2.505 2.413 ;
     RECT  7.815 2.143 7.905 2.413 ;
     RECT  13.215 2.143 13.305 2.413 ;
     RECT  18.615 2.143 18.705 2.413 ;
     RECT  24.015 2.143 24.105 2.413 ;
     RECT  78.015 2.255 78.105 2.413 ;
     RECT  80.784 2.219 83.61 2.413 ;
     RECT  88.815 2.143 88.905 2.413 ;
     RECT  26.136 2.219 57.33 2.525 ;
     RECT  58.428 2.219 76.626 2.525 ;
     RECT  80.784 2.413 83.697 2.525 ;
     RECT  54.864 2.525 56.754 2.597 ;
     RECT  50.94 2.525 52.146 2.669 ;
     RECT  28.692 2.525 29.697 2.759 ;
     RECT  31.752 2.525 31.77 2.759 ;
     RECT  36.756 2.525 39.438 2.759 ;
     RECT  41.58 2.525 50.13 2.759 ;
     RECT  51.015 2.669 52.146 2.759 ;
     RECT  53.028 2.525 53.118 2.759 ;
     RECT  54.864 2.597 56.697 2.759 ;
     RECT  67.215 2.525 68.058 2.759 ;
     RECT  69.552 2.525 69.57 2.759 ;
     RECT  72.615 2.525 73.674 2.759 ;
     RECT  82.26 2.525 82.278 2.759 ;
     RECT  36.756 2.759 38.718 3.029 ;
     RECT  40.176 2.525 40.626 3.029 ;
     RECT  40.215 3.029 40.626 3.053 ;
     RECT  58.428 2.525 59.49 3.073 ;
     RECT  34.776 2.525 35.097 3.137 ;
     RECT  41.58 2.759 43.038 3.271 ;
     RECT  58.14 3.073 59.49 3.271 ;
     RECT  44.172 2.759 50.058 3.299 ;
     RECT  35.856 2.525 36.018 3.341 ;
     RECT  41.436 3.271 43.038 3.379 ;
     RECT  41.328 3.379 43.038 3.407 ;
     RECT  53.1 2.759 53.118 3.415 ;
     RECT  55.8 2.759 56.697 3.415 ;
     RECT  57.456 3.271 59.49 3.415 ;
     RECT  60.264 2.525 62.838 3.415 ;
     RECT  53.1 3.415 53.514 3.451 ;
     RECT  55.8 3.415 63.054 3.451 ;
     RECT  64.944 3.379 64.962 3.451 ;
     RECT  55.8 3.451 63.378 3.577 ;
     RECT  64.404 3.451 64.962 3.577 ;
     RECT  66.456 3.577 66.474 3.613 ;
     RECT  67.215 2.759 67.497 3.613 ;
     RECT  13.215 2.413 13.497 3.685 ;
     RECT  55.8 3.577 64.962 3.685 ;
     RECT  65.7 3.577 65.718 3.685 ;
     RECT  36 3.341 36.018 3.713 ;
     RECT  54.864 2.759 54.882 3.721 ;
     RECT  45.252 3.299 49.95 3.839 ;
     RECT  54.504 3.721 54.882 3.847 ;
     RECT  55.8 3.685 65.718 3.847 ;
     RECT  53.1 3.451 53.586 3.883 ;
     RECT  54.504 3.847 65.718 3.883 ;
     RECT  44.172 3.299 44.478 3.955 ;
     RECT  68.832 3.451 68.85 3.955 ;
     RECT  36.9 3.029 38.718 3.979 ;
     RECT  51.015 2.759 51.297 3.991 ;
     RECT  53.1 3.883 65.718 3.991 ;
     RECT  66.456 3.613 67.497 3.991 ;
     RECT  68.832 3.955 68.958 3.991 ;
     RECT  52.236 3.955 52.254 4.081 ;
     RECT  53.1 3.991 67.497 4.081 ;
     RECT  52.236 4.081 67.497 4.109 ;
     RECT  58.32 4.109 67.497 4.117 ;
     RECT  68.724 3.991 68.958 4.117 ;
     RECT  49.932 3.839 49.95 4.181 ;
     RECT  43.812 3.955 44.478 4.261 ;
     RECT  45.252 3.839 49.158 4.261 ;
     RECT  58.32 4.117 68.958 4.261 ;
     RECT  58.32 4.261 69.354 4.423 ;
     RECT  52.236 4.109 57.582 4.459 ;
     RECT  50.868 3.991 51.297 4.555 ;
     RECT  36.432 3.979 38.718 4.649 ;
     RECT  43.812 4.261 49.158 4.649 ;
     RECT  36.432 4.649 37.134 4.801 ;
     RECT  35.964 4.801 37.134 4.829 ;
     RECT  40.215 3.053 40.497 4.891 ;
     RECT  41.328 3.407 41.454 4.891 ;
     RECT  37.98 4.649 38.718 4.919 ;
     RECT  36.756 4.829 37.134 4.955 ;
     RECT  10.764 3.307 10.782 4.963 ;
     RECT  58.32 4.423 69.786 4.999 ;
     RECT  52.128 4.459 57.582 5.035 ;
     RECT  50.832 4.555 51.297 5.071 ;
     RECT  52.02 5.035 57.582 5.071 ;
     RECT  58.32 4.999 69.894 5.071 ;
     RECT  40.215 4.891 41.454 5.161 ;
     RECT  42.264 3.407 43.038 5.161 ;
     RECT  71.208 4.891 71.226 5.161 ;
     RECT  36.756 4.955 36.918 5.189 ;
     RECT  43.812 4.649 49.05 5.189 ;
     RECT  50.832 5.071 57.582 5.197 ;
     RECT  58.32 5.071 70.146 5.197 ;
     RECT  10.764 4.963 11.142 5.269 ;
     RECT  70.884 5.161 71.226 5.269 ;
     RECT  50.832 5.197 70.146 5.341 ;
     RECT  70.884 5.269 71.262 5.341 ;
     RECT  35.964 4.829 35.982 5.405 ;
     RECT  50.832 5.341 71.262 5.431 ;
     RECT  50.832 5.431 71.658 5.503 ;
     RECT  50.832 5.503 71.802 5.575 ;
     RECT  40.215 5.161 43.038 5.845 ;
     RECT  50.796 5.575 71.802 5.971 ;
     RECT  72.615 2.759 72.897 5.971 ;
     RECT  50.796 5.971 72.897 6.043 ;
     RECT  50.76 6.043 72.897 6.071 ;
     RECT  45.288 5.189 48.978 6.385 ;
     RECT  50.76 6.071 69.75 6.583 ;
     RECT  45.288 6.385 49.338 6.691 ;
     RECT  50.112 6.583 69.75 6.691 ;
     RECT  6.768 3.109 6.786 6.853 ;
     RECT  6.696 6.853 6.786 6.881 ;
     RECT  45.288 6.691 69.75 6.961 ;
     RECT  70.488 6.071 72.897 6.961 ;
     RECT  45.288 6.961 72.897 7.771 ;
     RECT  13.215 3.685 13.95 8.239 ;
     RECT  36.756 5.189 36.774 8.267 ;
     RECT  34.815 3.137 35.097 8.671 ;
     RECT  13.215 8.239 14.238 8.699 ;
     RECT  2.415 2.413 2.697 8.779 ;
     RECT  40.215 5.845 43.074 8.851 ;
     RECT  32.688 8.815 32.706 8.861 ;
     RECT  10.764 5.269 11.682 8.941 ;
     RECT  9.936 4.351 9.954 8.977 ;
     RECT  10.692 8.941 12.078 8.977 ;
     RECT  6.696 6.881 6.714 9.013 ;
     RECT  34.236 8.671 35.097 9.067 ;
     RECT  2.412 8.779 2.697 9.085 ;
     RECT  3.42 8.851 3.438 9.085 ;
     RECT  6.696 9.013 6.786 9.085 ;
     RECT  9.432 8.977 12.078 9.085 ;
     RECT  33.66 9.067 35.097 9.101 ;
     RECT  6.696 9.085 7.038 9.121 ;
     RECT  7.815 2.413 8.097 9.121 ;
     RECT  33.66 9.101 33.678 9.149 ;
     RECT  2.412 9.085 3.438 9.163 ;
     RECT  9.432 9.085 12.222 9.211 ;
     RECT  5.796 5.071 5.814 9.247 ;
     RECT  0.54 8.779 0.558 9.307 ;
     RECT  5.724 9.247 5.814 9.349 ;
     RECT  2.304 9.163 3.438 9.391 ;
     RECT  4.176 8.815 4.59 9.391 ;
     RECT  5.328 9.349 5.814 9.391 ;
     RECT  6.624 9.121 8.097 9.391 ;
     RECT  0.144 9.307 0.558 9.481 ;
     RECT  14.22 8.699 14.238 9.509 ;
     RECT  9.144 9.211 12.222 9.517 ;
     RECT  9.144 9.517 12.258 9.595 ;
     RECT  9.108 9.595 12.258 9.617 ;
     RECT  10.692 9.617 12.258 9.625 ;
     RECT  13.215 8.699 13.497 9.625 ;
     RECT  2.304 9.391 8.097 9.787 ;
     RECT  9.108 9.617 9.954 9.787 ;
     RECT  2.304 9.787 9.954 9.815 ;
     RECT  39.852 8.851 43.074 9.823 ;
     RECT  43.812 5.189 44.478 9.823 ;
     RECT  10.692 9.625 13.554 9.887 ;
     RECT  11.592 9.887 13.554 10.049 ;
     RECT  2.34 9.815 9.954 10.085 ;
     RECT  39.852 9.823 44.478 10.327 ;
     RECT  45.288 7.771 73.458 10.327 ;
     RECT  0.108 9.481 0.558 10.445 ;
     RECT  2.415 10.085 9.954 10.471 ;
     RECT  10.692 9.887 10.818 10.471 ;
     RECT  0.108 10.445 0.486 10.829 ;
     RECT  2.415 10.471 10.818 10.859 ;
     RECT  11.592 10.049 13.497 10.859 ;
     RECT  5.688 10.859 10.818 11.003 ;
     RECT  39.852 10.327 73.458 11.011 ;
     RECT  0.108 10.829 0.342 11.201 ;
     RECT  36.828 9.661 36.846 11.209 ;
     RECT  5.688 11.003 10.206 11.273 ;
     RECT  2.415 10.859 4.95 11.281 ;
     RECT  38.7 4.919 38.718 11.281 ;
     RECT  0.144 11.201 0.342 11.309 ;
     RECT  39.852 11.011 73.53 11.371 ;
     RECT  6.264 11.273 10.206 11.399 ;
     RECT  2.304 11.281 4.95 11.405 ;
     RECT  6.264 11.399 9.918 11.579 ;
     RECT  11.196 11.611 11.214 11.669 ;
     RECT  12.276 10.859 13.497 11.677 ;
     RECT  14.544 11.641 14.562 11.677 ;
     RECT  34.815 9.101 35.097 11.677 ;
     RECT  21.816 11.677 21.834 11.713 ;
     RECT  12.276 11.677 14.562 11.749 ;
     RECT  38.7 11.281 38.79 11.785 ;
     RECT  12.276 11.749 14.67 11.821 ;
     RECT  18.615 2.413 18.897 11.821 ;
     RECT  21.816 11.713 22.194 11.821 ;
     RECT  10.836 11.749 10.926 11.849 ;
     RECT  17.676 11.641 17.694 11.911 ;
     RECT  18.468 11.821 18.897 11.911 ;
     RECT  6.264 11.579 9.846 11.939 ;
     RECT  10.836 11.849 10.854 11.939 ;
     RECT  12.276 11.821 14.742 11.947 ;
     RECT  20.628 11.821 21.078 11.947 ;
     RECT  39.852 11.371 73.638 11.947 ;
     RECT  12.276 11.947 14.814 11.981 ;
     RECT  15.624 11.911 15.642 11.983 ;
     RECT  16.452 11.821 16.65 11.983 ;
     RECT  14.436 11.981 14.814 12.019 ;
     RECT  38.376 11.785 38.79 12.019 ;
     RECT  17.676 11.911 18.897 12.055 ;
     RECT  19.944 11.947 21.078 12.055 ;
     RECT  21.816 11.821 22.482 12.055 ;
     RECT  6.264 11.939 9.342 12.083 ;
     RECT  14.436 12.019 14.886 12.091 ;
     RECT  15.624 11.983 16.65 12.091 ;
     RECT  2.415 11.405 4.95 12.209 ;
     RECT  14.436 12.091 16.758 12.217 ;
     RECT  17.676 12.055 21.078 12.217 ;
     RECT  21.816 12.055 22.842 12.217 ;
     RECT  2.415 12.209 3.402 12.245 ;
     RECT  24.015 2.413 24.297 12.253 ;
     RECT  38.376 12.019 38.97 12.253 ;
     RECT  23.976 12.253 24.297 12.289 ;
     RECT  14.436 12.217 22.842 12.325 ;
     RECT  23.976 12.289 24.642 12.325 ;
     RECT  23.94 12.325 24.642 12.361 ;
     RECT  23.868 12.361 25.434 12.451 ;
     RECT  26.208 12.361 26.226 12.451 ;
     RECT  37.944 12.253 38.97 12.487 ;
     RECT  14.436 12.325 23.022 12.523 ;
     RECT  23.868 12.451 26.226 12.523 ;
     RECT  37.8 12.487 38.97 12.523 ;
     RECT  39.708 11.947 73.638 12.523 ;
     RECT  14.436 12.523 26.226 12.551 ;
     RECT  37.8 12.523 73.638 12.595 ;
     RECT  4.428 12.209 4.95 12.893 ;
     RECT  9.18 12.083 9.198 12.929 ;
     RECT  12.276 11.981 13.497 13.027 ;
     RECT  14.436 12.551 25.074 13.027 ;
     RECT  12.276 13.027 25.074 13.333 ;
     RECT  25.884 12.551 25.902 13.333 ;
     RECT  12.276 13.333 25.902 13.567 ;
     RECT  37.8 12.595 73.674 13.567 ;
     RECT  12.276 13.567 26.082 13.711 ;
     RECT  12.276 13.711 26.19 13.945 ;
     RECT  27 13.567 27.018 13.945 ;
     RECT  36.828 11.209 36.918 13.945 ;
     RECT  37.8 13.567 73.71 13.945 ;
     RECT  74.448 12.253 74.466 14.107 ;
     RECT  36.828 13.945 73.71 14.143 ;
     RECT  74.448 14.107 74.61 14.143 ;
     RECT  36.828 14.143 74.61 14.251 ;
     RECT  75.528 12.091 75.546 14.251 ;
     RECT  0.144 11.309 0.162 14.791 ;
     RECT  12.276 13.945 27.018 14.791 ;
     RECT  0.036 14.791 0.162 14.819 ;
     RECT  76.464 14.719 76.482 15.061 ;
     RECT  76.464 15.061 76.698 15.179 ;
     RECT  36.828 14.251 75.546 15.211 ;
     RECT  12.276 14.791 27.09 15.223 ;
     RECT  12.276 15.223 27.162 15.259 ;
     RECT  12.276 15.259 27.234 15.493 ;
     RECT  36.828 15.211 75.582 15.601 ;
     RECT  76.464 15.179 76.482 15.601 ;
     RECT  11.664 15.493 27.234 15.961 ;
     RECT  36.828 15.601 76.482 15.961 ;
     RECT  11.664 15.961 27.846 15.997 ;
     RECT  30.852 16.033 30.87 16.133 ;
     RECT  4.932 12.893 4.95 16.169 ;
     RECT  11.664 15.997 28.026 16.267 ;
     RECT  6.264 12.083 8.097 16.439 ;
     RECT  11.664 16.267 28.602 16.439 ;
     RECT  11.664 16.439 28.314 16.445 ;
     RECT  10.836 16.411 10.854 16.529 ;
     RECT  11.808 16.445 28.314 17.411 ;
     RECT  36.324 15.961 76.482 17.419 ;
     RECT  36.324 17.419 76.518 17.491 ;
     RECT  11.808 17.411 27.954 17.915 ;
     RECT  16.848 17.915 27.954 17.951 ;
     RECT  36.324 17.491 76.95 18.265 ;
     RECT  36.324 18.265 76.986 18.427 ;
     RECT  11.808 17.915 16.074 18.571 ;
     RECT  34.815 11.677 35.514 18.619 ;
     RECT  36.324 18.427 77.202 18.619 ;
     RECT  11.088 18.571 16.074 18.697 ;
     RECT  16.884 17.951 27.954 18.697 ;
     RECT  11.088 18.697 27.954 18.769 ;
     RECT  11.088 18.769 28.35 18.841 ;
     RECT  29.415 2.759 29.697 18.841 ;
     RECT  34.815 18.619 77.202 18.841 ;
     RECT  6.984 16.439 8.097 18.869 ;
     RECT  30.744 18.841 30.762 18.959 ;
     RECT  11.088 18.841 29.697 19.009 ;
     RECT  27.828 19.009 29.697 19.139 ;
     RECT  27.828 19.139 28.35 19.229 ;
     RECT  27.828 19.229 28.242 19.265 ;
     RECT  11.088 19.009 27.09 19.345 ;
     RECT  34.776 18.841 77.202 19.345 ;
     RECT  78.015 2.413 78.297 19.345 ;
     RECT  7.344 18.869 8.097 19.579 ;
     RECT  7.344 19.579 8.478 19.615 ;
     RECT  34.776 19.345 78.297 19.615 ;
     RECT  11.052 19.345 27.09 19.651 ;
     RECT  11.016 19.651 27.09 19.813 ;
     RECT  27.828 19.265 28.206 19.813 ;
     RECT  7.344 19.615 8.55 19.849 ;
     RECT  11.016 19.813 28.206 19.885 ;
     RECT  34.38 19.615 78.297 19.915 ;
     RECT  7.2 19.849 8.55 19.921 ;
     RECT  10.98 19.885 28.206 19.921 ;
     RECT  10.296 19.921 28.206 20.011 ;
     RECT  10.26 20.011 28.206 20.083 ;
     RECT  9.756 20.083 28.206 20.119 ;
     RECT  7.2 19.921 8.586 20.155 ;
     RECT  9.756 20.119 28.494 20.155 ;
     RECT  9.612 20.155 28.494 20.191 ;
     RECT  7.164 20.155 8.586 20.281 ;
     RECT  9.54 20.191 28.494 20.461 ;
     RECT  7.056 20.281 8.586 20.551 ;
     RECT  9.54 20.461 28.566 20.551 ;
     RECT  7.056 20.551 28.566 20.615 ;
     RECT  7.056 20.615 10.278 20.687 ;
     RECT  34.02 19.915 78.297 20.687 ;
     RECT  11.088 20.615 28.566 20.849 ;
     RECT  11.088 20.849 28.458 20.921 ;
     RECT  34.02 20.687 46.35 20.965 ;
     RECT  11.376 20.921 28.458 21.119 ;
     RECT  7.056 20.687 8.19 21.235 ;
     RECT  11.376 21.119 28.386 21.389 ;
     RECT  11.376 21.389 28.206 21.461 ;
     RECT  9 20.687 10.278 21.541 ;
     RECT  11.376 21.461 28.098 21.569 ;
     RECT  6.876 21.235 8.19 21.631 ;
     RECT  9 21.541 10.314 21.631 ;
     RECT  33.984 20.965 46.35 21.631 ;
     RECT  47.088 20.687 78.297 21.631 ;
     RECT  11.376 21.569 27.594 21.667 ;
     RECT  6.876 21.631 10.314 21.695 ;
     RECT  6.876 21.695 10.278 22.271 ;
     RECT  29.415 19.139 29.697 22.459 ;
     RECT  33.984 21.631 78.297 22.469 ;
     RECT  30.564 22.441 30.582 22.493 ;
     RECT  33.984 22.469 77.094 22.577 ;
     RECT  6.948 22.271 10.278 22.783 ;
     RECT  11.088 21.667 27.594 22.783 ;
     RECT  6.948 22.783 27.81 22.891 ;
     RECT  28.872 22.459 29.697 22.891 ;
     RECT  5.508 22.891 5.526 22.981 ;
     RECT  4.5 22.891 4.518 23.017 ;
     RECT  5.508 22.981 5.778 23.017 ;
     RECT  4.5 23.017 5.778 23.089 ;
     RECT  6.948 22.891 29.826 23.089 ;
     RECT  4.248 23.089 29.826 23.279 ;
     RECT  27.72 23.279 29.826 23.323 ;
     RECT  4.248 23.279 26.946 23.395 ;
     RECT  27.72 23.323 30.15 23.419 ;
     RECT  3.924 23.395 26.946 23.549 ;
     RECT  34.2 22.577 77.094 23.549 ;
     RECT  4.104 23.549 26.946 23.621 ;
     RECT  27.72 23.419 30.618 23.791 ;
     RECT  31.428 23.665 31.446 23.791 ;
     RECT  34.2 23.549 76.986 23.819 ;
     RECT  27.72 23.791 31.446 24.089 ;
     RECT  34.2 23.819 76.446 24.089 ;
     RECT  4.14 23.621 26.946 24.097 ;
     RECT  27.72 24.089 31.266 24.097 ;
     RECT  33.408 23.755 33.426 24.205 ;
     RECT  34.2 24.089 75.978 24.205 ;
     RECT  33.408 24.205 75.978 24.241 ;
     RECT  33.048 24.241 75.978 24.359 ;
     RECT  4.14 24.097 31.266 24.503 ;
     RECT  33.048 24.359 75.726 24.523 ;
     RECT  32.796 24.523 75.726 24.601 ;
     RECT  6.12 24.503 31.266 24.907 ;
     RECT  32.508 24.601 75.726 24.907 ;
     RECT  4.14 24.503 5.13 25.177 ;
     RECT  3.924 25.177 5.13 25.285 ;
     RECT  3.924 25.285 5.382 25.583 ;
     RECT  4.032 25.583 5.382 25.591 ;
     RECT  6.12 24.907 75.726 25.591 ;
     RECT  4.032 25.591 75.726 25.853 ;
     RECT  4.14 25.853 75.726 27.329 ;
     RECT  76.788 26.941 76.806 27.329 ;
     RECT  31.104 27.329 75.726 27.337 ;
     RECT  4.14 27.329 30.33 28.147 ;
     RECT  4.14 28.147 30.366 28.183 ;
     RECT  31.104 27.337 76.194 28.183 ;
     RECT  4.14 28.183 76.194 28.291 ;
     RECT  4.14 28.291 76.446 28.409 ;
     RECT  4.14 28.409 75.942 29.335 ;
     RECT  4.14 29.335 76.014 29.371 ;
     RECT  4.14 29.371 76.338 29.605 ;
     RECT  3.996 29.605 76.338 29.759 ;
     RECT  44.964 29.759 76.338 30.037 ;
     RECT  3.996 29.759 44.118 30.145 ;
     RECT  44.964 30.037 76.626 30.181 ;
     RECT  44.964 30.181 77.022 30.209 ;
     RECT  76.608 30.209 77.022 30.335 ;
     RECT  3.96 30.145 44.118 30.451 ;
     RECT  77.004 30.335 77.022 30.677 ;
     RECT  44.964 30.209 75.834 30.713 ;
     RECT  2.415 12.245 2.697 30.949 ;
     RECT  3.888 30.451 44.118 30.949 ;
     RECT  2.415 30.949 44.118 31.261 ;
     RECT  2.415 31.261 44.226 31.531 ;
     RECT  2.415 31.531 44.298 31.657 ;
     RECT  45.036 30.713 75.834 31.657 ;
     RECT  2.415 31.657 75.834 32.261 ;
     RECT  2.415 32.261 75.726 32.729 ;
     RECT  2.415 32.729 74.934 32.801 ;
     RECT  2.415 32.801 74.79 32.813 ;
     RECT  74.772 32.813 74.79 33.035 ;
     RECT  75.708 32.729 75.726 33.071 ;
     RECT  0.036 14.819 0.054 33.449 ;
     RECT  2.415 32.813 73.998 33.965 ;
     RECT  2.415 33.965 73.962 34.619 ;
     RECT  2.415 34.619 73.746 35.339 ;
     RECT  64.332 35.339 73.746 35.429 ;
     RECT  2.415 35.339 63.522 35.453 ;
     RECT  2.415 35.453 63.45 35.969 ;
     RECT  64.62 35.429 73.746 36.041 ;
     RECT  67.14 36.041 73.746 36.149 ;
     RECT  67.14 36.149 73.098 36.509 ;
     RECT  64.62 36.041 66.366 36.859 ;
     RECT  67.14 36.509 72.954 36.859 ;
     RECT  2.415 35.969 63.414 36.895 ;
     RECT  2.415 36.895 63.666 37.057 ;
     RECT  2.415 37.057 63.882 37.129 ;
     RECT  64.62 36.859 72.954 37.129 ;
     RECT  2.415 37.129 72.954 37.697 ;
     RECT  2.415 37.697 72.897 38.705 ;
     RECT  2.415 38.705 65.358 38.741 ;
     RECT  2.415 38.741 51.642 39.091 ;
     RECT  52.38 38.741 65.358 39.451 ;
     RECT  66.132 38.705 72.897 39.451 ;
     RECT  2.34 39.091 51.642 39.721 ;
     RECT  52.38 39.451 72.897 39.721 ;
     RECT  2.34 39.721 72.897 39.749 ;
     RECT  65.952 39.749 72.897 39.785 ;
     RECT  66.132 39.785 72.897 39.827 ;
     RECT  66.276 39.827 72.897 39.893 ;
     RECT  66.384 39.893 72.897 40.091 ;
     RECT  66.492 40.091 72.897 40.199 ;
     RECT  66.492 40.199 71.406 40.631 ;
     RECT  66.492 40.631 71.298 40.739 ;
     RECT  2.34 39.749 65.178 40.901 ;
     RECT  2.34 40.901 64.962 40.945 ;
     RECT  2.304 40.945 64.962 41.009 ;
     RECT  2.304 41.009 64.89 41.021 ;
     RECT  66.492 40.739 68.67 41.279 ;
     RECT  2.34 41.021 64.89 41.597 ;
     RECT  52.164 41.597 64.89 41.639 ;
     RECT  66.816 41.279 68.67 41.683 ;
     RECT  69.408 40.739 71.298 41.683 ;
     RECT  52.164 41.639 64.854 41.747 ;
     RECT  66.024 41.791 66.042 42.025 ;
     RECT  66.816 41.683 71.298 42.025 ;
     RECT  64.836 41.747 64.854 42.179 ;
     RECT  66.024 42.025 71.298 42.179 ;
     RECT  52.164 41.747 64.098 42.221 ;
     RECT  2.34 41.597 51.354 42.331 ;
     RECT  66.024 42.179 70.974 42.359 ;
     RECT  2.34 42.331 51.39 42.421 ;
     RECT  52.164 42.221 63.198 42.421 ;
     RECT  2.34 42.421 63.198 42.449 ;
     RECT  54.9 42.449 62.802 42.557 ;
     RECT  70.956 42.359 70.974 42.557 ;
     RECT  2.34 42.449 53.838 42.593 ;
     RECT  54.936 42.557 62.802 42.593 ;
     RECT  64.08 42.221 64.098 42.629 ;
     RECT  66.024 42.359 70.182 42.629 ;
     RECT  54.972 42.593 62.802 42.719 ;
     RECT  55.008 42.719 60.498 42.791 ;
     RECT  66.024 42.629 70.11 42.791 ;
     RECT  55.08 42.791 60.498 42.989 ;
     RECT  2.34 42.593 53.694 43.331 ;
     RECT  2.34 43.331 53.586 43.529 ;
     RECT  54.324 43.483 54.342 43.529 ;
     RECT  61.815 42.719 62.802 43.609 ;
     RECT  55.188 42.989 60.498 43.681 ;
     RECT  61.272 43.609 62.802 43.681 ;
     RECT  66.168 42.791 70.11 43.681 ;
     RECT  54.432 43.645 54.45 43.799 ;
     RECT  55.188 43.681 62.802 43.799 ;
     RECT  65.772 43.681 70.11 43.799 ;
     RECT  61.272 43.799 62.802 43.835 ;
     RECT  2.34 43.529 43.002 44.069 ;
     RECT  54.72 44.059 55.062 44.105 ;
     RECT  55.872 43.799 60.498 44.249 ;
     RECT  43.812 43.529 53.586 44.339 ;
     RECT  56.088 44.249 60.498 44.339 ;
     RECT  65.916 43.799 70.11 44.339 ;
     RECT  2.415 44.069 43.002 44.419 ;
     RECT  44.424 44.339 53.586 44.483 ;
     RECT  61.815 43.835 62.802 44.519 ;
     RECT  45 44.483 53.586 44.539 ;
     RECT  2.415 44.419 43.362 44.609 ;
     RECT  54.72 44.105 54.738 44.609 ;
     RECT  65.916 44.339 69.606 44.609 ;
     RECT  2.415 44.609 42.858 44.669 ;
     RECT  45 44.539 53.802 44.761 ;
     RECT  2.415 44.669 42.822 44.879 ;
     RECT  45 44.761 54.306 44.879 ;
     RECT  56.088 44.339 60.462 44.879 ;
     RECT  56.415 44.879 60.462 44.951 ;
     RECT  45 44.879 53.91 45.059 ;
     RECT  45 45.059 52.794 45.101 ;
     RECT  61.815 44.519 62.097 45.107 ;
     RECT  72.615 40.199 72.897 45.107 ;
     RECT  78.015 22.469 78.297 45.107 ;
     RECT  83.415 2.525 83.697 45.107 ;
     RECT  88.815 2.413 89.097 45.107 ;
     RECT  2.415 44.879 3.834 45.149 ;
     RECT  4.608 44.879 42.174 45.149 ;
     RECT  53.532 45.059 53.91 45.149 ;
     RECT  56.415 44.951 60.426 45.149 ;
     RECT  65.916 44.609 68.994 45.149 ;
     RECT  4.896 45.149 9.738 45.155 ;
     RECT  4.896 45.155 9.162 45.221 ;
     RECT  10.692 45.149 41.814 45.221 ;
     RECT  53.532 45.149 53.586 45.221 ;
     RECT  65.916 45.149 68.418 45.221 ;
     RECT  56.415 45.149 59.994 45.245 ;
     RECT  59.4 45.245 59.994 45.257 ;
     RECT  10.728 45.221 40.77 45.293 ;
     RECT  59.472 45.257 59.994 45.299 ;
     RECT  10.728 45.293 40.554 45.329 ;
     RECT  10.728 45.329 14.814 45.341 ;
     RECT  16.704 45.329 40.554 45.341 ;
     RECT  59.976 45.299 59.994 45.341 ;
     RECT  65.916 45.221 68.382 45.341 ;
     RECT  2.415 45.149 2.898 45.377 ;
     RECT  6.3 45.221 9.162 45.377 ;
     RECT  56.415 45.245 58.626 45.377 ;
     RECT  61.815 45.107 61.905 45.377 ;
     RECT  72.615 45.107 72.705 45.377 ;
     RECT  78.015 45.107 78.105 45.377 ;
     RECT  83.415 45.107 83.505 45.377 ;
     RECT  88.815 45.107 88.905 45.377 ;
     RECT  14.508 45.341 14.814 45.389 ;
     RECT  16.704 45.341 28.278 45.389 ;
     RECT  53.568 45.221 53.586 45.389 ;
     RECT  65.916 45.341 68.238 45.389 ;
     RECT  10.728 45.341 13.662 45.419 ;
     RECT  24.156 45.389 28.278 45.419 ;
     RECT  45 45.101 47.826 45.419 ;
     RECT  24.228 45.419 28.278 45.485 ;
     RECT  41.652 45.221 41.814 45.485 ;
     RECT  45.072 45.419 47.826 45.485 ;
     RECT  65.916 45.389 67.842 45.485 ;
     RECT  3.708 45.149 3.834 45.491 ;
     RECT  29.34 45.341 40.554 45.491 ;
     RECT  8.604 45.377 9.162 45.527 ;
     RECT  29.34 45.491 38.934 45.533 ;
     RECT  39.672 45.491 40.554 45.533 ;
     RECT  45.072 45.485 47.79 45.533 ;
     RECT  48.564 45.101 52.794 45.533 ;
     RECT  10.908 45.419 13.662 45.563 ;
     RECT  24.228 45.485 28.242 45.581 ;
     RECT  29.34 45.533 29.394 45.581 ;
     RECT  30.168 45.533 38.934 45.581 ;
     RECT  39.672 45.533 40.194 45.581 ;
     RECT  45.072 45.533 46.278 45.581 ;
     RECT  47.052 45.533 47.79 45.581 ;
     RECT  48.564 45.533 52.254 45.581 ;
     RECT  65.916 45.485 66.474 45.581 ;
     RECT  67.356 45.485 67.842 45.581 ;
     RECT  6.3 45.377 7.614 45.599 ;
     RECT  30.168 45.581 34.794 45.629 ;
     RECT  40.104 45.581 40.122 45.629 ;
     RECT  67.824 45.581 67.842 45.629 ;
     RECT  29.376 45.581 29.394 45.677 ;
     RECT  15.912 45.329 15.93 45.869 ;
     RECT  45.072 45.581 45.306 45.869 ;
     RECT  16.704 45.389 23.382 45.965 ;
     RECT  30.168 45.629 33.066 46.157 ;
     RECT  41.688 45.485 41.814 46.157 ;
     RECT  35.676 45.581 38.466 46.184 ;
     RECT  17.316 45.965 23.382 46.205 ;
     RECT  36 46.184 38.466 46.205 ;
     RECT  46.08 45.581 46.098 46.205 ;
     RECT  47.052 45.581 47.394 46.205 ;
     RECT  56.556 45.377 58.626 46.205 ;
     RECT  23.364 46.205 23.382 46.253 ;
     RECT  24.228 45.581 26.442 46.253 ;
     RECT  30.168 46.157 31.734 46.253 ;
     RECT  36 46.205 38.106 46.253 ;
     RECT  17.316 46.205 22.554 46.301 ;
     RECT  7.308 45.599 7.614 46.445 ;
     RECT  18.972 46.301 22.554 46.445 ;
     RECT  7.596 46.445 7.614 46.493 ;
     RECT  32.472 46.157 33.066 46.493 ;
     RECT  4.896 45.221 5.454 46.541 ;
     RECT  6.3 45.599 6.57 46.589 ;
     RECT  14.508 45.389 14.526 46.589 ;
     RECT  36 46.253 37.602 46.637 ;
     RECT  36 46.637 36.558 46.685 ;
     RECT  10.98 45.563 13.662 46.733 ;
     RECT  24.228 46.253 26.19 46.733 ;
     RECT  27.252 45.581 27.27 46.733 ;
     RECT  36.252 46.685 36.558 46.733 ;
     RECT  56.988 46.205 58.626 46.733 ;
     RECT  10.98 46.733 13.554 46.781 ;
     RECT  17.316 46.301 17.874 46.781 ;
     RECT  18.972 46.445 20.07 46.781 ;
     RECT  21.24 46.445 22.554 46.781 ;
     RECT  24.228 46.733 26.01 46.781 ;
     RECT  31.248 46.253 31.734 46.781 ;
     RECT  32.472 46.493 32.778 46.781 ;
     RECT  36.54 46.733 36.558 46.781 ;
     RECT  45.072 45.869 45.09 46.781 ;
     RECT  47.16 46.205 47.394 46.781 ;
     RECT  48.96 45.581 48.978 46.781 ;
     RECT  50.688 45.581 50.706 46.781 ;
     RECT  56.988 46.733 58.086 46.781 ;
     RECT  64.98 45.841 64.998 46.781 ;
     RECT  8.604 45.527 8.622 46.829 ;
     RECT  11.268 46.781 12.546 46.829 ;
     RECT  19.044 46.781 19.638 46.829 ;
     RECT  21.24 46.781 21.546 46.829 ;
     RECT  31.572 46.781 31.734 46.829 ;
     RECT  37.332 46.637 37.602 46.829 ;
     RECT  47.376 46.781 47.394 46.829 ;
     RECT  11.268 46.829 11.538 46.877 ;
     RECT  19.62 46.829 19.638 46.877 ;
     RECT  21.24 46.829 21.258 46.877 ;
     RECT  24.552 46.781 25.002 46.877 ;
     RECT  31.716 46.829 31.734 46.877 ;
     RECT  11.52 46.877 11.538 46.925 ;
     RECT  24.552 46.877 24.894 46.925 ;
     RECT  51.768 45.581 51.786 47.117 ;
     RECT  6.552 46.589 6.57 47.275 ;
     RECT  51.408 47.131 51.75 47.309 ;
     RECT  6.552 47.275 6.858 47.357 ;
     RECT  12.312 46.829 12.546 47.357 ;
     RECT  17.316 46.781 17.766 47.357 ;
     RECT  20.376 47.323 20.394 47.371 ;
     RECT  4.896 46.541 4.914 47.405 ;
     RECT  6.84 47.357 6.858 47.405 ;
     RECT  24.552 46.925 24.57 47.405 ;
     RECT  30.168 46.253 30.186 47.405 ;
     RECT  34.2 45.629 34.794 47.405 ;
     RECT  37.584 46.829 37.602 47.405 ;
     RECT  41.796 46.157 41.814 47.405 ;
     RECT  49.176 47.227 49.194 47.405 ;
     RECT  51.48 47.309 51.75 47.405 ;
     RECT  3.816 45.491 3.834 47.453 ;
     RECT  12.42 47.357 12.546 47.453 ;
     RECT  17.316 47.357 17.73 47.453 ;
     RECT  20.376 47.371 20.97 47.453 ;
     RECT  2.88 45.377 2.898 47.501 ;
     RECT  12.528 47.453 12.546 47.501 ;
     RECT  17.712 47.453 17.73 47.501 ;
     RECT  20.952 47.453 20.97 47.501 ;
    LAYER M4 ;
     RECT  0.084 8.784 2.408 8.808 ;
     RECT  0.06 8.808 2.408 8.88 ;
     RECT  0.084 8.88 2.408 8.904 ;
     RECT  0.06 8.904 2.408 8.976 ;
     RECT  0.084 8.976 2.408 9 ;
     RECT  0.06 9 2.408 9.072 ;
     RECT  0.084 9.072 2.408 9.096 ;
     RECT  0.06 9.096 2.408 9.168 ;
     RECT  0.084 9.168 2.408 9.192 ;
     RECT  0.06 9.192 2.408 9.264 ;
     RECT  0.084 9.264 2.408 9.288 ;
     RECT  0.06 9.288 2.408 9.36 ;
     RECT  0.084 9.36 2.408 9.384 ;
     RECT  0.06 9.384 2.408 9.456 ;
     RECT  0.084 9.456 2.408 9.48 ;
     RECT  0.06 9.48 2.408 9.552 ;
     RECT  0.084 9.552 2.408 9.576 ;
     RECT  0.06 9.576 2.408 9.648 ;
     RECT  0.084 9.648 2.408 9.672 ;
     RECT  0.06 9.672 2.408 9.744 ;
     RECT  0.084 9.744 2.408 9.768 ;
     RECT  0.06 9.768 2.408 9.84 ;
     RECT  0.084 9.84 2.408 9.864 ;
     RECT  0.06 9.864 2.408 9.936 ;
     RECT  0.084 9.936 2.408 9.96 ;
     RECT  0.06 9.96 2.408 10.032 ;
     RECT  0.084 10.032 2.408 10.056 ;
     RECT  0.06 10.056 2.408 10.128 ;
     RECT  0.084 10.128 2.408 10.152 ;
     RECT  0.06 10.152 2.408 10.224 ;
     RECT  0.084 10.224 2.408 10.248 ;
     RECT  0.06 10.248 2.408 10.32 ;
     RECT  0.084 10.32 2.408 10.344 ;
     RECT  0.06 10.344 2.408 10.416 ;
     RECT  0.084 10.416 2.408 10.44 ;
     RECT  0.06 10.44 2.408 10.512 ;
     RECT  0.084 10.512 2.408 10.536 ;
     RECT  0.06 10.536 2.408 10.608 ;
     RECT  0.084 10.608 2.408 10.632 ;
     RECT  0.06 10.632 2.408 10.704 ;
     RECT  0.084 10.704 2.408 10.728 ;
     RECT  0.06 10.728 2.408 10.8 ;
     RECT  0.084 10.8 2.408 10.824 ;
     RECT  0.06 10.824 2.408 10.896 ;
     RECT  0.084 10.896 2.408 10.92 ;
     RECT  0.06 10.92 2.408 10.992 ;
     RECT  0.084 10.992 2.408 11.016 ;
     RECT  0.06 11.016 2.408 11.088 ;
     RECT  0.084 11.088 2.408 11.112 ;
     RECT  0.06 11.112 2.408 11.184 ;
     RECT  0.084 11.184 2.408 11.208 ;
     RECT  0.06 11.208 2.408 11.28 ;
     RECT  0.084 11.28 2.408 11.304 ;
     RECT  0.06 11.304 2.408 11.376 ;
     RECT  0.084 11.376 2.408 11.4 ;
     RECT  0.181 23.616 2.408 23.64 ;
     RECT  2.252 40.992 2.408 41.016 ;
     RECT  2.293 42 2.408 42.744 ;
     RECT  2.408 2.148 2.512 45.372 ;
     RECT  2.512 2.418 2.704 45.102 ;
     RECT  2.704 32.496 2.945 33.576 ;
     RECT  2.704 40.08 3.197 40.104 ;
     RECT  2.704 8.832 3.305 11.208 ;
     RECT  2.945 33.552 3.377 33.576 ;
     RECT  2.704 37.056 3.557 37.08 ;
     RECT  2.704 30.72 3.635 30.984 ;
     RECT  2.704 44.448 3.701 44.856 ;
     RECT  2.704 34.8 3.769 34.92 ;
     RECT  3.769 34.128 3.773 34.92 ;
     RECT  2.704 41.856 3.773 43.32 ;
     RECT  2.869 47.472 3.805 47.496 ;
     RECT  3.305 8.832 3.971 11.016 ;
     RECT  2.704 35.952 4.061 35.976 ;
     RECT  3.971 8.832 4.205 10.92 ;
     RECT  3.635 30.72 4.237 30.744 ;
     RECT  2.704 23.616 4.273 23.64 ;
     RECT  2.704 38.16 4.277 38.184 ;
     RECT  4.237 30.192 4.309 30.744 ;
     RECT  4.345 25.968 4.381 25.992 ;
     RECT  4.273 23.616 4.385 24.504 ;
     RECT  4.309 30.048 4.385 30.744 ;
     RECT  3.773 34.128 4.405 34.248 ;
     RECT  4.237 28.464 4.417 28.488 ;
     RECT  4.205 8.976 4.421 10.92 ;
     RECT  2.945 32.496 4.451 32.52 ;
     RECT  4.405 33.552 4.451 34.248 ;
     RECT  4.421 9.072 4.457 10.92 ;
     RECT  4.451 33.552 4.493 33.576 ;
     RECT  4.417 28.272 4.561 28.488 ;
     RECT  4.381 39.216 4.561 39.24 ;
     RECT  4.457 9.312 4.565 10.92 ;
     RECT  4.385 23.616 4.637 23.736 ;
     RECT  4.381 25.872 4.709 25.992 ;
     RECT  4.561 38.832 4.813 39.24 ;
     RECT  4.561 28.272 4.853 28.92 ;
     RECT  3.805 47.424 4.885 47.496 ;
     RECT  4.849 40.56 4.957 40.584 ;
     RECT  3.701 44.448 4.957 44.472 ;
     RECT  4.957 40.56 5.105 40.728 ;
     RECT  3.773 41.856 5.137 42.504 ;
     RECT  4.813 38.832 5.173 39.48 ;
     RECT  5.105 40.56 5.173 40.584 ;
     RECT  4.957 44.448 5.213 44.76 ;
     RECT  5.173 38.832 5.249 40.584 ;
     RECT  5.249 38.832 5.285 40.056 ;
     RECT  4.709 25.872 5.321 25.896 ;
     RECT  4.885 47.376 5.425 47.496 ;
     RECT  5.173 34.704 5.461 34.872 ;
     RECT  5.461 34.704 5.497 35.256 ;
     RECT  4.849 36.24 5.497 36.264 ;
     RECT  5.497 34.704 5.501 36.264 ;
     RECT  5.101 31.728 5.533 31.752 ;
     RECT  5.285 38.832 5.569 39.192 ;
     RECT  5.569 38.16 5.573 39.192 ;
     RECT  4.853 28.272 5.641 28.488 ;
     RECT  5.573 38.16 5.645 39.048 ;
     RECT  5.137 41.856 5.653 42.6 ;
     RECT  5.501 35.232 5.677 36.264 ;
     RECT  5.533 31.728 5.756 32.232 ;
     RECT  5.677 35.232 5.789 36.6 ;
     RECT  5.645 38.16 5.825 39 ;
     RECT  5.756 31.728 5.843 32.472 ;
     RECT  5.641 27.36 5.857 28.488 ;
     RECT  5.857 27.312 5.969 28.488 ;
     RECT  5.969 27.36 6.109 28.488 ;
     RECT  5.825 38.16 6.109 38.472 ;
     RECT  6.109 27.36 6.181 28.92 ;
     RECT  5.653 41.856 6.181 43.176 ;
     RECT  5.789 36.24 6.217 36.6 ;
     RECT  6.181 27.36 6.221 28.968 ;
     RECT  5.797 33.504 6.289 33.816 ;
     RECT  6.221 28.416 6.361 28.968 ;
     RECT  4.385 30.048 6.361 30.072 ;
     RECT  6.181 41.472 6.361 43.176 ;
     RECT  6.289 33.312 6.401 33.816 ;
     RECT  6.217 36.24 6.469 37.032 ;
     RECT  6.109 38.016 6.469 38.472 ;
     RECT  5.843 31.728 6.617 32.232 ;
     RECT  6.361 40.992 6.685 43.176 ;
     RECT  6.361 28.416 6.721 30.072 ;
     RECT  4.637 23.616 6.757 23.64 ;
     RECT  6.757 23.616 6.865 24.504 ;
     RECT  6.469 36.24 6.865 38.472 ;
     RECT  5.213 44.448 6.901 44.472 ;
     RECT  6.901 44.352 7.081 44.472 ;
     RECT  6.865 23.616 7.189 25.368 ;
     RECT  6.221 27.36 7.225 27.432 ;
     RECT  6.721 28.416 7.225 30.888 ;
     RECT  6.685 40.608 7.225 43.176 ;
     RECT  7.081 44.352 7.225 44.76 ;
     RECT  5.425 46.512 7.297 47.496 ;
     RECT  7.189 23.04 7.333 25.368 ;
     RECT  6.469 34.896 7.369 34.92 ;
     RECT  6.401 33.792 7.441 33.816 ;
     RECT  7.369 34.896 7.441 35.208 ;
     RECT  7.333 23.04 7.621 26.04 ;
     RECT  7.621 22.752 7.657 26.04 ;
     RECT  7.225 39.792 7.669 43.176 ;
     RECT  7.225 44.352 7.669 45 ;
     RECT  7.441 33.792 7.801 35.208 ;
     RECT  4.565 9.36 7.808 10.92 ;
     RECT  7.669 11.952 7.808 11.976 ;
     RECT  7.669 20.4 7.808 20.424 ;
     RECT  7.657 22.032 7.808 26.04 ;
     RECT  7.225 27.36 7.808 30.888 ;
     RECT  6.617 32.16 7.808 32.232 ;
     RECT  7.801 33.648 7.808 35.208 ;
     RECT  6.865 36.24 7.808 38.712 ;
     RECT  7.669 39.792 7.808 45 ;
     RECT  7.808 2.148 7.912 45.372 ;
     RECT  7.912 2.418 8.104 45.102 ;
     RECT  8.104 26.64 8.165 30.888 ;
     RECT  8.165 26.832 8.201 30.888 ;
     RECT  8.201 26.88 8.381 30.888 ;
     RECT  8.104 32.016 8.705 34.152 ;
     RECT  8.705 32.208 8.723 34.152 ;
     RECT  8.104 9.792 8.849 11.976 ;
     RECT  8.723 33.648 9.029 34.152 ;
     RECT  8.104 41.424 9.029 45 ;
     RECT  8.849 9.792 9.097 9.864 ;
     RECT  9.029 33.984 9.097 34.152 ;
     RECT  8.104 20.928 9.169 20.952 ;
     RECT  8.104 35.568 9.173 40.152 ;
     RECT  8.104 22.752 9.277 24.504 ;
     RECT  9.277 22.272 9.313 24.504 ;
     RECT  8.104 25.536 9.313 25.656 ;
     RECT  9.097 9.6 9.421 9.864 ;
     RECT  8.381 26.88 9.421 30.168 ;
     RECT  9.097 33.984 9.461 34.2 ;
     RECT  9.169 20.928 9.637 21.144 ;
     RECT  9.173 35.568 9.637 36.984 ;
     RECT  9.029 44.976 9.685 45 ;
     RECT  9.637 20.112 9.749 21.144 ;
     RECT  9.313 22.272 9.749 25.656 ;
     RECT  9.685 44.976 9.772 45.144 ;
     RECT  9.421 9.072 9.785 9.864 ;
     RECT  9.749 22.368 9.785 25.512 ;
     RECT  9.029 41.424 9.821 43.896 ;
     RECT  9.173 38.352 9.889 40.152 ;
     RECT  9.821 41.424 9.889 43.848 ;
     RECT  9.889 38.352 9.893 43.848 ;
     RECT  9.637 35.184 9.929 36.984 ;
     RECT  9.421 26.88 10.069 30.792 ;
     RECT  9.772 44.976 10.073 45 ;
     RECT  9.749 20.112 10.109 21.096 ;
     RECT  9.893 38.352 10.109 43.8 ;
     RECT  8.849 10.944 10.289 11.976 ;
     RECT  9.929 35.568 10.289 36.984 ;
     RECT  9.785 23.04 10.361 23.544 ;
     RECT  10.069 26.88 10.396 31.08 ;
     RECT  10.396 26.88 10.613 30.072 ;
     RECT  10.289 35.712 10.645 36.984 ;
     RECT  10.361 23.28 10.789 23.544 ;
     RECT  10.109 20.112 10.861 20.136 ;
     RECT  9.785 25.152 10.861 25.512 ;
     RECT  9.461 33.984 10.861 34.152 ;
     RECT  9.785 9.072 10.937 9.624 ;
     RECT  10.861 25.056 10.969 25.512 ;
     RECT  10.861 33.792 11.045 34.152 ;
     RECT  10.861 20.016 11.077 20.136 ;
     RECT  10.109 38.352 11.077 43.512 ;
     RECT  10.789 23.28 11.113 23.928 ;
     RECT  10.969 25.056 11.113 25.8 ;
     RECT  10.645 35.712 11.113 37.224 ;
     RECT  11.077 38.352 11.113 44.184 ;
     RECT  11.077 19.296 11.149 20.136 ;
     RECT  11.113 35.712 11.185 44.184 ;
     RECT  11.045 33.792 11.189 34.008 ;
     RECT  11.185 35.712 11.189 44.328 ;
     RECT  11.149 19.296 11.221 20.568 ;
     RECT  11.189 41.712 11.324 44.328 ;
     RECT  11.324 41.712 11.333 45.048 ;
     RECT  10.937 9.408 11.365 9.624 ;
     RECT  10.289 10.992 11.365 11.976 ;
     RECT  11.365 9.408 11.411 11.976 ;
     RECT  11.333 44.16 11.411 45.048 ;
     RECT  11.221 19.296 11.509 20.616 ;
     RECT  11.113 22.224 11.509 22.248 ;
     RECT  11.509 19.296 11.581 22.248 ;
     RECT  11.113 23.28 11.581 25.8 ;
     RECT  11.581 19.296 11.617 25.8 ;
     RECT  10.613 26.88 11.617 29.64 ;
     RECT  11.617 19.296 11.941 29.64 ;
     RECT  11.189 35.712 11.945 40.44 ;
     RECT  11.941 18.864 11.977 29.64 ;
     RECT  11.189 33.792 11.977 33.816 ;
     RECT  7.297 46.416 11.977 47.496 ;
     RECT  10.396 31.056 11.989 31.08 ;
     RECT  11.989 30.96 12.013 31.08 ;
     RECT  11.411 9.552 12.053 10.104 ;
     RECT  12.013 30.96 12.076 31.128 ;
     RECT  11.945 35.712 12.193 40.056 ;
     RECT  11.977 18.768 12.265 29.64 ;
     RECT  12.265 18.768 12.517 29.832 ;
     RECT  12.076 31.104 12.517 31.128 ;
     RECT  8.723 32.208 12.517 32.232 ;
     RECT  11.977 45.312 12.557 47.496 ;
     RECT  12.193 34.992 12.589 40.056 ;
     RECT  12.557 45.312 12.601 47.4 ;
     RECT  11.977 33.6 12.661 33.816 ;
     RECT  12.517 31.104 12.733 32.232 ;
     RECT  12.661 33.36 12.733 33.816 ;
     RECT  11.411 44.16 12.805 44.328 ;
     RECT  12.601 45.312 12.805 47.304 ;
     RECT  11.653 16.416 12.877 16.44 ;
     RECT  12.733 31.104 12.913 33.816 ;
     RECT  12.589 34.944 12.913 40.056 ;
     RECT  12.805 44.16 12.947 47.304 ;
     RECT  12.517 18.528 13.045 29.832 ;
     RECT  12.053 9.552 13.208 9.576 ;
     RECT  11.411 11.712 13.208 11.976 ;
     RECT  13.165 13.056 13.208 13.08 ;
     RECT  12.877 16.416 13.208 17.4 ;
     RECT  13.045 18.528 13.208 30.12 ;
     RECT  12.913 31.104 13.208 40.056 ;
     RECT  11.333 41.712 13.208 42.888 ;
     RECT  12.947 44.16 13.208 46.824 ;
     RECT  13.208 2.148 13.312 46.824 ;
     RECT  13.312 2.418 13.331 46.824 ;
     RECT  13.331 2.418 13.504 46.776 ;
     RECT  13.504 13.056 13.619 13.08 ;
     RECT  13.504 43.92 13.619 46.776 ;
     RECT  13.504 14.304 13.66 14.328 ;
     RECT  13.504 17.136 13.673 25.32 ;
     RECT  13.504 34.656 13.709 37.416 ;
     RECT  13.619 46.416 13.715 46.776 ;
     RECT  13.709 35.04 13.745 37.416 ;
     RECT  13.504 32.16 13.817 33.384 ;
     RECT  13.504 11.712 13.889 11.976 ;
     RECT  13.745 35.04 13.925 35.256 ;
     RECT  13.715 46.416 14.003 46.728 ;
     RECT  13.504 26.304 14.033 30.216 ;
     RECT  13.745 36.24 14.177 37.416 ;
     RECT  13.925 35.184 14.249 35.256 ;
     RECT  13.673 17.136 14.321 25.08 ;
     RECT  13.889 11.856 14.497 11.976 ;
     RECT  13.817 32.16 14.537 33.288 ;
     RECT  14.537 32.16 14.569 33.192 ;
     RECT  14.321 17.136 14.609 18.792 ;
     RECT  14.497 11.856 14.645 12.552 ;
     RECT  14.677 14.784 14.713 14.808 ;
     RECT  13.504 15.792 14.713 15.816 ;
     RECT  13.619 43.92 14.713 45.384 ;
     RECT  14.645 11.952 14.773 12.552 ;
     RECT  14.033 28.176 14.773 30.216 ;
     RECT  14.321 19.92 14.785 25.08 ;
     RECT  14.033 26.304 14.785 27.192 ;
     RECT  14.785 19.92 14.825 27.192 ;
     RECT  14.713 43.728 14.825 45.384 ;
     RECT  14.773 28.176 14.86 30.792 ;
     RECT  14.713 14.784 14.893 15.816 ;
     RECT  13.504 38.448 14.897 39.912 ;
     RECT  13.504 40.992 14.929 42.744 ;
     RECT  14.825 43.728 14.929 44.616 ;
     RECT  14.825 22.272 15.005 27.192 ;
     RECT  14.893 14.112 15.149 15.816 ;
     RECT  14.773 11.952 15.217 13.032 ;
     RECT  15.149 14.112 15.217 15.384 ;
     RECT  15.005 26.256 15.253 27.192 ;
     RECT  14.86 28.176 15.253 30.216 ;
     RECT  14.893 34.656 15.293 34.824 ;
     RECT  14.825 19.92 15.361 21.288 ;
     RECT  15.253 26.256 15.401 30.216 ;
     RECT  14.897 39.504 15.433 39.912 ;
     RECT  14.929 40.992 15.433 44.616 ;
     RECT  15.293 34.8 15.509 34.824 ;
     RECT  15.005 22.272 15.581 25.128 ;
     RECT  14.609 17.424 15.617 18.792 ;
     RECT  14.897 38.448 15.761 38.472 ;
     RECT  14.003 46.416 15.901 46.584 ;
     RECT  15.433 39.504 15.941 44.616 ;
     RECT  15.217 11.952 15.977 15.384 ;
     RECT  14.569 32.016 15.977 33.192 ;
     RECT  15.581 22.512 16.045 25.128 ;
     RECT  15.401 26.256 16.045 28.488 ;
     RECT  15.977 14.496 16.049 15.384 ;
     RECT  15.401 29.472 16.049 30.216 ;
     RECT  15.941 41.088 16.049 44.616 ;
     RECT  15.977 32.016 16.081 33.048 ;
     RECT  16.049 41.088 16.085 44.52 ;
     RECT  16.049 29.472 16.157 29.496 ;
     RECT  14.177 36.24 16.297 37.128 ;
     RECT  16.049 14.496 16.301 14.52 ;
     RECT  16.085 41.088 16.499 43.752 ;
     RECT  16.081 31.872 16.553 33.048 ;
     RECT  16.297 36.24 16.553 37.32 ;
     RECT  16.499 41.904 16.553 43.752 ;
     RECT  15.361 19.872 16.585 21.288 ;
     RECT  16.045 22.512 16.585 28.488 ;
     RECT  15.757 16.416 16.621 16.44 ;
     RECT  15.617 17.424 16.621 17.88 ;
     RECT  16.621 16.416 16.657 17.88 ;
     RECT  16.553 37.296 16.661 37.32 ;
     RECT  16.657 16.416 16.765 18.84 ;
     RECT  16.585 19.872 16.765 28.872 ;
     RECT  16.765 16.416 16.985 28.872 ;
     RECT  16.985 17.136 17.021 28.872 ;
     RECT  16.553 32.736 17.021 33.048 ;
     RECT  17.021 17.328 17.057 28.872 ;
     RECT  17.021 33.024 17.129 33.048 ;
     RECT  15.941 39.504 17.197 39.912 ;
     RECT  17.057 17.328 17.201 20.184 ;
     RECT  16.553 36.24 17.228 36.264 ;
     RECT  17.228 35.328 17.233 36.264 ;
     RECT  17.057 21.648 17.273 28.872 ;
     RECT  15.901 45.84 17.305 46.584 ;
     RECT  17.233 34.416 17.315 36.264 ;
     RECT  17.273 21.648 17.345 28.776 ;
     RECT  17.315 36.24 17.381 36.264 ;
     RECT  17.089 30.192 17.629 30.216 ;
     RECT  17.197 39.504 17.653 40.44 ;
     RECT  16.553 41.904 17.653 43.512 ;
     RECT  15.977 11.952 17.701 13.032 ;
     RECT  17.305 45.84 17.701 47.448 ;
     RECT  17.701 11.952 17.737 13.368 ;
     RECT  17.737 11.952 17.809 13.608 ;
     RECT  18.025 14.928 18.061 14.952 ;
     RECT  18.061 14.928 18.097 15.048 ;
     RECT  18.061 16.08 18.097 16.104 ;
     RECT  17.809 11.952 18.205 13.848 ;
     RECT  17.701 45.84 18.205 47.496 ;
     RECT  18.205 11.952 18.241 13.944 ;
     RECT  18.097 14.928 18.241 16.104 ;
     RECT  18.205 45.264 18.277 47.496 ;
     RECT  17.345 21.648 18.385 25.128 ;
     RECT  17.345 26.304 18.385 28.632 ;
     RECT  18.385 21.648 18.529 28.632 ;
     RECT  17.629 30.192 18.529 30.84 ;
     RECT  17.653 39.504 18.529 43.512 ;
     RECT  17.315 34.416 18.565 35.064 ;
     RECT  18.205 37.104 18.565 37.128 ;
     RECT  18.241 11.952 18.608 16.104 ;
     RECT  17.201 17.856 18.608 20.184 ;
     RECT  18.529 21.648 18.608 31.224 ;
     RECT  18.565 34.128 18.608 35.064 ;
     RECT  18.565 36.864 18.608 37.128 ;
     RECT  18.529 38.784 18.608 43.512 ;
     RECT  18.277 45.168 18.608 47.496 ;
     RECT  18.608 2.148 18.712 47.496 ;
     RECT  18.712 2.418 18.904 47.496 ;
     RECT  18.904 36.864 18.965 43.128 ;
     RECT  18.965 39.312 19.145 43.128 ;
     RECT  18.965 36.864 19.181 37.992 ;
     RECT  18.904 20.016 19.187 31.848 ;
     RECT  18.904 11.952 19.253 18.168 ;
     RECT  19.253 11.952 19.289 13.176 ;
     RECT  19.253 14.16 19.325 18.168 ;
     RECT  19.187 20.016 19.331 31.224 ;
     RECT  19.181 36.864 19.361 36.888 ;
     RECT  19.325 16.32 19.397 18.168 ;
     RECT  19.331 29.328 19.397 31.224 ;
     RECT  19.145 39.312 19.427 41.928 ;
     RECT  19.289 11.952 19.469 12.312 ;
     RECT  19.397 29.424 19.577 31.224 ;
     RECT  19.397 16.368 19.613 18.168 ;
     RECT  18.904 32.88 19.613 33.096 ;
     RECT  19.145 43.104 19.757 43.128 ;
     RECT  19.181 37.968 19.933 37.992 ;
     RECT  19.331 20.016 19.937 28.2 ;
     RECT  19.469 11.952 19.973 11.976 ;
     RECT  19.427 39.312 19.981 41.688 ;
     RECT  19.577 29.424 20.045 31.032 ;
     RECT  18.904 34.416 20.149 34.968 ;
     RECT  19.937 20.016 20.153 26.856 ;
     RECT  19.325 14.16 20.225 15.048 ;
     RECT  19.613 16.368 20.225 17.064 ;
     RECT  18.904 45.024 20.293 47.496 ;
     RECT  19.933 37.968 20.365 38.328 ;
     RECT  20.153 25.68 20.435 26.76 ;
     RECT  20.435 25.68 20.441 26.568 ;
     RECT  20.441 25.68 20.476 26.328 ;
     RECT  19.613 32.88 20.509 32.952 ;
     RECT  20.149 34.416 20.509 35.496 ;
     RECT  20.509 34.128 20.54 35.496 ;
     RECT  20.225 14.784 20.545 15.048 ;
     RECT  20.54 34.128 20.545 36.312 ;
     RECT  20.365 37.584 20.545 38.328 ;
     RECT  19.981 39.312 20.545 39.336 ;
     RECT  20.153 20.016 20.585 24.648 ;
     RECT  20.045 29.424 20.621 30.744 ;
     RECT  20.545 34.128 20.627 39.336 ;
     RECT  19.981 40.56 20.657 41.688 ;
     RECT  20.225 16.752 20.765 17.064 ;
     RECT  20.509 32.592 20.837 32.952 ;
     RECT  20.627 34.128 20.873 35.496 ;
     RECT  20.873 34.128 20.909 34.968 ;
     RECT  20.833 42.336 20.941 42.36 ;
     RECT  20.293 44.976 20.981 47.496 ;
     RECT  20.657 40.56 21.017 41.064 ;
     RECT  20.981 44.976 21.025 47.4 ;
     RECT  20.627 37.152 21.049 39.336 ;
     RECT  21.017 40.56 21.049 40.872 ;
     RECT  19.613 18.144 21.085 18.168 ;
     RECT  20.909 34.128 21.085 34.44 ;
     RECT  20.585 21.072 21.089 24.648 ;
     RECT  21.049 37.152 21.089 40.872 ;
     RECT  20.476 25.728 21.125 26.328 ;
     RECT  20.765 16.752 21.341 16.824 ;
     RECT  20.621 29.424 21.341 30.648 ;
     RECT  21.013 13.296 21.409 13.32 ;
     RECT  20.545 14.784 21.409 15.096 ;
     RECT  20.585 20.016 21.409 20.04 ;
     RECT  19.937 27.888 21.409 28.2 ;
     RECT  21.341 29.424 21.409 30.168 ;
     RECT  21.409 13.296 21.445 15.096 ;
     RECT  21.085 17.856 21.445 18.168 ;
     RECT  21.409 19.296 21.445 20.04 ;
     RECT  21.409 27.888 21.449 30.168 ;
     RECT  21.341 16.752 21.485 16.776 ;
     RECT  21.089 21.12 21.541 24.648 ;
     RECT  21.125 25.728 21.541 26.28 ;
     RECT  21.445 13.152 21.553 15.096 ;
     RECT  21.085 33.936 21.557 34.44 ;
     RECT  21.553 12.72 21.589 15.096 ;
     RECT  21.541 21.12 21.621 26.28 ;
     RECT  21.589 12.72 21.625 15.336 ;
     RECT  21.025 44.976 21.637 46.872 ;
     RECT  20.977 31.776 21.661 31.8 ;
     RECT  20.941 42.336 21.661 43.32 ;
     RECT  21.637 44.448 21.661 46.872 ;
     RECT  21.661 42.336 21.724 46.872 ;
     RECT  21.445 17.856 21.731 20.04 ;
     RECT  21.625 12.384 21.737 15.768 ;
     RECT  21.731 17.856 21.809 19.32 ;
     RECT  21.089 38.304 21.809 40.872 ;
     RECT  21.449 27.888 21.836 30.072 ;
     RECT  21.089 37.152 21.841 37.224 ;
     RECT  21.724 45.024 21.875 46.872 ;
     RECT  21.836 27.84 21.881 30.072 ;
     RECT  21.557 33.984 21.913 34.44 ;
     RECT  21.841 36.24 21.913 37.224 ;
     RECT  21.881 27.84 21.923 29.976 ;
     RECT  21.621 25.488 22.093 26.28 ;
     RECT  21.809 38.304 22.097 39.768 ;
     RECT  21.923 27.888 22.115 29.976 ;
     RECT  22.115 27.888 22.241 27.912 ;
     RECT  21.913 33.984 22.273 37.224 ;
     RECT  22.097 38.304 22.273 38.52 ;
     RECT  22.273 33.984 22.277 38.52 ;
     RECT  21.661 31.248 22.313 31.8 ;
     RECT  22.277 33.984 22.313 35.352 ;
     RECT  21.621 21.12 22.381 23.928 ;
     RECT  22.381 20.976 22.421 23.928 ;
     RECT  22.093 25.488 22.457 26.808 ;
     RECT  21.737 12.384 22.493 13.896 ;
     RECT  21.737 14.928 22.561 15.768 ;
     RECT  22.493 12.384 22.709 12.888 ;
     RECT  22.097 39.744 22.709 39.768 ;
     RECT  21.724 42.336 22.739 43.944 ;
     RECT  22.421 20.976 22.777 23.88 ;
     RECT  22.739 42.336 22.777 42.984 ;
     RECT  22.709 12.48 22.817 12.888 ;
     RECT  22.115 29.088 22.835 29.976 ;
     RECT  22.777 20.544 22.853 23.88 ;
     RECT  22.457 25.488 22.853 26.28 ;
     RECT  22.313 34.032 22.883 35.352 ;
     RECT  22.883 34.032 22.925 35.304 ;
     RECT  21.875 45.024 22.931 46.776 ;
     RECT  22.817 12.528 22.997 12.888 ;
     RECT  21.809 40.8 23.029 40.872 ;
     RECT  22.277 36.624 23.461 38.52 ;
     RECT  21.809 17.856 23.533 18.984 ;
     RECT  22.853 20.544 23.533 21.72 ;
     RECT  23.029 40.032 23.569 40.872 ;
     RECT  22.931 45.024 23.749 46.44 ;
     RECT  22.853 22.8 23.857 23.88 ;
     RECT  22.493 13.872 23.893 13.896 ;
     RECT  22.561 14.928 23.893 16.584 ;
     RECT  23.533 17.856 23.893 21.72 ;
     RECT  23.857 22.752 23.893 23.88 ;
     RECT  22.777 42.048 23.893 42.984 ;
     RECT  22.997 12.864 23.965 12.888 ;
     RECT  23.893 13.872 23.965 16.584 ;
     RECT  22.835 29.088 23.965 29.496 ;
     RECT  23.965 12.864 24.008 16.584 ;
     RECT  23.893 17.856 24.008 23.88 ;
     RECT  22.853 25.488 24.008 25.8 ;
     RECT  23.965 29.088 24.008 29.832 ;
     RECT  22.749 31.2 24.008 31.224 ;
     RECT  22.925 34.128 24.008 35.304 ;
     RECT  23.461 36.624 24.008 38.76 ;
     RECT  23.569 40.032 24.008 40.968 ;
     RECT  23.893 42.048 24.008 43.32 ;
     RECT  23.749 44.448 24.008 46.44 ;
     RECT  24.008 2.148 24.037 46.44 ;
     RECT  24.037 2.148 24.112 47.4 ;
     RECT  24.112 2.418 24.304 47.4 ;
     RECT  24.304 29.76 24.401 29.832 ;
     RECT  24.304 20.592 24.419 25.8 ;
     RECT  24.304 31.056 24.437 31.224 ;
     RECT  24.419 25.104 24.473 25.8 ;
     RECT  24.304 36.864 24.473 41.64 ;
     RECT  24.473 38.16 24.509 41.64 ;
     RECT  24.509 38.256 24.515 41.64 ;
     RECT  24.304 13.632 24.545 14.232 ;
     RECT  24.419 20.592 24.545 23.88 ;
     RECT  24.304 44.448 24.581 47.4 ;
     RECT  24.304 32.832 24.617 35.592 ;
     RECT  24.515 38.256 24.617 41.544 ;
     RECT  24.473 25.488 24.653 25.8 ;
     RECT  24.617 33.024 24.653 35.592 ;
     RECT  24.617 39.072 24.659 41.544 ;
     RECT  24.659 39.072 24.977 39.816 ;
     RECT  24.304 42.672 24.977 43.416 ;
     RECT  24.977 42.768 25.085 43.416 ;
     RECT  24.653 25.488 25.121 25.704 ;
     RECT  25.085 42.816 25.139 43.416 ;
     RECT  24.545 22.032 25.157 23.88 ;
     RECT  25.121 25.488 25.157 25.56 ;
     RECT  24.653 33.024 25.157 33.048 ;
     RECT  24.653 34.08 25.157 35.592 ;
     RECT  24.977 39.792 25.193 39.816 ;
     RECT  24.545 13.872 25.405 14.232 ;
     RECT  24.304 15.744 25.405 15.768 ;
     RECT  24.659 40.8 25.445 41.544 ;
     RECT  24.304 18.144 25.477 19.512 ;
     RECT  24.401 29.808 25.477 29.832 ;
     RECT  24.437 31.056 25.477 31.08 ;
     RECT  25.139 43.344 25.549 43.416 ;
     RECT  24.581 44.448 25.549 46.92 ;
     RECT  25.549 43.344 25.619 46.92 ;
     RECT  24.473 36.864 25.657 37.08 ;
     RECT  24.304 12.384 25.669 12.408 ;
     RECT  25.669 12.384 25.715 12.504 ;
     RECT  25.405 13.872 25.717 15.768 ;
     RECT  25.477 29.808 25.765 31.08 ;
     RECT  25.445 41.52 25.769 41.544 ;
     RECT  25.477 17.088 25.805 19.512 ;
     RECT  25.157 34.128 25.805 35.592 ;
     RECT  25.657 36.864 25.805 37.224 ;
     RECT  25.717 13.872 25.913 16.008 ;
     RECT  25.805 18.864 25.913 19.512 ;
     RECT  25.765 29.808 25.974 31.944 ;
     RECT  25.549 28.8 25.981 28.824 ;
     RECT  25.913 13.872 26.021 13.896 ;
     RECT  25.913 15.024 26.057 16.008 ;
     RECT  25.974 29.808 26.057 31.896 ;
     RECT  25.805 36.864 26.129 37.032 ;
     RECT  26.057 15.696 26.161 16.008 ;
     RECT  25.805 17.088 26.161 17.112 ;
     RECT  25.477 24.912 26.273 24.936 ;
     RECT  25.619 43.344 26.291 46.776 ;
     RECT  26.291 44.736 26.345 46.776 ;
     RECT  25.805 34.416 26.381 35.592 ;
     RECT  25.913 18.864 26.417 19.368 ;
     RECT  26.291 43.344 26.449 43.416 ;
     RECT  26.197 26.016 26.485 26.04 ;
     RECT  24.304 27.312 26.485 27.336 ;
     RECT  26.017 1.728 26.496 1.752 ;
     RECT  26.345 45.024 26.579 46.776 ;
     RECT  26.161 15.696 26.597 17.112 ;
     RECT  25.157 22.704 26.665 23.88 ;
     RECT  26.521 39.264 26.669 39.288 ;
     RECT  26.125 0.096 26.701 0.12 ;
     RECT  26.057 29.808 26.705 31.08 ;
     RECT  26.665 21.456 26.737 23.88 ;
     RECT  26.737 21.36 26.777 23.88 ;
     RECT  25.981 28.752 26.809 28.824 ;
     RECT  26.701 0.096 26.867 0.216 ;
     RECT  26.485 26.016 26.881 27.336 ;
     RECT  26.597 15.984 26.921 17.112 ;
     RECT  26.521 20.352 26.953 20.376 ;
     RECT  26.777 21.36 26.953 21.48 ;
     RECT  26.953 20.352 27.173 21.48 ;
     RECT  26.449 42.768 27.197 43.416 ;
     RECT  26.809 28.656 27.205 28.824 ;
     RECT  26.381 34.416 27.205 35.352 ;
     RECT  26.129 37.008 27.241 37.032 ;
     RECT  27.197 42.72 27.241 43.416 ;
     RECT  27.173 20.448 27.245 21.48 ;
     RECT  27.205 33.936 27.277 35.352 ;
     RECT  27.241 41.904 27.281 43.416 ;
     RECT  26.867 0.096 27.289 0.168 ;
     RECT  26.881 25.824 27.313 27.336 ;
     RECT  27.281 43.392 27.313 43.416 ;
     RECT  27.245 20.448 27.317 21.384 ;
     RECT  27.205 28.656 27.349 28.92 ;
     RECT  27.277 33.408 27.349 35.352 ;
     RECT  27.241 36.48 27.349 37.032 ;
     RECT  27.313 43.392 27.353 43.752 ;
     RECT  27.313 25.248 27.421 27.336 ;
     RECT  26.705 30.24 27.425 31.08 ;
     RECT  26.921 17.088 27.461 17.112 ;
     RECT  26.921 15.984 27.605 16.008 ;
     RECT  27.349 28.32 27.605 28.92 ;
     RECT  26.417 18.864 27.713 18.984 ;
     RECT  27.317 20.448 27.785 21.288 ;
     RECT  27.421 25.152 27.889 27.336 ;
     RECT  27.349 33.408 27.893 37.032 ;
     RECT  27.713 18.864 27.929 18.888 ;
     RECT  27.893 33.936 27.929 37.032 ;
     RECT  27.605 28.464 28.069 28.92 ;
     RECT  27.425 30.72 28.213 31.08 ;
     RECT  26.777 22.704 28.249 23.88 ;
     RECT  27.889 25.008 28.249 27.336 ;
     RECT  27.785 21.264 28.259 21.288 ;
     RECT  28.213 30.72 28.297 31.368 ;
     RECT  28.249 22.704 28.325 27.336 ;
     RECT  27.929 34.08 28.361 37.032 ;
     RECT  28.297 31.344 28.393 31.368 ;
     RECT  27.385 39.84 28.393 39.864 ;
     RECT  28.393 39.84 28.597 40.104 ;
     RECT  27.281 41.904 28.597 42.12 ;
     RECT  27.289 0.096 28.62 0.12 ;
     RECT  28.325 22.704 28.861 27.096 ;
     RECT  28.069 28.464 29.149 28.968 ;
     RECT  27.353 43.728 29.269 43.752 ;
     RECT  26.579 45.024 29.269 46.728 ;
     RECT  28.861 22.464 29.329 27.096 ;
     RECT  29.149 28.464 29.329 29.064 ;
     RECT  28.62 0.096 29.365 0.168 ;
     RECT  26.496 1.728 29.408 1.8 ;
     RECT  25.715 12.48 29.408 12.504 ;
     RECT  29.329 22.464 29.408 29.064 ;
     RECT  28.393 31.344 29.408 32.328 ;
     RECT  28.361 34.08 29.408 35.448 ;
     RECT  28.361 36.48 29.408 37.032 ;
     RECT  28.609 38.16 29.408 38.184 ;
     RECT  28.597 39.84 29.408 42.12 ;
     RECT  29.269 43.728 29.408 47.352 ;
     RECT  29.365 0.096 29.555 0.552 ;
     RECT  29.408 1.728 29.605 47.352 ;
     RECT  29.605 1.728 29.704 47.4 ;
     RECT  29.704 26.016 29.729 28.728 ;
     RECT  29.729 26.016 29.837 27.576 ;
     RECT  29.555 0.096 30.089 0.168 ;
     RECT  29.704 30.096 30.161 30.12 ;
     RECT  29.837 26.64 30.197 27.576 ;
     RECT  29.704 44.4 30.197 47.4 ;
     RECT  29.704 31.68 30.227 32.376 ;
     RECT  29.704 33.504 30.227 38.904 ;
     RECT  30.197 26.64 30.269 27.096 ;
     RECT  30.227 34.416 30.275 38.904 ;
     RECT  29.704 41.616 30.275 43.368 ;
     RECT  29.704 40.416 30.449 40.44 ;
     RECT  29.729 28.704 30.521 28.728 ;
     RECT  29.704 22.464 30.629 24.264 ;
     RECT  30.275 42.768 30.773 43.368 ;
     RECT  30.629 23.616 30.797 24.264 ;
     RECT  30.797 23.616 30.881 25.128 ;
     RECT  30.275 34.416 30.899 38.424 ;
     RECT  30.899 36.48 31.187 38.424 ;
     RECT  30.197 44.4 31.237 46.728 ;
     RECT  30.629 22.464 31.283 22.536 ;
     RECT  30.881 23.616 31.321 24.552 ;
     RECT  31.237 25.632 31.333 25.656 ;
     RECT  30.275 41.616 31.333 41.64 ;
     RECT  30.773 42.768 31.333 42.792 ;
     RECT  31.333 41.616 31.345 42.792 ;
     RECT  31.333 25.632 31.379 25.848 ;
     RECT  31.187 36.48 31.385 37.752 ;
     RECT  30.227 32.16 31.453 32.376 ;
     RECT  31.345 41.472 31.477 42.792 ;
     RECT  31.453 31.92 31.493 32.376 ;
     RECT  31.477 41.04 31.493 42.792 ;
     RECT  31.237 44.4 31.561 46.776 ;
     RECT  29.704 1.728 31.637 1.8 ;
     RECT  30.089 0.096 31.672 0.12 ;
     RECT  31.561 43.92 31.705 46.824 ;
     RECT  30.269 27.072 31.741 27.096 ;
     RECT  31.379 25.824 31.853 25.848 ;
     RECT  31.672 0.096 31.877 0.168 ;
     RECT  31.877 0.096 31.961 0.6 ;
     RECT  31.385 36.48 31.961 37.656 ;
     RECT  31.741 26.88 32.137 27.096 ;
     RECT  31.493 42.768 32.213 42.792 ;
     RECT  31.705 43.92 32.339 46.872 ;
     RECT  32.339 43.92 32.393 46.776 ;
     RECT  30.899 34.416 32.461 35.208 ;
     RECT  31.961 36.48 32.461 36.792 ;
     RECT  32.461 33.984 32.533 35.208 ;
     RECT  31.637 1.728 32.652 1.752 ;
     RECT  32.389 28.896 32.677 28.92 ;
     RECT  32.636 8.832 32.723 8.856 ;
     RECT  31.321 23.616 32.785 23.88 ;
     RECT  32.137 25.968 32.821 27.096 ;
     RECT  31.493 31.92 32.821 31.944 ;
     RECT  31.961 0.096 32.933 0.168 ;
     RECT  32.533 33.264 32.969 35.208 ;
     RECT  31.493 41.04 33.001 41.496 ;
     RECT  32.821 25.968 33.005 27.864 ;
     RECT  32.677 28.896 33.061 29.736 ;
     RECT  32.821 30.72 33.061 31.944 ;
     RECT  33.061 28.896 33.185 31.944 ;
     RECT  32.969 33.312 33.221 35.208 ;
     RECT  33.185 28.896 33.365 31.512 ;
     RECT  33.001 41.04 33.397 42.216 ;
     RECT  32.785 23.616 33.541 24.552 ;
     RECT  33.005 25.968 33.541 26.136 ;
     RECT  33.365 29.088 33.653 31.512 ;
     RECT  32.461 36.192 33.653 36.792 ;
     RECT  33.653 36.768 33.685 36.792 ;
     RECT  32.393 44.448 33.721 46.776 ;
     RECT  33.397 40.704 33.877 42.84 ;
     RECT  33.685 36.768 33.901 37.032 ;
     RECT  31.237 20.304 34.009 20.328 ;
     RECT  33.221 33.312 34.009 33.336 ;
     RECT  33.221 34.416 34.009 35.208 ;
     RECT  33.901 36.768 34.045 37.704 ;
     RECT  33.721 44.304 34.117 46.776 ;
     RECT  34.117 44.304 34.165 47.4 ;
     RECT  32.652 1.728 34.189 1.8 ;
     RECT  34.009 33.072 34.261 33.336 ;
     RECT  34.009 19.92 34.369 20.328 ;
     RECT  33.005 27.84 34.46 27.864 ;
     RECT  34.46 27.696 34.501 27.864 ;
     RECT  33.653 29.088 34.501 31.128 ;
     RECT  32.933 0.096 34.546 0.12 ;
     RECT  33.877 40.56 34.645 42.84 ;
     RECT  34.165 43.92 34.645 47.4 ;
     RECT  34.546 0.096 34.693 0.168 ;
     RECT  34.501 27.696 34.693 31.128 ;
     RECT  34.189 1.728 34.808 1.848 ;
     RECT  33.649 9.072 34.808 9.096 ;
     RECT  29.704 12.48 34.808 12.504 ;
     RECT  34.369 19.632 34.808 20.328 ;
     RECT  31.283 22.464 34.808 22.488 ;
     RECT  33.541 23.616 34.808 26.136 ;
     RECT  34.693 27.36 34.808 31.128 ;
     RECT  34.261 32.256 34.808 33.336 ;
     RECT  34.009 34.416 34.808 35.496 ;
     RECT  34.045 36.768 34.808 37.992 ;
     RECT  31.777 39.312 34.808 39.336 ;
     RECT  34.645 40.56 34.808 47.4 ;
     RECT  34.693 0.096 35.027 0.552 ;
     RECT  34.808 1.728 35.104 47.4 ;
     RECT  35.104 37.968 35.129 38.712 ;
     RECT  35.104 22.464 35.201 35.208 ;
     RECT  35.201 22.464 35.219 34.44 ;
     RECT  35.219 22.464 35.309 23.976 ;
     RECT  35.219 25.248 35.315 34.44 ;
     RECT  35.104 42.336 35.453 47.4 ;
     RECT  35.315 32.496 35.489 34.44 ;
     RECT  35.315 25.248 35.699 31.128 ;
     RECT  35.104 40.176 35.813 40.584 ;
     RECT  35.104 19.632 35.993 21.24 ;
     RECT  35.104 5.376 36.035 5.4 ;
     RECT  35.104 9.072 36.035 9.096 ;
     RECT  35.699 25.248 36.101 31.032 ;
     RECT  35.027 0.096 36.108 0.12 ;
     RECT  35.104 12.48 36.179 12.504 ;
     RECT  36.101 26.112 36.245 31.032 ;
     RECT  35.489 33.024 36.245 34.44 ;
     RECT  36.245 26.784 36.389 31.032 ;
     RECT  35.104 3.312 36.421 3.336 ;
     RECT  36.245 33.408 36.425 34.44 ;
     RECT  35.453 42.336 36.425 42.36 ;
     RECT  36.421 3.312 36.505 4.008 ;
     RECT  35.104 36.96 36.637 36.984 ;
     RECT  36.425 33.408 36.677 34.344 ;
     RECT  36.108 0.096 36.7 0.168 ;
     RECT  35.129 38.688 36.785 38.712 ;
     RECT  35.104 1.728 36.881 1.752 ;
     RECT  35.813 40.176 36.961 40.2 ;
     RECT  36.637 36.96 36.995 37.464 ;
     RECT  36.677 33.936 37.001 34.344 ;
     RECT  36.133 17.088 37.033 17.112 ;
     RECT  36.949 35.472 37.036 35.496 ;
     RECT  36.505 3.312 37.073 3.336 ;
     RECT  37.033 17.088 37.073 17.208 ;
     RECT  36.995 37.056 37.105 37.464 ;
     RECT  35.993 19.632 37.145 20.328 ;
     RECT  36.881 1.728 37.148 1.8 ;
     RECT  37.145 20.016 37.249 20.328 ;
     RECT  37.249 20.016 37.285 20.712 ;
     RECT  37.148 1.68 37.357 1.8 ;
     RECT  36.389 26.784 37.357 26.856 ;
     RECT  36.389 27.936 37.427 31.032 ;
     RECT  37.357 1.632 37.532 1.8 ;
     RECT  35.453 43.584 37.613 47.4 ;
     RECT  37.532 1.632 37.619 2.28 ;
     RECT  37.073 17.184 37.717 17.208 ;
     RECT  37.061 0.576 37.729 0.6 ;
     RECT  37.285 20.016 37.753 21.672 ;
     RECT  35.104 18.624 37.763 18.648 ;
     RECT  37.753 20.016 37.825 22.536 ;
     RECT  35.309 23.616 37.825 23.976 ;
     RECT  37.427 27.936 37.829 29.88 ;
     RECT  37.825 20.016 37.865 23.976 ;
     RECT  37.717 38.784 37.897 38.808 ;
     RECT  36.961 40.176 37.897 40.44 ;
     RECT  37.865 20.016 37.901 20.328 ;
     RECT  37.619 1.632 37.957 1.848 ;
     RECT  37.357 26.64 38.041 26.856 ;
     RECT  37.427 30.912 38.041 31.032 ;
     RECT  37.069 32.064 38.041 32.088 ;
     RECT  37.957 1.152 38.045 1.848 ;
     RECT  37.105 37.056 38.045 37.704 ;
     RECT  37.613 43.584 38.099 46.824 ;
     RECT  38.041 26.064 38.113 26.856 ;
     RECT  37.901 20.016 38.153 20.28 ;
     RECT  37.865 21.648 38.153 23.976 ;
     RECT  38.113 26.016 38.153 26.856 ;
     RECT  37.829 27.936 38.153 29.256 ;
     RECT  37.717 17.184 38.189 17.64 ;
     RECT  38.045 1.728 38.197 1.848 ;
     RECT  37.897 38.784 38.213 40.44 ;
     RECT  37.001 33.936 38.221 34.296 ;
     RECT  38.041 30.912 38.261 32.088 ;
     RECT  38.149 42.528 38.261 42.552 ;
     RECT  38.213 38.736 38.293 41.064 ;
     RECT  38.293 38.736 38.297 41.16 ;
     RECT  38.153 23.616 38.365 23.976 ;
     RECT  38.221 33.936 38.365 35.208 ;
     RECT  38.153 20.016 38.369 20.136 ;
     RECT  38.261 31.776 38.405 32.088 ;
     RECT  38.297 38.976 38.483 41.16 ;
     RECT  38.099 43.584 38.483 46.248 ;
     RECT  38.405 31.776 38.549 31.8 ;
     RECT  38.369 20.016 38.585 20.04 ;
     RECT  38.153 28.128 38.729 29.256 ;
     RECT  38.045 37.056 38.729 37.512 ;
     RECT  38.483 38.976 38.771 40.2 ;
     RECT  38.153 26.016 38.837 26.52 ;
     RECT  38.729 28.128 38.86 28.776 ;
     RECT  38.483 43.584 38.867 46.2 ;
     RECT  38.365 33.936 38.941 35.736 ;
     RECT  38.837 26.016 38.981 26.04 ;
     RECT  38.729 37.2 39.017 37.512 ;
     RECT  38.771 38.976 39.161 39 ;
     RECT  38.189 17.616 39.197 17.64 ;
     RECT  39.017 37.488 39.233 37.512 ;
     RECT  38.153 21.648 39.337 22.584 ;
     RECT  38.771 40.176 39.445 40.2 ;
     RECT  38.941 33.072 39.517 35.736 ;
     RECT  39.265 27.072 39.913 27.192 ;
     RECT  39.829 30.768 39.913 30.792 ;
     RECT  38.867 43.584 39.949 45.576 ;
     RECT  39.949 43.104 39.973 45.576 ;
     RECT  39.877 47.184 39.973 47.208 ;
     RECT  39.877 17.904 39.985 17.928 ;
     RECT  39.973 47.184 40.019 47.304 ;
     RECT  39.337 21.648 40.021 22.632 ;
     RECT  39.517 16.368 40.057 16.392 ;
     RECT  38.365 23.616 40.057 24.84 ;
     RECT  40.019 47.28 40.069 47.304 ;
     RECT  40.057 16.32 40.093 16.392 ;
     RECT  39.913 27.072 40.093 27.624 ;
     RECT  38.86 28.752 40.093 28.776 ;
     RECT  39.913 30.768 40.093 30.888 ;
     RECT  40.069 47.28 40.115 47.4 ;
     RECT  40.021 21.072 40.165 22.632 ;
     RECT  38.197 1.728 40.208 1.8 ;
     RECT  39.109 2.88 40.208 2.904 ;
     RECT  40.093 16.32 40.208 16.68 ;
     RECT  39.985 17.904 40.208 18.024 ;
     RECT  40.165 20.592 40.208 22.632 ;
     RECT  40.057 23.616 40.208 25.32 ;
     RECT  40.093 27.072 40.208 28.776 ;
     RECT  40.093 30.432 40.208 30.888 ;
     RECT  39.517 32.496 40.208 35.736 ;
     RECT  39.337 38.16 40.208 38.184 ;
     RECT  39.445 40.176 40.208 40.968 ;
     RECT  39.973 43.104 40.208 46.152 ;
     RECT  39.409 0.096 40.261 0.12 ;
     RECT  40.261 0.096 40.385 0.552 ;
     RECT  40.208 1.728 40.504 46.152 ;
     RECT  40.504 21.984 40.601 25.32 ;
     RECT  40.601 21.984 40.637 22.536 ;
     RECT  40.504 16.368 40.709 20.616 ;
     RECT  40.504 27.168 40.745 29.352 ;
     RECT  40.709 18.384 40.781 20.616 ;
     RECT  40.504 37.632 40.781 38.712 ;
     RECT  40.709 16.368 40.853 17.112 ;
     RECT  40.385 0.096 40.897 0.168 ;
     RECT  40.781 18.384 40.979 20.04 ;
     RECT  40.637 21.984 40.997 22.008 ;
     RECT  40.504 33.552 41.105 35.208 ;
     RECT  40.504 44.352 41.141 46.152 ;
     RECT  40.601 23.664 41.177 25.32 ;
     RECT  40.781 38.112 41.213 38.712 ;
     RECT  40.745 27.168 41.249 27.384 ;
     RECT  40.504 1.728 41.285 1.8 ;
     RECT  41.213 38.112 41.321 38.184 ;
     RECT  40.504 30.432 41.357 30.984 ;
     RECT  40.979 18.816 41.465 19.56 ;
     RECT  41.105 33.552 41.537 34.824 ;
     RECT  41.357 30.96 41.645 30.984 ;
     RECT  41.141 44.64 41.681 46.152 ;
     RECT  41.681 46.128 41.717 46.152 ;
     RECT  41.537 33.6 41.753 34.824 ;
     RECT  40.504 40.704 41.777 41.496 ;
     RECT  40.115 47.376 41.825 47.4 ;
     RECT  41.777 40.416 41.843 41.496 ;
     RECT  41.843 40.416 41.861 41.256 ;
     RECT  40.897 0.096 41.965 0.12 ;
     RECT  40.745 28.752 41.965 28.776 ;
     RECT  40.504 43.104 41.965 43.128 ;
     RECT  41.249 27.36 42.109 27.384 ;
     RECT  41.965 28.752 42.109 29.064 ;
     RECT  41.753 34.8 42.185 34.824 ;
     RECT  42.181 37.056 42.365 37.08 ;
     RECT  41.965 43.104 42.397 43.56 ;
     RECT  42.109 27.36 42.505 29.976 ;
     RECT  41.465 18.912 42.541 19.56 ;
     RECT  41.753 33.6 42.621 33.624 ;
     RECT  42.397 42.48 42.685 43.56 ;
     RECT  41.681 44.64 42.685 44.664 ;
     RECT  41.929 31.968 42.721 31.992 ;
     RECT  42.621 33.024 42.721 33.624 ;
     RECT  41.177 23.664 42.725 25.032 ;
     RECT  42.253 21.648 42.757 21.672 ;
     RECT  42.757 20.832 42.793 21.672 ;
     RECT  42.721 31.968 42.793 33.624 ;
     RECT  42.541 18.816 42.797 19.56 ;
     RECT  42.793 31.968 42.833 34.2 ;
     RECT  42.685 42.48 42.833 44.664 ;
     RECT  42.725 23.76 42.865 25.032 ;
     RECT  42.833 44.64 42.869 44.664 ;
     RECT  42.793 20.832 43.049 22.2 ;
     RECT  42.505 26.88 43.052 29.976 ;
     RECT  43.052 26.88 43.093 30.792 ;
     RECT  43.093 26.88 43.121 31.368 ;
     RECT  43.121 30.768 43.139 31.368 ;
     RECT  42.833 32.832 43.229 33.048 ;
     RECT  42.937 18.768 43.285 18.792 ;
     RECT  41.285 1.728 43.3 1.752 ;
     RECT  43.121 26.88 43.34 29.544 ;
     RECT  43.285 19.968 43.372 19.992 ;
     RECT  43.34 26.544 43.409 29.544 ;
     RECT  43.409 26.544 43.427 26.568 ;
     RECT  42.833 42.48 43.429 43.56 ;
     RECT  43.3 1.728 43.445 1.8 ;
     RECT  43.409 27.648 43.481 29.544 ;
     RECT  43.429 42.288 43.516 43.56 ;
     RECT  42.865 23.76 43.553 25.416 ;
     RECT  43.516 42.48 43.553 43.56 ;
     RECT  41.965 0.096 43.729 0.168 ;
     RECT  42.833 34.176 43.729 34.2 ;
     RECT  43.333 35.184 43.729 35.208 ;
     RECT  43.139 31.344 43.733 31.368 ;
     RECT  43.729 34.176 43.769 35.208 ;
     RECT  43.285 18.672 43.801 18.792 ;
     RECT  43.481 27.648 43.805 29.496 ;
     RECT  43.553 23.856 43.841 25.416 ;
     RECT  43.805 28.224 43.841 29.496 ;
     RECT  43.229 33.024 43.841 33.048 ;
     RECT  43.801 18.672 44.161 19.704 ;
     RECT  43.841 28.224 44.165 29.448 ;
     RECT  44.161 18.144 44.201 19.704 ;
     RECT  44.201 18.144 44.237 19.272 ;
     RECT  40.504 3.024 44.305 3.048 ;
     RECT  43.841 23.856 44.342 24.936 ;
     RECT  43.049 21.36 44.453 22.2 ;
     RECT  44.342 23.856 44.453 24.888 ;
     RECT  44.305 3.024 44.588 3.72 ;
     RECT  43.445 1.728 44.593 1.752 ;
     RECT  43.553 43.296 44.593 43.56 ;
     RECT  44.588 3.024 44.629 4.536 ;
     RECT  44.629 2.784 44.809 4.536 ;
     RECT  44.453 21.36 44.809 21.96 ;
     RECT  44.453 23.856 45.025 24.504 ;
     RECT  43.945 26.304 45.025 26.328 ;
     RECT  41.321 38.16 45.097 38.184 ;
     RECT  45.097 32.16 45.169 32.184 ;
     RECT  44.809 21.264 45.212 21.96 ;
     RECT  43.729 0.096 45.241 0.216 ;
     RECT  44.593 1.728 45.241 1.8 ;
     RECT  44.165 28.8 45.241 29.448 ;
     RECT  43.769 34.368 45.241 35.208 ;
     RECT  45.133 36.912 45.241 36.936 ;
     RECT  45.169 20.064 45.253 20.088 ;
     RECT  45.212 21.072 45.253 21.96 ;
     RECT  45.241 0.096 45.277 1.8 ;
     RECT  44.809 2.784 45.277 5.16 ;
     RECT  45.025 26.304 45.277 26.568 ;
     RECT  45.253 20.064 45.349 21.96 ;
     RECT  45.241 36.864 45.349 36.936 ;
     RECT  45.349 36.816 45.385 36.936 ;
     RECT  45.277 0.096 45.395 5.16 ;
     RECT  45.349 19.872 45.493 21.96 ;
     RECT  44.593 43.056 45.529 43.56 ;
     RECT  45.097 38.16 45.601 38.472 ;
     RECT  45.395 1.728 45.608 5.16 ;
     RECT  44.629 7.728 45.608 7.752 ;
     RECT  45.301 9.792 45.608 9.816 ;
     RECT  44.965 13.152 45.608 13.176 ;
     RECT  44.945 14.736 45.608 14.76 ;
     RECT  45.529 15.984 45.608 16.008 ;
     RECT  40.853 17.088 45.608 17.112 ;
     RECT  44.237 18.144 45.608 18.792 ;
     RECT  45.493 19.872 45.608 22.488 ;
     RECT  45.025 23.568 45.608 24.504 ;
     RECT  45.277 26.208 45.608 26.568 ;
     RECT  45.097 27.648 45.608 27.672 ;
     RECT  45.241 28.8 45.608 30.408 ;
     RECT  45.169 32.16 45.608 32.232 ;
     RECT  45.241 33.936 45.608 35.208 ;
     RECT  45.385 36.576 45.608 36.936 ;
     RECT  45.601 38.16 45.608 38.808 ;
     RECT  41.861 41.232 45.608 41.256 ;
     RECT  45.529 43.008 45.608 43.56 ;
     RECT  45.608 1.728 45.733 45.372 ;
     RECT  45.733 1.728 45.889 45.528 ;
     RECT  45.889 1.728 45.904 45.576 ;
     RECT  45.061 46.752 45.971 46.776 ;
     RECT  45.904 21.696 46.001 21.912 ;
     RECT  45.904 33.936 46.019 35.544 ;
     RECT  45.904 36.624 46.019 39.432 ;
     RECT  45.904 43.008 46.069 45.576 ;
     RECT  45.904 27.936 46.073 28.824 ;
     RECT  46.019 36.816 46.115 39.432 ;
     RECT  46.115 38.448 46.145 39.432 ;
     RECT  46.069 43.008 46.217 46.2 ;
     RECT  45.904 23.568 46.253 26.328 ;
     RECT  46.145 38.448 46.253 39.24 ;
     RECT  46.217 43.296 46.477 46.2 ;
     RECT  45.904 9.696 46.505 16.968 ;
     RECT  46.505 11.472 46.595 16.968 ;
     RECT  45.904 1.728 46.721 2.28 ;
     RECT  46.721 1.728 46.739 2.232 ;
     RECT  45.395 0.096 46.753 0.168 ;
     RECT  46.595 11.472 46.787 12.216 ;
     RECT  46.253 38.448 46.793 39.192 ;
     RECT  46.793 38.448 46.829 38.664 ;
     RECT  46.753 0.096 46.873 0.216 ;
     RECT  46.873 0.192 46.931 0.216 ;
     RECT  45.904 3.312 46.937 3.96 ;
     RECT  45.904 18.144 46.969 20.088 ;
     RECT  45.904 40.56 46.988 40.584 ;
     RECT  45.904 7.584 47.027 7.944 ;
     RECT  46.988 40.272 47.075 40.584 ;
     RECT  46.477 45.024 47.149 46.2 ;
     RECT  46.073 28.8 47.153 28.824 ;
     RECT  45.904 5.616 47.189 5.64 ;
     RECT  46.115 36.816 47.221 37.08 ;
     RECT  45.904 31.824 47.225 32.808 ;
     RECT  46.001 21.888 47.228 21.912 ;
     RECT  47.228 21.888 47.257 22.248 ;
     RECT  46.253 23.568 47.257 26.28 ;
     RECT  47.257 21.888 47.269 26.28 ;
     RECT  47.225 31.824 47.293 31.944 ;
     RECT  46.969 18.144 47.315 20.232 ;
     RECT  46.505 9.696 47.317 10.488 ;
     RECT  47.269 21.648 47.324 26.28 ;
     RECT  47.185 41.952 47.365 41.976 ;
     RECT  47.149 45.024 47.365 46.776 ;
     RECT  47.315 18.144 47.369 19.56 ;
     RECT  47.324 21.504 47.401 26.28 ;
     RECT  46.019 33.936 47.401 35.208 ;
     RECT  47.317 9.072 47.405 10.488 ;
     RECT  46.595 13.296 47.405 16.968 ;
     RECT  47.369 18.768 47.411 19.56 ;
     RECT  47.365 40.992 47.429 41.976 ;
     RECT  46.477 43.296 47.429 43.56 ;
     RECT  47.365 45.024 47.507 46.824 ;
     RECT  47.401 33.936 47.509 35.592 ;
     RECT  47.221 36.816 47.509 37.464 ;
     RECT  47.429 40.992 47.513 43.56 ;
     RECT  47.468 39.888 47.555 39.912 ;
     RECT  47.513 40.992 47.555 42.408 ;
     RECT  47.509 33.936 47.603 37.464 ;
     RECT  46.937 3.312 47.621 3.48 ;
     RECT  46.787 11.952 47.653 12.216 ;
     RECT  47.405 13.296 47.653 16.824 ;
     RECT  47.603 36.816 47.657 37.464 ;
     RECT  47.405 9.504 47.725 10.488 ;
     RECT  47.621 3.456 47.729 3.48 ;
     RECT  46.739 1.728 47.749 1.944 ;
     RECT  47.657 36.816 47.801 37.176 ;
     RECT  47.401 21.504 47.833 27.24 ;
     RECT  47.513 43.536 47.845 43.56 ;
     RECT  47.845 43.536 47.891 43.656 ;
     RECT  47.833 21.504 47.977 27.288 ;
     RECT  47.749 1.728 48.037 1.992 ;
     RECT  47.845 5.136 48.085 5.16 ;
     RECT  47.027 7.92 48.129 7.944 ;
     RECT  47.507 45.024 48.133 45.576 ;
     RECT  48.013 0.144 48.157 0.168 ;
     RECT  47.725 29.616 48.188 29.64 ;
     RECT  47.293 31.344 48.193 31.944 ;
     RECT  47.977 21.504 48.229 27.72 ;
     RECT  48.188 29.04 48.229 29.64 ;
     RECT  48.193 30.912 48.229 31.944 ;
     RECT  47.801 36.816 48.305 37.08 ;
     RECT  48.229 21.024 48.373 27.72 ;
     RECT  48.229 29.04 48.373 31.944 ;
     RECT  48.157 0.096 48.409 0.168 ;
     RECT  47.411 19.536 48.409 19.56 ;
     RECT  48.373 20.928 48.409 27.72 ;
     RECT  47.555 40.992 48.409 42.072 ;
     RECT  48.409 19.536 48.428 27.72 ;
     RECT  47.653 11.952 48.469 16.824 ;
     RECT  48.409 40.944 48.485 42.072 ;
     RECT  48.373 28.752 48.517 31.944 ;
     RECT  48.517 28.752 48.521 32.28 ;
     RECT  48.469 11.952 48.553 17.64 ;
     RECT  48.428 18.768 48.553 27.72 ;
     RECT  48.409 0.096 48.563 0.216 ;
     RECT  48.485 40.944 48.589 41.016 ;
     RECT  47.725 9.504 48.661 10.728 ;
     RECT  48.553 11.952 48.697 27.72 ;
     RECT  48.661 8.976 48.733 10.728 ;
     RECT  48.697 11.76 48.733 27.72 ;
     RECT  47.603 33.936 48.733 35.592 ;
     RECT  46.829 38.64 48.769 38.664 ;
     RECT  48.589 40.608 48.769 41.016 ;
     RECT  48.521 30 48.805 32.28 ;
     RECT  48.733 33.936 48.805 36.792 ;
     RECT  48.085 4.368 48.845 5.16 ;
     RECT  48.733 8.976 48.845 27.72 ;
     RECT  47.507 46.8 48.949 46.824 ;
     RECT  48.485 42.048 48.985 42.072 ;
     RECT  48.949 46.752 48.997 46.824 ;
     RECT  48.769 38.64 49.021 41.016 ;
     RECT  48.133 44.928 49.021 45.576 ;
     RECT  48.845 4.56 49.061 5.16 ;
     RECT  48.985 42.048 49.061 42.264 ;
     RECT  48.997 46.752 49.093 47.208 ;
     RECT  49.093 46.752 49.138 47.304 ;
     RECT  49.138 46.752 49.139 47.4 ;
     RECT  49.061 42.144 49.157 42.264 ;
     RECT  47.891 43.632 49.157 43.656 ;
     RECT  49.139 47.184 49.166 47.4 ;
     RECT  49.157 42.144 49.241 43.656 ;
     RECT  49.166 47.232 49.249 47.4 ;
     RECT  48.805 30 49.273 36.792 ;
     RECT  48.037 1.728 49.313 2.28 ;
     RECT  49.273 30 49.313 36.84 ;
     RECT  49.249 47.232 49.331 47.352 ;
     RECT  48.845 10.128 49.345 27.72 ;
     RECT  48.521 28.752 49.345 28.776 ;
     RECT  49.331 47.28 49.523 47.352 ;
     RECT  49.313 35.184 49.525 36.84 ;
     RECT  49.021 38.064 49.525 41.016 ;
     RECT  49.525 35.184 49.565 41.064 ;
     RECT  49.313 30 49.571 34.104 ;
     RECT  49.313 1.728 49.601 1.992 ;
     RECT  49.565 36.384 49.601 41.064 ;
     RECT  48.129 7.872 49.633 7.944 ;
     RECT  48.845 8.976 49.633 9 ;
     RECT  49.601 36.768 49.781 41.064 ;
     RECT  49.633 7.872 49.885 9 ;
     RECT  49.345 10.128 49.885 28.776 ;
     RECT  49.601 1.728 49.925 1.896 ;
     RECT  48.563 0.096 49.933 0.168 ;
     RECT  49.571 30 49.993 33.048 ;
     RECT  49.993 29.856 50.065 33.048 ;
     RECT  49.885 7.872 50.101 28.776 ;
     RECT  49.781 38.016 50.137 41.064 ;
     RECT  49.241 42.144 50.137 42.264 ;
     RECT  49.241 43.632 50.137 43.656 ;
     RECT  49.021 44.688 50.137 45.576 ;
     RECT  50.137 38.016 50.293 42.264 ;
     RECT  50.137 43.632 50.293 45.576 ;
     RECT  50.101 7.632 50.425 28.776 ;
     RECT  50.065 29.76 50.425 33.048 ;
     RECT  49.565 35.184 50.588 35.256 ;
     RECT  49.781 36.768 50.588 36.84 ;
     RECT  50.425 7.632 50.641 33.048 ;
     RECT  49.571 34.08 50.641 34.104 ;
     RECT  49.523 47.328 50.677 47.352 ;
     RECT  50.641 7.632 50.821 34.104 ;
     RECT  49.933 0.096 50.929 0.12 ;
     RECT  50.821 7.104 50.929 34.104 ;
     RECT  50.588 35.184 50.929 36.84 ;
     RECT  49.925 1.728 50.962 1.752 ;
     RECT  50.677 46.752 50.963 47.352 ;
     RECT  50.962 1.728 51.008 1.8 ;
     RECT  49.061 4.56 51.008 4.584 ;
     RECT  50.78 5.856 51.008 5.88 ;
     RECT  50.929 7.104 51.008 36.84 ;
     RECT  50.293 38.016 51.008 45.576 ;
     RECT  51.008 1.728 51.304 45.576 ;
     RECT  51.304 7.104 51.401 35.208 ;
     RECT  50.963 47.088 51.442 47.352 ;
     RECT  51.304 38.16 51.725 38.232 ;
     RECT  51.442 47.088 51.761 47.4 ;
     RECT  51.761 47.088 51.797 47.304 ;
     RECT  51.304 45.168 51.833 45.576 ;
     RECT  50.929 0.096 51.865 0.552 ;
     RECT  51.797 47.28 51.875 47.304 ;
     RECT  51.865 0.096 51.949 0.6 ;
     RECT  51.833 45.36 52.265 45.576 ;
     RECT  51.304 39.792 52.445 44.088 ;
     RECT  51.304 5.76 52.477 5.88 ;
     RECT  52.445 39.792 52.553 42.36 ;
     RECT  52.477 4.992 52.585 5.88 ;
     RECT  52.445 43.344 52.625 44.088 ;
     RECT  52.585 4.992 52.693 6.072 ;
     RECT  52.553 39.792 52.729 41.256 ;
     RECT  51.304 36.288 52.765 36.84 ;
     RECT  52.729 39.36 52.769 41.256 ;
     RECT  51.725 38.16 52.796 38.184 ;
     RECT  51.949 0.096 52.801 0.216 ;
     RECT  52.265 45.36 52.805 45.528 ;
     RECT  52.796 38.016 52.837 38.184 ;
     RECT  52.769 39.36 52.837 40.968 ;
     RECT  52.801 0.048 52.841 0.216 ;
     RECT  52.837 38.016 52.883 40.968 ;
     RECT  52.693 4.368 52.913 6.072 ;
     RECT  52.553 42.24 52.913 42.36 ;
     RECT  51.401 7.152 53.377 35.208 ;
     RECT  52.765 36.192 53.377 36.84 ;
     RECT  52.841 0.048 53.389 0.168 ;
     RECT  53.377 7.152 53.413 36.84 ;
     RECT  52.805 45.36 53.597 45.384 ;
     RECT  53.413 7.152 53.701 37.176 ;
     RECT  52.625 43.824 53.773 44.088 ;
     RECT  52.913 4.992 53.881 6.072 ;
     RECT  53.701 7.104 53.881 37.176 ;
     RECT  53.881 4.992 53.953 37.176 ;
     RECT  52.913 42.336 54.085 42.36 ;
     RECT  53.773 43.824 54.085 44.568 ;
     RECT  54.085 43.488 54.131 44.568 ;
     RECT  53.953 4.416 54.173 37.176 ;
     RECT  54.173 5.04 54.205 37.176 ;
     RECT  52.883 38.16 54.205 40.968 ;
     RECT  54.085 42 54.205 42.36 ;
     RECT  51.304 1.728 54.469 1.752 ;
     RECT  53.389 0.048 54.61 0.12 ;
     RECT  54.205 5.04 54.677 42.36 ;
     RECT  54.677 37.632 54.889 42.36 ;
     RECT  54.131 43.488 54.889 44.088 ;
     RECT  54.61 0.048 55.177 0.168 ;
     RECT  54.469 1.728 55.289 1.8 ;
     RECT  55.177 0.048 55.379 0.216 ;
     RECT  54.677 5.04 55.429 36.504 ;
     RECT  55.429 4.992 55.465 36.504 ;
     RECT  55.289 1.728 56.408 1.752 ;
     RECT  55.465 4.224 56.408 36.504 ;
     RECT  54.889 37.632 56.408 44.088 ;
     RECT  55.379 0.048 56.485 0.12 ;
     RECT  56.408 1.728 56.545 45.372 ;
     RECT  56.545 1.728 56.704 46.2 ;
     RECT  56.485 0.048 56.765 0.552 ;
     RECT  56.704 3.984 56.977 46.2 ;
     RECT  56.977 3.984 57.107 46.776 ;
     RECT  57.107 3.984 57.125 42.792 ;
     RECT  56.765 0.048 57.341 0.168 ;
     RECT  57.107 44.064 57.395 46.776 ;
     RECT  57.125 3.984 57.485 38.424 ;
     RECT  56.704 1.728 57.557 1.8 ;
     RECT  57.485 3.984 57.593 36.312 ;
     RECT  57.395 44.064 58.093 45.576 ;
     RECT  58.093 43.92 58.105 45.576 ;
     RECT  57.395 46.704 58.355 46.776 ;
     RECT  57.341 0.048 58.373 0.072 ;
     RECT  57.593 4.224 58.499 36.312 ;
     RECT  58.355 46.704 58.739 46.728 ;
     RECT  57.125 39.792 58.813 42.792 ;
     RECT  58.105 43.92 58.813 45.288 ;
     RECT  57.485 37.44 58.885 38.424 ;
     RECT  58.885 37.344 58.957 38.424 ;
     RECT  58.813 39.792 59.029 45.288 ;
     RECT  59.029 39.6 59.141 45.288 ;
     RECT  59.141 43.632 59.173 45.288 ;
     RECT  58.499 4.224 59.425 35.208 ;
     RECT  59.141 39.6 59.537 42.648 ;
     RECT  59.173 43.632 59.573 45.336 ;
     RECT  58.957 36.48 59.603 38.424 ;
     RECT  59.425 3.84 59.641 35.208 ;
     RECT  58.373 0.048 59.724 0.12 ;
     RECT  59.573 43.632 59.753 43.896 ;
     RECT  59.603 37.344 59.756 38.424 ;
     RECT  59.537 39.6 59.756 41.976 ;
     RECT  59.724 0.048 59.813 0.168 ;
     RECT  59.641 3.84 59.825 35.928 ;
     RECT  59.813 0.048 59.897 0.6 ;
     RECT  59.573 44.88 60.005 45.336 ;
     RECT  59.753 43.872 60.221 43.896 ;
     RECT  59.825 3.936 60.761 35.928 ;
     RECT  59.756 37.344 61.009 41.976 ;
     RECT  61.009 37.344 61.525 42.216 ;
     RECT  61.525 37.152 61.549 42.216 ;
     RECT  60.761 4.176 61.657 35.928 ;
     RECT  57.557 1.728 61.729 1.752 ;
     RECT  61.549 37.104 61.765 42.216 ;
     RECT  61.729 1.728 61.808 1.8 ;
     RECT  61.657 4.176 61.808 35.976 ;
     RECT  61.765 37.056 61.808 42.216 ;
     RECT  60.005 44.88 61.808 44.904 ;
     RECT  61.808 1.728 61.912 45.372 ;
     RECT  59.897 0.048 61.945 0.168 ;
     RECT  61.945 0.048 62.099 0.552 ;
     RECT  61.912 1.728 62.104 45.102 ;
     RECT  62.104 37.104 62.129 42.216 ;
     RECT  62.104 3.408 62.243 35.496 ;
     RECT  62.243 4.128 62.453 35.496 ;
     RECT  62.453 4.128 62.857 35.448 ;
     RECT  62.129 37.152 63.461 42.216 ;
     RECT  62.857 5.232 63.533 35.448 ;
     RECT  63.461 37.152 63.569 41.784 ;
     RECT  63.533 5.232 63.641 35.304 ;
     RECT  63.641 5.232 63.821 35.208 ;
     RECT  62.099 0.048 63.853 0.12 ;
     RECT  63.853 0.048 63.937 0.6 ;
     RECT  63.821 5.232 64.001 5.592 ;
     RECT  63.569 37.296 64.217 41.784 ;
     RECT  64.217 37.296 64.717 39.816 ;
     RECT  63.937 0.048 64.793 0.168 ;
     RECT  63.821 6.624 64.965 35.208 ;
     RECT  64.717 36.528 65.189 39.816 ;
     RECT  64.001 5.232 65.329 5.256 ;
     RECT  62.104 1.728 65.376 1.752 ;
     RECT  65.189 36.528 65.441 37.368 ;
     RECT  64.965 34.656 65.509 35.208 ;
     RECT  65.509 34.656 65.66 35.352 ;
     RECT  65.66 34.656 65.747 35.976 ;
     RECT  62.857 4.128 65.905 4.248 ;
     RECT  65.329 5.232 65.905 5.592 ;
     RECT  62.104 44.88 65.905 44.904 ;
     RECT  64.969 46.752 65.939 46.776 ;
     RECT  64.965 6.624 66.013 33.672 ;
     RECT  65.747 34.656 66.013 35.448 ;
     RECT  64.217 40.848 66.013 41.784 ;
     RECT  65.441 37.2 66.053 37.368 ;
     RECT  65.189 38.448 66.161 39.816 ;
     RECT  66.013 40.848 66.869 42.6 ;
     RECT  66.161 38.448 66.877 39.576 ;
     RECT  66.853 47.328 66.901 47.352 ;
     RECT  66.901 46.704 67.043 47.352 ;
     RECT  66.869 40.848 67.093 43.32 ;
     RECT  65.905 4.128 67.129 5.592 ;
     RECT  66.013 6.624 67.129 35.448 ;
     RECT  65.376 1.728 67.208 1.8 ;
     RECT  67.129 4.128 67.208 35.448 ;
     RECT  66.053 37.2 67.208 37.224 ;
     RECT  66.877 38.208 67.208 39.576 ;
     RECT  67.093 40.56 67.208 43.32 ;
     RECT  65.905 44.88 67.208 45.576 ;
     RECT  67.208 1.728 67.237 45.576 ;
     RECT  67.237 1.104 67.385 45.576 ;
     RECT  64.793 0.048 67.429 0.12 ;
     RECT  67.385 1.728 67.504 45.576 ;
     RECT  67.429 0.048 67.565 0.552 ;
     RECT  67.504 4.128 67.673 36.024 ;
     RECT  67.504 44.88 67.813 45.576 ;
     RECT  67.813 44.88 67.955 45.624 ;
     RECT  67.673 4.128 67.961 35.208 ;
     RECT  67.565 0.048 68.069 0.168 ;
     RECT  67.961 4.128 68.213 4.248 ;
     RECT  67.955 44.88 68.249 45.384 ;
     RECT  68.213 4.224 68.357 4.248 ;
     RECT  68.249 44.88 68.393 45.336 ;
     RECT  67.961 5.712 68.429 35.208 ;
     RECT  68.393 44.88 68.465 44.904 ;
     RECT  67.504 41.664 68.629 43.176 ;
     RECT  67.504 1.728 68.681 1.8 ;
     RECT  67.504 38.208 68.753 39.768 ;
     RECT  68.429 11.136 68.963 35.208 ;
     RECT  68.069 0.048 69.112 0.12 ;
     RECT  68.629 41.664 69.185 43.368 ;
     RECT  69.185 43.344 69.221 43.368 ;
     RECT  69.185 41.664 69.532 42.264 ;
     RECT  68.429 5.712 69.613 9.816 ;
     RECT  69.112 0.048 69.625 0.168 ;
     RECT  69.613 5.04 69.689 9.816 ;
     RECT  69.689 6.96 69.793 9.816 ;
     RECT  68.681 1.728 69.804 1.752 ;
     RECT  68.963 11.136 69.973 33.048 ;
     RECT  69.685 37.776 69.973 37.8 ;
     RECT  68.753 39.024 69.973 39.768 ;
     RECT  69.973 11.136 70.009 33.144 ;
     RECT  68.963 34.224 70.009 35.208 ;
     RECT  69.973 37.776 70.477 39.768 ;
     RECT  69.793 6.96 70.481 9.912 ;
     RECT  69.532 41.664 70.517 41.688 ;
     RECT  70.481 8.784 70.549 9.912 ;
     RECT  70.009 11.136 70.549 35.208 ;
     RECT  70.477 37.776 70.691 40.488 ;
     RECT  70.481 6.96 70.765 7.8 ;
     RECT  70.691 37.776 70.805 39.768 ;
     RECT  70.549 36.576 70.837 36.6 ;
     RECT  70.549 8.784 70.877 35.208 ;
     RECT  70.805 39.024 70.877 39.768 ;
     RECT  70.877 8.976 71.017 35.208 ;
     RECT  70.877 39.216 71.021 39.288 ;
     RECT  69.689 5.04 71.221 5.064 ;
     RECT  70.765 6.192 71.221 7.8 ;
     RECT  69.625 0.048 71.244 0.12 ;
     RECT  71.221 5.04 71.267 7.8 ;
     RECT  71.017 8.976 71.273 35.496 ;
     RECT  71.273 8.976 71.309 9.192 ;
     RECT  70.805 37.776 71.309 37.8 ;
     RECT  71.309 8.976 71.342 9.048 ;
     RECT  70.837 36.48 71.345 36.6 ;
     RECT  71.267 5.712 71.417 7.8 ;
     RECT  71.345 36.576 71.521 36.6 ;
     RECT  71.417 5.712 71.525 5.784 ;
     RECT  71.521 36.576 71.525 37.224 ;
     RECT  71.273 10.176 71.629 35.496 ;
     RECT  71.021 39.216 71.845 39.24 ;
     RECT  69.804 1.728 72.608 1.8 ;
     RECT  71.525 5.76 72.608 5.784 ;
     RECT  71.417 7.344 72.608 7.368 ;
     RECT  71.342 8.976 72.608 9 ;
     RECT  71.629 10.176 72.608 35.592 ;
     RECT  71.525 37.2 72.608 37.224 ;
     RECT  71.845 38.784 72.608 39.24 ;
     RECT  72.608 1.728 72.712 45.372 ;
     RECT  71.244 0.048 72.805 0.168 ;
     RECT  72.712 1.728 72.904 45.102 ;
     RECT  72.805 0.048 72.965 0.552 ;
     RECT  72.904 12.288 73.117 34.248 ;
     RECT  73.117 12.288 73.433 32.808 ;
     RECT  73.433 12.288 73.505 17.208 ;
     RECT  73.117 33.936 73.577 34.248 ;
     RECT  73.505 12.288 73.649 13.08 ;
     RECT  73.433 18.432 73.757 32.808 ;
     RECT  73.757 18.432 73.901 30.648 ;
     RECT  73.901 18.432 74.009 30.6 ;
     RECT  73.577 33.936 74.009 33.96 ;
     RECT  74.009 18.432 74.081 24.504 ;
     RECT  74.009 25.488 74.092 30.6 ;
     RECT  73.505 14.112 74.117 17.208 ;
     RECT  73.757 31.92 74.153 32.808 ;
     RECT  72.965 0.048 74.405 0.168 ;
     RECT  74.117 14.112 74.441 15.864 ;
     RECT  74.092 25.488 74.513 25.512 ;
     RECT  74.153 31.92 74.585 32.04 ;
     RECT  74.441 14.112 74.621 15.24 ;
     RECT  74.585 31.92 74.621 31.944 ;
     RECT  74.081 18.432 74.729 21.528 ;
     RECT  74.092 26.64 74.729 30.6 ;
     RECT  74.729 26.64 74.809 28.536 ;
     RECT  74.809 26.64 74.812 28.248 ;
     RECT  74.729 18.432 74.837 21.48 ;
     RECT  74.837 18.432 74.869 19.032 ;
     RECT  74.081 22.512 74.873 24.504 ;
     RECT  74.837 20.16 74.945 21.48 ;
     RECT  74.729 29.52 74.945 30.6 ;
     RECT  74.945 20.592 74.981 21.48 ;
     RECT  74.812 27.312 75.161 28.248 ;
     RECT  74.873 24.48 75.233 24.504 ;
     RECT  74.945 29.52 75.233 30.168 ;
     RECT  74.869 18.144 75.253 19.032 ;
     RECT  75.253 17.904 75.269 19.032 ;
     RECT  75.269 17.904 75.299 18.84 ;
     RECT  74.873 22.512 75.377 23.4 ;
     RECT  75.161 27.312 75.377 27.336 ;
     RECT  75.299 17.904 75.404 18.456 ;
     RECT  74.621 14.688 75.413 15.24 ;
     RECT  73.649 13.056 75.491 13.08 ;
     RECT  75.404 17.04 75.491 18.456 ;
     RECT  75.491 18.192 75.557 18.456 ;
     RECT  75.377 22.704 75.58 23.4 ;
     RECT  75.413 15.216 75.593 15.24 ;
     RECT  75.233 29.664 75.773 30.168 ;
     RECT  74.981 21.456 75.809 21.48 ;
     RECT  75.557 18.432 75.881 18.456 ;
     RECT  75.773 30.144 75.917 30.168 ;
     RECT  75.58 22.704 76.241 22.728 ;
     RECT  72.904 1.728 76.601 1.8 ;
     RECT  76.601 1.776 76.817 1.8 ;
     RECT  76.381 21.648 76.925 21.672 ;
     RECT  74.405 0.048 77.489 0.12 ;
     RECT  77.489 0.048 77.573 0.6 ;
     RECT  77.605 1.728 77.689 1.752 ;
     RECT  77.573 0.048 77.843 0.168 ;
     RECT  78.008 2.148 78.112 45.372 ;
     RECT  78.112 2.418 78.304 45.102 ;
     RECT  80.521 1.728 80.626 1.752 ;
     RECT  80.773 0.096 81.125 0.12 ;
     RECT  81.125 0.096 81.209 0.168 ;
     RECT  81.209 0.096 82.188 0.12 ;
     RECT  82.188 0.096 82.289 0.168 ;
     RECT  82.289 0.096 83.315 0.12 ;
     RECT  80.626 1.728 83.408 1.8 ;
     RECT  83.408 1.728 83.512 45.372 ;
     RECT  83.461 0.528 83.585 0.552 ;
     RECT  83.512 1.728 83.621 45.102 ;
     RECT  83.621 2.418 83.704 45.102 ;
     RECT  88.808 2.148 88.912 45.372 ;
     RECT  88.912 2.418 89.104 45.102 ;
    LAYER M5 ;
     RECT  26.088 0.016 26.16 0.037 ;
     RECT  26.184 0.016 26.256 0.037 ;
     RECT  26.28 0.016 26.352 0.037 ;
     RECT  26.376 0.016 26.448 0.037 ;
     RECT  26.472 0.016 26.544 0.037 ;
     RECT  26.568 0.016 26.64 0.037 ;
     RECT  26.664 0.016 26.736 0.037 ;
     RECT  26.76 0.016 26.832 0.037 ;
     RECT  26.856 0.016 26.928 0.037 ;
     RECT  26.952 0.016 27.024 0.037 ;
     RECT  27.048 0.016 27.12 0.037 ;
     RECT  27.144 0.016 27.216 0.037 ;
     RECT  27.24 0.016 27.312 0.037 ;
     RECT  27.336 0.016 27.408 0.037 ;
     RECT  27.432 0.016 27.504 0.037 ;
     RECT  27.528 0.016 27.6 0.037 ;
     RECT  27.624 0.016 27.696 0.037 ;
     RECT  27.72 0.016 27.792 0.037 ;
     RECT  27.816 0.016 27.888 0.037 ;
     RECT  27.912 0.016 27.984 0.037 ;
     RECT  28.008 0.016 28.08 0.037 ;
     RECT  28.104 0.016 28.176 0.037 ;
     RECT  28.2 0.016 28.272 0.037 ;
     RECT  28.296 0.016 28.368 0.037 ;
     RECT  28.392 0.016 28.464 0.037 ;
     RECT  28.488 0.016 28.56 0.037 ;
     RECT  28.584 0.016 28.656 0.037 ;
     RECT  28.68 0.016 28.752 0.037 ;
     RECT  28.776 0.016 28.848 0.037 ;
     RECT  28.872 0.016 28.944 0.037 ;
     RECT  28.968 0.016 29.04 0.037 ;
     RECT  29.064 0.016 29.136 0.037 ;
     RECT  29.16 0.016 29.232 0.037 ;
     RECT  29.256 0.016 29.328 0.037 ;
     RECT  29.352 0.016 29.424 0.037 ;
     RECT  29.448 0.016 29.52 0.037 ;
     RECT  29.544 0.016 29.616 0.037 ;
     RECT  29.64 0.016 29.712 0.037 ;
     RECT  29.736 0.016 29.808 0.037 ;
     RECT  29.832 0.016 29.904 0.037 ;
     RECT  29.928 0.016 30 0.037 ;
     RECT  30.024 0.016 30.096 0.037 ;
     RECT  30.12 0.016 30.192 0.037 ;
     RECT  30.216 0.016 30.288 0.037 ;
     RECT  30.312 0.016 30.384 0.037 ;
     RECT  30.408 0.016 30.48 0.037 ;
     RECT  30.504 0.016 30.576 0.037 ;
     RECT  30.6 0.016 30.672 0.037 ;
     RECT  30.696 0.016 30.768 0.037 ;
     RECT  30.792 0.016 30.864 0.037 ;
     RECT  30.888 0.016 30.96 0.037 ;
     RECT  30.984 0.016 31.056 0.037 ;
     RECT  31.08 0.016 31.152 0.037 ;
     RECT  31.176 0.016 31.248 0.037 ;
     RECT  31.272 0.016 31.344 0.037 ;
     RECT  31.368 0.016 31.44 0.037 ;
     RECT  31.464 0.016 31.536 0.037 ;
     RECT  31.56 0.016 31.632 0.037 ;
     RECT  31.656 0.016 31.728 0.037 ;
     RECT  31.752 0.016 31.824 0.037 ;
     RECT  31.848 0.016 31.92 0.037 ;
     RECT  31.944 0.016 32.016 0.037 ;
     RECT  32.04 0.016 32.112 0.037 ;
     RECT  32.136 0.016 32.208 0.037 ;
     RECT  32.232 0.016 32.304 0.037 ;
     RECT  32.328 0.016 32.4 0.037 ;
     RECT  32.424 0.016 32.496 0.037 ;
     RECT  32.52 0.016 32.592 0.037 ;
     RECT  32.616 0.016 32.688 0.037 ;
     RECT  32.712 0.016 32.784 0.037 ;
     RECT  32.808 0.016 32.88 0.037 ;
     RECT  32.904 0.016 32.976 0.037 ;
     RECT  33 0.016 33.072 0.037 ;
     RECT  33.096 0.016 33.168 0.037 ;
     RECT  33.192 0.016 33.264 0.037 ;
     RECT  33.288 0.016 33.36 0.037 ;
     RECT  33.384 0.016 33.456 0.037 ;
     RECT  33.48 0.016 33.552 0.037 ;
     RECT  33.576 0.016 33.648 0.037 ;
     RECT  33.672 0.016 33.744 0.037 ;
     RECT  33.768 0.016 33.84 0.037 ;
     RECT  33.864 0.016 33.936 0.037 ;
     RECT  33.96 0.016 34.032 0.037 ;
     RECT  34.056 0.016 34.128 0.037 ;
     RECT  34.152 0.016 34.224 0.037 ;
     RECT  34.248 0.016 34.32 0.037 ;
     RECT  34.344 0.016 34.416 0.037 ;
     RECT  34.44 0.016 34.512 0.037 ;
     RECT  34.536 0.016 34.608 0.037 ;
     RECT  34.632 0.016 34.704 0.037 ;
     RECT  34.728 0.016 34.8 0.037 ;
     RECT  34.824 0.016 34.896 0.037 ;
     RECT  34.92 0.016 34.992 0.037 ;
     RECT  35.016 0.016 35.088 0.037 ;
     RECT  35.112 0.016 35.184 0.037 ;
     RECT  35.208 0.016 35.28 0.037 ;
     RECT  35.304 0.016 35.376 0.037 ;
     RECT  35.4 0.016 35.472 0.037 ;
     RECT  35.496 0.016 35.568 0.037 ;
     RECT  35.592 0.016 35.664 0.037 ;
     RECT  35.688 0.016 35.76 0.037 ;
     RECT  35.784 0.016 35.856 0.037 ;
     RECT  35.88 0.016 35.952 0.037 ;
     RECT  35.976 0.016 36.048 0.037 ;
     RECT  36.072 0.016 36.144 0.037 ;
     RECT  36.168 0.016 36.24 0.037 ;
     RECT  36.264 0.016 36.336 0.037 ;
     RECT  36.36 0.016 36.432 0.037 ;
     RECT  36.456 0.016 36.528 0.037 ;
     RECT  36.552 0.016 36.624 0.037 ;
     RECT  36.648 0.016 36.72 0.037 ;
     RECT  36.744 0.016 36.816 0.037 ;
     RECT  36.84 0.016 36.912 0.037 ;
     RECT  36.936 0.016 37.008 0.037 ;
     RECT  37.032 0.016 37.104 0.037 ;
     RECT  37.128 0.016 37.2 0.037 ;
     RECT  37.224 0.016 37.296 0.037 ;
     RECT  37.32 0.016 37.392 0.037 ;
     RECT  37.416 0.016 37.488 0.037 ;
     RECT  37.512 0.016 37.584 0.037 ;
     RECT  37.608 0.016 37.68 0.037 ;
     RECT  37.704 0.016 37.776 0.037 ;
     RECT  37.8 0.016 37.872 0.037 ;
     RECT  37.896 0.016 37.968 0.037 ;
     RECT  37.992 0.016 38.064 0.037 ;
     RECT  38.088 0.016 38.16 0.037 ;
     RECT  38.184 0.016 38.256 0.037 ;
     RECT  38.28 0.016 39.12 0.037 ;
     RECT  39.144 0.016 39.216 0.037 ;
     RECT  39.24 0.016 39.312 0.037 ;
     RECT  39.336 0.016 39.408 0.037 ;
     RECT  39.432 0.016 39.504 0.037 ;
     RECT  39.528 0.016 39.6 0.037 ;
     RECT  39.624 0.016 39.696 0.037 ;
     RECT  39.72 0.016 39.792 0.037 ;
     RECT  39.816 0.016 39.888 0.037 ;
     RECT  39.912 0.016 39.984 0.037 ;
     RECT  40.008 0.016 40.08 0.037 ;
     RECT  40.104 0.016 40.176 0.037 ;
     RECT  40.2 0.016 40.272 0.037 ;
     RECT  40.296 0.016 40.368 0.037 ;
     RECT  40.392 0.016 40.464 0.037 ;
     RECT  40.488 0.016 40.56 0.037 ;
     RECT  40.584 0.016 40.656 0.037 ;
     RECT  40.68 0.016 40.752 0.037 ;
     RECT  40.776 0.016 40.848 0.037 ;
     RECT  40.872 0.016 40.944 0.037 ;
     RECT  40.968 0.016 41.04 0.037 ;
     RECT  41.064 0.016 41.136 0.037 ;
     RECT  41.16 0.016 41.232 0.037 ;
     RECT  41.256 0.016 41.328 0.037 ;
     RECT  41.352 0.016 41.424 0.037 ;
     RECT  41.448 0.016 41.52 0.037 ;
     RECT  41.544 0.016 41.616 0.037 ;
     RECT  41.64 0.016 41.712 0.037 ;
     RECT  41.736 0.016 41.808 0.037 ;
     RECT  41.832 0.016 41.904 0.037 ;
     RECT  41.928 0.016 42 0.037 ;
     RECT  42.024 0.016 42.096 0.037 ;
     RECT  42.12 0.016 42.192 0.037 ;
     RECT  42.216 0.016 42.288 0.037 ;
     RECT  42.312 0.016 42.384 0.037 ;
     RECT  42.408 0.016 42.48 0.037 ;
     RECT  42.504 0.016 42.576 0.037 ;
     RECT  42.6 0.016 42.672 0.037 ;
     RECT  42.696 0.016 42.768 0.037 ;
     RECT  42.792 0.016 42.864 0.037 ;
     RECT  42.888 0.016 42.96 0.037 ;
     RECT  42.984 0.016 43.056 0.037 ;
     RECT  43.08 0.016 43.152 0.037 ;
     RECT  43.176 0.016 43.248 0.037 ;
     RECT  43.272 0.016 43.344 0.037 ;
     RECT  43.368 0.016 43.44 0.037 ;
     RECT  43.464 0.016 43.536 0.037 ;
     RECT  43.56 0.016 43.632 0.037 ;
     RECT  43.656 0.016 43.728 0.037 ;
     RECT  43.752 0.016 43.824 0.037 ;
     RECT  43.848 0.016 43.92 0.037 ;
     RECT  43.944 0.016 44.016 0.037 ;
     RECT  44.04 0.016 44.112 0.037 ;
     RECT  44.136 0.016 44.208 0.037 ;
     RECT  44.232 0.016 44.304 0.037 ;
     RECT  44.328 0.016 44.4 0.037 ;
     RECT  44.424 0.016 44.496 0.037 ;
     RECT  44.52 0.016 44.592 0.037 ;
     RECT  44.616 0.016 44.688 0.037 ;
     RECT  44.712 0.016 44.784 0.037 ;
     RECT  44.808 0.016 44.88 0.037 ;
     RECT  44.904 0.016 44.976 0.037 ;
     RECT  45 0.016 45.072 0.037 ;
     RECT  45.096 0.016 45.168 0.037 ;
     RECT  45.192 0.016 45.264 0.037 ;
     RECT  45.288 0.016 45.36 0.037 ;
     RECT  45.384 0.016 45.456 0.037 ;
     RECT  45.48 0.016 45.552 0.037 ;
     RECT  45.576 0.016 45.648 0.037 ;
     RECT  45.672 0.016 45.744 0.037 ;
     RECT  45.768 0.016 45.84 0.037 ;
     RECT  45.864 0.016 45.936 0.037 ;
     RECT  45.96 0.016 46.032 0.037 ;
     RECT  46.056 0.016 46.128 0.037 ;
     RECT  46.152 0.016 46.224 0.037 ;
     RECT  46.248 0.016 46.32 0.037 ;
     RECT  46.344 0.016 46.416 0.037 ;
     RECT  46.44 0.016 46.512 0.037 ;
     RECT  46.536 0.016 46.608 0.037 ;
     RECT  46.632 0.016 46.704 0.037 ;
     RECT  46.728 0.016 46.8 0.037 ;
     RECT  46.824 0.016 46.896 0.037 ;
     RECT  46.92 0.016 46.992 0.037 ;
     RECT  47.016 0.016 47.088 0.037 ;
     RECT  47.112 0.016 47.184 0.037 ;
     RECT  47.208 0.016 47.28 0.037 ;
     RECT  47.304 0.016 47.376 0.037 ;
     RECT  47.4 0.016 47.472 0.037 ;
     RECT  47.496 0.016 47.568 0.037 ;
     RECT  47.592 0.016 47.664 0.037 ;
     RECT  47.688 0.016 47.76 0.037 ;
     RECT  47.784 0.016 47.856 0.037 ;
     RECT  47.88 0.016 47.952 0.037 ;
     RECT  47.976 0.016 48.048 0.037 ;
     RECT  48.072 0.016 48.144 0.037 ;
     RECT  48.168 0.016 48.24 0.037 ;
     RECT  48.264 0.016 48.336 0.037 ;
     RECT  48.36 0.016 48.432 0.037 ;
     RECT  48.456 0.016 48.528 0.037 ;
     RECT  48.552 0.016 48.624 0.037 ;
     RECT  48.648 0.016 48.72 0.037 ;
     RECT  48.744 0.016 48.816 0.037 ;
     RECT  48.84 0.016 48.912 0.037 ;
     RECT  48.936 0.016 49.008 0.037 ;
     RECT  49.032 0.016 49.104 0.037 ;
     RECT  49.128 0.016 49.2 0.037 ;
     RECT  49.224 0.016 49.296 0.037 ;
     RECT  49.32 0.016 49.392 0.037 ;
     RECT  49.416 0.016 49.488 0.037 ;
     RECT  49.512 0.016 49.584 0.037 ;
     RECT  49.608 0.016 49.68 0.037 ;
     RECT  49.704 0.016 49.776 0.037 ;
     RECT  49.8 0.016 49.872 0.037 ;
     RECT  49.896 0.016 49.968 0.037 ;
     RECT  49.992 0.016 50.064 0.037 ;
     RECT  50.088 0.016 50.16 0.037 ;
     RECT  50.184 0.016 50.256 0.037 ;
     RECT  50.28 0.016 50.352 0.037 ;
     RECT  50.376 0.016 50.448 0.037 ;
     RECT  50.472 0.016 50.544 0.037 ;
     RECT  50.568 0.016 50.64 0.037 ;
     RECT  50.664 0.016 50.736 0.037 ;
     RECT  50.76 0.016 50.832 0.037 ;
     RECT  50.856 0.016 50.928 0.037 ;
     RECT  50.952 0.016 51.024 0.037 ;
     RECT  51.048 0.016 51.12 0.037 ;
     RECT  51.144 0.016 51.216 0.037 ;
     RECT  51.24 0.016 51.312 0.037 ;
     RECT  51.336 0.016 51.408 0.037 ;
     RECT  51.432 0.016 51.504 0.037 ;
     RECT  51.528 0.016 51.6 0.037 ;
     RECT  51.624 0.016 51.696 0.037 ;
     RECT  51.72 0.016 51.792 0.037 ;
     RECT  51.816 0.016 51.888 0.037 ;
     RECT  51.912 0.016 51.984 0.037 ;
     RECT  52.008 0.016 52.08 0.037 ;
     RECT  52.104 0.016 52.176 0.037 ;
     RECT  52.2 0.016 52.272 0.037 ;
     RECT  52.296 0.016 52.368 0.037 ;
     RECT  52.392 0.016 52.464 0.037 ;
     RECT  52.488 0.016 52.56 0.037 ;
     RECT  52.584 0.016 52.656 0.037 ;
     RECT  52.68 0.016 52.752 0.037 ;
     RECT  52.776 0.016 52.848 0.037 ;
     RECT  52.872 0.016 52.944 0.037 ;
     RECT  52.968 0.016 53.04 0.037 ;
     RECT  53.064 0.016 53.136 0.037 ;
     RECT  53.16 0.016 53.232 0.037 ;
     RECT  53.256 0.016 53.328 0.037 ;
     RECT  53.352 0.016 53.424 0.037 ;
     RECT  53.448 0.016 53.52 0.037 ;
     RECT  53.544 0.016 53.616 0.037 ;
     RECT  53.64 0.016 53.712 0.037 ;
     RECT  53.736 0.016 53.808 0.037 ;
     RECT  53.832 0.016 53.904 0.037 ;
     RECT  53.928 0.016 54 0.037 ;
     RECT  54.024 0.016 54.096 0.037 ;
     RECT  54.12 0.016 54.192 0.037 ;
     RECT  54.216 0.016 54.288 0.037 ;
     RECT  54.312 0.016 54.384 0.037 ;
     RECT  54.408 0.016 54.48 0.037 ;
     RECT  54.504 0.016 54.576 0.037 ;
     RECT  54.6 0.016 54.672 0.037 ;
     RECT  54.696 0.016 54.768 0.037 ;
     RECT  54.792 0.016 54.864 0.037 ;
     RECT  54.888 0.016 54.96 0.037 ;
     RECT  54.984 0.016 55.056 0.037 ;
     RECT  55.08 0.016 55.152 0.037 ;
     RECT  55.176 0.016 55.248 0.037 ;
     RECT  55.272 0.016 55.344 0.037 ;
     RECT  55.368 0.016 55.44 0.037 ;
     RECT  55.464 0.016 55.536 0.037 ;
     RECT  55.56 0.016 55.632 0.037 ;
     RECT  55.656 0.016 55.728 0.037 ;
     RECT  55.752 0.016 55.824 0.037 ;
     RECT  55.848 0.016 55.92 0.037 ;
     RECT  55.944 0.016 56.016 0.037 ;
     RECT  56.04 0.016 56.112 0.037 ;
     RECT  56.136 0.016 56.208 0.037 ;
     RECT  56.232 0.016 56.304 0.037 ;
     RECT  56.328 0.016 56.4 0.037 ;
     RECT  56.424 0.016 56.496 0.037 ;
     RECT  56.52 0.016 56.592 0.037 ;
     RECT  56.616 0.016 56.688 0.037 ;
     RECT  56.712 0.016 56.784 0.037 ;
     RECT  56.808 0.016 56.88 0.037 ;
     RECT  56.904 0.016 56.976 0.037 ;
     RECT  57 0.016 57.072 0.037 ;
     RECT  57.096 0.016 57.168 0.037 ;
     RECT  57.192 0.016 57.264 0.037 ;
     RECT  57.288 0.016 57.36 0.037 ;
     RECT  57.384 0.016 57.456 0.037 ;
     RECT  57.48 0.016 58.32 0.037 ;
     RECT  58.344 0.016 58.416 0.037 ;
     RECT  58.44 0.016 58.512 0.037 ;
     RECT  58.536 0.016 58.608 0.037 ;
     RECT  58.632 0.016 58.704 0.037 ;
     RECT  58.728 0.016 58.8 0.037 ;
     RECT  58.824 0.016 58.896 0.037 ;
     RECT  58.92 0.016 58.992 0.037 ;
     RECT  59.016 0.016 59.088 0.037 ;
     RECT  59.112 0.016 59.184 0.037 ;
     RECT  59.208 0.016 59.28 0.037 ;
     RECT  59.304 0.016 59.376 0.037 ;
     RECT  59.4 0.016 59.472 0.037 ;
     RECT  59.496 0.016 59.568 0.037 ;
     RECT  59.592 0.016 59.664 0.037 ;
     RECT  59.688 0.016 59.76 0.037 ;
     RECT  59.784 0.016 59.856 0.037 ;
     RECT  59.88 0.016 59.952 0.037 ;
     RECT  59.976 0.016 60.048 0.037 ;
     RECT  60.072 0.016 60.144 0.037 ;
     RECT  60.168 0.016 60.24 0.037 ;
     RECT  60.264 0.016 60.336 0.037 ;
     RECT  60.36 0.016 60.432 0.037 ;
     RECT  60.456 0.016 60.528 0.037 ;
     RECT  60.552 0.016 60.624 0.037 ;
     RECT  60.648 0.016 60.72 0.037 ;
     RECT  60.744 0.016 60.816 0.037 ;
     RECT  60.84 0.016 60.912 0.037 ;
     RECT  60.936 0.016 61.008 0.037 ;
     RECT  61.032 0.016 61.104 0.037 ;
     RECT  61.128 0.016 61.2 0.037 ;
     RECT  61.224 0.016 61.296 0.037 ;
     RECT  61.32 0.016 61.392 0.037 ;
     RECT  61.416 0.016 61.488 0.037 ;
     RECT  61.512 0.016 61.584 0.037 ;
     RECT  61.608 0.016 61.68 0.037 ;
     RECT  61.704 0.016 61.776 0.037 ;
     RECT  61.8 0.016 61.872 0.037 ;
     RECT  61.896 0.016 61.968 0.037 ;
     RECT  61.992 0.016 62.064 0.037 ;
     RECT  62.088 0.016 62.16 0.037 ;
     RECT  62.184 0.016 62.256 0.037 ;
     RECT  62.28 0.016 62.352 0.037 ;
     RECT  62.376 0.016 62.448 0.037 ;
     RECT  62.472 0.016 62.544 0.037 ;
     RECT  62.568 0.016 62.64 0.037 ;
     RECT  62.664 0.016 62.736 0.037 ;
     RECT  62.76 0.016 62.832 0.037 ;
     RECT  62.856 0.016 62.928 0.037 ;
     RECT  62.952 0.016 63.024 0.037 ;
     RECT  63.048 0.016 63.12 0.037 ;
     RECT  63.144 0.016 63.216 0.037 ;
     RECT  63.24 0.016 63.312 0.037 ;
     RECT  63.336 0.016 63.408 0.037 ;
     RECT  63.432 0.016 63.504 0.037 ;
     RECT  63.528 0.016 63.6 0.037 ;
     RECT  63.624 0.016 63.696 0.037 ;
     RECT  63.72 0.016 63.792 0.037 ;
     RECT  63.816 0.016 63.888 0.037 ;
     RECT  63.912 0.016 63.984 0.037 ;
     RECT  64.008 0.016 64.08 0.037 ;
     RECT  64.104 0.016 64.176 0.037 ;
     RECT  64.2 0.016 64.272 0.037 ;
     RECT  64.296 0.016 64.368 0.037 ;
     RECT  64.392 0.016 64.464 0.037 ;
     RECT  64.488 0.016 64.56 0.037 ;
     RECT  64.584 0.016 64.656 0.037 ;
     RECT  64.68 0.016 64.752 0.037 ;
     RECT  64.776 0.016 64.848 0.037 ;
     RECT  64.872 0.016 64.944 0.037 ;
     RECT  64.968 0.016 65.04 0.037 ;
     RECT  65.064 0.016 65.136 0.037 ;
     RECT  65.16 0.016 65.232 0.037 ;
     RECT  65.256 0.016 65.328 0.037 ;
     RECT  65.352 0.016 65.424 0.037 ;
     RECT  65.448 0.016 65.52 0.037 ;
     RECT  65.544 0.016 65.616 0.037 ;
     RECT  65.64 0.016 65.712 0.037 ;
     RECT  65.736 0.016 65.808 0.037 ;
     RECT  65.832 0.016 65.904 0.037 ;
     RECT  65.928 0.016 66 0.037 ;
     RECT  66.024 0.016 66.096 0.037 ;
     RECT  66.12 0.016 66.192 0.037 ;
     RECT  66.216 0.016 66.288 0.037 ;
     RECT  66.312 0.016 66.384 0.037 ;
     RECT  66.408 0.016 66.48 0.037 ;
     RECT  66.504 0.016 66.576 0.037 ;
     RECT  66.6 0.016 66.672 0.037 ;
     RECT  66.696 0.016 66.768 0.037 ;
     RECT  66.792 0.016 66.864 0.037 ;
     RECT  66.888 0.016 66.96 0.037 ;
     RECT  66.984 0.016 67.056 0.037 ;
     RECT  67.08 0.016 67.152 0.037 ;
     RECT  67.176 0.016 67.248 0.037 ;
     RECT  67.272 0.016 67.344 0.037 ;
     RECT  67.368 0.016 67.44 0.037 ;
     RECT  67.464 0.016 67.536 0.037 ;
     RECT  67.56 0.016 67.632 0.037 ;
     RECT  67.656 0.016 67.728 0.037 ;
     RECT  67.752 0.016 67.824 0.037 ;
     RECT  67.848 0.016 67.92 0.037 ;
     RECT  67.944 0.016 68.016 0.037 ;
     RECT  68.04 0.016 68.112 0.037 ;
     RECT  68.136 0.016 68.208 0.037 ;
     RECT  68.232 0.016 68.304 0.037 ;
     RECT  68.328 0.016 68.4 0.037 ;
     RECT  68.424 0.016 68.496 0.037 ;
     RECT  68.52 0.016 68.592 0.037 ;
     RECT  68.616 0.016 68.688 0.037 ;
     RECT  68.712 0.016 68.784 0.037 ;
     RECT  68.808 0.016 68.88 0.037 ;
     RECT  68.904 0.016 68.976 0.037 ;
     RECT  69 0.016 69.072 0.037 ;
     RECT  69.096 0.016 69.168 0.037 ;
     RECT  69.192 0.016 69.264 0.037 ;
     RECT  69.288 0.016 69.36 0.037 ;
     RECT  69.384 0.016 69.456 0.037 ;
     RECT  69.48 0.016 69.552 0.037 ;
     RECT  69.576 0.016 69.648 0.037 ;
     RECT  69.672 0.016 69.744 0.037 ;
     RECT  69.768 0.016 69.84 0.037 ;
     RECT  69.864 0.016 69.936 0.037 ;
     RECT  69.96 0.016 70.032 0.037 ;
     RECT  70.056 0.016 70.128 0.037 ;
     RECT  70.152 0.016 70.224 0.037 ;
     RECT  70.248 0.016 70.32 0.037 ;
     RECT  70.344 0.016 70.416 0.037 ;
     RECT  70.44 0.016 70.512 0.037 ;
     RECT  70.536 0.016 70.608 0.037 ;
     RECT  70.632 0.016 70.704 0.037 ;
     RECT  70.728 0.016 70.8 0.037 ;
     RECT  70.824 0.016 70.896 0.037 ;
     RECT  70.92 0.016 70.992 0.037 ;
     RECT  71.016 0.016 71.088 0.037 ;
     RECT  71.112 0.016 71.184 0.037 ;
     RECT  71.208 0.016 71.28 0.037 ;
     RECT  71.304 0.016 71.376 0.037 ;
     RECT  71.4 0.016 71.472 0.037 ;
     RECT  71.496 0.016 71.568 0.037 ;
     RECT  71.592 0.016 71.664 0.037 ;
     RECT  71.688 0.016 71.76 0.037 ;
     RECT  71.784 0.016 71.856 0.037 ;
     RECT  71.88 0.016 71.952 0.037 ;
     RECT  71.976 0.016 72.048 0.037 ;
     RECT  72.072 0.016 72.144 0.037 ;
     RECT  72.168 0.016 72.24 0.037 ;
     RECT  72.264 0.016 72.336 0.037 ;
     RECT  72.36 0.016 72.432 0.037 ;
     RECT  72.456 0.016 72.528 0.037 ;
     RECT  72.552 0.016 72.624 0.037 ;
     RECT  72.648 0.016 72.72 0.037 ;
     RECT  72.744 0.016 72.816 0.037 ;
     RECT  72.84 0.016 72.912 0.037 ;
     RECT  72.936 0.016 73.008 0.037 ;
     RECT  73.032 0.016 73.104 0.037 ;
     RECT  73.128 0.016 73.2 0.037 ;
     RECT  73.224 0.016 73.296 0.037 ;
     RECT  73.32 0.016 73.392 0.037 ;
     RECT  73.416 0.016 73.488 0.037 ;
     RECT  73.512 0.016 73.584 0.037 ;
     RECT  73.608 0.016 73.68 0.037 ;
     RECT  73.704 0.016 73.776 0.037 ;
     RECT  73.8 0.016 73.872 0.037 ;
     RECT  73.896 0.016 73.968 0.037 ;
     RECT  73.992 0.016 74.064 0.037 ;
     RECT  74.088 0.016 74.16 0.037 ;
     RECT  74.184 0.016 74.256 0.037 ;
     RECT  74.28 0.016 74.352 0.037 ;
     RECT  74.376 0.016 74.448 0.037 ;
     RECT  74.472 0.016 74.544 0.037 ;
     RECT  74.568 0.016 74.64 0.037 ;
     RECT  74.664 0.016 74.736 0.037 ;
     RECT  74.76 0.016 74.832 0.037 ;
     RECT  74.856 0.016 74.928 0.037 ;
     RECT  74.952 0.016 75.024 0.037 ;
     RECT  75.048 0.016 75.12 0.037 ;
     RECT  75.144 0.016 75.216 0.037 ;
     RECT  75.24 0.016 75.312 0.037 ;
     RECT  75.336 0.016 75.408 0.037 ;
     RECT  75.432 0.016 75.504 0.037 ;
     RECT  75.528 0.016 75.6 0.037 ;
     RECT  75.624 0.016 75.696 0.037 ;
     RECT  75.72 0.016 75.792 0.037 ;
     RECT  75.816 0.016 75.888 0.037 ;
     RECT  75.912 0.016 75.984 0.037 ;
     RECT  76.008 0.016 76.08 0.037 ;
     RECT  76.104 0.016 76.176 0.037 ;
     RECT  76.2 0.016 76.272 0.037 ;
     RECT  76.296 0.016 76.368 0.037 ;
     RECT  76.392 0.016 76.464 0.037 ;
     RECT  76.488 0.016 76.56 0.037 ;
     RECT  76.584 0.016 76.656 0.037 ;
     RECT  76.68 0.016 77.52 0.037 ;
     RECT  77.544 0.016 77.616 0.037 ;
     RECT  77.64 0.016 77.712 0.037 ;
     RECT  26.088 0.037 26.16 0.084 ;
     RECT  26.184 0.037 26.256 0.084 ;
     RECT  26.28 0.037 26.352 0.084 ;
     RECT  26.376 0.037 26.448 0.084 ;
     RECT  26.472 0.037 26.544 0.084 ;
     RECT  26.568 0.037 26.64 0.084 ;
     RECT  26.664 0.037 26.736 0.084 ;
     RECT  26.76 0.037 26.832 0.084 ;
     RECT  26.856 0.037 26.928 0.084 ;
     RECT  26.952 0.037 27.024 0.084 ;
     RECT  27.048 0.037 27.12 0.084 ;
     RECT  27.144 0.037 27.216 0.084 ;
     RECT  27.24 0.037 27.312 0.084 ;
     RECT  27.336 0.037 27.408 0.084 ;
     RECT  27.432 0.037 27.504 0.084 ;
     RECT  27.528 0.037 27.6 0.084 ;
     RECT  27.624 0.037 27.696 0.084 ;
     RECT  27.72 0.037 27.792 0.084 ;
     RECT  27.816 0.037 27.888 0.084 ;
     RECT  27.912 0.037 27.984 0.084 ;
     RECT  28.008 0.037 28.08 0.084 ;
     RECT  28.104 0.037 28.176 0.084 ;
     RECT  28.2 0.037 28.272 0.084 ;
     RECT  28.296 0.037 28.368 0.084 ;
     RECT  28.392 0.037 28.464 0.084 ;
     RECT  28.488 0.037 28.56 0.084 ;
     RECT  28.584 0.037 28.656 0.084 ;
     RECT  28.68 0.037 28.752 0.084 ;
     RECT  28.776 0.037 28.848 0.084 ;
     RECT  28.872 0.037 28.944 0.084 ;
     RECT  28.968 0.037 29.04 0.084 ;
     RECT  29.064 0.037 29.136 0.084 ;
     RECT  29.16 0.037 29.232 0.084 ;
     RECT  29.256 0.037 29.328 0.084 ;
     RECT  29.352 0.037 29.424 0.084 ;
     RECT  29.448 0.037 29.52 0.084 ;
     RECT  29.544 0.037 29.616 0.084 ;
     RECT  29.64 0.037 29.712 0.084 ;
     RECT  29.736 0.037 29.808 0.084 ;
     RECT  29.832 0.037 29.904 0.084 ;
     RECT  29.928 0.037 30 0.084 ;
     RECT  30.024 0.037 30.096 0.084 ;
     RECT  30.12 0.037 30.192 0.084 ;
     RECT  30.216 0.037 30.288 0.084 ;
     RECT  30.312 0.037 30.384 0.084 ;
     RECT  30.408 0.037 30.48 0.084 ;
     RECT  30.504 0.037 30.576 0.084 ;
     RECT  30.6 0.037 30.672 0.084 ;
     RECT  30.696 0.037 30.768 0.084 ;
     RECT  30.792 0.037 30.864 0.084 ;
     RECT  30.888 0.037 30.96 0.084 ;
     RECT  30.984 0.037 31.056 0.084 ;
     RECT  31.08 0.037 31.152 0.084 ;
     RECT  31.176 0.037 31.248 0.084 ;
     RECT  31.272 0.037 31.344 0.084 ;
     RECT  31.368 0.037 31.44 0.084 ;
     RECT  31.464 0.037 31.536 0.084 ;
     RECT  31.56 0.037 31.632 0.084 ;
     RECT  31.656 0.037 31.728 0.084 ;
     RECT  31.752 0.037 31.824 0.084 ;
     RECT  31.848 0.037 31.92 0.084 ;
     RECT  31.944 0.037 32.016 0.084 ;
     RECT  32.04 0.037 32.112 0.084 ;
     RECT  32.136 0.037 32.208 0.084 ;
     RECT  32.232 0.037 32.304 0.084 ;
     RECT  32.328 0.037 32.4 0.084 ;
     RECT  32.424 0.037 32.496 0.084 ;
     RECT  32.52 0.037 32.592 0.084 ;
     RECT  32.616 0.037 32.688 0.084 ;
     RECT  32.712 0.037 32.784 0.084 ;
     RECT  32.808 0.037 32.88 0.084 ;
     RECT  32.904 0.037 32.976 0.084 ;
     RECT  33 0.037 33.072 0.084 ;
     RECT  33.096 0.037 33.168 0.084 ;
     RECT  33.192 0.037 33.264 0.084 ;
     RECT  33.288 0.037 33.36 0.084 ;
     RECT  33.384 0.037 33.456 0.084 ;
     RECT  33.48 0.037 33.552 0.084 ;
     RECT  33.576 0.037 33.648 0.084 ;
     RECT  33.672 0.037 33.744 0.084 ;
     RECT  33.768 0.037 33.84 0.084 ;
     RECT  33.864 0.037 33.936 0.084 ;
     RECT  33.96 0.037 34.032 0.084 ;
     RECT  34.056 0.037 34.128 0.084 ;
     RECT  34.152 0.037 34.224 0.084 ;
     RECT  34.248 0.037 34.32 0.084 ;
     RECT  34.344 0.037 34.416 0.084 ;
     RECT  34.44 0.037 34.512 0.084 ;
     RECT  34.536 0.037 34.608 0.084 ;
     RECT  34.632 0.037 34.704 0.084 ;
     RECT  34.728 0.037 34.8 0.084 ;
     RECT  34.824 0.037 34.896 0.084 ;
     RECT  34.92 0.037 34.992 0.084 ;
     RECT  35.016 0.037 35.088 0.084 ;
     RECT  35.112 0.037 35.184 0.084 ;
     RECT  35.208 0.037 35.28 0.084 ;
     RECT  35.304 0.037 35.376 0.084 ;
     RECT  35.4 0.037 35.472 0.084 ;
     RECT  35.496 0.037 35.568 0.084 ;
     RECT  35.592 0.037 35.664 0.084 ;
     RECT  35.688 0.037 35.76 0.084 ;
     RECT  35.784 0.037 35.856 0.084 ;
     RECT  35.88 0.037 35.952 0.084 ;
     RECT  35.976 0.037 36.048 0.084 ;
     RECT  36.072 0.037 36.144 0.084 ;
     RECT  36.168 0.037 36.24 0.084 ;
     RECT  36.264 0.037 36.336 0.084 ;
     RECT  36.36 0.037 36.432 0.084 ;
     RECT  36.456 0.037 36.528 0.084 ;
     RECT  36.552 0.037 36.624 0.084 ;
     RECT  36.648 0.037 36.72 0.084 ;
     RECT  36.744 0.037 36.816 0.084 ;
     RECT  36.84 0.037 36.912 0.084 ;
     RECT  36.936 0.037 37.008 0.084 ;
     RECT  37.032 0.037 37.104 0.084 ;
     RECT  37.128 0.037 37.2 0.084 ;
     RECT  37.224 0.037 37.296 0.084 ;
     RECT  37.32 0.037 37.392 0.084 ;
     RECT  37.416 0.037 37.488 0.084 ;
     RECT  37.512 0.037 37.584 0.084 ;
     RECT  37.608 0.037 37.68 0.084 ;
     RECT  37.704 0.037 37.776 0.084 ;
     RECT  37.8 0.037 37.872 0.084 ;
     RECT  37.896 0.037 37.968 0.084 ;
     RECT  37.992 0.037 38.064 0.084 ;
     RECT  38.088 0.037 38.16 0.084 ;
     RECT  38.184 0.037 38.256 0.084 ;
     RECT  38.28 0.037 39.12 0.084 ;
     RECT  39.144 0.037 39.216 0.084 ;
     RECT  39.24 0.037 39.312 0.084 ;
     RECT  39.336 0.037 39.408 0.084 ;
     RECT  39.432 0.037 39.504 0.084 ;
     RECT  39.528 0.037 39.6 0.084 ;
     RECT  39.624 0.037 39.696 0.084 ;
     RECT  39.72 0.037 39.792 0.084 ;
     RECT  39.816 0.037 39.888 0.084 ;
     RECT  39.912 0.037 39.984 0.084 ;
     RECT  40.008 0.037 40.08 0.084 ;
     RECT  40.104 0.037 40.176 0.084 ;
     RECT  40.2 0.037 40.272 0.084 ;
     RECT  40.296 0.037 40.368 0.084 ;
     RECT  40.392 0.037 40.464 0.084 ;
     RECT  40.488 0.037 40.56 0.084 ;
     RECT  40.584 0.037 40.656 0.084 ;
     RECT  40.68 0.037 40.752 0.084 ;
     RECT  40.776 0.037 40.848 0.084 ;
     RECT  40.872 0.037 40.944 0.084 ;
     RECT  40.968 0.037 41.04 0.084 ;
     RECT  41.064 0.037 41.136 0.084 ;
     RECT  41.16 0.037 41.232 0.084 ;
     RECT  41.256 0.037 41.328 0.084 ;
     RECT  41.352 0.037 41.424 0.084 ;
     RECT  41.448 0.037 41.52 0.084 ;
     RECT  41.544 0.037 41.616 0.084 ;
     RECT  41.64 0.037 41.712 0.084 ;
     RECT  41.736 0.037 41.808 0.084 ;
     RECT  41.832 0.037 41.904 0.084 ;
     RECT  41.928 0.037 42 0.084 ;
     RECT  42.024 0.037 42.096 0.084 ;
     RECT  42.12 0.037 42.192 0.084 ;
     RECT  42.216 0.037 42.288 0.084 ;
     RECT  42.312 0.037 42.384 0.084 ;
     RECT  42.408 0.037 42.48 0.084 ;
     RECT  42.504 0.037 42.576 0.084 ;
     RECT  42.6 0.037 42.672 0.084 ;
     RECT  42.696 0.037 42.768 0.084 ;
     RECT  42.792 0.037 42.864 0.084 ;
     RECT  42.888 0.037 42.96 0.084 ;
     RECT  42.984 0.037 43.056 0.084 ;
     RECT  43.08 0.037 43.152 0.084 ;
     RECT  43.176 0.037 43.248 0.084 ;
     RECT  43.272 0.037 43.344 0.084 ;
     RECT  43.368 0.037 43.44 0.084 ;
     RECT  43.464 0.037 43.536 0.084 ;
     RECT  43.56 0.037 43.632 0.084 ;
     RECT  43.656 0.037 43.728 0.084 ;
     RECT  43.752 0.037 43.824 0.084 ;
     RECT  43.848 0.037 43.92 0.084 ;
     RECT  43.944 0.037 44.016 0.084 ;
     RECT  44.04 0.037 44.112 0.084 ;
     RECT  44.136 0.037 44.208 0.084 ;
     RECT  44.232 0.037 44.304 0.084 ;
     RECT  44.328 0.037 44.4 0.084 ;
     RECT  44.424 0.037 44.496 0.084 ;
     RECT  44.52 0.037 44.592 0.084 ;
     RECT  44.616 0.037 44.688 0.084 ;
     RECT  44.712 0.037 44.784 0.084 ;
     RECT  44.808 0.037 44.88 0.084 ;
     RECT  44.904 0.037 44.976 0.084 ;
     RECT  45 0.037 45.072 0.084 ;
     RECT  45.096 0.037 45.168 0.084 ;
     RECT  45.192 0.037 45.264 0.084 ;
     RECT  45.288 0.037 45.36 0.084 ;
     RECT  45.384 0.037 45.456 0.084 ;
     RECT  45.48 0.037 45.552 0.084 ;
     RECT  45.576 0.037 45.648 0.084 ;
     RECT  45.672 0.037 45.744 0.084 ;
     RECT  45.768 0.037 45.84 0.084 ;
     RECT  45.864 0.037 45.936 0.084 ;
     RECT  45.96 0.037 46.032 0.084 ;
     RECT  46.056 0.037 46.128 0.084 ;
     RECT  46.152 0.037 46.224 0.084 ;
     RECT  46.248 0.037 46.32 0.084 ;
     RECT  46.344 0.037 46.416 0.084 ;
     RECT  46.44 0.037 46.512 0.084 ;
     RECT  46.536 0.037 46.608 0.084 ;
     RECT  46.632 0.037 46.704 0.084 ;
     RECT  46.728 0.037 46.8 0.084 ;
     RECT  46.824 0.037 46.896 0.084 ;
     RECT  46.92 0.037 46.992 0.084 ;
     RECT  47.016 0.037 47.088 0.084 ;
     RECT  47.112 0.037 47.184 0.084 ;
     RECT  47.208 0.037 47.28 0.084 ;
     RECT  47.304 0.037 47.376 0.084 ;
     RECT  47.4 0.037 47.472 0.084 ;
     RECT  47.496 0.037 47.568 0.084 ;
     RECT  47.592 0.037 47.664 0.084 ;
     RECT  47.688 0.037 47.76 0.084 ;
     RECT  47.784 0.037 47.856 0.084 ;
     RECT  47.88 0.037 47.952 0.084 ;
     RECT  47.976 0.037 48.048 0.084 ;
     RECT  48.072 0.037 48.144 0.084 ;
     RECT  48.168 0.037 48.24 0.084 ;
     RECT  48.264 0.037 48.336 0.084 ;
     RECT  48.36 0.037 48.432 0.084 ;
     RECT  48.456 0.037 48.528 0.084 ;
     RECT  48.552 0.037 48.624 0.084 ;
     RECT  48.648 0.037 48.72 0.084 ;
     RECT  48.744 0.037 48.816 0.084 ;
     RECT  48.84 0.037 48.912 0.084 ;
     RECT  48.936 0.037 49.008 0.084 ;
     RECT  49.032 0.037 49.104 0.084 ;
     RECT  49.128 0.037 49.2 0.084 ;
     RECT  49.224 0.037 49.296 0.084 ;
     RECT  49.32 0.037 49.392 0.084 ;
     RECT  49.416 0.037 49.488 0.084 ;
     RECT  49.512 0.037 49.584 0.084 ;
     RECT  49.608 0.037 49.68 0.084 ;
     RECT  49.704 0.037 49.776 0.084 ;
     RECT  49.8 0.037 49.872 0.084 ;
     RECT  49.896 0.037 49.968 0.084 ;
     RECT  49.992 0.037 50.064 0.084 ;
     RECT  50.088 0.037 50.16 0.084 ;
     RECT  50.184 0.037 50.256 0.084 ;
     RECT  50.28 0.037 50.352 0.084 ;
     RECT  50.376 0.037 50.448 0.084 ;
     RECT  50.472 0.037 50.544 0.084 ;
     RECT  50.568 0.037 50.64 0.084 ;
     RECT  50.664 0.037 50.736 0.084 ;
     RECT  50.76 0.037 50.832 0.084 ;
     RECT  50.856 0.037 50.928 0.084 ;
     RECT  50.952 0.037 51.024 0.084 ;
     RECT  51.048 0.037 51.12 0.084 ;
     RECT  51.144 0.037 51.216 0.084 ;
     RECT  51.24 0.037 51.312 0.084 ;
     RECT  51.336 0.037 51.408 0.084 ;
     RECT  51.432 0.037 51.504 0.084 ;
     RECT  51.528 0.037 51.6 0.084 ;
     RECT  51.624 0.037 51.696 0.084 ;
     RECT  51.72 0.037 51.792 0.084 ;
     RECT  51.816 0.037 51.888 0.084 ;
     RECT  51.912 0.037 51.984 0.084 ;
     RECT  52.008 0.037 52.08 0.084 ;
     RECT  52.104 0.037 52.176 0.084 ;
     RECT  52.2 0.037 52.272 0.084 ;
     RECT  52.296 0.037 52.368 0.084 ;
     RECT  52.392 0.037 52.464 0.084 ;
     RECT  52.488 0.037 52.56 0.084 ;
     RECT  52.584 0.037 52.656 0.084 ;
     RECT  52.68 0.037 52.752 0.084 ;
     RECT  52.776 0.037 52.848 0.084 ;
     RECT  52.872 0.037 52.944 0.084 ;
     RECT  52.968 0.037 53.04 0.084 ;
     RECT  53.064 0.037 53.136 0.084 ;
     RECT  53.16 0.037 53.232 0.084 ;
     RECT  53.256 0.037 53.328 0.084 ;
     RECT  53.352 0.037 53.424 0.084 ;
     RECT  53.448 0.037 53.52 0.084 ;
     RECT  53.544 0.037 53.616 0.084 ;
     RECT  53.64 0.037 53.712 0.084 ;
     RECT  53.736 0.037 53.808 0.084 ;
     RECT  53.832 0.037 53.904 0.084 ;
     RECT  53.928 0.037 54 0.084 ;
     RECT  54.024 0.037 54.096 0.084 ;
     RECT  54.12 0.037 54.192 0.084 ;
     RECT  54.216 0.037 54.288 0.084 ;
     RECT  54.312 0.037 54.384 0.084 ;
     RECT  54.408 0.037 54.48 0.084 ;
     RECT  54.504 0.037 54.576 0.084 ;
     RECT  54.6 0.037 54.672 0.084 ;
     RECT  54.696 0.037 54.768 0.084 ;
     RECT  54.792 0.037 54.864 0.084 ;
     RECT  54.888 0.037 54.96 0.084 ;
     RECT  54.984 0.037 55.056 0.084 ;
     RECT  55.08 0.037 55.152 0.084 ;
     RECT  55.176 0.037 55.248 0.084 ;
     RECT  55.272 0.037 55.344 0.084 ;
     RECT  55.368 0.037 55.44 0.084 ;
     RECT  55.464 0.037 55.536 0.084 ;
     RECT  55.56 0.037 55.632 0.084 ;
     RECT  55.656 0.037 55.728 0.084 ;
     RECT  55.752 0.037 55.824 0.084 ;
     RECT  55.848 0.037 55.92 0.084 ;
     RECT  55.944 0.037 56.016 0.084 ;
     RECT  56.04 0.037 56.112 0.084 ;
     RECT  56.136 0.037 56.208 0.084 ;
     RECT  56.232 0.037 56.304 0.084 ;
     RECT  56.328 0.037 56.4 0.084 ;
     RECT  56.424 0.037 56.496 0.084 ;
     RECT  56.52 0.037 56.592 0.084 ;
     RECT  56.616 0.037 56.688 0.084 ;
     RECT  56.712 0.037 56.784 0.084 ;
     RECT  56.808 0.037 56.88 0.084 ;
     RECT  56.904 0.037 56.976 0.084 ;
     RECT  57 0.037 57.072 0.084 ;
     RECT  57.096 0.037 57.168 0.084 ;
     RECT  57.192 0.037 57.264 0.084 ;
     RECT  57.288 0.037 57.36 0.084 ;
     RECT  57.384 0.037 57.456 0.084 ;
     RECT  57.48 0.037 58.32 0.084 ;
     RECT  58.344 0.037 58.416 0.084 ;
     RECT  58.44 0.037 58.512 0.084 ;
     RECT  58.536 0.037 58.608 0.084 ;
     RECT  58.632 0.037 58.704 0.084 ;
     RECT  58.728 0.037 58.8 0.084 ;
     RECT  58.824 0.037 58.896 0.084 ;
     RECT  58.92 0.037 58.992 0.084 ;
     RECT  59.016 0.037 59.088 0.084 ;
     RECT  59.112 0.037 59.184 0.084 ;
     RECT  59.208 0.037 59.28 0.084 ;
     RECT  59.304 0.037 59.376 0.084 ;
     RECT  59.4 0.037 59.472 0.084 ;
     RECT  59.496 0.037 59.568 0.084 ;
     RECT  59.592 0.037 59.664 0.084 ;
     RECT  59.688 0.037 59.76 0.084 ;
     RECT  59.784 0.037 59.856 0.084 ;
     RECT  59.88 0.037 59.952 0.084 ;
     RECT  59.976 0.037 60.048 0.084 ;
     RECT  60.072 0.037 60.144 0.084 ;
     RECT  60.168 0.037 60.24 0.084 ;
     RECT  60.264 0.037 60.336 0.084 ;
     RECT  60.36 0.037 60.432 0.084 ;
     RECT  60.456 0.037 60.528 0.084 ;
     RECT  60.552 0.037 60.624 0.084 ;
     RECT  60.648 0.037 60.72 0.084 ;
     RECT  60.744 0.037 60.816 0.084 ;
     RECT  60.84 0.037 60.912 0.084 ;
     RECT  60.936 0.037 61.008 0.084 ;
     RECT  61.032 0.037 61.104 0.084 ;
     RECT  61.128 0.037 61.2 0.084 ;
     RECT  61.224 0.037 61.296 0.084 ;
     RECT  61.32 0.037 61.392 0.084 ;
     RECT  61.416 0.037 61.488 0.084 ;
     RECT  61.512 0.037 61.584 0.084 ;
     RECT  61.608 0.037 61.68 0.084 ;
     RECT  61.704 0.037 61.776 0.084 ;
     RECT  61.8 0.037 61.872 0.084 ;
     RECT  61.896 0.037 61.968 0.084 ;
     RECT  61.992 0.037 62.064 0.084 ;
     RECT  62.088 0.037 62.16 0.084 ;
     RECT  62.184 0.037 62.256 0.084 ;
     RECT  62.28 0.037 62.352 0.084 ;
     RECT  62.376 0.037 62.448 0.084 ;
     RECT  62.472 0.037 62.544 0.084 ;
     RECT  62.568 0.037 62.64 0.084 ;
     RECT  62.664 0.037 62.736 0.084 ;
     RECT  62.76 0.037 62.832 0.084 ;
     RECT  62.856 0.037 62.928 0.084 ;
     RECT  62.952 0.037 63.024 0.084 ;
     RECT  63.048 0.037 63.12 0.084 ;
     RECT  63.144 0.037 63.216 0.084 ;
     RECT  63.24 0.037 63.312 0.084 ;
     RECT  63.336 0.037 63.408 0.084 ;
     RECT  63.432 0.037 63.504 0.084 ;
     RECT  63.528 0.037 63.6 0.084 ;
     RECT  63.624 0.037 63.696 0.084 ;
     RECT  63.72 0.037 63.792 0.084 ;
     RECT  63.816 0.037 63.888 0.084 ;
     RECT  63.912 0.037 63.984 0.084 ;
     RECT  64.008 0.037 64.08 0.084 ;
     RECT  64.104 0.037 64.176 0.084 ;
     RECT  64.2 0.037 64.272 0.084 ;
     RECT  64.296 0.037 64.368 0.084 ;
     RECT  64.392 0.037 64.464 0.084 ;
     RECT  64.488 0.037 64.56 0.084 ;
     RECT  64.584 0.037 64.656 0.084 ;
     RECT  64.68 0.037 64.752 0.084 ;
     RECT  64.776 0.037 64.848 0.084 ;
     RECT  64.872 0.037 64.944 0.084 ;
     RECT  64.968 0.037 65.04 0.084 ;
     RECT  65.064 0.037 65.136 0.084 ;
     RECT  65.16 0.037 65.232 0.084 ;
     RECT  65.256 0.037 65.328 0.084 ;
     RECT  65.352 0.037 65.424 0.084 ;
     RECT  65.448 0.037 65.52 0.084 ;
     RECT  65.544 0.037 65.616 0.084 ;
     RECT  65.64 0.037 65.712 0.084 ;
     RECT  65.736 0.037 65.808 0.084 ;
     RECT  65.832 0.037 65.904 0.084 ;
     RECT  65.928 0.037 66 0.084 ;
     RECT  66.024 0.037 66.096 0.084 ;
     RECT  66.12 0.037 66.192 0.084 ;
     RECT  66.216 0.037 66.288 0.084 ;
     RECT  66.312 0.037 66.384 0.084 ;
     RECT  66.408 0.037 66.48 0.084 ;
     RECT  66.504 0.037 66.576 0.084 ;
     RECT  66.6 0.037 66.672 0.084 ;
     RECT  66.696 0.037 66.768 0.084 ;
     RECT  66.792 0.037 66.864 0.084 ;
     RECT  66.888 0.037 66.96 0.084 ;
     RECT  66.984 0.037 67.056 0.084 ;
     RECT  67.08 0.037 67.152 0.084 ;
     RECT  67.176 0.037 67.248 0.084 ;
     RECT  67.272 0.037 67.344 0.084 ;
     RECT  67.368 0.037 67.44 0.084 ;
     RECT  67.464 0.037 67.536 0.084 ;
     RECT  67.56 0.037 67.632 0.084 ;
     RECT  67.656 0.037 67.728 0.084 ;
     RECT  67.752 0.037 67.824 0.084 ;
     RECT  67.848 0.037 67.92 0.084 ;
     RECT  67.944 0.037 68.016 0.084 ;
     RECT  68.04 0.037 68.112 0.084 ;
     RECT  68.136 0.037 68.208 0.084 ;
     RECT  68.232 0.037 68.304 0.084 ;
     RECT  68.328 0.037 68.4 0.084 ;
     RECT  68.424 0.037 68.496 0.084 ;
     RECT  68.52 0.037 68.592 0.084 ;
     RECT  68.616 0.037 68.688 0.084 ;
     RECT  68.712 0.037 68.784 0.084 ;
     RECT  68.808 0.037 68.88 0.084 ;
     RECT  68.904 0.037 68.976 0.084 ;
     RECT  69 0.037 69.072 0.084 ;
     RECT  69.096 0.037 69.168 0.084 ;
     RECT  69.192 0.037 69.264 0.084 ;
     RECT  69.288 0.037 69.36 0.084 ;
     RECT  69.384 0.037 69.456 0.084 ;
     RECT  69.48 0.037 69.552 0.084 ;
     RECT  69.576 0.037 69.648 0.084 ;
     RECT  69.672 0.037 69.744 0.084 ;
     RECT  69.768 0.037 69.84 0.084 ;
     RECT  69.864 0.037 69.936 0.084 ;
     RECT  69.96 0.037 70.032 0.084 ;
     RECT  70.056 0.037 70.128 0.084 ;
     RECT  70.152 0.037 70.224 0.084 ;
     RECT  70.248 0.037 70.32 0.084 ;
     RECT  70.344 0.037 70.416 0.084 ;
     RECT  70.44 0.037 70.512 0.084 ;
     RECT  70.536 0.037 70.608 0.084 ;
     RECT  70.632 0.037 70.704 0.084 ;
     RECT  70.728 0.037 70.8 0.084 ;
     RECT  70.824 0.037 70.896 0.084 ;
     RECT  70.92 0.037 70.992 0.084 ;
     RECT  71.016 0.037 71.088 0.084 ;
     RECT  71.112 0.037 71.184 0.084 ;
     RECT  71.208 0.037 71.28 0.084 ;
     RECT  71.304 0.037 71.376 0.084 ;
     RECT  71.4 0.037 71.472 0.084 ;
     RECT  71.496 0.037 71.568 0.084 ;
     RECT  71.592 0.037 71.664 0.084 ;
     RECT  71.688 0.037 71.76 0.084 ;
     RECT  71.784 0.037 71.856 0.084 ;
     RECT  71.88 0.037 71.952 0.084 ;
     RECT  71.976 0.037 72.048 0.084 ;
     RECT  72.072 0.037 72.144 0.084 ;
     RECT  72.168 0.037 72.24 0.084 ;
     RECT  72.264 0.037 72.336 0.084 ;
     RECT  72.36 0.037 72.432 0.084 ;
     RECT  72.456 0.037 72.528 0.084 ;
     RECT  72.552 0.037 72.624 0.084 ;
     RECT  72.648 0.037 72.72 0.084 ;
     RECT  72.744 0.037 72.816 0.084 ;
     RECT  72.84 0.037 72.912 0.084 ;
     RECT  72.936 0.037 73.008 0.084 ;
     RECT  73.032 0.037 73.104 0.084 ;
     RECT  73.128 0.037 73.2 0.084 ;
     RECT  73.224 0.037 73.296 0.084 ;
     RECT  73.32 0.037 73.392 0.084 ;
     RECT  73.416 0.037 73.488 0.084 ;
     RECT  73.512 0.037 73.584 0.084 ;
     RECT  73.608 0.037 73.68 0.084 ;
     RECT  73.704 0.037 73.776 0.084 ;
     RECT  73.8 0.037 73.872 0.084 ;
     RECT  73.896 0.037 73.968 0.084 ;
     RECT  73.992 0.037 74.064 0.084 ;
     RECT  74.088 0.037 74.16 0.084 ;
     RECT  74.184 0.037 74.256 0.084 ;
     RECT  74.28 0.037 74.352 0.084 ;
     RECT  74.376 0.037 74.448 0.084 ;
     RECT  74.472 0.037 74.544 0.084 ;
     RECT  74.568 0.037 74.64 0.084 ;
     RECT  74.664 0.037 74.736 0.084 ;
     RECT  74.76 0.037 74.832 0.084 ;
     RECT  74.856 0.037 74.928 0.084 ;
     RECT  74.952 0.037 75.024 0.084 ;
     RECT  75.048 0.037 75.12 0.084 ;
     RECT  75.144 0.037 75.216 0.084 ;
     RECT  75.24 0.037 75.312 0.084 ;
     RECT  75.336 0.037 75.408 0.084 ;
     RECT  75.432 0.037 75.504 0.084 ;
     RECT  75.528 0.037 75.6 0.084 ;
     RECT  75.624 0.037 75.696 0.084 ;
     RECT  75.72 0.037 75.792 0.084 ;
     RECT  75.816 0.037 75.888 0.084 ;
     RECT  75.912 0.037 75.984 0.084 ;
     RECT  76.008 0.037 76.08 0.084 ;
     RECT  76.104 0.037 76.176 0.084 ;
     RECT  76.2 0.037 76.272 0.084 ;
     RECT  76.296 0.037 76.368 0.084 ;
     RECT  76.392 0.037 76.464 0.084 ;
     RECT  76.488 0.037 76.56 0.084 ;
     RECT  76.584 0.037 76.656 0.084 ;
     RECT  76.68 0.037 77.52 0.084 ;
     RECT  77.544 0.037 77.616 0.084 ;
     RECT  77.64 0.037 77.712 0.084 ;
     RECT  77.736 0.037 77.832 0.084 ;
     RECT  26.064 0.084 77.832 0.179 ;
     RECT  26.064 0.179 77.64 1.763 ;
     RECT  80.616 0.016 80.688 0.084 ;
     RECT  80.712 0.016 80.784 0.084 ;
     RECT  80.808 0.016 80.88 0.084 ;
     RECT  80.904 0.016 80.976 0.084 ;
     RECT  81 0.016 81.072 0.084 ;
     RECT  81.096 0.016 81.168 0.084 ;
     RECT  81.192 0.016 81.264 0.084 ;
     RECT  81.288 0.016 81.36 0.084 ;
     RECT  81.384 0.016 81.456 0.084 ;
     RECT  81.48 0.016 81.552 0.084 ;
     RECT  81.576 0.016 81.648 0.084 ;
     RECT  81.672 0.016 81.744 0.084 ;
     RECT  81.768 0.016 81.84 0.084 ;
     RECT  81.864 0.016 81.936 0.084 ;
     RECT  81.96 0.016 82.032 0.084 ;
     RECT  82.056 0.016 82.128 0.084 ;
     RECT  82.152 0.016 82.224 0.084 ;
     RECT  82.248 0.016 82.32 0.084 ;
     RECT  82.344 0.016 82.416 0.084 ;
     RECT  82.44 0.016 82.512 0.084 ;
     RECT  82.536 0.016 82.608 0.084 ;
     RECT  82.632 0.016 82.704 0.084 ;
     RECT  82.728 0.016 82.8 0.084 ;
     RECT  82.824 0.016 82.896 0.084 ;
     RECT  82.92 0.016 82.992 0.084 ;
     RECT  83.016 0.016 83.088 0.084 ;
     RECT  83.112 0.016 83.184 0.084 ;
     RECT  83.208 0.016 83.28 0.084 ;
     RECT  83.304 0.016 83.376 0.084 ;
     RECT  83.4 0.016 83.472 0.084 ;
     RECT  83.496 0.016 83.568 0.084 ;
     RECT  80.592 0.084 83.592 1.763 ;
     RECT  26.544 1.763 31.56 1.811 ;
     RECT  32.688 1.763 35.112 1.811 ;
     RECT  36.912 1.763 41.256 1.811 ;
     RECT  43.344 1.763 43.368 1.811 ;
     RECT  44.88 1.763 49.416 1.811 ;
     RECT  54.48 1.763 55.176 1.811 ;
     RECT  56.4 1.763 57.48 1.811 ;
     RECT  65.424 1.763 68.616 1.811 ;
     RECT  69.84 1.763 76.68 1.811 ;
     RECT  80.688 1.763 81 1.811 ;
     RECT  82.032 1.763 83.592 1.811 ;
     RECT  34.224 1.811 35.112 1.859 ;
     RECT  37.584 1.811 39.144 1.859 ;
     RECT  45.312 1.811 48.264 1.907 ;
     RECT  45.312 1.907 48.072 1.955 ;
     RECT  47.76 1.955 48.072 2.003 ;
     RECT  2.4 2.137 2.52 2.151 ;
     RECT  7.8 2.137 7.92 2.151 ;
     RECT  13.2 2.137 13.32 2.151 ;
     RECT  18.6 2.137 18.72 2.151 ;
     RECT  24 2.137 24.12 2.151 ;
     RECT  78 2.137 78.12 2.151 ;
     RECT  83.4 1.811 83.592 2.151 ;
     RECT  88.8 2.137 88.92 2.151 ;
     RECT  45.312 1.955 46.728 2.243 ;
     RECT  37.584 1.859 37.608 2.291 ;
     RECT  47.856 2.003 48.072 2.291 ;
     RECT  45.312 2.243 46.584 2.773 ;
     RECT  39.12 1.859 39.144 2.915 ;
     RECT  61.8 1.763 62.112 3.397 ;
     RECT  44.64 2.773 46.584 3.443 ;
     RECT  36.432 3.301 36.456 4.019 ;
     RECT  61.8 3.397 62.232 4.501 ;
     RECT  56.4 1.811 56.712 5.029 ;
     RECT  47.856 2.291 47.88 5.171 ;
     RECT  34.8 1.859 35.112 5.365 ;
     RECT  67.2 1.811 67.512 5.509 ;
     RECT  61.8 4.501 62.808 5.557 ;
     RECT  44.64 3.443 45.912 5.605 ;
     RECT  71.232 5.029 71.256 5.747 ;
     RECT  51 1.763 51.312 5.845 ;
     RECT  61.8 5.557 62.952 6.085 ;
     RECT  61.68 6.085 62.952 6.131 ;
     RECT  55.536 5.029 56.712 6.277 ;
     RECT  70.992 6.229 71.016 6.709 ;
     RECT  54.48 6.949 54.504 7.189 ;
     RECT  55.536 6.277 57.288 7.189 ;
     RECT  67.2 5.509 67.608 7.189 ;
     RECT  67.2 7.189 68.472 7.477 ;
     RECT  44.64 5.605 46.776 7.573 ;
     RECT  44.64 7.573 47.016 7.619 ;
     RECT  67.104 7.477 68.472 7.667 ;
     RECT  44.64 7.619 45.912 7.763 ;
     RECT  61.68 6.131 62.808 7.765 ;
     RECT  50.832 5.845 51.312 7.907 ;
     RECT  46.992 7.619 47.016 7.909 ;
     RECT  48.192 7.861 48.216 7.909 ;
     RECT  54.48 7.189 57.288 7.957 ;
     RECT  66 8.005 66.024 8.963 ;
     RECT  51 7.907 51.312 9.013 ;
     RECT  54.288 7.957 57.288 9.061 ;
     RECT  34.8 5.365 36.024 9.107 ;
     RECT  54.24 9.061 57.288 9.347 ;
     RECT  59.232 8.485 59.256 9.397 ;
     RECT  60.24 9.205 60.264 9.397 ;
     RECT  65.712 8.965 65.736 9.541 ;
     RECT  63.84 8.197 63.864 9.587 ;
     RECT  46.992 7.909 48.216 9.731 ;
     RECT  48.192 9.731 48.216 9.779 ;
     RECT  59.232 9.397 60.264 9.779 ;
     RECT  45.312 7.763 45.912 9.781 ;
     RECT  46.992 9.731 47.016 9.781 ;
     RECT  45.312 9.781 47.016 9.827 ;
     RECT  7.8 2.151 8.112 9.925 ;
     RECT  70.896 6.709 71.016 10.165 ;
     RECT  54.288 9.347 57.288 10.213 ;
     RECT  52.704 1.763 52.728 10.261 ;
     RECT  61.584 7.765 62.808 10.453 ;
     RECT  7.68 9.925 8.112 10.501 ;
     RECT  61.584 10.453 63.672 10.693 ;
     RECT  50.112 9.013 51.312 10.789 ;
     RECT  54.288 10.213 57.672 10.883 ;
     RECT  52.704 10.261 53.064 10.979 ;
     RECT  3.936 10.597 3.96 11.027 ;
     RECT  54.288 10.883 55.176 11.029 ;
     RECT  61.008 10.693 63.672 11.171 ;
     RECT  70.896 10.165 71.4 11.221 ;
     RECT  72.6 1.811 72.912 11.221 ;
     RECT  64.992 9.541 65.736 11.317 ;
     RECT  7.68 10.501 8.616 11.411 ;
     RECT  9.6 9.781 9.624 11.459 ;
     RECT  61.536 11.171 63.672 11.461 ;
     RECT  64.992 11.317 65.928 11.461 ;
     RECT  49.392 10.789 51.312 11.701 ;
     RECT  59.232 9.779 59.784 11.701 ;
     RECT  11.376 9.397 11.4 11.747 ;
     RECT  61.536 11.461 65.928 11.749 ;
     RECT  67.2 7.667 68.472 11.749 ;
     RECT  69.504 6.229 69.528 11.941 ;
     RECT  70.656 11.221 72.912 11.941 ;
     RECT  7.68 11.411 8.112 11.987 ;
     RECT  34.8 9.107 35.928 12.469 ;
     RECT  34.8 12.469 36.168 12.515 ;
     RECT  61.536 11.749 68.472 12.517 ;
     RECT  52.704 10.979 52.728 12.565 ;
     RECT  53.904 11.029 55.176 12.565 ;
     RECT  56.4 10.883 57.672 12.613 ;
     RECT  59.232 11.701 60.216 12.613 ;
     RECT  56.4 12.613 60.216 12.805 ;
     RECT  61.344 12.517 68.472 12.805 ;
     RECT  52.704 12.565 55.176 12.851 ;
     RECT  14.784 12.517 14.808 13.043 ;
     RECT  13.2 2.151 13.512 13.045 ;
     RECT  45.6 9.827 47.016 13.045 ;
     RECT  69.504 11.941 72.912 13.093 ;
     RECT  45.6 13.045 47.928 13.141 ;
     RECT  49.2 11.701 51.312 13.621 ;
     RECT  44.976 13.141 47.928 13.811 ;
     RECT  49.104 13.621 51.312 13.909 ;
     RECT  52.704 12.851 52.728 14.149 ;
     RECT  53.904 12.851 55.176 14.149 ;
     RECT  69.504 13.093 73.176 14.197 ;
     RECT  13.2 13.045 13.608 14.339 ;
     RECT  52.704 14.149 55.176 14.533 ;
     RECT  56.4 12.805 68.472 14.533 ;
     RECT  25.68 12.373 25.704 14.627 ;
     RECT  52.704 14.533 68.472 14.675 ;
     RECT  44.976 13.811 46.488 14.771 ;
     RECT  47.856 13.811 47.928 14.773 ;
     RECT  45.6 14.771 46.488 14.869 ;
     RECT  56.304 14.675 68.472 15.157 ;
     RECT  69.504 14.197 73.416 15.157 ;
     RECT  56.304 15.157 73.416 15.203 ;
     RECT  49.104 13.909 51.528 15.251 ;
     RECT  45.6 14.869 46.728 15.253 ;
     RECT  47.856 14.773 47.976 15.253 ;
     RECT  52.704 14.675 55.176 15.539 ;
     RECT  56.304 15.203 67.896 15.685 ;
     RECT  45.6 15.253 47.976 15.925 ;
     RECT  49.104 15.251 51.48 15.925 ;
     RECT  25.728 14.773 25.752 16.019 ;
     RECT  45.6 15.925 51.48 16.019 ;
     RECT  68.928 15.203 73.416 16.019 ;
     RECT  56.256 15.685 67.896 16.211 ;
     RECT  56.256 16.211 67.8 16.451 ;
     RECT  53.856 15.539 55.176 16.693 ;
     RECT  56.256 16.451 67.752 16.693 ;
     RECT  40.2 1.811 40.512 17.077 ;
     RECT  52.704 15.539 52.728 17.077 ;
     RECT  36.144 12.515 36.168 17.123 ;
     RECT  52.656 17.077 52.824 17.363 ;
     RECT  53.856 16.693 67.752 17.605 ;
     RECT  69.024 16.019 73.416 17.605 ;
     RECT  13.2 14.339 13.512 17.845 ;
     RECT  75.456 13.045 75.48 17.893 ;
     RECT  75.264 17.893 75.48 17.939 ;
     RECT  45.6 16.019 45.912 18.133 ;
     RECT  47.376 16.019 51.48 18.133 ;
     RECT  21.648 15.301 21.672 18.179 ;
     RECT  44.448 17.077 44.472 18.179 ;
     RECT  52.704 17.363 52.824 18.373 ;
     RECT  53.856 17.605 73.416 18.373 ;
     RECT  13.2 17.845 13.656 18.563 ;
     RECT  37.728 17.605 37.752 18.613 ;
     RECT  37.008 18.613 37.752 18.659 ;
     RECT  75.264 17.939 75.288 18.851 ;
     RECT  52.704 18.373 73.416 19.331 ;
     RECT  68.736 19.331 73.416 19.381 ;
     RECT  37.008 18.659 37.032 19.667 ;
     RECT  45.6 18.133 51.528 19.861 ;
     RECT  68.736 19.381 73.464 19.861 ;
     RECT  45.504 19.861 51.528 19.909 ;
     RECT  17.472 19.093 17.496 20.003 ;
     RECT  43.296 18.661 43.32 20.003 ;
     RECT  52.704 19.331 67.704 20.003 ;
     RECT  40.2 17.077 40.968 20.051 ;
     RECT  45.504 19.909 51.576 20.099 ;
     RECT  9.648 11.845 9.672 20.147 ;
     RECT  32.688 8.821 32.712 20.339 ;
     RECT  7.8 11.987 8.112 20.389 ;
     RECT  45.504 20.099 45.912 20.869 ;
     RECT  45.264 20.869 45.912 21.107 ;
     RECT  52.704 20.003 67.608 21.109 ;
     RECT  21.696 18.757 21.768 21.157 ;
     RECT  21.696 21.157 21.912 21.203 ;
     RECT  68.736 19.861 73.512 21.251 ;
     RECT  21.744 21.203 21.912 21.299 ;
     RECT  47.28 20.099 51.576 21.395 ;
     RECT  52.704 21.109 67.704 21.541 ;
     RECT  68.736 21.251 73.464 21.541 ;
     RECT  24 2.151 24.312 21.637 ;
     RECT  42.768 20.821 42.792 21.683 ;
     RECT  45.456 21.107 45.912 21.971 ;
     RECT  47.28 21.395 51.312 22.259 ;
     RECT  52.704 21.541 73.464 22.259 ;
     RECT  52.704 22.259 57.528 22.307 ;
     RECT  34.8 12.515 35.112 22.453 ;
     RECT  45.504 21.971 45.912 22.499 ;
     RECT  23.904 21.637 24.312 22.595 ;
     RECT  28.224 21.253 28.248 22.739 ;
     RECT  24 22.595 24.312 22.741 ;
     RECT  7.68 20.389 8.112 22.837 ;
     RECT  47.376 22.259 51.312 23.269 ;
     RECT  7.632 22.837 8.112 23.363 ;
     RECT  75.504 22.693 75.528 23.411 ;
     RECT  58.608 22.259 73.464 23.507 ;
     RECT  52.704 22.307 57.48 23.509 ;
     RECT  7.68 23.363 8.112 23.555 ;
     RECT  0.192 11.077 0.216 23.651 ;
     RECT  47.376 23.269 51.432 23.747 ;
     RECT  24 22.741 24.552 23.845 ;
     RECT  16.56 20.821 16.584 23.939 ;
     RECT  16.608 23.941 16.968 24.085 ;
     RECT  58.608 23.507 65.256 24.227 ;
     RECT  31.248 20.293 31.272 24.229 ;
     RECT  45.6 22.499 45.912 24.469 ;
     RECT  52.704 23.509 57.528 24.469 ;
     RECT  66.576 23.507 73.464 24.469 ;
     RECT  21.888 21.299 21.912 24.517 ;
     RECT  30.816 24.229 31.272 24.563 ;
     RECT  58.608 24.227 63.192 24.611 ;
     RECT  34.8 22.453 35.208 24.659 ;
     RECT  64.176 24.227 65.256 24.755 ;
     RECT  58.656 24.611 63.192 24.947 ;
     RECT  16.608 24.085 17.16 24.995 ;
     RECT  16.608 24.995 16.632 24.997 ;
     RECT  30.816 24.563 30.84 25.139 ;
     RECT  47.376 23.747 51.312 25.139 ;
     RECT  64.176 24.755 65.064 25.283 ;
     RECT  45.6 24.469 46.152 25.331 ;
     RECT  16.176 24.997 16.632 25.715 ;
     RECT  58.656 24.947 63.144 25.715 ;
     RECT  64.176 25.283 65.016 25.715 ;
     RECT  66.576 24.469 73.704 25.765 ;
     RECT  48.192 25.139 51.312 25.907 ;
     RECT  21.552 24.517 21.912 26.003 ;
     RECT  33.552 25.237 33.576 26.003 ;
     RECT  66.192 25.765 73.704 26.197 ;
     RECT  58.752 25.715 63.144 26.389 ;
     RECT  64.176 25.715 64.776 26.389 ;
     RECT  66.144 26.197 73.704 26.437 ;
     RECT  66.144 26.437 74.04 26.629 ;
     RECT  18.6 2.151 18.912 26.677 ;
     RECT  20.4 23.845 20.424 26.771 ;
     RECT  58.752 26.389 64.776 26.917 ;
     RECT  16.608 25.715 16.632 26.963 ;
     RECT  48.768 25.907 51.312 26.965 ;
     RECT  31.344 25.621 31.368 27.107 ;
     RECT  66.144 26.629 74.76 27.251 ;
     RECT  34.8 24.659 35.112 27.301 ;
     RECT  48.768 26.965 51.672 27.301 ;
     RECT  52.704 24.469 57.624 27.301 ;
     RECT  18.6 26.677 19.368 27.395 ;
     RECT  48.768 27.301 57.624 27.395 ;
     RECT  66.144 27.251 73.704 27.395 ;
     RECT  34.8 27.301 35.208 27.685 ;
     RECT  58.752 26.917 65.064 27.779 ;
     RECT  58.752 27.779 64.968 27.875 ;
     RECT  18.6 27.395 18.912 27.877 ;
     RECT  21.888 26.003 21.912 27.877 ;
     RECT  66.144 27.395 68.664 27.971 ;
     RECT  38.784 26.485 38.808 28.163 ;
     RECT  13.2 18.563 13.512 28.213 ;
     RECT  50.352 27.395 57.624 28.259 ;
     RECT  13.2 28.213 13.608 28.309 ;
     RECT  69.984 27.395 73.704 28.355 ;
     RECT  34.512 27.685 35.208 28.499 ;
     RECT  50.352 28.259 52.008 28.499 ;
     RECT  58.8 27.875 64.968 28.499 ;
     RECT  18.48 27.877 18.912 28.547 ;
     RECT  70.032 28.355 73.704 28.547 ;
     RECT  74.736 27.251 74.76 28.547 ;
     RECT  18.6 28.547 18.912 28.549 ;
     RECT  9.696 28.453 9.72 28.643 ;
     RECT  21.888 27.877 22.104 28.645 ;
     RECT  34.8 28.499 35.208 28.645 ;
     RECT  21.648 28.645 22.104 28.691 ;
     RECT  43.392 24.613 43.416 28.835 ;
     RECT  13.056 28.309 13.608 28.931 ;
     RECT  71.472 28.547 73.704 28.931 ;
     RECT  53.04 28.259 57.624 29.027 ;
     RECT  48.768 27.395 49.368 29.029 ;
     RECT  70.032 28.547 70.296 29.075 ;
     RECT  34.8 28.645 35.736 29.171 ;
     RECT  53.52 29.027 57.624 29.173 ;
     RECT  16.08 28.453 16.104 29.507 ;
     RECT  53.52 29.173 57.72 29.603 ;
     RECT  37.584 28.501 37.608 29.605 ;
     RECT  18.6 28.549 19.32 29.651 ;
     RECT  37.392 29.605 37.608 29.651 ;
     RECT  53.52 29.603 57.576 29.699 ;
     RECT  66.288 27.971 68.664 29.941 ;
     RECT  21.648 28.691 21.672 29.987 ;
     RECT  42.72 29.029 42.744 29.987 ;
     RECT  13.056 28.931 13.512 30.131 ;
     RECT  66.288 29.941 68.712 30.131 ;
     RECT  33.072 28.885 33.096 30.227 ;
     RECT  48.24 29.029 49.368 30.275 ;
     RECT  70.128 29.075 70.296 30.275 ;
     RECT  50.496 28.499 52.008 30.323 ;
     RECT  50.544 30.323 52.008 30.419 ;
     RECT  2.4 2.151 2.712 30.709 ;
     RECT  27.36 28.309 27.384 30.709 ;
     RECT  40.2 20.051 40.512 30.757 ;
     RECT  14.784 30.181 14.808 30.803 ;
     RECT  71.472 28.931 73.656 30.899 ;
     RECT  2.4 30.709 3.624 30.995 ;
     RECT  37.392 29.651 37.416 30.997 ;
     RECT  10.32 30.181 10.344 31.091 ;
     RECT  12 30.949 12.024 31.091 ;
     RECT  27.36 30.709 28.248 31.091 ;
     RECT  34.8 29.171 35.688 31.093 ;
     RECT  33.888 31.093 35.688 31.139 ;
     RECT  22.8 29.941 22.824 31.235 ;
     RECT  13.2 30.131 13.512 31.285 ;
     RECT  37.344 30.997 37.416 31.285 ;
     RECT  66.384 30.131 68.712 31.285 ;
     RECT  28.224 31.091 28.248 31.379 ;
     RECT  43.104 30.757 43.128 31.379 ;
     RECT  29.4 1.811 29.712 31.669 ;
     RECT  58.8 28.499 64.92 31.811 ;
     RECT  45.6 25.331 45.912 31.813 ;
     RECT  24 23.845 25.08 31.861 ;
     RECT  58.848 31.811 64.92 31.907 ;
     RECT  71.472 30.899 73.608 31.909 ;
     RECT  37.344 31.285 38.184 32.099 ;
     RECT  71.472 31.909 74.04 32.195 ;
     RECT  48.768 30.275 49.368 32.291 ;
     RECT  2.4 30.995 3.432 32.531 ;
     RECT  39.84 30.757 40.512 32.531 ;
     RECT  70.272 30.275 70.296 32.531 ;
     RECT  71.472 32.195 71.592 32.531 ;
     RECT  59.568 31.907 64.92 32.675 ;
     RECT  72.6 32.195 74.04 32.723 ;
     RECT  48.816 32.291 49.368 32.773 ;
     RECT  45.6 31.813 46.536 32.819 ;
     RECT  50.544 30.419 51.312 32.867 ;
     RECT  66.384 31.285 68.952 32.965 ;
     RECT  48.816 32.773 49.56 33.011 ;
     RECT  7.8 23.555 8.112 33.013 ;
     RECT  18.6 29.651 19.176 33.107 ;
     RECT  53.52 29.699 53.736 33.107 ;
     RECT  66.336 32.965 68.952 33.299 ;
     RECT  29.4 31.669 30.216 33.539 ;
     RECT  40.2 32.531 40.512 33.541 ;
     RECT  50.832 32.867 51.312 33.587 ;
     RECT  66.336 33.299 68.232 33.587 ;
     RECT  42.672 33.013 42.696 33.635 ;
     RECT  7.8 33.013 8.712 33.683 ;
     RECT  33.888 31.139 35.304 33.683 ;
     RECT  48.912 33.011 49.56 33.683 ;
     RECT  54.768 29.699 57.576 33.683 ;
     RECT  5.808 32.437 5.832 33.827 ;
     RECT  4.416 32.485 4.44 34.259 ;
     RECT  39.888 33.541 40.512 34.259 ;
     RECT  54.768 33.683 56.712 34.259 ;
     RECT  59.568 32.675 62.28 34.259 ;
     RECT  72.6 32.723 73.416 34.259 ;
     RECT  38.16 32.099 38.184 34.307 ;
     RECT  64.176 32.675 64.92 34.499 ;
     RECT  67.104 33.587 68.232 34.595 ;
     RECT  71.568 32.531 71.592 34.693 ;
     RECT  67.104 34.595 67.656 34.787 ;
     RECT  29.4 33.539 29.712 34.789 ;
     RECT  70.128 33.109 70.152 34.835 ;
     RECT  71.472 34.693 71.592 35.125 ;
     RECT  72.6 34.259 72.912 35.125 ;
     RECT  59.568 34.259 60.792 35.219 ;
     RECT  29.232 34.789 29.712 35.315 ;
     RECT  61.8 34.259 62.28 35.315 ;
     RECT  53.712 33.107 53.736 35.363 ;
     RECT  55.152 34.259 56.712 35.363 ;
     RECT  71.472 35.125 72.912 35.363 ;
     RECT  45.6 32.819 45.912 35.509 ;
     RECT  7.8 33.683 8.112 35.845 ;
     RECT  51 33.587 51.312 35.845 ;
     RECT  48.912 33.683 49.368 35.891 ;
     RECT  47.568 31.861 47.592 35.939 ;
     RECT  65.712 35.317 65.736 35.987 ;
     RECT  67.2 34.787 67.656 36.035 ;
     RECT  17.28 35.317 17.304 36.275 ;
     RECT  30.864 35.509 30.888 36.515 ;
     RECT  55.44 35.363 56.712 36.515 ;
     RECT  59.568 35.219 59.832 36.515 ;
     RECT  11.328 35.845 11.352 36.949 ;
     RECT  36.96 35.461 36.984 36.995 ;
     RECT  29.4 35.315 29.712 36.997 ;
     RECT  56.4 36.515 56.712 36.997 ;
     RECT  24 31.861 26.04 37.091 ;
     RECT  61.8 35.315 62.112 37.141 ;
     RECT  61.536 37.141 62.112 37.475 ;
     RECT  7.8 35.845 8.376 37.573 ;
     RECT  48.96 35.891 49.368 37.573 ;
     RECT  22.848 35.317 22.872 37.861 ;
     RECT  24 37.091 24.312 37.861 ;
     RECT  45.6 35.509 46.008 37.909 ;
     RECT  28.944 36.997 29.712 38.149 ;
     RECT  31.152 37.621 31.176 38.149 ;
     RECT  28.944 38.149 31.176 38.195 ;
     RECT  50.64 35.845 51.312 38.195 ;
     RECT  22.848 37.861 24.312 38.243 ;
     RECT  20.592 36.277 20.616 38.339 ;
     RECT  23.424 38.243 24.312 38.387 ;
     RECT  29.4 38.195 31.176 38.435 ;
     RECT  52.848 38.005 52.872 38.435 ;
     RECT  61.8 37.475 62.112 38.581 ;
     RECT  45.6 37.909 46.104 38.629 ;
     RECT  67.2 36.035 67.512 38.725 ;
     RECT  71.856 35.363 72.912 38.819 ;
     RECT  56.4 36.997 56.808 38.869 ;
     RECT  29.4 38.435 30.264 38.915 ;
     RECT  24 38.387 24.312 39.061 ;
     RECT  25.344 37.091 26.04 39.061 ;
     RECT  56.4 38.869 56.856 39.25 ;
     RECT  64.176 34.499 64.2 39.251 ;
     RECT  72.144 38.819 72.912 39.251 ;
     RECT  61.248 38.581 62.112 39.253 ;
     RECT  38.256 38.725 38.28 39.301 ;
     RECT  45.6 38.629 47.064 39.443 ;
     RECT  61.248 39.253 63.096 39.539 ;
     RECT  56.4 39.25 57 39.587 ;
     RECT  67.008 38.725 67.512 39.587 ;
     RECT  59.808 36.515 59.832 39.827 ;
     RECT  11.088 36.949 11.352 39.829 ;
     RECT  47.04 39.443 47.064 39.877 ;
     RECT  51 38.195 51.312 39.877 ;
     RECT  48.96 37.573 49.56 39.923 ;
     RECT  56.4 39.587 56.808 39.923 ;
     RECT  7.8 37.573 8.52 40.067 ;
     RECT  10.848 39.829 11.352 40.067 ;
     RECT  33.888 33.683 35.112 40.165 ;
     RECT  38.256 39.301 38.76 40.357 ;
     RECT  11.328 40.067 11.352 40.403 ;
     RECT  12.528 31.285 13.512 40.405 ;
     RECT  18.6 33.107 18.912 40.405 ;
     RECT  29.4 38.915 29.712 40.405 ;
     RECT  70.656 39.253 70.68 40.499 ;
     RECT  47.04 39.877 47.544 40.595 ;
     RECT  61.8 39.539 63.096 40.595 ;
     RECT  67.104 39.587 67.512 40.595 ;
     RECT  50.688 39.877 51.312 40.691 ;
     RECT  19.92 39.877 19.944 40.835 ;
     RECT  17.664 40.405 18.912 40.837 ;
     RECT  49.392 39.923 49.56 40.931 ;
     RECT  47.52 40.595 47.544 40.933 ;
     RECT  2.4 32.531 2.712 40.981 ;
     RECT  29.4 40.405 30.264 40.981 ;
     RECT  17.664 40.837 19.416 41.075 ;
     RECT  49.536 40.931 49.56 41.075 ;
     RECT  58.464 35.845 58.488 41.075 ;
     RECT  41.808 40.405 41.832 41.507 ;
     RECT  31.488 41.029 31.512 41.605 ;
     RECT  24 39.061 26.04 41.651 ;
     RECT  68.64 38.197 68.664 41.653 ;
     RECT  51 40.691 51.312 41.749 ;
     RECT  11.904 40.405 13.512 41.939 ;
     RECT  18.6 41.075 19.416 41.939 ;
     RECT  28.608 40.981 30.264 41.939 ;
     RECT  32.784 41.221 32.808 42.037 ;
     RECT  33.888 40.165 35.976 42.037 ;
     RECT  5.856 36.229 5.88 42.133 ;
     RECT  56.4 39.923 56.712 42.133 ;
     RECT  5.76 42.133 5.88 42.179 ;
     RECT  11.904 41.939 11.928 42.179 ;
     RECT  68.64 41.653 69.48 42.275 ;
     RECT  43.44 41.221 43.464 42.323 ;
     RECT  31.344 41.605 31.512 42.467 ;
     RECT  18.6 41.939 18.912 42.709 ;
     RECT  47.52 40.933 48.456 42.709 ;
     RECT  51 41.749 52.104 42.709 ;
     RECT  2.304 40.981 2.712 42.755 ;
     RECT  14.496 41.749 14.52 42.755 ;
     RECT  29.4 41.939 30.264 42.803 ;
     RECT  24 41.651 24.312 42.805 ;
     RECT  25.344 41.651 26.04 42.805 ;
     RECT  16.464 41.077 16.488 42.995 ;
     RECT  5.76 42.179 5.784 43.141 ;
     RECT  67.2 40.595 67.512 43.141 ;
     RECT  68.64 42.275 68.664 43.141 ;
     RECT  5.664 43.141 5.784 43.187 ;
     RECT  50.304 42.709 52.104 43.285 ;
     RECT  67.008 43.141 68.664 43.285 ;
     RECT  24 42.805 26.04 43.379 ;
     RECT  66.912 43.285 68.664 43.379 ;
     RECT  24 43.379 25.128 43.427 ;
     RECT  27.216 42.709 27.24 43.427 ;
     RECT  10.896 41.893 10.92 43.523 ;
     RECT  17.664 42.709 18.912 43.523 ;
     RECT  47.472 42.709 49.224 43.571 ;
     RECT  56.4 42.133 57.096 43.571 ;
     RECT  47.856 43.571 49.224 43.667 ;
     RECT  7.8 40.067 8.112 43.813 ;
     RECT  9.552 43.141 9.576 43.859 ;
     RECT  32.784 42.037 35.976 44.341 ;
     RECT  29.4 42.803 29.712 44.389 ;
     RECT  24 43.427 24.312 44.437 ;
     RECT  45.6 39.443 45.912 44.437 ;
     RECT  59.184 42.469 59.208 44.437 ;
     RECT  5.664 43.187 5.688 44.483 ;
     RECT  14.832 43.861 14.856 44.483 ;
     RECT  31.488 42.467 31.512 44.485 ;
     RECT  7.68 43.813 8.112 44.579 ;
     RECT  54.096 40.837 54.12 44.579 ;
     RECT  29.28 44.389 29.712 44.629 ;
     RECT  30.912 44.485 31.512 44.629 ;
     RECT  23.76 44.437 24.312 44.725 ;
     RECT  32.784 44.341 36.264 44.773 ;
     RECT  26.256 44.341 26.28 44.917 ;
     RECT  48.432 43.667 49.224 44.917 ;
     RECT  21.648 44.437 21.672 44.965 ;
     RECT  23.76 44.725 24.456 44.965 ;
     RECT  13.2 41.939 13.512 45.013 ;
     RECT  18.6 43.523 18.912 45.013 ;
     RECT  20.304 44.965 21.672 45.013 ;
     RECT  22.704 43.909 22.728 45.013 ;
     RECT  23.76 44.965 24.504 45.013 ;
     RECT  25.968 44.917 26.28 45.013 ;
     RECT  29.28 44.629 31.512 45.013 ;
     RECT  32.784 44.773 36.648 45.013 ;
     RECT  37.968 40.357 38.76 45.013 ;
     RECT  40.2 34.259 40.512 45.013 ;
     RECT  45.6 44.437 46.44 45.013 ;
     RECT  48.144 44.917 49.224 45.013 ;
     RECT  50.304 43.285 52.2 45.013 ;
     RECT  56.4 43.571 56.712 45.013 ;
     RECT  58.704 44.437 59.208 45.013 ;
     RECT  66.912 43.379 68.04 45.013 ;
     RECT  56.4 45.013 57.096 45.061 ;
     RECT  58.224 45.013 59.208 45.061 ;
     RECT  9.696 43.861 9.72 45.155 ;
     RECT  13.008 45.013 13.8 45.157 ;
     RECT  18.6 45.013 24.504 45.157 ;
     RECT  18.288 45.157 24.504 45.205 ;
     RECT  25.968 45.013 36.648 45.205 ;
     RECT  11.376 45.013 11.4 45.301 ;
     RECT  13.008 45.157 14.376 45.301 ;
     RECT  66.288 45.013 68.136 45.301 ;
     RECT  2.4 42.755 2.712 45.369 ;
     RECT  7.8 44.579 8.112 45.369 ;
     RECT  37.68 45.013 40.512 45.369 ;
     RECT  61.8 40.595 62.112 45.369 ;
     RECT  72.6 39.251 72.912 45.369 ;
     RECT  78 2.151 78.312 45.369 ;
     RECT  83.4 2.151 83.712 45.369 ;
     RECT  88.8 2.151 89.112 45.369 ;
     RECT  2.4 45.369 2.52 45.383 ;
     RECT  7.8 45.369 7.92 45.383 ;
     RECT  45.6 45.013 52.2 45.383 ;
     RECT  56.4 45.061 59.208 45.383 ;
     RECT  61.8 45.369 61.92 45.383 ;
     RECT  72.6 45.369 72.72 45.383 ;
     RECT  78 45.369 78.12 45.383 ;
     RECT  83.4 45.369 83.52 45.383 ;
     RECT  88.8 45.369 88.92 45.383 ;
     RECT  66.192 45.301 68.232 45.493 ;
     RECT  66.096 45.493 68.232 45.541 ;
     RECT  18.288 45.205 36.648 45.829 ;
     RECT  37.68 45.369 40.488 45.829 ;
     RECT  66 45.541 68.232 46.741 ;
     RECT  11.376 45.301 14.376 47.436 ;
     RECT  11.4 47.436 11.472 47.504 ;
     RECT  11.496 47.436 11.568 47.504 ;
     RECT  11.592 47.436 11.664 47.504 ;
     RECT  11.688 47.436 11.76 47.504 ;
     RECT  11.784 47.436 11.856 47.504 ;
     RECT  11.88 47.436 11.952 47.504 ;
     RECT  11.976 47.436 12.048 47.504 ;
     RECT  12.072 47.436 12.144 47.504 ;
     RECT  12.168 47.436 12.24 47.504 ;
     RECT  12.264 47.436 12.336 47.504 ;
     RECT  12.36 47.436 12.432 47.504 ;
     RECT  12.456 47.436 12.528 47.504 ;
     RECT  12.552 47.436 12.624 47.504 ;
     RECT  12.648 47.436 12.72 47.504 ;
     RECT  12.744 47.436 12.816 47.504 ;
     RECT  12.84 47.436 12.912 47.504 ;
     RECT  12.936 47.436 13.008 47.504 ;
     RECT  13.032 47.436 13.104 47.504 ;
     RECT  13.128 47.436 13.2 47.504 ;
     RECT  13.224 47.436 13.296 47.504 ;
     RECT  13.32 47.436 13.392 47.504 ;
     RECT  13.416 47.436 13.488 47.504 ;
     RECT  13.512 47.436 13.584 47.504 ;
     RECT  13.608 47.436 13.68 47.504 ;
     RECT  13.704 47.436 13.776 47.504 ;
     RECT  13.8 47.436 13.872 47.504 ;
     RECT  13.896 47.436 13.968 47.504 ;
     RECT  13.992 47.436 14.064 47.504 ;
     RECT  14.088 47.436 14.16 47.504 ;
     RECT  14.184 47.436 14.256 47.504 ;
     RECT  14.28 47.436 14.352 47.504 ;
     RECT  18.288 45.829 40.488 47.436 ;
     RECT  18.312 47.436 18.384 47.504 ;
     RECT  18.408 47.436 18.48 47.504 ;
     RECT  18.504 47.436 18.576 47.504 ;
     RECT  18.6 47.436 18.672 47.504 ;
     RECT  18.696 47.436 18.768 47.504 ;
     RECT  18.792 47.436 18.864 47.504 ;
     RECT  18.888 47.436 18.96 47.504 ;
     RECT  18.984 47.436 19.056 47.504 ;
     RECT  19.08 47.436 19.152 47.504 ;
     RECT  19.176 47.436 19.248 47.504 ;
     RECT  19.272 47.436 19.344 47.504 ;
     RECT  19.368 47.436 19.44 47.504 ;
     RECT  19.464 47.436 19.536 47.504 ;
     RECT  19.56 47.436 19.632 47.504 ;
     RECT  19.656 47.436 19.728 47.504 ;
     RECT  19.752 47.436 19.824 47.504 ;
     RECT  19.848 47.436 19.92 47.504 ;
     RECT  19.944 47.436 20.016 47.504 ;
     RECT  20.04 47.436 20.112 47.504 ;
     RECT  20.136 47.436 20.208 47.504 ;
     RECT  20.232 47.436 20.304 47.504 ;
     RECT  20.328 47.436 20.4 47.504 ;
     RECT  20.424 47.436 20.496 47.504 ;
     RECT  20.52 47.436 20.592 47.504 ;
     RECT  20.616 47.436 20.688 47.504 ;
     RECT  20.712 47.436 20.784 47.504 ;
     RECT  20.808 47.436 20.88 47.504 ;
     RECT  20.904 47.436 20.976 47.504 ;
     RECT  21 47.436 21.072 47.504 ;
     RECT  21.096 47.436 21.168 47.504 ;
     RECT  21.192 47.436 21.264 47.504 ;
     RECT  21.288 47.436 21.36 47.504 ;
     RECT  21.384 47.436 21.456 47.504 ;
     RECT  21.48 47.436 21.552 47.504 ;
     RECT  21.576 47.436 21.648 47.504 ;
     RECT  21.672 47.436 21.744 47.504 ;
     RECT  21.768 47.436 21.84 47.504 ;
     RECT  21.864 47.436 21.936 47.504 ;
     RECT  21.96 47.436 22.032 47.504 ;
     RECT  22.056 47.436 22.128 47.504 ;
     RECT  22.152 47.436 22.224 47.504 ;
     RECT  22.248 47.436 22.32 47.504 ;
     RECT  22.344 47.436 22.416 47.504 ;
     RECT  22.44 47.436 22.512 47.504 ;
     RECT  22.536 47.436 22.608 47.504 ;
     RECT  22.632 47.436 22.704 47.504 ;
     RECT  22.728 47.436 22.8 47.504 ;
     RECT  22.824 47.436 22.896 47.504 ;
     RECT  22.92 47.436 22.992 47.504 ;
     RECT  23.016 47.436 23.088 47.504 ;
     RECT  23.112 47.436 23.184 47.504 ;
     RECT  23.208 47.436 23.28 47.504 ;
     RECT  23.304 47.436 23.376 47.504 ;
     RECT  23.4 47.436 23.472 47.504 ;
     RECT  23.496 47.436 23.568 47.504 ;
     RECT  23.592 47.436 23.664 47.504 ;
     RECT  23.688 47.436 23.76 47.504 ;
     RECT  23.784 47.436 23.856 47.504 ;
     RECT  23.88 47.436 23.952 47.504 ;
     RECT  23.976 47.436 24.048 47.504 ;
     RECT  24.072 47.436 24.144 47.504 ;
     RECT  24.168 47.436 24.24 47.504 ;
     RECT  24.264 47.436 24.336 47.504 ;
     RECT  24.36 47.436 24.432 47.504 ;
     RECT  24.456 47.436 24.528 47.504 ;
     RECT  24.552 47.436 24.624 47.504 ;
     RECT  24.648 47.436 24.72 47.504 ;
     RECT  24.744 47.436 24.816 47.504 ;
     RECT  24.84 47.436 24.912 47.504 ;
     RECT  24.936 47.436 25.008 47.504 ;
     RECT  25.032 47.436 25.104 47.504 ;
     RECT  25.128 47.436 25.2 47.504 ;
     RECT  25.224 47.436 25.296 47.504 ;
     RECT  25.32 47.436 25.392 47.504 ;
     RECT  25.416 47.436 25.488 47.504 ;
     RECT  25.512 47.436 25.584 47.504 ;
     RECT  25.608 47.436 25.68 47.504 ;
     RECT  25.704 47.436 25.776 47.504 ;
     RECT  25.8 47.436 25.872 47.504 ;
     RECT  25.896 47.436 25.968 47.504 ;
     RECT  25.992 47.436 26.064 47.504 ;
     RECT  26.088 47.436 26.16 47.504 ;
     RECT  26.184 47.436 26.256 47.504 ;
     RECT  26.28 47.436 26.352 47.504 ;
     RECT  26.376 47.436 26.448 47.504 ;
     RECT  26.472 47.436 26.544 47.504 ;
     RECT  26.568 47.436 26.64 47.504 ;
     RECT  26.664 47.436 26.736 47.504 ;
     RECT  26.76 47.436 26.832 47.504 ;
     RECT  26.856 47.436 26.928 47.504 ;
     RECT  26.952 47.436 27.024 47.504 ;
     RECT  27.048 47.436 27.12 47.504 ;
     RECT  27.144 47.436 27.216 47.504 ;
     RECT  27.24 47.436 27.312 47.504 ;
     RECT  27.336 47.436 27.408 47.504 ;
     RECT  27.432 47.436 27.504 47.504 ;
     RECT  27.528 47.436 27.6 47.504 ;
     RECT  27.624 47.436 27.696 47.504 ;
     RECT  27.72 47.436 27.792 47.504 ;
     RECT  27.816 47.436 27.888 47.504 ;
     RECT  27.912 47.436 27.984 47.504 ;
     RECT  28.008 47.436 28.08 47.504 ;
     RECT  28.104 47.436 28.176 47.504 ;
     RECT  28.2 47.436 28.272 47.504 ;
     RECT  28.296 47.436 28.368 47.504 ;
     RECT  28.392 47.436 28.464 47.504 ;
     RECT  28.488 47.436 28.56 47.504 ;
     RECT  28.584 47.436 28.656 47.504 ;
     RECT  28.68 47.436 28.752 47.504 ;
     RECT  28.776 47.436 28.848 47.504 ;
     RECT  28.872 47.436 28.944 47.504 ;
     RECT  28.968 47.436 29.04 47.504 ;
     RECT  29.064 47.436 29.136 47.504 ;
     RECT  29.16 47.436 29.232 47.504 ;
     RECT  29.256 47.436 29.328 47.504 ;
     RECT  29.352 47.436 29.424 47.504 ;
     RECT  29.448 47.436 29.52 47.504 ;
     RECT  29.544 47.436 29.616 47.504 ;
     RECT  29.64 47.436 29.712 47.504 ;
     RECT  29.736 47.436 29.808 47.504 ;
     RECT  29.832 47.436 29.904 47.504 ;
     RECT  29.928 47.436 30 47.504 ;
     RECT  30.024 47.436 30.096 47.504 ;
     RECT  30.12 47.436 30.192 47.504 ;
     RECT  30.216 47.436 30.288 47.504 ;
     RECT  30.312 47.436 30.384 47.504 ;
     RECT  30.408 47.436 30.48 47.504 ;
     RECT  30.504 47.436 30.576 47.504 ;
     RECT  30.6 47.436 30.672 47.504 ;
     RECT  30.696 47.436 30.768 47.504 ;
     RECT  30.792 47.436 30.864 47.504 ;
     RECT  30.888 47.436 30.96 47.504 ;
     RECT  30.984 47.436 31.056 47.504 ;
     RECT  31.08 47.436 31.152 47.504 ;
     RECT  31.176 47.436 31.248 47.504 ;
     RECT  31.272 47.436 31.344 47.504 ;
     RECT  31.368 47.436 31.44 47.504 ;
     RECT  31.464 47.436 31.536 47.504 ;
     RECT  31.56 47.436 31.632 47.504 ;
     RECT  31.656 47.436 31.728 47.504 ;
     RECT  31.752 47.436 31.824 47.504 ;
     RECT  31.848 47.436 31.92 47.504 ;
     RECT  31.944 47.436 32.016 47.504 ;
     RECT  32.04 47.436 32.112 47.504 ;
     RECT  32.136 47.436 32.208 47.504 ;
     RECT  32.232 47.436 32.304 47.504 ;
     RECT  32.328 47.436 32.4 47.504 ;
     RECT  32.424 47.436 32.496 47.504 ;
     RECT  32.52 47.436 32.592 47.504 ;
     RECT  32.616 47.436 32.688 47.504 ;
     RECT  32.712 47.436 32.784 47.504 ;
     RECT  32.808 47.436 32.88 47.504 ;
     RECT  32.904 47.436 32.976 47.504 ;
     RECT  33 47.436 33.072 47.504 ;
     RECT  33.096 47.436 33.168 47.504 ;
     RECT  33.192 47.436 33.264 47.504 ;
     RECT  33.288 47.436 33.36 47.504 ;
     RECT  33.384 47.436 33.456 47.504 ;
     RECT  33.48 47.436 33.552 47.504 ;
     RECT  33.576 47.436 33.648 47.504 ;
     RECT  33.672 47.436 33.744 47.504 ;
     RECT  33.768 47.436 33.84 47.504 ;
     RECT  33.864 47.436 33.936 47.504 ;
     RECT  33.96 47.436 34.032 47.504 ;
     RECT  34.056 47.436 34.128 47.504 ;
     RECT  34.152 47.436 34.224 47.504 ;
     RECT  34.248 47.436 34.32 47.504 ;
     RECT  34.344 47.436 34.416 47.504 ;
     RECT  34.44 47.436 34.512 47.504 ;
     RECT  34.536 47.436 34.608 47.504 ;
     RECT  34.632 47.436 34.704 47.504 ;
     RECT  34.728 47.436 34.8 47.504 ;
     RECT  34.824 47.436 34.896 47.504 ;
     RECT  34.92 47.436 34.992 47.504 ;
     RECT  35.016 47.436 35.088 47.504 ;
     RECT  35.112 47.436 35.184 47.504 ;
     RECT  35.208 47.436 35.28 47.504 ;
     RECT  35.304 47.436 35.376 47.504 ;
     RECT  35.4 47.436 35.472 47.504 ;
     RECT  35.496 47.436 35.568 47.504 ;
     RECT  35.592 47.436 35.664 47.504 ;
     RECT  35.688 47.436 35.76 47.504 ;
     RECT  35.784 47.436 35.856 47.504 ;
     RECT  35.88 47.436 35.952 47.504 ;
     RECT  35.976 47.436 36.048 47.504 ;
     RECT  36.072 47.436 36.144 47.504 ;
     RECT  36.168 47.436 36.24 47.504 ;
     RECT  36.264 47.436 36.336 47.504 ;
     RECT  36.36 47.436 36.432 47.504 ;
     RECT  36.456 47.436 36.528 47.504 ;
     RECT  36.552 47.436 36.624 47.504 ;
     RECT  36.648 47.436 37.488 47.504 ;
     RECT  37.512 47.436 37.584 47.504 ;
     RECT  37.608 47.436 37.68 47.504 ;
     RECT  37.704 47.436 37.776 47.504 ;
     RECT  37.8 47.436 37.872 47.504 ;
     RECT  37.896 47.436 37.968 47.504 ;
     RECT  37.992 47.436 38.064 47.504 ;
     RECT  38.088 47.436 38.16 47.504 ;
     RECT  38.184 47.436 38.256 47.504 ;
     RECT  38.28 47.436 38.352 47.504 ;
     RECT  38.376 47.436 38.448 47.504 ;
     RECT  38.472 47.436 38.544 47.504 ;
     RECT  38.568 47.436 38.64 47.504 ;
     RECT  38.664 47.436 38.736 47.504 ;
     RECT  38.76 47.436 38.832 47.504 ;
     RECT  38.856 47.436 38.928 47.504 ;
     RECT  38.952 47.436 39.024 47.504 ;
     RECT  39.048 47.436 39.12 47.504 ;
     RECT  39.144 47.436 39.216 47.504 ;
     RECT  39.24 47.436 39.312 47.504 ;
     RECT  39.336 47.436 39.408 47.504 ;
     RECT  39.432 47.436 39.504 47.504 ;
     RECT  39.528 47.436 39.6 47.504 ;
     RECT  39.624 47.436 39.696 47.504 ;
     RECT  39.72 47.436 39.792 47.504 ;
     RECT  39.816 47.436 39.888 47.504 ;
     RECT  39.912 47.436 39.984 47.504 ;
     RECT  40.008 47.436 40.08 47.504 ;
     RECT  40.104 47.436 40.176 47.504 ;
     RECT  40.2 47.436 40.272 47.504 ;
     RECT  40.296 47.436 40.368 47.504 ;
     RECT  40.392 47.436 40.464 47.504 ;
     RECT  45.744 45.383 52.2 47.436 ;
     RECT  45.768 47.436 45.84 47.504 ;
     RECT  45.864 47.436 45.936 47.504 ;
     RECT  45.96 47.436 46.032 47.504 ;
     RECT  46.056 47.436 46.128 47.504 ;
     RECT  46.152 47.436 46.224 47.504 ;
     RECT  46.248 47.436 46.32 47.504 ;
     RECT  46.344 47.436 46.416 47.504 ;
     RECT  46.44 47.436 46.512 47.504 ;
     RECT  46.536 47.436 46.608 47.504 ;
     RECT  46.632 47.436 46.704 47.504 ;
     RECT  46.728 47.436 46.8 47.504 ;
     RECT  46.824 47.436 46.896 47.504 ;
     RECT  46.92 47.436 46.992 47.504 ;
     RECT  47.016 47.436 47.088 47.504 ;
     RECT  47.112 47.436 47.184 47.504 ;
     RECT  47.208 47.436 47.28 47.504 ;
     RECT  47.304 47.436 47.376 47.504 ;
     RECT  47.4 47.436 47.472 47.504 ;
     RECT  47.496 47.436 47.568 47.504 ;
     RECT  47.592 47.436 47.664 47.504 ;
     RECT  47.688 47.436 47.76 47.504 ;
     RECT  47.784 47.436 47.856 47.504 ;
     RECT  47.88 47.436 47.952 47.504 ;
     RECT  47.976 47.436 48.048 47.504 ;
     RECT  48.072 47.436 48.144 47.504 ;
     RECT  48.168 47.436 48.24 47.504 ;
     RECT  48.264 47.436 48.336 47.504 ;
     RECT  48.36 47.436 48.432 47.504 ;
     RECT  48.456 47.436 48.528 47.504 ;
     RECT  48.552 47.436 48.624 47.504 ;
     RECT  48.648 47.436 48.72 47.504 ;
     RECT  48.744 47.436 48.816 47.504 ;
     RECT  48.84 47.436 48.912 47.504 ;
     RECT  48.936 47.436 49.008 47.504 ;
     RECT  49.032 47.436 49.104 47.504 ;
     RECT  49.128 47.436 49.2 47.504 ;
     RECT  49.224 47.436 49.296 47.504 ;
     RECT  49.32 47.436 49.392 47.504 ;
     RECT  49.416 47.436 49.488 47.504 ;
     RECT  49.512 47.436 49.584 47.504 ;
     RECT  49.608 47.436 49.68 47.504 ;
     RECT  49.704 47.436 49.776 47.504 ;
     RECT  49.8 47.436 49.872 47.504 ;
     RECT  49.896 47.436 49.968 47.504 ;
     RECT  49.992 47.436 50.064 47.504 ;
     RECT  50.088 47.436 50.16 47.504 ;
     RECT  50.184 47.436 50.256 47.504 ;
     RECT  50.28 47.436 50.352 47.504 ;
     RECT  50.376 47.436 50.448 47.504 ;
     RECT  50.472 47.436 50.544 47.504 ;
     RECT  50.568 47.436 50.64 47.504 ;
     RECT  50.664 47.436 50.736 47.504 ;
     RECT  50.76 47.436 50.832 47.504 ;
     RECT  50.856 47.436 50.928 47.504 ;
     RECT  50.952 47.436 51.024 47.504 ;
     RECT  51.048 47.436 51.12 47.504 ;
     RECT  51.144 47.436 51.216 47.504 ;
     RECT  51.24 47.436 51.312 47.504 ;
     RECT  51.336 47.436 51.408 47.504 ;
     RECT  51.432 47.436 51.504 47.504 ;
     RECT  51.528 47.436 51.6 47.504 ;
     RECT  51.624 47.436 51.696 47.504 ;
     RECT  51.72 47.436 51.792 47.504 ;
     RECT  51.816 47.436 51.888 47.504 ;
     RECT  51.912 47.436 51.984 47.504 ;
     RECT  52.008 47.436 52.08 47.504 ;
     RECT  52.104 47.436 52.176 47.504 ;
     RECT  56.88 45.383 59.208 47.436 ;
     RECT  56.904 47.436 56.976 47.504 ;
     RECT  57 47.436 57.072 47.504 ;
     RECT  57.096 47.436 57.168 47.504 ;
     RECT  57.192 47.436 57.264 47.504 ;
     RECT  57.288 47.436 57.36 47.504 ;
     RECT  57.384 47.436 57.456 47.504 ;
     RECT  57.48 47.436 57.552 47.504 ;
     RECT  57.576 47.436 57.648 47.504 ;
     RECT  57.672 47.436 57.744 47.504 ;
     RECT  57.768 47.436 57.84 47.504 ;
     RECT  57.864 47.436 57.936 47.504 ;
     RECT  57.96 47.436 58.032 47.504 ;
     RECT  58.056 47.436 58.128 47.504 ;
     RECT  58.152 47.436 58.224 47.504 ;
     RECT  58.248 47.436 58.32 47.504 ;
     RECT  58.344 47.436 58.416 47.504 ;
     RECT  58.44 47.436 58.512 47.504 ;
     RECT  58.536 47.436 58.608 47.504 ;
     RECT  58.632 47.436 58.704 47.504 ;
     RECT  58.728 47.436 58.8 47.504 ;
     RECT  58.824 47.436 58.896 47.504 ;
     RECT  58.92 47.436 58.992 47.504 ;
     RECT  59.016 47.436 59.088 47.504 ;
     RECT  59.112 47.436 59.184 47.504 ;
     RECT  65.904 46.741 68.232 47.436 ;
     RECT  65.928 47.436 66 47.504 ;
     RECT  66.024 47.436 66.096 47.504 ;
     RECT  66.12 47.436 66.192 47.504 ;
     RECT  66.216 47.436 66.288 47.504 ;
     RECT  66.312 47.436 66.384 47.504 ;
     RECT  66.408 47.436 66.48 47.504 ;
     RECT  66.504 47.436 66.576 47.504 ;
     RECT  66.6 47.436 66.672 47.504 ;
     RECT  66.696 47.436 66.768 47.504 ;
     RECT  66.792 47.436 66.864 47.504 ;
     RECT  66.888 47.436 66.96 47.504 ;
     RECT  66.984 47.436 67.056 47.504 ;
     RECT  67.08 47.436 67.152 47.504 ;
     RECT  67.176 47.436 67.248 47.504 ;
     RECT  67.272 47.436 67.344 47.504 ;
     RECT  67.368 47.436 67.44 47.504 ;
     RECT  67.464 47.436 67.536 47.504 ;
     RECT  67.56 47.436 67.632 47.504 ;
     RECT  67.656 47.436 67.728 47.504 ;
     RECT  67.752 47.436 67.824 47.504 ;
     RECT  67.848 47.436 67.92 47.504 ;
     RECT  67.944 47.436 68.016 47.504 ;
     RECT  68.04 47.436 68.112 47.504 ;
     RECT  68.136 47.436 68.208 47.504 ;
     RECT  31.56 1.763 32.688 1.811 ;
     RECT  43.368 1.763 44.88 1.811 ;
     RECT  51.312 1.763 52.704 13.909 ;
     RECT  55.176 1.763 56.4 1.811 ;
     RECT  68.616 1.763 69.84 1.811 ;
     RECT  81 1.763 82.032 1.811 ;
     RECT  39.144 1.811 40.2 2.915 ;
     RECT  44.64 1.811 45.312 2.773 ;
     RECT  37.608 1.859 39.12 2.291 ;
     RECT  46.728 1.955 47.76 2.003 ;
     RECT  46.728 2.003 47.856 2.243 ;
     RECT  46.584 2.243 47.856 3.443 ;
     RECT  35.112 3.301 36.432 4.019 ;
     RECT  35.112 4.019 36.024 5.365 ;
     RECT  71.256 5.029 72.6 5.747 ;
     RECT  69.528 6.229 70.992 6.709 ;
     RECT  69.528 6.709 70.896 11.221 ;
     RECT  54.504 6.949 55.536 7.189 ;
     RECT  68.472 7.189 69.504 15.157 ;
     RECT  45.912 7.619 46.992 9.781 ;
     RECT  67.104 7.667 67.2 8.005 ;
     RECT  47.016 7.861 48.192 7.909 ;
     RECT  50.832 7.907 51 9.013 ;
     RECT  66.024 8.005 67.2 8.963 ;
     RECT  62.808 8.197 63.84 9.587 ;
     RECT  66 8.963 67.2 8.965 ;
     RECT  65.736 8.965 67.2 11.317 ;
     RECT  52.728 9.061 54.24 9.347 ;
     RECT  59.256 9.205 60.24 9.397 ;
     RECT  60.264 9.205 61.584 9.779 ;
     RECT  52.728 9.347 54.288 10.261 ;
     RECT  63.864 9.541 64.992 9.587 ;
     RECT  62.808 9.587 64.992 10.453 ;
     RECT  47.016 9.731 48.192 9.779 ;
     RECT  59.784 9.779 61.584 10.693 ;
     RECT  8.112 9.781 9.6 10.501 ;
     RECT  71.4 10.165 72.6 11.221 ;
     RECT  53.064 10.261 54.288 10.979 ;
     RECT  63.672 10.453 64.992 11.461 ;
     RECT  8.616 10.501 9.6 11.411 ;
     RECT  2.712 10.597 3.936 11.027 ;
     RECT  59.784 10.693 61.008 11.171 ;
     RECT  55.176 10.883 56.4 14.533 ;
     RECT  52.728 10.979 54.288 11.029 ;
     RECT  52.728 11.029 53.904 12.565 ;
     RECT  59.784 11.171 61.536 11.701 ;
     RECT  69.528 11.221 70.656 11.941 ;
     RECT  65.928 11.317 67.2 11.749 ;
     RECT  8.112 11.411 9.6 11.459 ;
     RECT  60.216 11.701 61.536 12.517 ;
     RECT  24.312 12.373 25.68 14.627 ;
     RECT  35.112 12.515 36.144 17.123 ;
     RECT  13.512 12.517 14.784 13.043 ;
     RECT  60.216 12.517 61.344 12.805 ;
     RECT  52.728 12.851 53.904 14.149 ;
     RECT  13.512 13.043 13.608 13.045 ;
     RECT  47.928 13.045 49.2 13.621 ;
     RECT  47.928 13.621 49.104 14.773 ;
     RECT  46.488 13.811 47.856 14.869 ;
     RECT  51.528 13.909 52.704 15.251 ;
     RECT  24.312 14.627 25.704 14.773 ;
     RECT  55.176 14.675 56.304 15.685 ;
     RECT  24.312 14.773 25.728 16.019 ;
     RECT  47.976 14.773 49.104 15.925 ;
     RECT  46.728 14.869 47.856 15.253 ;
     RECT  67.896 15.203 68.928 16.019 ;
     RECT  51.48 15.251 52.704 17.077 ;
     RECT  52.728 15.539 53.856 17.077 ;
     RECT  55.176 15.685 56.256 16.693 ;
     RECT  45.912 16.019 47.376 18.133 ;
     RECT  67.896 16.019 69.024 16.211 ;
     RECT  67.8 16.211 69.024 16.451 ;
     RECT  67.752 16.451 69.024 17.605 ;
     RECT  44.472 17.077 45.6 18.179 ;
     RECT  51.48 17.077 52.656 17.363 ;
     RECT  52.824 17.077 53.856 18.373 ;
     RECT  51.48 17.363 52.704 18.133 ;
     RECT  51.528 18.133 52.704 19.909 ;
     RECT  17.496 19.093 18.6 20.003 ;
     RECT  67.704 19.331 68.736 20.003 ;
     RECT  51.576 19.909 52.704 21.395 ;
     RECT  67.608 20.003 68.736 21.109 ;
     RECT  45.912 20.099 47.28 22.259 ;
     RECT  31.272 20.293 32.688 20.339 ;
     RECT  67.704 21.109 68.736 21.541 ;
     RECT  28.248 21.253 29.4 22.739 ;
     RECT  51.312 21.395 52.704 23.269 ;
     RECT  45.912 22.259 47.376 24.469 ;
     RECT  57.528 22.259 58.608 22.307 ;
     RECT  57.48 22.307 58.608 23.509 ;
     RECT  51.432 23.269 52.704 23.747 ;
     RECT  65.256 23.507 66.576 24.755 ;
     RECT  57.528 23.509 58.608 24.469 ;
     RECT  51.312 23.747 52.704 26.965 ;
     RECT  18.912 23.845 20.4 26.677 ;
     RECT  20.424 23.845 21.888 24.517 ;
     RECT  16.56 23.939 16.584 23.941 ;
     RECT  16.56 23.941 16.608 24.997 ;
     RECT  17.16 24.085 18.6 24.995 ;
     RECT  63.192 24.227 64.176 24.947 ;
     RECT  29.712 24.229 30.816 25.139 ;
     RECT  46.152 24.469 47.376 25.139 ;
     RECT  57.624 24.469 58.608 24.611 ;
     RECT  20.424 24.517 21.552 26.003 ;
     RECT  57.624 24.611 58.656 25.715 ;
     RECT  65.064 24.755 66.576 25.283 ;
     RECT  63.144 24.947 64.176 26.389 ;
     RECT  33.576 25.237 34.8 26.003 ;
     RECT  65.016 25.283 66.576 25.715 ;
     RECT  57.624 25.715 58.752 27.875 ;
     RECT  64.776 25.715 66.576 25.765 ;
     RECT  64.776 25.765 66.192 26.197 ;
     RECT  20.424 26.003 21.888 26.771 ;
     RECT  64.776 26.197 66.144 26.917 ;
     RECT  38.808 26.485 40.2 28.163 ;
     RECT  19.368 26.677 20.4 26.771 ;
     RECT  65.064 26.917 66.144 27.779 ;
     RECT  51.672 26.965 52.704 27.301 ;
     RECT  73.704 27.251 74.736 28.547 ;
     RECT  18.912 27.395 19.32 28.549 ;
     RECT  49.368 27.395 50.352 28.499 ;
     RECT  68.664 27.395 69.984 28.355 ;
     RECT  64.968 27.779 66.144 27.971 ;
     RECT  57.624 27.875 58.8 29.173 ;
     RECT  64.968 27.971 66.288 28.499 ;
     RECT  52.008 28.259 53.04 29.027 ;
     RECT  68.664 28.355 70.032 29.075 ;
     RECT  49.368 28.499 50.496 30.323 ;
     RECT  64.92 28.499 66.288 30.131 ;
     RECT  70.296 28.547 71.472 32.531 ;
     RECT  21.672 28.691 22.104 29.941 ;
     RECT  13.512 28.931 13.608 30.181 ;
     RECT  52.008 29.027 53.52 30.419 ;
     RECT  68.664 29.075 70.128 29.941 ;
     RECT  57.72 29.173 58.8 29.603 ;
     RECT  57.576 29.603 58.8 31.811 ;
     RECT  53.736 29.699 54.768 34.259 ;
     RECT  21.672 29.941 22.8 29.987 ;
     RECT  22.824 29.941 24 31.235 ;
     RECT  68.712 29.941 70.128 30.275 ;
     RECT  13.056 30.131 13.2 30.949 ;
     RECT  64.92 30.131 66.384 32.965 ;
     RECT  13.512 30.181 14.784 30.803 ;
     RECT  68.712 30.275 70.272 31.285 ;
     RECT  49.368 30.323 50.544 32.773 ;
     RECT  28.248 30.709 29.4 31.379 ;
     RECT  73.608 30.899 73.656 31.909 ;
     RECT  12.024 30.949 13.2 31.091 ;
     RECT  3.432 30.995 3.624 32.485 ;
     RECT  12.528 31.091 13.2 31.285 ;
     RECT  68.952 31.285 70.272 32.531 ;
     RECT  57.576 31.811 58.848 31.907 ;
     RECT  46.536 31.861 47.568 32.819 ;
     RECT  47.592 31.861 48.768 32.291 ;
     RECT  71.592 32.195 72.6 35.125 ;
     RECT  47.592 32.291 48.816 33.011 ;
     RECT  3.432 32.485 4.416 32.531 ;
     RECT  4.44 32.485 5.808 33.827 ;
     RECT  39.888 32.531 40.2 33.541 ;
     RECT  68.952 32.531 71.568 33.109 ;
     RECT  49.56 32.773 50.544 32.867 ;
     RECT  49.56 32.867 50.832 33.587 ;
     RECT  64.92 32.965 66.336 33.587 ;
     RECT  47.592 33.011 48.912 35.891 ;
     RECT  68.952 33.109 70.128 33.299 ;
     RECT  70.152 33.109 71.568 34.693 ;
     RECT  49.56 33.587 51 33.683 ;
     RECT  53.736 34.259 55.152 35.363 ;
     RECT  60.792 34.259 61.8 35.219 ;
     RECT  64.2 34.499 64.92 35.317 ;
     RECT  70.152 34.693 71.472 34.835 ;
     RECT  67.104 34.787 67.2 35.317 ;
     RECT  17.304 35.317 18.6 36.275 ;
     RECT  22.872 35.317 24 37.861 ;
     RECT  64.2 35.317 65.712 35.987 ;
     RECT  65.736 35.317 67.2 35.987 ;
     RECT  29.712 35.509 30.864 36.515 ;
     RECT  11.352 35.845 12.528 40.403 ;
     RECT  49.368 35.845 50.64 37.573 ;
     RECT  58.488 35.845 59.568 36.515 ;
     RECT  47.592 35.891 48.96 35.939 ;
     RECT  29.712 36.515 30.888 37.621 ;
     RECT  58.488 36.515 59.808 39.827 ;
     RECT  24.312 37.091 25.344 39.061 ;
     RECT  61.536 37.475 61.8 38.581 ;
     RECT  49.56 37.573 50.64 38.195 ;
     RECT  29.712 37.621 31.152 38.149 ;
     RECT  49.56 38.195 51 39.877 ;
     RECT  67.512 38.197 68.64 43.141 ;
     RECT  59.832 38.581 61.248 39.539 ;
     RECT  29.712 38.915 30.264 40.405 ;
     RECT  57 39.25 58.464 39.587 ;
     RECT  38.76 39.301 40.2 45.013 ;
     RECT  45.912 39.443 47.04 40.595 ;
     RECT  18.912 39.877 19.92 40.835 ;
     RECT  47.544 39.877 48.96 39.923 ;
     RECT  49.56 39.877 50.688 40.691 ;
     RECT  47.544 39.923 49.392 40.931 ;
     RECT  11.328 40.403 12.528 40.405 ;
     RECT  11.328 40.405 11.904 41.893 ;
     RECT  40.512 40.405 41.808 41.507 ;
     RECT  49.56 40.691 51 41.075 ;
     RECT  18.912 40.835 19.416 40.837 ;
     RECT  47.544 40.931 49.536 40.933 ;
     RECT  48.456 40.933 49.536 41.075 ;
     RECT  30.264 41.029 31.488 41.605 ;
     RECT  31.512 41.221 32.784 45.013 ;
     RECT  32.808 41.221 33.888 42.037 ;
     RECT  30.264 41.605 31.344 42.467 ;
     RECT  24.312 41.651 25.344 42.805 ;
     RECT  13.512 41.749 14.496 42.755 ;
     RECT  10.92 41.893 11.904 42.179 ;
     RECT  11.928 41.939 13.2 42.179 ;
     RECT  30.264 42.467 31.488 42.803 ;
     RECT  16.488 42.709 17.664 42.995 ;
     RECT  26.04 42.709 27.216 43.379 ;
     RECT  49.224 42.709 50.304 45.013 ;
     RECT  13.512 42.755 14.52 43.861 ;
     RECT  8.112 43.141 9.552 43.859 ;
     RECT  9.576 43.141 10.896 43.523 ;
     RECT  25.128 43.379 27.216 43.427 ;
     RECT  24.312 43.427 26.28 44.341 ;
     RECT  9.576 43.523 9.72 43.859 ;
     RECT  47.472 43.571 47.856 43.667 ;
     RECT  56.712 43.571 57.096 45.013 ;
     RECT  47.472 43.667 48.432 44.437 ;
     RECT  9.696 43.859 9.72 43.861 ;
     RECT  13.512 43.861 14.832 44.483 ;
     RECT  22.728 43.909 24 44.437 ;
     RECT  24.312 44.341 26.256 44.725 ;
     RECT  21.672 44.437 22.704 45.013 ;
     RECT  22.728 44.437 23.76 45.013 ;
     RECT  46.44 44.437 48.432 44.917 ;
     RECT  13.512 44.483 14.376 45.013 ;
     RECT  29.712 44.485 30.912 44.629 ;
     RECT  24.456 44.725 26.256 44.917 ;
     RECT  36.648 44.773 37.968 45.013 ;
     RECT  24.456 44.917 25.968 44.965 ;
     RECT  46.44 44.917 48.144 45.013 ;
     RECT  18.912 44.965 20.304 45.013 ;
     RECT  24.504 44.965 25.968 45.205 ;
     RECT  13.8 45.013 14.376 45.157 ;
     RECT  36.648 45.013 37.68 45.829 ;
     RECT  57.096 45.013 58.224 45.061 ;
  END
END ot_hgi_coll_argmax_m_tp192
END LIBRARY
